VERSION 5.8 ;
BUSBITCHARS "[]" ;
DIVIDERCHAR "/" ;
UNITS
    DATABASE MICRONS 1000 ;
END UNITS

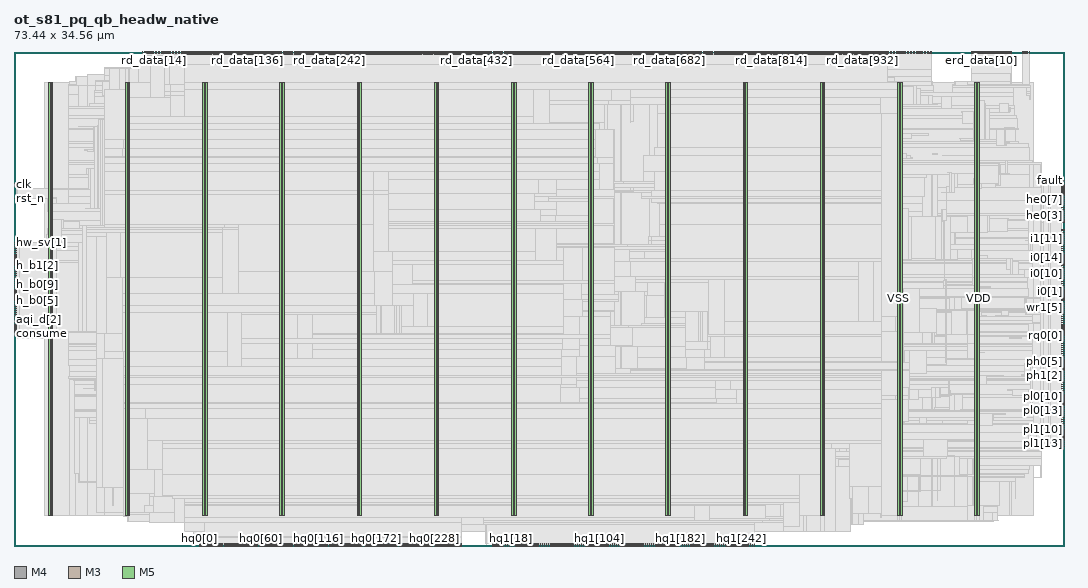
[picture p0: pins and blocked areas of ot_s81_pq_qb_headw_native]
MACRO ot_s81_pq_qb_headw_native
  FOREIGN ot_s81_pq_qb_headw_native 0 0 ;
  CLASS BLOCK ;
  SIZE 73.44 BY 34.56 ;
  PIN aqi_d[0]
    DIRECTION INPUT ;
    USE SIGNAL ;
    PORT
      LAYER M4 ;
        RECT  0 15.024 0.192 15.048 ;
    END
  END aqi_d[0]
  PIN aqi_d[1]
    DIRECTION INPUT ;
    USE SIGNAL ;
    PORT
      LAYER M4 ;
        RECT  0 15.168 0.192 15.192 ;
    END
  END aqi_d[1]
  PIN aqi_d[2]
    DIRECTION INPUT ;
    USE SIGNAL ;
    PORT
      LAYER M4 ;
        RECT  0 15.312 0.192 15.336 ;
    END
  END aqi_d[2]
  PIN aqi_d[3]
    DIRECTION INPUT ;
    USE SIGNAL ;
    PORT
      LAYER M4 ;
        RECT  0 15.456 0.192 15.48 ;
    END
  END aqi_d[3]
  PIN aqi_d[4]
    DIRECTION INPUT ;
    USE SIGNAL ;
    PORT
      LAYER M4 ;
        RECT  0 15.6 0.192 15.624 ;
    END
  END aqi_d[4]
  PIN aqi_d[5]
    DIRECTION INPUT ;
    USE SIGNAL ;
    PORT
      LAYER M4 ;
        RECT  0 15.744 0.192 15.768 ;
    END
  END aqi_d[5]
  PIN aqi_d[6]
    DIRECTION INPUT ;
    USE SIGNAL ;
    PORT
      LAYER M4 ;
        RECT  0 15.888 0.192 15.912 ;
    END
  END aqi_d[6]
  PIN aqi_d[7]
    DIRECTION INPUT ;
    USE SIGNAL ;
    PORT
      LAYER M4 ;
        RECT  0 16.032 0.192 16.056 ;
    END
  END aqi_d[7]
  PIN aqi_d[8]
    DIRECTION INPUT ;
    USE SIGNAL ;
    PORT
      LAYER M4 ;
        RECT  0 16.176 0.192 16.2 ;
    END
  END aqi_d[8]
  PIN aqi_d[9]
    DIRECTION INPUT ;
    USE SIGNAL ;
    PORT
      LAYER M4 ;
        RECT  0 16.32 0.192 16.344 ;
    END
  END aqi_d[9]
  PIN bfault[0]
    DIRECTION INPUT ;
    USE SIGNAL ;
    PORT
      LAYER M3 ;
        RECT  70.56 34.416 70.578 34.56 ;
    END
  END bfault[0]
  PIN bfault[1]
    DIRECTION INPUT ;
    USE SIGNAL ;
    PORT
      LAYER M3 ;
        RECT  70.704 34.416 70.722 34.56 ;
    END
  END bfault[1]
  PIN bfault[2]
    DIRECTION INPUT ;
    USE SIGNAL ;
    PORT
      LAYER M3 ;
        RECT  70.848 34.416 70.866 34.56 ;
    END
  END bfault[2]
  PIN bfault[3]
    DIRECTION INPUT ;
    USE SIGNAL ;
    PORT
      LAYER M3 ;
        RECT  70.992 34.416 71.01 34.56 ;
    END
  END bfault[3]
  PIN clk
    DIRECTION INPUT ;
    USE SIGNAL ;
    PORT
      LAYER M4 ;
        RECT  0 25.296 0.192 25.32 ;
    END
    PORT
      LAYER M4 ;
        RECT  0.156 25.296 0.181 25.32 ;
    END
  END clk
  PIN consume
    DIRECTION INPUT ;
    USE SIGNAL ;
    PORT
      LAYER M4 ;
        RECT  0 14.88 0.192 14.904 ;
    END
  END consume
  PIN erd_data[0]
    DIRECTION INPUT ;
    USE SIGNAL ;
    PORT
      LAYER M3 ;
        RECT  66.96 34.416 66.978 34.56 ;
    END
  END erd_data[0]
  PIN erd_data[10]
    DIRECTION INPUT ;
    USE SIGNAL ;
    PORT
      LAYER M3 ;
        RECT  67.68 34.416 67.698 34.56 ;
    END
  END erd_data[10]
  PIN erd_data[11]
    DIRECTION INPUT ;
    USE SIGNAL ;
    PORT
      LAYER M3 ;
        RECT  67.752 34.416 67.77 34.56 ;
    END
  END erd_data[11]
  PIN erd_data[12]
    DIRECTION INPUT ;
    USE SIGNAL ;
    PORT
      LAYER M3 ;
        RECT  67.824 34.416 67.842 34.56 ;
    END
  END erd_data[12]
  PIN erd_data[13]
    DIRECTION INPUT ;
    USE SIGNAL ;
    PORT
      LAYER M3 ;
        RECT  67.896 34.416 67.914 34.56 ;
    END
  END erd_data[13]
  PIN erd_data[14]
    DIRECTION INPUT ;
    USE SIGNAL ;
    PORT
      LAYER M3 ;
        RECT  67.968 34.416 67.986 34.56 ;
    END
  END erd_data[14]
  PIN erd_data[15]
    DIRECTION INPUT ;
    USE SIGNAL ;
    PORT
      LAYER M3 ;
        RECT  68.04 34.416 68.058 34.56 ;
    END
  END erd_data[15]
  PIN erd_data[16]
    DIRECTION INPUT ;
    USE SIGNAL ;
    PORT
      LAYER M3 ;
        RECT  68.112 34.416 68.13 34.56 ;
    END
  END erd_data[16]
  PIN erd_data[17]
    DIRECTION INPUT ;
    USE SIGNAL ;
    PORT
      LAYER M3 ;
        RECT  68.184 34.416 68.202 34.56 ;
    END
  END erd_data[17]
  PIN erd_data[18]
    DIRECTION INPUT ;
    USE SIGNAL ;
    PORT
      LAYER M3 ;
        RECT  68.256 34.416 68.274 34.56 ;
    END
  END erd_data[18]
  PIN erd_data[19]
    DIRECTION INPUT ;
    USE SIGNAL ;
    PORT
      LAYER M3 ;
        RECT  68.328 34.416 68.346 34.56 ;
    END
  END erd_data[19]
  PIN erd_data[1]
    DIRECTION INPUT ;
    USE SIGNAL ;
    PORT
      LAYER M3 ;
        RECT  67.032 34.416 67.05 34.56 ;
    END
  END erd_data[1]
  PIN erd_data[20]
    DIRECTION INPUT ;
    USE SIGNAL ;
    PORT
      LAYER M3 ;
        RECT  68.4 34.416 68.418 34.56 ;
    END
  END erd_data[20]
  PIN erd_data[21]
    DIRECTION INPUT ;
    USE SIGNAL ;
    PORT
      LAYER M3 ;
        RECT  68.472 34.416 68.49 34.56 ;
    END
  END erd_data[21]
  PIN erd_data[22]
    DIRECTION INPUT ;
    USE SIGNAL ;
    PORT
      LAYER M3 ;
        RECT  68.544 34.416 68.562 34.56 ;
    END
  END erd_data[22]
  PIN erd_data[23]
    DIRECTION INPUT ;
    USE SIGNAL ;
    PORT
      LAYER M3 ;
        RECT  68.616 34.416 68.634 34.56 ;
    END
  END erd_data[23]
  PIN erd_data[24]
    DIRECTION INPUT ;
    USE SIGNAL ;
    PORT
      LAYER M3 ;
        RECT  68.688 34.416 68.706 34.56 ;
    END
  END erd_data[24]
  PIN erd_data[25]
    DIRECTION INPUT ;
    USE SIGNAL ;
    PORT
      LAYER M3 ;
        RECT  68.76 34.416 68.778 34.56 ;
    END
  END erd_data[25]
  PIN erd_data[26]
    DIRECTION INPUT ;
    USE SIGNAL ;
    PORT
      LAYER M3 ;
        RECT  68.832 34.416 68.85 34.56 ;
    END
  END erd_data[26]
  PIN erd_data[27]
    DIRECTION INPUT ;
    USE SIGNAL ;
    PORT
      LAYER M3 ;
        RECT  68.904 34.416 68.922 34.56 ;
    END
  END erd_data[27]
  PIN erd_data[28]
    DIRECTION INPUT ;
    USE SIGNAL ;
    PORT
      LAYER M3 ;
        RECT  68.976 34.416 68.994 34.56 ;
    END
  END erd_data[28]
  PIN erd_data[29]
    DIRECTION INPUT ;
    USE SIGNAL ;
    PORT
      LAYER M3 ;
        RECT  69.048 34.416 69.066 34.56 ;
    END
  END erd_data[29]
  PIN erd_data[2]
    DIRECTION INPUT ;
    USE SIGNAL ;
    PORT
      LAYER M3 ;
        RECT  67.104 34.416 67.122 34.56 ;
    END
  END erd_data[2]
  PIN erd_data[30]
    DIRECTION INPUT ;
    USE SIGNAL ;
    PORT
      LAYER M3 ;
        RECT  69.12 34.416 69.138 34.56 ;
    END
  END erd_data[30]
  PIN erd_data[31]
    DIRECTION INPUT ;
    USE SIGNAL ;
    PORT
      LAYER M3 ;
        RECT  69.192 34.416 69.21 34.56 ;
    END
  END erd_data[31]
  PIN erd_data[32]
    DIRECTION INPUT ;
    USE SIGNAL ;
    PORT
      LAYER M3 ;
        RECT  69.264 34.416 69.282 34.56 ;
    END
  END erd_data[32]
  PIN erd_data[33]
    DIRECTION INPUT ;
    USE SIGNAL ;
    PORT
      LAYER M3 ;
        RECT  69.336 34.416 69.354 34.56 ;
    END
  END erd_data[33]
  PIN erd_data[34]
    DIRECTION INPUT ;
    USE SIGNAL ;
    PORT
      LAYER M3 ;
        RECT  69.408 34.416 69.426 34.56 ;
    END
  END erd_data[34]
  PIN erd_data[35]
    DIRECTION INPUT ;
    USE SIGNAL ;
    PORT
      LAYER M3 ;
        RECT  69.48 34.416 69.498 34.56 ;
    END
  END erd_data[35]
  PIN erd_data[36]
    DIRECTION INPUT ;
    USE SIGNAL ;
    PORT
      LAYER M3 ;
        RECT  69.552 34.416 69.57 34.56 ;
    END
  END erd_data[36]
  PIN erd_data[37]
    DIRECTION INPUT ;
    USE SIGNAL ;
    PORT
      LAYER M3 ;
        RECT  69.624 34.416 69.642 34.56 ;
    END
  END erd_data[37]
  PIN erd_data[38]
    DIRECTION INPUT ;
    USE SIGNAL ;
    PORT
      LAYER M3 ;
        RECT  69.696 34.416 69.714 34.56 ;
    END
    PORT
      LAYER M3 ;
        RECT  69.66 34.428 69.75 34.493 ;
    END
  END erd_data[38]
  PIN erd_data[39]
    DIRECTION INPUT ;
    USE SIGNAL ;
    PORT
      LAYER M3 ;
        RECT  69.768 34.416 69.786 34.56 ;
    END
  END erd_data[39]
  PIN erd_data[3]
    DIRECTION INPUT ;
    USE SIGNAL ;
    PORT
      LAYER M3 ;
        RECT  67.176 34.416 67.194 34.56 ;
    END
  END erd_data[3]
  PIN erd_data[4]
    DIRECTION INPUT ;
    USE SIGNAL ;
    PORT
      LAYER M3 ;
        RECT  67.248 34.416 67.266 34.56 ;
    END
  END erd_data[4]
  PIN erd_data[5]
    DIRECTION INPUT ;
    USE SIGNAL ;
    PORT
      LAYER M3 ;
        RECT  67.32 34.416 67.338 34.56 ;
    END
  END erd_data[5]
  PIN erd_data[6]
    DIRECTION INPUT ;
    USE SIGNAL ;
    PORT
      LAYER M3 ;
        RECT  67.392 34.416 67.41 34.56 ;
    END
  END erd_data[6]
  PIN erd_data[7]
    DIRECTION INPUT ;
    USE SIGNAL ;
    PORT
      LAYER M3 ;
        RECT  67.464 34.416 67.482 34.56 ;
    END
  END erd_data[7]
  PIN erd_data[8]
    DIRECTION INPUT ;
    USE SIGNAL ;
    PORT
      LAYER M3 ;
        RECT  67.536 34.416 67.554 34.56 ;
    END
  END erd_data[8]
  PIN erd_data[9]
    DIRECTION INPUT ;
    USE SIGNAL ;
    PORT
      LAYER M3 ;
        RECT  67.608 34.416 67.626 34.56 ;
    END
  END erd_data[9]
  PIN fault
    DIRECTION OUTPUT ;
    USE SIGNAL ;
    PORT
      LAYER M4 ;
        RECT  73.248 25.536 73.44 25.56 ;
    END
  END fault
  PIN h_b0[0]
    DIRECTION INPUT ;
    USE SIGNAL ;
    PORT
      LAYER M4 ;
        RECT  0 16.464 0.192 16.488 ;
    END
  END h_b0[0]
  PIN h_b0[10]
    DIRECTION INPUT ;
    USE SIGNAL ;
    PORT
      LAYER M4 ;
        RECT  0 17.904 0.192 17.928 ;
    END
  END h_b0[10]
  PIN h_b0[11]
    DIRECTION INPUT ;
    USE SIGNAL ;
    PORT
      LAYER M4 ;
        RECT  0 18.048 0.192 18.072 ;
    END
  END h_b0[11]
  PIN h_b0[12]
    DIRECTION INPUT ;
    USE SIGNAL ;
    PORT
      LAYER M4 ;
        RECT  0 18.192 0.192 18.216 ;
    END
  END h_b0[12]
  PIN h_b0[13]
    DIRECTION INPUT ;
    USE SIGNAL ;
    PORT
      LAYER M4 ;
        RECT  0 18.336 0.192 18.36 ;
    END
  END h_b0[13]
  PIN h_b0[14]
    DIRECTION INPUT ;
    USE SIGNAL ;
    PORT
      LAYER M4 ;
        RECT  0 18.48 0.192 18.504 ;
    END
  END h_b0[14]
  PIN h_b0[15]
    DIRECTION INPUT ;
    USE SIGNAL ;
    PORT
      LAYER M4 ;
        RECT  0 18.624 0.192 18.648 ;
    END
  END h_b0[15]
  PIN h_b0[1]
    DIRECTION INPUT ;
    USE SIGNAL ;
    PORT
      LAYER M4 ;
        RECT  0 16.608 0.192 16.632 ;
    END
  END h_b0[1]
  PIN h_b0[2]
    DIRECTION INPUT ;
    USE SIGNAL ;
    PORT
      LAYER M4 ;
        RECT  0 16.752 0.192 16.776 ;
    END
  END h_b0[2]
  PIN h_b0[3]
    DIRECTION INPUT ;
    USE SIGNAL ;
    PORT
      LAYER M4 ;
        RECT  0 16.896 0.192 16.92 ;
    END
  END h_b0[3]
  PIN h_b0[4]
    DIRECTION INPUT ;
    USE SIGNAL ;
    PORT
      LAYER M4 ;
        RECT  0 17.04 0.192 17.064 ;
    END
  END h_b0[4]
  PIN h_b0[5]
    DIRECTION INPUT ;
    USE SIGNAL ;
    PORT
      LAYER M4 ;
        RECT  0 17.184 0.192 17.208 ;
    END
  END h_b0[5]
  PIN h_b0[6]
    DIRECTION INPUT ;
    USE SIGNAL ;
    PORT
      LAYER M4 ;
        RECT  0 17.328 0.192 17.352 ;
    END
  END h_b0[6]
  PIN h_b0[7]
    DIRECTION INPUT ;
    USE SIGNAL ;
    PORT
      LAYER M4 ;
        RECT  0 17.472 0.192 17.496 ;
    END
  END h_b0[7]
  PIN h_b0[8]
    DIRECTION INPUT ;
    USE SIGNAL ;
    PORT
      LAYER M4 ;
        RECT  0 17.616 0.192 17.64 ;
    END
  END h_b0[8]
  PIN h_b0[9]
    DIRECTION INPUT ;
    USE SIGNAL ;
    PORT
      LAYER M4 ;
        RECT  0 17.76 0.192 17.784 ;
    END
  END h_b0[9]
  PIN h_b1[0]
    DIRECTION INPUT ;
    USE SIGNAL ;
    PORT
      LAYER M4 ;
        RECT  0 18.768 0.192 18.792 ;
    END
  END h_b1[0]
  PIN h_b1[10]
    DIRECTION INPUT ;
    USE SIGNAL ;
    PORT
      LAYER M4 ;
        RECT  0 20.208 0.192 20.232 ;
    END
  END h_b1[10]
  PIN h_b1[11]
    DIRECTION INPUT ;
    USE SIGNAL ;
    PORT
      LAYER M4 ;
        RECT  0 20.352 0.192 20.376 ;
    END
  END h_b1[11]
  PIN h_b1[12]
    DIRECTION INPUT ;
    USE SIGNAL ;
    PORT
      LAYER M4 ;
        RECT  0 20.496 0.192 20.52 ;
    END
  END h_b1[12]
  PIN h_b1[13]
    DIRECTION INPUT ;
    USE SIGNAL ;
    PORT
      LAYER M4 ;
        RECT  0 20.64 0.192 20.664 ;
    END
  END h_b1[13]
  PIN h_b1[14]
    DIRECTION INPUT ;
    USE SIGNAL ;
    PORT
      LAYER M4 ;
        RECT  0 20.784 0.192 20.808 ;
    END
  END h_b1[14]
  PIN h_b1[15]
    DIRECTION INPUT ;
    USE SIGNAL ;
    PORT
      LAYER M4 ;
        RECT  0 20.928 0.192 20.952 ;
    END
  END h_b1[15]
  PIN h_b1[1]
    DIRECTION INPUT ;
    USE SIGNAL ;
    PORT
      LAYER M4 ;
        RECT  0 18.912 0.192 18.936 ;
    END
  END h_b1[1]
  PIN h_b1[2]
    DIRECTION INPUT ;
    USE SIGNAL ;
    PORT
      LAYER M4 ;
        RECT  0 19.056 0.192 19.08 ;
    END
  END h_b1[2]
  PIN h_b1[3]
    DIRECTION INPUT ;
    USE SIGNAL ;
    PORT
      LAYER M4 ;
        RECT  0 19.2 0.192 19.224 ;
    END
  END h_b1[3]
  PIN h_b1[4]
    DIRECTION INPUT ;
    USE SIGNAL ;
    PORT
      LAYER M4 ;
        RECT  0 19.344 0.192 19.368 ;
    END
  END h_b1[4]
  PIN h_b1[5]
    DIRECTION INPUT ;
    USE SIGNAL ;
    PORT
      LAYER M4 ;
        RECT  0 19.488 0.192 19.512 ;
    END
  END h_b1[5]
  PIN h_b1[6]
    DIRECTION INPUT ;
    USE SIGNAL ;
    PORT
      LAYER M4 ;
        RECT  0 19.632 0.192 19.656 ;
    END
  END h_b1[6]
  PIN h_b1[7]
    DIRECTION INPUT ;
    USE SIGNAL ;
    PORT
      LAYER M4 ;
        RECT  0 19.776 0.192 19.8 ;
    END
  END h_b1[7]
  PIN h_b1[8]
    DIRECTION INPUT ;
    USE SIGNAL ;
    PORT
      LAYER M4 ;
        RECT  0 19.92 0.192 19.944 ;
    END
  END h_b1[8]
  PIN h_b1[9]
    DIRECTION INPUT ;
    USE SIGNAL ;
    PORT
      LAYER M4 ;
        RECT  0 20.064 0.192 20.088 ;
    END
  END h_b1[9]
  PIN he0[0]
    DIRECTION OUTPUT ;
    USE SIGNAL ;
    PORT
      LAYER M4 ;
        RECT  73.248 22.656 73.44 22.68 ;
    END
  END he0[0]
  PIN he0[1]
    DIRECTION OUTPUT ;
    USE SIGNAL ;
    PORT
      LAYER M4 ;
        RECT  73.248 22.8 73.44 22.824 ;
    END
  END he0[1]
  PIN he0[2]
    DIRECTION OUTPUT ;
    USE SIGNAL ;
    PORT
      LAYER M4 ;
        RECT  73.248 22.944 73.44 22.968 ;
    END
  END he0[2]
  PIN he0[3]
    DIRECTION OUTPUT ;
    USE SIGNAL ;
    PORT
      LAYER M4 ;
        RECT  73.248 23.088 73.44 23.112 ;
    END
  END he0[3]
  PIN he0[4]
    DIRECTION OUTPUT ;
    USE SIGNAL ;
    PORT
      LAYER M4 ;
        RECT  73.248 23.232 73.44 23.256 ;
    END
  END he0[4]
  PIN he0[5]
    DIRECTION OUTPUT ;
    USE SIGNAL ;
    PORT
      LAYER M4 ;
        RECT  73.248 23.376 73.44 23.4 ;
    END
  END he0[5]
  PIN he0[6]
    DIRECTION OUTPUT ;
    USE SIGNAL ;
    PORT
      LAYER M4 ;
        RECT  73.248 23.52 73.44 23.544 ;
    END
  END he0[6]
  PIN he0[7]
    DIRECTION OUTPUT ;
    USE SIGNAL ;
    PORT
      LAYER M4 ;
        RECT  73.248 23.664 73.44 23.688 ;
    END
  END he0[7]
  PIN he0[8]
    DIRECTION OUTPUT ;
    USE SIGNAL ;
    PORT
      LAYER M4 ;
        RECT  73.248 23.808 73.44 23.832 ;
    END
  END he0[8]
  PIN he0[9]
    DIRECTION OUTPUT ;
    USE SIGNAL ;
    PORT
      LAYER M4 ;
        RECT  73.248 23.952 73.44 23.976 ;
    END
  END he0[9]
  PIN he1[0]
    DIRECTION OUTPUT ;
    USE SIGNAL ;
    PORT
      LAYER M4 ;
        RECT  73.248 24.096 73.44 24.12 ;
    END
  END he1[0]
  PIN he1[1]
    DIRECTION OUTPUT ;
    USE SIGNAL ;
    PORT
      LAYER M4 ;
        RECT  73.248 24.24 73.44 24.264 ;
    END
  END he1[1]
  PIN he1[2]
    DIRECTION OUTPUT ;
    USE SIGNAL ;
    PORT
      LAYER M4 ;
        RECT  73.248 24.384 73.44 24.408 ;
    END
  END he1[2]
  PIN he1[3]
    DIRECTION OUTPUT ;
    USE SIGNAL ;
    PORT
      LAYER M4 ;
        RECT  73.248 24.528 73.44 24.552 ;
    END
  END he1[3]
  PIN he1[4]
    DIRECTION OUTPUT ;
    USE SIGNAL ;
    PORT
      LAYER M4 ;
        RECT  73.248 24.672 73.44 24.696 ;
    END
  END he1[4]
  PIN he1[5]
    DIRECTION OUTPUT ;
    USE SIGNAL ;
    PORT
      LAYER M4 ;
        RECT  73.248 24.816 73.44 24.84 ;
    END
  END he1[5]
  PIN he1[6]
    DIRECTION OUTPUT ;
    USE SIGNAL ;
    PORT
      LAYER M4 ;
        RECT  73.248 24.96 73.44 24.984 ;
    END
  END he1[6]
  PIN he1[7]
    DIRECTION OUTPUT ;
    USE SIGNAL ;
    PORT
      LAYER M4 ;
        RECT  73.248 25.104 73.44 25.128 ;
    END
  END he1[7]
  PIN he1[8]
    DIRECTION OUTPUT ;
    USE SIGNAL ;
    PORT
      LAYER M4 ;
        RECT  73.248 25.248 73.44 25.272 ;
    END
  END he1[8]
  PIN he1[9]
    DIRECTION OUTPUT ;
    USE SIGNAL ;
    PORT
      LAYER M4 ;
        RECT  73.248 25.392 73.44 25.416 ;
    END
  END he1[9]
  PIN hq0[0]
    DIRECTION OUTPUT ;
    USE SIGNAL ;
    PORT
      LAYER M3 ;
        RECT  12.96 0 12.978 0.144 ;
    END
  END hq0[0]
  PIN hq0[100]
    DIRECTION OUTPUT ;
    USE SIGNAL ;
    PORT
      LAYER M3 ;
        RECT  20.16 0 20.178 0.144 ;
    END
  END hq0[100]
  PIN hq0[101]
    DIRECTION OUTPUT ;
    USE SIGNAL ;
    PORT
      LAYER M5 ;
        RECT  20.208 0 20.232 0.192 ;
    END
  END hq0[101]
  PIN hq0[102]
    DIRECTION OUTPUT ;
    USE SIGNAL ;
    PORT
      LAYER M3 ;
        RECT  20.304 0 20.322 0.144 ;
    END
  END hq0[102]
  PIN hq0[103]
    DIRECTION OUTPUT ;
    USE SIGNAL ;
    PORT
      LAYER M5 ;
        RECT  20.352 0 20.376 0.192 ;
    END
  END hq0[103]
  PIN hq0[104]
    DIRECTION OUTPUT ;
    USE SIGNAL ;
    PORT
      LAYER M3 ;
        RECT  20.448 0 20.466 0.144 ;
    END
  END hq0[104]
  PIN hq0[105]
    DIRECTION OUTPUT ;
    USE SIGNAL ;
    PORT
      LAYER M5 ;
        RECT  20.496 0 20.52 0.192 ;
    END
  END hq0[105]
  PIN hq0[106]
    DIRECTION OUTPUT ;
    USE SIGNAL ;
    PORT
      LAYER M3 ;
        RECT  20.592 0 20.61 0.144 ;
    END
  END hq0[106]
  PIN hq0[107]
    DIRECTION OUTPUT ;
    USE SIGNAL ;
    PORT
      LAYER M5 ;
        RECT  20.64 0 20.664 0.192 ;
    END
  END hq0[107]
  PIN hq0[108]
    DIRECTION OUTPUT ;
    USE SIGNAL ;
    PORT
      LAYER M3 ;
        RECT  20.736 0 20.754 0.144 ;
    END
  END hq0[108]
  PIN hq0[109]
    DIRECTION OUTPUT ;
    USE SIGNAL ;
    PORT
      LAYER M5 ;
        RECT  20.784 0 20.808 0.192 ;
    END
  END hq0[109]
  PIN hq0[10]
    DIRECTION OUTPUT ;
    USE SIGNAL ;
    PORT
      LAYER M3 ;
        RECT  13.68 0 13.698 0.144 ;
    END
  END hq0[10]
  PIN hq0[110]
    DIRECTION OUTPUT ;
    USE SIGNAL ;
    PORT
      LAYER M3 ;
        RECT  20.88 0 20.898 0.144 ;
    END
  END hq0[110]
  PIN hq0[111]
    DIRECTION OUTPUT ;
    USE SIGNAL ;
    PORT
      LAYER M5 ;
        RECT  20.928 0 20.952 0.192 ;
    END
  END hq0[111]
  PIN hq0[112]
    DIRECTION OUTPUT ;
    USE SIGNAL ;
    PORT
      LAYER M3 ;
        RECT  21.024 0 21.042 0.144 ;
    END
  END hq0[112]
  PIN hq0[113]
    DIRECTION OUTPUT ;
    USE SIGNAL ;
    PORT
      LAYER M5 ;
        RECT  21.072 0 21.096 0.192 ;
    END
  END hq0[113]
  PIN hq0[114]
    DIRECTION OUTPUT ;
    USE SIGNAL ;
    PORT
      LAYER M3 ;
        RECT  21.168 0 21.186 0.144 ;
    END
  END hq0[114]
  PIN hq0[115]
    DIRECTION OUTPUT ;
    USE SIGNAL ;
    PORT
      LAYER M5 ;
        RECT  21.216 0 21.24 0.192 ;
    END
  END hq0[115]
  PIN hq0[116]
    DIRECTION OUTPUT ;
    USE SIGNAL ;
    PORT
      LAYER M3 ;
        RECT  21.312 0 21.33 0.144 ;
    END
  END hq0[116]
  PIN hq0[117]
    DIRECTION OUTPUT ;
    USE SIGNAL ;
    PORT
      LAYER M5 ;
        RECT  21.36 0 21.384 0.192 ;
    END
  END hq0[117]
  PIN hq0[118]
    DIRECTION OUTPUT ;
    USE SIGNAL ;
    PORT
      LAYER M3 ;
        RECT  21.456 0 21.474 0.144 ;
    END
  END hq0[118]
  PIN hq0[119]
    DIRECTION OUTPUT ;
    USE SIGNAL ;
    PORT
      LAYER M5 ;
        RECT  21.504 0 21.528 0.192 ;
    END
  END hq0[119]
  PIN hq0[11]
    DIRECTION OUTPUT ;
    USE SIGNAL ;
    PORT
      LAYER M5 ;
        RECT  13.728 0 13.752 0.192 ;
    END
  END hq0[11]
  PIN hq0[120]
    DIRECTION OUTPUT ;
    USE SIGNAL ;
    PORT
      LAYER M3 ;
        RECT  21.6 0 21.618 0.144 ;
    END
  END hq0[120]
  PIN hq0[121]
    DIRECTION OUTPUT ;
    USE SIGNAL ;
    PORT
      LAYER M5 ;
        RECT  21.648 0 21.672 0.192 ;
    END
  END hq0[121]
  PIN hq0[122]
    DIRECTION OUTPUT ;
    USE SIGNAL ;
    PORT
      LAYER M3 ;
        RECT  21.744 0 21.762 0.144 ;
    END
  END hq0[122]
  PIN hq0[123]
    DIRECTION OUTPUT ;
    USE SIGNAL ;
    PORT
      LAYER M5 ;
        RECT  21.792 0 21.816 0.192 ;
    END
  END hq0[123]
  PIN hq0[124]
    DIRECTION OUTPUT ;
    USE SIGNAL ;
    PORT
      LAYER M3 ;
        RECT  21.888 0 21.906 0.144 ;
    END
  END hq0[124]
  PIN hq0[125]
    DIRECTION OUTPUT ;
    USE SIGNAL ;
    PORT
      LAYER M5 ;
        RECT  21.936 0 21.96 0.192 ;
    END
  END hq0[125]
  PIN hq0[126]
    DIRECTION OUTPUT ;
    USE SIGNAL ;
    PORT
      LAYER M3 ;
        RECT  22.032 0 22.05 0.144 ;
    END
  END hq0[126]
  PIN hq0[127]
    DIRECTION OUTPUT ;
    USE SIGNAL ;
    PORT
      LAYER M5 ;
        RECT  22.08 0 22.104 0.192 ;
    END
  END hq0[127]
  PIN hq0[128]
    DIRECTION OUTPUT ;
    USE SIGNAL ;
    PORT
      LAYER M3 ;
        RECT  22.176 0 22.194 0.144 ;
    END
  END hq0[128]
  PIN hq0[129]
    DIRECTION OUTPUT ;
    USE SIGNAL ;
    PORT
      LAYER M5 ;
        RECT  22.224 0 22.248 0.192 ;
    END
  END hq0[129]
  PIN hq0[12]
    DIRECTION OUTPUT ;
    USE SIGNAL ;
    PORT
      LAYER M3 ;
        RECT  13.824 0 13.842 0.144 ;
    END
  END hq0[12]
  PIN hq0[130]
    DIRECTION OUTPUT ;
    USE SIGNAL ;
    PORT
      LAYER M3 ;
        RECT  22.32 0 22.338 0.144 ;
    END
  END hq0[130]
  PIN hq0[131]
    DIRECTION OUTPUT ;
    USE SIGNAL ;
    PORT
      LAYER M5 ;
        RECT  22.368 0 22.392 0.192 ;
    END
  END hq0[131]
  PIN hq0[132]
    DIRECTION OUTPUT ;
    USE SIGNAL ;
    PORT
      LAYER M3 ;
        RECT  22.464 0 22.482 0.144 ;
    END
  END hq0[132]
  PIN hq0[133]
    DIRECTION OUTPUT ;
    USE SIGNAL ;
    PORT
      LAYER M5 ;
        RECT  22.512 0 22.536 0.192 ;
    END
  END hq0[133]
  PIN hq0[134]
    DIRECTION OUTPUT ;
    USE SIGNAL ;
    PORT
      LAYER M3 ;
        RECT  22.608 0 22.626 0.144 ;
    END
  END hq0[134]
  PIN hq0[135]
    DIRECTION OUTPUT ;
    USE SIGNAL ;
    PORT
      LAYER M5 ;
        RECT  22.656 0 22.68 0.192 ;
    END
  END hq0[135]
  PIN hq0[136]
    DIRECTION OUTPUT ;
    USE SIGNAL ;
    PORT
      LAYER M3 ;
        RECT  22.752 0 22.77 0.144 ;
    END
  END hq0[136]
  PIN hq0[137]
    DIRECTION OUTPUT ;
    USE SIGNAL ;
    PORT
      LAYER M5 ;
        RECT  22.8 0 22.824 0.192 ;
    END
  END hq0[137]
  PIN hq0[138]
    DIRECTION OUTPUT ;
    USE SIGNAL ;
    PORT
      LAYER M3 ;
        RECT  22.896 0 22.914 0.144 ;
    END
  END hq0[138]
  PIN hq0[139]
    DIRECTION OUTPUT ;
    USE SIGNAL ;
    PORT
      LAYER M5 ;
        RECT  22.944 0 22.968 0.192 ;
    END
  END hq0[139]
  PIN hq0[13]
    DIRECTION OUTPUT ;
    USE SIGNAL ;
    PORT
      LAYER M5 ;
        RECT  13.872 0 13.896 0.192 ;
    END
  END hq0[13]
  PIN hq0[140]
    DIRECTION OUTPUT ;
    USE SIGNAL ;
    PORT
      LAYER M3 ;
        RECT  23.04 0 23.058 0.144 ;
    END
  END hq0[140]
  PIN hq0[141]
    DIRECTION OUTPUT ;
    USE SIGNAL ;
    PORT
      LAYER M5 ;
        RECT  23.088 0 23.112 0.192 ;
    END
  END hq0[141]
  PIN hq0[142]
    DIRECTION OUTPUT ;
    USE SIGNAL ;
    PORT
      LAYER M3 ;
        RECT  23.184 0 23.202 0.144 ;
    END
  END hq0[142]
  PIN hq0[143]
    DIRECTION OUTPUT ;
    USE SIGNAL ;
    PORT
      LAYER M5 ;
        RECT  23.232 0 23.256 0.192 ;
    END
  END hq0[143]
  PIN hq0[144]
    DIRECTION OUTPUT ;
    USE SIGNAL ;
    PORT
      LAYER M3 ;
        RECT  23.328 0 23.346 0.144 ;
    END
  END hq0[144]
  PIN hq0[145]
    DIRECTION OUTPUT ;
    USE SIGNAL ;
    PORT
      LAYER M5 ;
        RECT  23.376 0 23.4 0.192 ;
    END
  END hq0[145]
  PIN hq0[146]
    DIRECTION OUTPUT ;
    USE SIGNAL ;
    PORT
      LAYER M3 ;
        RECT  23.472 0 23.49 0.144 ;
    END
  END hq0[146]
  PIN hq0[147]
    DIRECTION OUTPUT ;
    USE SIGNAL ;
    PORT
      LAYER M5 ;
        RECT  23.52 0 23.544 0.192 ;
    END
  END hq0[147]
  PIN hq0[148]
    DIRECTION OUTPUT ;
    USE SIGNAL ;
    PORT
      LAYER M3 ;
        RECT  23.616 0 23.634 0.144 ;
    END
  END hq0[148]
  PIN hq0[149]
    DIRECTION OUTPUT ;
    USE SIGNAL ;
    PORT
      LAYER M5 ;
        RECT  23.664 0 23.688 0.192 ;
    END
  END hq0[149]
  PIN hq0[14]
    DIRECTION OUTPUT ;
    USE SIGNAL ;
    PORT
      LAYER M3 ;
        RECT  13.968 0 13.986 0.144 ;
    END
  END hq0[14]
  PIN hq0[150]
    DIRECTION OUTPUT ;
    USE SIGNAL ;
    PORT
      LAYER M3 ;
        RECT  23.76 0 23.778 0.144 ;
    END
  END hq0[150]
  PIN hq0[151]
    DIRECTION OUTPUT ;
    USE SIGNAL ;
    PORT
      LAYER M5 ;
        RECT  23.808 0 23.832 0.192 ;
    END
  END hq0[151]
  PIN hq0[152]
    DIRECTION OUTPUT ;
    USE SIGNAL ;
    PORT
      LAYER M3 ;
        RECT  23.904 0 23.922 0.144 ;
    END
  END hq0[152]
  PIN hq0[153]
    DIRECTION OUTPUT ;
    USE SIGNAL ;
    PORT
      LAYER M5 ;
        RECT  23.952 0 23.976 0.192 ;
    END
  END hq0[153]
  PIN hq0[154]
    DIRECTION OUTPUT ;
    USE SIGNAL ;
    PORT
      LAYER M3 ;
        RECT  24.048 0 24.066 0.144 ;
    END
  END hq0[154]
  PIN hq0[155]
    DIRECTION OUTPUT ;
    USE SIGNAL ;
    PORT
      LAYER M5 ;
        RECT  24.096 0 24.12 0.192 ;
    END
  END hq0[155]
  PIN hq0[156]
    DIRECTION OUTPUT ;
    USE SIGNAL ;
    PORT
      LAYER M3 ;
        RECT  24.192 0 24.21 0.144 ;
    END
  END hq0[156]
  PIN hq0[157]
    DIRECTION OUTPUT ;
    USE SIGNAL ;
    PORT
      LAYER M5 ;
        RECT  24.24 0 24.264 0.192 ;
    END
  END hq0[157]
  PIN hq0[158]
    DIRECTION OUTPUT ;
    USE SIGNAL ;
    PORT
      LAYER M3 ;
        RECT  24.336 0 24.354 0.144 ;
    END
  END hq0[158]
  PIN hq0[159]
    DIRECTION OUTPUT ;
    USE SIGNAL ;
    PORT
      LAYER M5 ;
        RECT  24.384 0 24.408 0.192 ;
    END
  END hq0[159]
  PIN hq0[15]
    DIRECTION OUTPUT ;
    USE SIGNAL ;
    PORT
      LAYER M5 ;
        RECT  14.016 0 14.04 0.192 ;
    END
  END hq0[15]
  PIN hq0[160]
    DIRECTION OUTPUT ;
    USE SIGNAL ;
    PORT
      LAYER M3 ;
        RECT  24.48 0 24.498 0.144 ;
    END
  END hq0[160]
  PIN hq0[161]
    DIRECTION OUTPUT ;
    USE SIGNAL ;
    PORT
      LAYER M5 ;
        RECT  24.528 0 24.552 0.192 ;
    END
  END hq0[161]
  PIN hq0[162]
    DIRECTION OUTPUT ;
    USE SIGNAL ;
    PORT
      LAYER M3 ;
        RECT  24.624 0 24.642 0.144 ;
    END
  END hq0[162]
  PIN hq0[163]
    DIRECTION OUTPUT ;
    USE SIGNAL ;
    PORT
      LAYER M5 ;
        RECT  24.672 0 24.696 0.192 ;
    END
  END hq0[163]
  PIN hq0[164]
    DIRECTION OUTPUT ;
    USE SIGNAL ;
    PORT
      LAYER M3 ;
        RECT  24.768 0 24.786 0.144 ;
    END
  END hq0[164]
  PIN hq0[165]
    DIRECTION OUTPUT ;
    USE SIGNAL ;
    PORT
      LAYER M5 ;
        RECT  24.816 0 24.84 0.192 ;
    END
  END hq0[165]
  PIN hq0[166]
    DIRECTION OUTPUT ;
    USE SIGNAL ;
    PORT
      LAYER M3 ;
        RECT  24.912 0 24.93 0.144 ;
    END
  END hq0[166]
  PIN hq0[167]
    DIRECTION OUTPUT ;
    USE SIGNAL ;
    PORT
      LAYER M5 ;
        RECT  24.96 0 24.984 0.192 ;
    END
  END hq0[167]
  PIN hq0[168]
    DIRECTION OUTPUT ;
    USE SIGNAL ;
    PORT
      LAYER M3 ;
        RECT  25.056 0 25.074 0.144 ;
    END
  END hq0[168]
  PIN hq0[169]
    DIRECTION OUTPUT ;
    USE SIGNAL ;
    PORT
      LAYER M5 ;
        RECT  25.104 0 25.128 0.192 ;
    END
  END hq0[169]
  PIN hq0[16]
    DIRECTION OUTPUT ;
    USE SIGNAL ;
    PORT
      LAYER M3 ;
        RECT  14.112 0 14.13 0.144 ;
    END
  END hq0[16]
  PIN hq0[170]
    DIRECTION OUTPUT ;
    USE SIGNAL ;
    PORT
      LAYER M3 ;
        RECT  25.2 0 25.218 0.144 ;
    END
  END hq0[170]
  PIN hq0[171]
    DIRECTION OUTPUT ;
    USE SIGNAL ;
    PORT
      LAYER M5 ;
        RECT  25.248 0 25.272 0.192 ;
    END
  END hq0[171]
  PIN hq0[172]
    DIRECTION OUTPUT ;
    USE SIGNAL ;
    PORT
      LAYER M3 ;
        RECT  25.344 0 25.362 0.144 ;
    END
  END hq0[172]
  PIN hq0[173]
    DIRECTION OUTPUT ;
    USE SIGNAL ;
    PORT
      LAYER M5 ;
        RECT  25.392 0 25.416 0.192 ;
    END
  END hq0[173]
  PIN hq0[174]
    DIRECTION OUTPUT ;
    USE SIGNAL ;
    PORT
      LAYER M3 ;
        RECT  25.488 0 25.506 0.144 ;
    END
  END hq0[174]
  PIN hq0[175]
    DIRECTION OUTPUT ;
    USE SIGNAL ;
    PORT
      LAYER M5 ;
        RECT  25.536 0 25.56 0.192 ;
    END
  END hq0[175]
  PIN hq0[176]
    DIRECTION OUTPUT ;
    USE SIGNAL ;
    PORT
      LAYER M3 ;
        RECT  25.632 0 25.65 0.144 ;
    END
  END hq0[176]
  PIN hq0[177]
    DIRECTION OUTPUT ;
    USE SIGNAL ;
    PORT
      LAYER M5 ;
        RECT  25.68 0 25.704 0.192 ;
    END
  END hq0[177]
  PIN hq0[178]
    DIRECTION OUTPUT ;
    USE SIGNAL ;
    PORT
      LAYER M3 ;
        RECT  25.776 0 25.794 0.144 ;
    END
  END hq0[178]
  PIN hq0[179]
    DIRECTION OUTPUT ;
    USE SIGNAL ;
    PORT
      LAYER M5 ;
        RECT  25.824 0 25.848 0.192 ;
    END
  END hq0[179]
  PIN hq0[17]
    DIRECTION OUTPUT ;
    USE SIGNAL ;
    PORT
      LAYER M5 ;
        RECT  14.16 0 14.184 0.192 ;
    END
  END hq0[17]
  PIN hq0[180]
    DIRECTION OUTPUT ;
    USE SIGNAL ;
    PORT
      LAYER M3 ;
        RECT  25.92 0 25.938 0.144 ;
    END
  END hq0[180]
  PIN hq0[181]
    DIRECTION OUTPUT ;
    USE SIGNAL ;
    PORT
      LAYER M5 ;
        RECT  25.968 0 25.992 0.192 ;
    END
  END hq0[181]
  PIN hq0[182]
    DIRECTION OUTPUT ;
    USE SIGNAL ;
    PORT
      LAYER M3 ;
        RECT  26.064 0 26.082 0.144 ;
    END
  END hq0[182]
  PIN hq0[183]
    DIRECTION OUTPUT ;
    USE SIGNAL ;
    PORT
      LAYER M5 ;
        RECT  26.112 0 26.136 0.192 ;
    END
  END hq0[183]
  PIN hq0[184]
    DIRECTION OUTPUT ;
    USE SIGNAL ;
    PORT
      LAYER M3 ;
        RECT  26.208 0 26.226 0.144 ;
    END
  END hq0[184]
  PIN hq0[185]
    DIRECTION OUTPUT ;
    USE SIGNAL ;
    PORT
      LAYER M5 ;
        RECT  26.256 0 26.28 0.192 ;
    END
  END hq0[185]
  PIN hq0[186]
    DIRECTION OUTPUT ;
    USE SIGNAL ;
    PORT
      LAYER M3 ;
        RECT  26.352 0 26.37 0.144 ;
    END
  END hq0[186]
  PIN hq0[187]
    DIRECTION OUTPUT ;
    USE SIGNAL ;
    PORT
      LAYER M5 ;
        RECT  26.4 0 26.424 0.192 ;
    END
  END hq0[187]
  PIN hq0[188]
    DIRECTION OUTPUT ;
    USE SIGNAL ;
    PORT
      LAYER M3 ;
        RECT  26.496 0 26.514 0.144 ;
    END
  END hq0[188]
  PIN hq0[189]
    DIRECTION OUTPUT ;
    USE SIGNAL ;
    PORT
      LAYER M5 ;
        RECT  26.544 0 26.568 0.192 ;
    END
  END hq0[189]
  PIN hq0[18]
    DIRECTION OUTPUT ;
    USE SIGNAL ;
    PORT
      LAYER M3 ;
        RECT  14.256 0 14.274 0.144 ;
    END
  END hq0[18]
  PIN hq0[190]
    DIRECTION OUTPUT ;
    USE SIGNAL ;
    PORT
      LAYER M3 ;
        RECT  26.64 0 26.658 0.144 ;
    END
  END hq0[190]
  PIN hq0[191]
    DIRECTION OUTPUT ;
    USE SIGNAL ;
    PORT
      LAYER M5 ;
        RECT  26.688 0 26.712 0.192 ;
    END
  END hq0[191]
  PIN hq0[192]
    DIRECTION OUTPUT ;
    USE SIGNAL ;
    PORT
      LAYER M3 ;
        RECT  26.784 0 26.802 0.144 ;
    END
  END hq0[192]
  PIN hq0[193]
    DIRECTION OUTPUT ;
    USE SIGNAL ;
    PORT
      LAYER M5 ;
        RECT  26.832 0 26.856 0.192 ;
    END
  END hq0[193]
  PIN hq0[194]
    DIRECTION OUTPUT ;
    USE SIGNAL ;
    PORT
      LAYER M3 ;
        RECT  26.928 0 26.946 0.144 ;
    END
  END hq0[194]
  PIN hq0[195]
    DIRECTION OUTPUT ;
    USE SIGNAL ;
    PORT
      LAYER M5 ;
        RECT  26.976 0 27 0.192 ;
    END
  END hq0[195]
  PIN hq0[196]
    DIRECTION OUTPUT ;
    USE SIGNAL ;
    PORT
      LAYER M3 ;
        RECT  27.072 0 27.09 0.144 ;
    END
  END hq0[196]
  PIN hq0[197]
    DIRECTION OUTPUT ;
    USE SIGNAL ;
    PORT
      LAYER M5 ;
        RECT  27.12 0 27.144 0.192 ;
    END
  END hq0[197]
  PIN hq0[198]
    DIRECTION OUTPUT ;
    USE SIGNAL ;
    PORT
      LAYER M3 ;
        RECT  27.216 0 27.234 0.144 ;
    END
  END hq0[198]
  PIN hq0[199]
    DIRECTION OUTPUT ;
    USE SIGNAL ;
    PORT
      LAYER M5 ;
        RECT  27.264 0 27.288 0.192 ;
    END
  END hq0[199]
  PIN hq0[19]
    DIRECTION OUTPUT ;
    USE SIGNAL ;
    PORT
      LAYER M5 ;
        RECT  14.304 0 14.328 0.192 ;
    END
  END hq0[19]
  PIN hq0[1]
    DIRECTION OUTPUT ;
    USE SIGNAL ;
    PORT
      LAYER M5 ;
        RECT  13.008 0 13.032 0.192 ;
    END
  END hq0[1]
  PIN hq0[200]
    DIRECTION OUTPUT ;
    USE SIGNAL ;
    PORT
      LAYER M3 ;
        RECT  27.36 0 27.378 0.144 ;
    END
  END hq0[200]
  PIN hq0[201]
    DIRECTION OUTPUT ;
    USE SIGNAL ;
    PORT
      LAYER M5 ;
        RECT  27.408 0 27.432 0.192 ;
    END
  END hq0[201]
  PIN hq0[202]
    DIRECTION OUTPUT ;
    USE SIGNAL ;
    PORT
      LAYER M3 ;
        RECT  27.504 0 27.522 0.144 ;
    END
  END hq0[202]
  PIN hq0[203]
    DIRECTION OUTPUT ;
    USE SIGNAL ;
    PORT
      LAYER M5 ;
        RECT  27.552 0 27.576 0.192 ;
    END
  END hq0[203]
  PIN hq0[204]
    DIRECTION OUTPUT ;
    USE SIGNAL ;
    PORT
      LAYER M3 ;
        RECT  27.648 0 27.666 0.144 ;
    END
  END hq0[204]
  PIN hq0[205]
    DIRECTION OUTPUT ;
    USE SIGNAL ;
    PORT
      LAYER M5 ;
        RECT  27.696 0 27.72 0.192 ;
    END
  END hq0[205]
  PIN hq0[206]
    DIRECTION OUTPUT ;
    USE SIGNAL ;
    PORT
      LAYER M3 ;
        RECT  27.792 0 27.81 0.144 ;
    END
  END hq0[206]
  PIN hq0[207]
    DIRECTION OUTPUT ;
    USE SIGNAL ;
    PORT
      LAYER M5 ;
        RECT  27.84 0 27.864 0.192 ;
    END
  END hq0[207]
  PIN hq0[208]
    DIRECTION OUTPUT ;
    USE SIGNAL ;
    PORT
      LAYER M3 ;
        RECT  27.936 0 27.954 0.144 ;
    END
  END hq0[208]
  PIN hq0[209]
    DIRECTION OUTPUT ;
    USE SIGNAL ;
    PORT
      LAYER M5 ;
        RECT  27.984 0 28.008 0.192 ;
    END
  END hq0[209]
  PIN hq0[20]
    DIRECTION OUTPUT ;
    USE SIGNAL ;
    PORT
      LAYER M3 ;
        RECT  14.4 0 14.418 0.144 ;
    END
  END hq0[20]
  PIN hq0[210]
    DIRECTION OUTPUT ;
    USE SIGNAL ;
    PORT
      LAYER M3 ;
        RECT  28.08 0 28.098 0.144 ;
    END
  END hq0[210]
  PIN hq0[211]
    DIRECTION OUTPUT ;
    USE SIGNAL ;
    PORT
      LAYER M5 ;
        RECT  28.128 0 28.152 0.192 ;
    END
  END hq0[211]
  PIN hq0[212]
    DIRECTION OUTPUT ;
    USE SIGNAL ;
    PORT
      LAYER M3 ;
        RECT  28.224 0 28.242 0.144 ;
    END
  END hq0[212]
  PIN hq0[213]
    DIRECTION OUTPUT ;
    USE SIGNAL ;
    PORT
      LAYER M5 ;
        RECT  28.272 0 28.296 0.192 ;
    END
  END hq0[213]
  PIN hq0[214]
    DIRECTION OUTPUT ;
    USE SIGNAL ;
    PORT
      LAYER M3 ;
        RECT  28.368 0 28.386 0.144 ;
    END
  END hq0[214]
  PIN hq0[215]
    DIRECTION OUTPUT ;
    USE SIGNAL ;
    PORT
      LAYER M5 ;
        RECT  28.416 0 28.44 0.192 ;
    END
  END hq0[215]
  PIN hq0[216]
    DIRECTION OUTPUT ;
    USE SIGNAL ;
    PORT
      LAYER M3 ;
        RECT  28.512 0 28.53 0.144 ;
    END
  END hq0[216]
  PIN hq0[217]
    DIRECTION OUTPUT ;
    USE SIGNAL ;
    PORT
      LAYER M5 ;
        RECT  28.56 0 28.584 0.192 ;
    END
  END hq0[217]
  PIN hq0[218]
    DIRECTION OUTPUT ;
    USE SIGNAL ;
    PORT
      LAYER M3 ;
        RECT  28.656 0 28.674 0.144 ;
    END
  END hq0[218]
  PIN hq0[219]
    DIRECTION OUTPUT ;
    USE SIGNAL ;
    PORT
      LAYER M5 ;
        RECT  28.704 0 28.728 0.192 ;
    END
  END hq0[219]
  PIN hq0[21]
    DIRECTION OUTPUT ;
    USE SIGNAL ;
    PORT
      LAYER M5 ;
        RECT  14.448 0 14.472 0.192 ;
    END
  END hq0[21]
  PIN hq0[220]
    DIRECTION OUTPUT ;
    USE SIGNAL ;
    PORT
      LAYER M3 ;
        RECT  28.8 0 28.818 0.144 ;
    END
  END hq0[220]
  PIN hq0[221]
    DIRECTION OUTPUT ;
    USE SIGNAL ;
    PORT
      LAYER M5 ;
        RECT  28.848 0 28.872 0.192 ;
    END
  END hq0[221]
  PIN hq0[222]
    DIRECTION OUTPUT ;
    USE SIGNAL ;
    PORT
      LAYER M3 ;
        RECT  28.944 0 28.962 0.144 ;
    END
  END hq0[222]
  PIN hq0[223]
    DIRECTION OUTPUT ;
    USE SIGNAL ;
    PORT
      LAYER M5 ;
        RECT  28.992 0 29.016 0.192 ;
    END
  END hq0[223]
  PIN hq0[224]
    DIRECTION OUTPUT ;
    USE SIGNAL ;
    PORT
      LAYER M3 ;
        RECT  29.088 0 29.106 0.144 ;
    END
  END hq0[224]
  PIN hq0[225]
    DIRECTION OUTPUT ;
    USE SIGNAL ;
    PORT
      LAYER M5 ;
        RECT  29.136 0 29.16 0.192 ;
    END
  END hq0[225]
  PIN hq0[226]
    DIRECTION OUTPUT ;
    USE SIGNAL ;
    PORT
      LAYER M3 ;
        RECT  29.232 0 29.25 0.144 ;
    END
  END hq0[226]
  PIN hq0[227]
    DIRECTION OUTPUT ;
    USE SIGNAL ;
    PORT
      LAYER M5 ;
        RECT  29.28 0 29.304 0.192 ;
    END
  END hq0[227]
  PIN hq0[228]
    DIRECTION OUTPUT ;
    USE SIGNAL ;
    PORT
      LAYER M3 ;
        RECT  29.376 0 29.394 0.144 ;
    END
  END hq0[228]
  PIN hq0[229]
    DIRECTION OUTPUT ;
    USE SIGNAL ;
    PORT
      LAYER M5 ;
        RECT  29.424 0 29.448 0.192 ;
    END
  END hq0[229]
  PIN hq0[22]
    DIRECTION OUTPUT ;
    USE SIGNAL ;
    PORT
      LAYER M3 ;
        RECT  14.544 0 14.562 0.144 ;
    END
  END hq0[22]
  PIN hq0[230]
    DIRECTION OUTPUT ;
    USE SIGNAL ;
    PORT
      LAYER M3 ;
        RECT  29.52 0 29.538 0.144 ;
    END
  END hq0[230]
  PIN hq0[231]
    DIRECTION OUTPUT ;
    USE SIGNAL ;
    PORT
      LAYER M5 ;
        RECT  29.568 0 29.592 0.192 ;
    END
  END hq0[231]
  PIN hq0[232]
    DIRECTION OUTPUT ;
    USE SIGNAL ;
    PORT
      LAYER M3 ;
        RECT  29.664 0 29.682 0.144 ;
    END
  END hq0[232]
  PIN hq0[233]
    DIRECTION OUTPUT ;
    USE SIGNAL ;
    PORT
      LAYER M5 ;
        RECT  29.712 0 29.736 0.192 ;
    END
  END hq0[233]
  PIN hq0[234]
    DIRECTION OUTPUT ;
    USE SIGNAL ;
    PORT
      LAYER M3 ;
        RECT  29.808 0 29.826 0.144 ;
    END
  END hq0[234]
  PIN hq0[235]
    DIRECTION OUTPUT ;
    USE SIGNAL ;
    PORT
      LAYER M5 ;
        RECT  29.856 0 29.88 0.192 ;
    END
  END hq0[235]
  PIN hq0[236]
    DIRECTION OUTPUT ;
    USE SIGNAL ;
    PORT
      LAYER M3 ;
        RECT  29.952 0 29.97 0.144 ;
    END
  END hq0[236]
  PIN hq0[237]
    DIRECTION OUTPUT ;
    USE SIGNAL ;
    PORT
      LAYER M5 ;
        RECT  30 0 30.024 0.192 ;
    END
  END hq0[237]
  PIN hq0[238]
    DIRECTION OUTPUT ;
    USE SIGNAL ;
    PORT
      LAYER M3 ;
        RECT  30.096 0 30.114 0.144 ;
    END
  END hq0[238]
  PIN hq0[239]
    DIRECTION OUTPUT ;
    USE SIGNAL ;
    PORT
      LAYER M5 ;
        RECT  30.144 0 30.168 0.192 ;
    END
  END hq0[239]
  PIN hq0[23]
    DIRECTION OUTPUT ;
    USE SIGNAL ;
    PORT
      LAYER M5 ;
        RECT  14.592 0 14.616 0.192 ;
    END
  END hq0[23]
  PIN hq0[240]
    DIRECTION OUTPUT ;
    USE SIGNAL ;
    PORT
      LAYER M3 ;
        RECT  30.24 0 30.258 0.144 ;
    END
  END hq0[240]
  PIN hq0[241]
    DIRECTION OUTPUT ;
    USE SIGNAL ;
    PORT
      LAYER M5 ;
        RECT  30.288 0 30.312 0.192 ;
    END
  END hq0[241]
  PIN hq0[242]
    DIRECTION OUTPUT ;
    USE SIGNAL ;
    PORT
      LAYER M3 ;
        RECT  30.384 0 30.402 0.144 ;
    END
  END hq0[242]
  PIN hq0[243]
    DIRECTION OUTPUT ;
    USE SIGNAL ;
    PORT
      LAYER M5 ;
        RECT  30.432 0 30.456 0.192 ;
    END
  END hq0[243]
  PIN hq0[244]
    DIRECTION OUTPUT ;
    USE SIGNAL ;
    PORT
      LAYER M3 ;
        RECT  30.528 0 30.546 0.144 ;
    END
  END hq0[244]
  PIN hq0[245]
    DIRECTION OUTPUT ;
    USE SIGNAL ;
    PORT
      LAYER M5 ;
        RECT  30.576 0 30.6 0.192 ;
    END
  END hq0[245]
  PIN hq0[246]
    DIRECTION OUTPUT ;
    USE SIGNAL ;
    PORT
      LAYER M3 ;
        RECT  30.672 0 30.69 0.144 ;
    END
  END hq0[246]
  PIN hq0[247]
    DIRECTION OUTPUT ;
    USE SIGNAL ;
    PORT
      LAYER M5 ;
        RECT  30.72 0 30.744 0.192 ;
    END
  END hq0[247]
  PIN hq0[248]
    DIRECTION OUTPUT ;
    USE SIGNAL ;
    PORT
      LAYER M3 ;
        RECT  30.816 0 30.834 0.144 ;
    END
  END hq0[248]
  PIN hq0[249]
    DIRECTION OUTPUT ;
    USE SIGNAL ;
    PORT
      LAYER M5 ;
        RECT  30.864 0 30.888 0.192 ;
    END
  END hq0[249]
  PIN hq0[24]
    DIRECTION OUTPUT ;
    USE SIGNAL ;
    PORT
      LAYER M3 ;
        RECT  14.688 0 14.706 0.144 ;
    END
  END hq0[24]
  PIN hq0[250]
    DIRECTION OUTPUT ;
    USE SIGNAL ;
    PORT
      LAYER M3 ;
        RECT  30.96 0 30.978 0.144 ;
    END
  END hq0[250]
  PIN hq0[251]
    DIRECTION OUTPUT ;
    USE SIGNAL ;
    PORT
      LAYER M5 ;
        RECT  31.008 0 31.032 0.192 ;
    END
  END hq0[251]
  PIN hq0[252]
    DIRECTION OUTPUT ;
    USE SIGNAL ;
    PORT
      LAYER M3 ;
        RECT  31.104 0 31.122 0.144 ;
    END
  END hq0[252]
  PIN hq0[253]
    DIRECTION OUTPUT ;
    USE SIGNAL ;
    PORT
      LAYER M5 ;
        RECT  31.152 0 31.176 0.192 ;
    END
  END hq0[253]
  PIN hq0[254]
    DIRECTION OUTPUT ;
    USE SIGNAL ;
    PORT
      LAYER M3 ;
        RECT  31.248 0 31.266 0.144 ;
    END
  END hq0[254]
  PIN hq0[255]
    DIRECTION OUTPUT ;
    USE SIGNAL ;
    PORT
      LAYER M5 ;
        RECT  31.296 0 31.32 0.192 ;
    END
  END hq0[255]
  PIN hq0[25]
    DIRECTION OUTPUT ;
    USE SIGNAL ;
    PORT
      LAYER M5 ;
        RECT  14.736 0 14.76 0.192 ;
    END
  END hq0[25]
  PIN hq0[26]
    DIRECTION OUTPUT ;
    USE SIGNAL ;
    PORT
      LAYER M3 ;
        RECT  14.832 0 14.85 0.144 ;
    END
  END hq0[26]
  PIN hq0[27]
    DIRECTION OUTPUT ;
    USE SIGNAL ;
    PORT
      LAYER M5 ;
        RECT  14.88 0 14.904 0.192 ;
    END
  END hq0[27]
  PIN hq0[28]
    DIRECTION OUTPUT ;
    USE SIGNAL ;
    PORT
      LAYER M3 ;
        RECT  14.976 0 14.994 0.144 ;
    END
  END hq0[28]
  PIN hq0[29]
    DIRECTION OUTPUT ;
    USE SIGNAL ;
    PORT
      LAYER M5 ;
        RECT  15.024 0 15.048 0.192 ;
    END
  END hq0[29]
  PIN hq0[2]
    DIRECTION OUTPUT ;
    USE SIGNAL ;
    PORT
      LAYER M3 ;
        RECT  13.104 0 13.122 0.144 ;
    END
  END hq0[2]
  PIN hq0[30]
    DIRECTION OUTPUT ;
    USE SIGNAL ;
    PORT
      LAYER M3 ;
        RECT  15.12 0 15.138 0.144 ;
    END
  END hq0[30]
  PIN hq0[31]
    DIRECTION OUTPUT ;
    USE SIGNAL ;
    PORT
      LAYER M5 ;
        RECT  15.168 0 15.192 0.192 ;
    END
  END hq0[31]
  PIN hq0[32]
    DIRECTION OUTPUT ;
    USE SIGNAL ;
    PORT
      LAYER M3 ;
        RECT  15.264 0 15.282 0.144 ;
    END
  END hq0[32]
  PIN hq0[33]
    DIRECTION OUTPUT ;
    USE SIGNAL ;
    PORT
      LAYER M5 ;
        RECT  15.312 0 15.336 0.192 ;
    END
  END hq0[33]
  PIN hq0[34]
    DIRECTION OUTPUT ;
    USE SIGNAL ;
    PORT
      LAYER M3 ;
        RECT  15.408 0 15.426 0.144 ;
    END
  END hq0[34]
  PIN hq0[35]
    DIRECTION OUTPUT ;
    USE SIGNAL ;
    PORT
      LAYER M5 ;
        RECT  15.456 0 15.48 0.192 ;
    END
  END hq0[35]
  PIN hq0[36]
    DIRECTION OUTPUT ;
    USE SIGNAL ;
    PORT
      LAYER M3 ;
        RECT  15.552 0 15.57 0.144 ;
    END
  END hq0[36]
  PIN hq0[37]
    DIRECTION OUTPUT ;
    USE SIGNAL ;
    PORT
      LAYER M5 ;
        RECT  15.6 0 15.624 0.192 ;
    END
  END hq0[37]
  PIN hq0[38]
    DIRECTION OUTPUT ;
    USE SIGNAL ;
    PORT
      LAYER M3 ;
        RECT  15.696 0 15.714 0.144 ;
    END
  END hq0[38]
  PIN hq0[39]
    DIRECTION OUTPUT ;
    USE SIGNAL ;
    PORT
      LAYER M5 ;
        RECT  15.744 0 15.768 0.192 ;
    END
  END hq0[39]
  PIN hq0[3]
    DIRECTION OUTPUT ;
    USE SIGNAL ;
    PORT
      LAYER M5 ;
        RECT  13.152 0 13.176 0.192 ;
    END
  END hq0[3]
  PIN hq0[40]
    DIRECTION OUTPUT ;
    USE SIGNAL ;
    PORT
      LAYER M3 ;
        RECT  15.84 0 15.858 0.144 ;
    END
  END hq0[40]
  PIN hq0[41]
    DIRECTION OUTPUT ;
    USE SIGNAL ;
    PORT
      LAYER M5 ;
        RECT  15.888 0 15.912 0.192 ;
    END
  END hq0[41]
  PIN hq0[42]
    DIRECTION OUTPUT ;
    USE SIGNAL ;
    PORT
      LAYER M3 ;
        RECT  15.984 0 16.002 0.144 ;
    END
  END hq0[42]
  PIN hq0[43]
    DIRECTION OUTPUT ;
    USE SIGNAL ;
    PORT
      LAYER M5 ;
        RECT  16.032 0 16.056 0.192 ;
    END
  END hq0[43]
  PIN hq0[44]
    DIRECTION OUTPUT ;
    USE SIGNAL ;
    PORT
      LAYER M3 ;
        RECT  16.128 0 16.146 0.144 ;
    END
  END hq0[44]
  PIN hq0[45]
    DIRECTION OUTPUT ;
    USE SIGNAL ;
    PORT
      LAYER M5 ;
        RECT  16.176 0 16.2 0.192 ;
    END
  END hq0[45]
  PIN hq0[46]
    DIRECTION OUTPUT ;
    USE SIGNAL ;
    PORT
      LAYER M3 ;
        RECT  16.272 0 16.29 0.144 ;
    END
  END hq0[46]
  PIN hq0[47]
    DIRECTION OUTPUT ;
    USE SIGNAL ;
    PORT
      LAYER M5 ;
        RECT  16.32 0 16.344 0.192 ;
    END
  END hq0[47]
  PIN hq0[48]
    DIRECTION OUTPUT ;
    USE SIGNAL ;
    PORT
      LAYER M3 ;
        RECT  16.416 0 16.434 0.144 ;
    END
  END hq0[48]
  PIN hq0[49]
    DIRECTION OUTPUT ;
    USE SIGNAL ;
    PORT
      LAYER M5 ;
        RECT  16.464 0 16.488 0.192 ;
    END
  END hq0[49]
  PIN hq0[4]
    DIRECTION OUTPUT ;
    USE SIGNAL ;
    PORT
      LAYER M3 ;
        RECT  13.248 0 13.266 0.144 ;
    END
  END hq0[4]
  PIN hq0[50]
    DIRECTION OUTPUT ;
    USE SIGNAL ;
    PORT
      LAYER M3 ;
        RECT  16.56 0 16.578 0.144 ;
    END
  END hq0[50]
  PIN hq0[51]
    DIRECTION OUTPUT ;
    USE SIGNAL ;
    PORT
      LAYER M5 ;
        RECT  16.608 0 16.632 0.192 ;
    END
  END hq0[51]
  PIN hq0[52]
    DIRECTION OUTPUT ;
    USE SIGNAL ;
    PORT
      LAYER M3 ;
        RECT  16.704 0 16.722 0.144 ;
    END
  END hq0[52]
  PIN hq0[53]
    DIRECTION OUTPUT ;
    USE SIGNAL ;
    PORT
      LAYER M5 ;
        RECT  16.752 0 16.776 0.192 ;
    END
  END hq0[53]
  PIN hq0[54]
    DIRECTION OUTPUT ;
    USE SIGNAL ;
    PORT
      LAYER M3 ;
        RECT  16.848 0 16.866 0.144 ;
    END
  END hq0[54]
  PIN hq0[55]
    DIRECTION OUTPUT ;
    USE SIGNAL ;
    PORT
      LAYER M5 ;
        RECT  16.896 0 16.92 0.192 ;
    END
  END hq0[55]
  PIN hq0[56]
    DIRECTION OUTPUT ;
    USE SIGNAL ;
    PORT
      LAYER M3 ;
        RECT  16.992 0 17.01 0.144 ;
    END
  END hq0[56]
  PIN hq0[57]
    DIRECTION OUTPUT ;
    USE SIGNAL ;
    PORT
      LAYER M5 ;
        RECT  17.04 0 17.064 0.192 ;
    END
  END hq0[57]
  PIN hq0[58]
    DIRECTION OUTPUT ;
    USE SIGNAL ;
    PORT
      LAYER M3 ;
        RECT  17.136 0 17.154 0.144 ;
    END
  END hq0[58]
  PIN hq0[59]
    DIRECTION OUTPUT ;
    USE SIGNAL ;
    PORT
      LAYER M5 ;
        RECT  17.184 0 17.208 0.192 ;
    END
  END hq0[59]
  PIN hq0[5]
    DIRECTION OUTPUT ;
    USE SIGNAL ;
    PORT
      LAYER M5 ;
        RECT  13.296 0 13.32 0.192 ;
    END
  END hq0[5]
  PIN hq0[60]
    DIRECTION OUTPUT ;
    USE SIGNAL ;
    PORT
      LAYER M3 ;
        RECT  17.28 0 17.298 0.144 ;
    END
  END hq0[60]
  PIN hq0[61]
    DIRECTION OUTPUT ;
    USE SIGNAL ;
    PORT
      LAYER M5 ;
        RECT  17.328 0 17.352 0.192 ;
    END
  END hq0[61]
  PIN hq0[62]
    DIRECTION OUTPUT ;
    USE SIGNAL ;
    PORT
      LAYER M3 ;
        RECT  17.424 0 17.442 0.144 ;
    END
  END hq0[62]
  PIN hq0[63]
    DIRECTION OUTPUT ;
    USE SIGNAL ;
    PORT
      LAYER M5 ;
        RECT  17.472 0 17.496 0.192 ;
    END
  END hq0[63]
  PIN hq0[64]
    DIRECTION OUTPUT ;
    USE SIGNAL ;
    PORT
      LAYER M3 ;
        RECT  17.568 0 17.586 0.144 ;
    END
  END hq0[64]
  PIN hq0[65]
    DIRECTION OUTPUT ;
    USE SIGNAL ;
    PORT
      LAYER M5 ;
        RECT  17.616 0 17.64 0.192 ;
    END
  END hq0[65]
  PIN hq0[66]
    DIRECTION OUTPUT ;
    USE SIGNAL ;
    PORT
      LAYER M3 ;
        RECT  17.712 0 17.73 0.144 ;
    END
  END hq0[66]
  PIN hq0[67]
    DIRECTION OUTPUT ;
    USE SIGNAL ;
    PORT
      LAYER M5 ;
        RECT  17.76 0 17.784 0.192 ;
    END
  END hq0[67]
  PIN hq0[68]
    DIRECTION OUTPUT ;
    USE SIGNAL ;
    PORT
      LAYER M3 ;
        RECT  17.856 0 17.874 0.144 ;
    END
  END hq0[68]
  PIN hq0[69]
    DIRECTION OUTPUT ;
    USE SIGNAL ;
    PORT
      LAYER M5 ;
        RECT  17.904 0 17.928 0.192 ;
    END
  END hq0[69]
  PIN hq0[6]
    DIRECTION OUTPUT ;
    USE SIGNAL ;
    PORT
      LAYER M3 ;
        RECT  13.392 0 13.41 0.144 ;
    END
  END hq0[6]
  PIN hq0[70]
    DIRECTION OUTPUT ;
    USE SIGNAL ;
    PORT
      LAYER M3 ;
        RECT  18 0 18.018 0.144 ;
    END
  END hq0[70]
  PIN hq0[71]
    DIRECTION OUTPUT ;
    USE SIGNAL ;
    PORT
      LAYER M5 ;
        RECT  18.048 0 18.072 0.192 ;
    END
  END hq0[71]
  PIN hq0[72]
    DIRECTION OUTPUT ;
    USE SIGNAL ;
    PORT
      LAYER M3 ;
        RECT  18.144 0 18.162 0.144 ;
    END
  END hq0[72]
  PIN hq0[73]
    DIRECTION OUTPUT ;
    USE SIGNAL ;
    PORT
      LAYER M5 ;
        RECT  18.192 0 18.216 0.192 ;
    END
  END hq0[73]
  PIN hq0[74]
    DIRECTION OUTPUT ;
    USE SIGNAL ;
    PORT
      LAYER M3 ;
        RECT  18.288 0 18.306 0.144 ;
    END
  END hq0[74]
  PIN hq0[75]
    DIRECTION OUTPUT ;
    USE SIGNAL ;
    PORT
      LAYER M5 ;
        RECT  18.336 0 18.36 0.192 ;
    END
  END hq0[75]
  PIN hq0[76]
    DIRECTION OUTPUT ;
    USE SIGNAL ;
    PORT
      LAYER M3 ;
        RECT  18.432 0 18.45 0.144 ;
    END
  END hq0[76]
  PIN hq0[77]
    DIRECTION OUTPUT ;
    USE SIGNAL ;
    PORT
      LAYER M5 ;
        RECT  18.48 0 18.504 0.192 ;
    END
  END hq0[77]
  PIN hq0[78]
    DIRECTION OUTPUT ;
    USE SIGNAL ;
    PORT
      LAYER M3 ;
        RECT  18.576 0 18.594 0.144 ;
    END
  END hq0[78]
  PIN hq0[79]
    DIRECTION OUTPUT ;
    USE SIGNAL ;
    PORT
      LAYER M5 ;
        RECT  18.624 0 18.648 0.192 ;
    END
  END hq0[79]
  PIN hq0[7]
    DIRECTION OUTPUT ;
    USE SIGNAL ;
    PORT
      LAYER M5 ;
        RECT  13.44 0 13.464 0.192 ;
    END
  END hq0[7]
  PIN hq0[80]
    DIRECTION OUTPUT ;
    USE SIGNAL ;
    PORT
      LAYER M3 ;
        RECT  18.72 0 18.738 0.144 ;
    END
  END hq0[80]
  PIN hq0[81]
    DIRECTION OUTPUT ;
    USE SIGNAL ;
    PORT
      LAYER M5 ;
        RECT  18.768 0 18.792 0.192 ;
    END
  END hq0[81]
  PIN hq0[82]
    DIRECTION OUTPUT ;
    USE SIGNAL ;
    PORT
      LAYER M3 ;
        RECT  18.864 0 18.882 0.144 ;
    END
  END hq0[82]
  PIN hq0[83]
    DIRECTION OUTPUT ;
    USE SIGNAL ;
    PORT
      LAYER M5 ;
        RECT  18.912 0 18.936 0.192 ;
    END
  END hq0[83]
  PIN hq0[84]
    DIRECTION OUTPUT ;
    USE SIGNAL ;
    PORT
      LAYER M3 ;
        RECT  19.008 0 19.026 0.144 ;
    END
  END hq0[84]
  PIN hq0[85]
    DIRECTION OUTPUT ;
    USE SIGNAL ;
    PORT
      LAYER M5 ;
        RECT  19.056 0 19.08 0.192 ;
    END
  END hq0[85]
  PIN hq0[86]
    DIRECTION OUTPUT ;
    USE SIGNAL ;
    PORT
      LAYER M3 ;
        RECT  19.152 0 19.17 0.144 ;
    END
  END hq0[86]
  PIN hq0[87]
    DIRECTION OUTPUT ;
    USE SIGNAL ;
    PORT
      LAYER M5 ;
        RECT  19.2 0 19.224 0.192 ;
    END
  END hq0[87]
  PIN hq0[88]
    DIRECTION OUTPUT ;
    USE SIGNAL ;
    PORT
      LAYER M3 ;
        RECT  19.296 0 19.314 0.144 ;
    END
  END hq0[88]
  PIN hq0[89]
    DIRECTION OUTPUT ;
    USE SIGNAL ;
    PORT
      LAYER M5 ;
        RECT  19.344 0 19.368 0.192 ;
    END
  END hq0[89]
  PIN hq0[8]
    DIRECTION OUTPUT ;
    USE SIGNAL ;
    PORT
      LAYER M3 ;
        RECT  13.536 0 13.554 0.144 ;
    END
  END hq0[8]
  PIN hq0[90]
    DIRECTION OUTPUT ;
    USE SIGNAL ;
    PORT
      LAYER M3 ;
        RECT  19.44 0 19.458 0.144 ;
    END
  END hq0[90]
  PIN hq0[91]
    DIRECTION OUTPUT ;
    USE SIGNAL ;
    PORT
      LAYER M5 ;
        RECT  19.488 0 19.512 0.192 ;
    END
  END hq0[91]
  PIN hq0[92]
    DIRECTION OUTPUT ;
    USE SIGNAL ;
    PORT
      LAYER M3 ;
        RECT  19.584 0 19.602 0.144 ;
    END
  END hq0[92]
  PIN hq0[93]
    DIRECTION OUTPUT ;
    USE SIGNAL ;
    PORT
      LAYER M5 ;
        RECT  19.632 0 19.656 0.192 ;
    END
  END hq0[93]
  PIN hq0[94]
    DIRECTION OUTPUT ;
    USE SIGNAL ;
    PORT
      LAYER M3 ;
        RECT  19.728 0 19.746 0.144 ;
    END
  END hq0[94]
  PIN hq0[95]
    DIRECTION OUTPUT ;
    USE SIGNAL ;
    PORT
      LAYER M5 ;
        RECT  19.776 0 19.8 0.192 ;
    END
  END hq0[95]
  PIN hq0[96]
    DIRECTION OUTPUT ;
    USE SIGNAL ;
    PORT
      LAYER M3 ;
        RECT  19.872 0 19.89 0.144 ;
    END
  END hq0[96]
  PIN hq0[97]
    DIRECTION OUTPUT ;
    USE SIGNAL ;
    PORT
      LAYER M5 ;
        RECT  19.92 0 19.944 0.192 ;
    END
  END hq0[97]
  PIN hq0[98]
    DIRECTION OUTPUT ;
    USE SIGNAL ;
    PORT
      LAYER M3 ;
        RECT  20.016 0 20.034 0.144 ;
    END
  END hq0[98]
  PIN hq0[99]
    DIRECTION OUTPUT ;
    USE SIGNAL ;
    PORT
      LAYER M5 ;
        RECT  20.064 0 20.088 0.192 ;
    END
  END hq0[99]
  PIN hq0[9]
    DIRECTION OUTPUT ;
    USE SIGNAL ;
    PORT
      LAYER M5 ;
        RECT  13.584 0 13.608 0.192 ;
    END
  END hq0[9]
  PIN hq1[0]
    DIRECTION OUTPUT ;
    USE SIGNAL ;
    PORT
      LAYER M3 ;
        RECT  33.48 0 33.498 0.144 ;
    END
  END hq1[0]
  PIN hq1[100]
    DIRECTION OUTPUT ;
    USE SIGNAL ;
    PORT
      LAYER M3 ;
        RECT  40.68 0 40.698 0.144 ;
    END
  END hq1[100]
  PIN hq1[101]
    DIRECTION OUTPUT ;
    USE SIGNAL ;
    PORT
      LAYER M5 ;
        RECT  40.704 0 40.728 0.192 ;
    END
  END hq1[101]
  PIN hq1[102]
    DIRECTION OUTPUT ;
    USE SIGNAL ;
    PORT
      LAYER M3 ;
        RECT  40.824 0 40.842 0.144 ;
    END
  END hq1[102]
  PIN hq1[103]
    DIRECTION OUTPUT ;
    USE SIGNAL ;
    PORT
      LAYER M5 ;
        RECT  40.848 0 40.872 0.192 ;
    END
  END hq1[103]
  PIN hq1[104]
    DIRECTION OUTPUT ;
    USE SIGNAL ;
    PORT
      LAYER M3 ;
        RECT  40.968 0 40.986 0.144 ;
    END
  END hq1[104]
  PIN hq1[105]
    DIRECTION OUTPUT ;
    USE SIGNAL ;
    PORT
      LAYER M5 ;
        RECT  40.992 0 41.016 0.192 ;
    END
  END hq1[105]
  PIN hq1[106]
    DIRECTION OUTPUT ;
    USE SIGNAL ;
    PORT
      LAYER M3 ;
        RECT  41.112 0 41.13 0.144 ;
    END
  END hq1[106]
  PIN hq1[107]
    DIRECTION OUTPUT ;
    USE SIGNAL ;
    PORT
      LAYER M5 ;
        RECT  41.136 0 41.16 0.192 ;
    END
  END hq1[107]
  PIN hq1[108]
    DIRECTION OUTPUT ;
    USE SIGNAL ;
    PORT
      LAYER M3 ;
        RECT  41.256 0 41.274 0.144 ;
    END
  END hq1[108]
  PIN hq1[109]
    DIRECTION OUTPUT ;
    USE SIGNAL ;
    PORT
      LAYER M5 ;
        RECT  41.28 0 41.304 0.192 ;
    END
  END hq1[109]
  PIN hq1[10]
    DIRECTION OUTPUT ;
    USE SIGNAL ;
    PORT
      LAYER M3 ;
        RECT  34.2 0 34.218 0.144 ;
    END
  END hq1[10]
  PIN hq1[110]
    DIRECTION OUTPUT ;
    USE SIGNAL ;
    PORT
      LAYER M3 ;
        RECT  41.4 0 41.418 0.144 ;
    END
  END hq1[110]
  PIN hq1[111]
    DIRECTION OUTPUT ;
    USE SIGNAL ;
    PORT
      LAYER M5 ;
        RECT  41.424 0 41.448 0.192 ;
    END
  END hq1[111]
  PIN hq1[112]
    DIRECTION OUTPUT ;
    USE SIGNAL ;
    PORT
      LAYER M3 ;
        RECT  41.544 0 41.562 0.144 ;
    END
  END hq1[112]
  PIN hq1[113]
    DIRECTION OUTPUT ;
    USE SIGNAL ;
    PORT
      LAYER M5 ;
        RECT  41.568 0 41.592 0.192 ;
    END
  END hq1[113]
  PIN hq1[114]
    DIRECTION OUTPUT ;
    USE SIGNAL ;
    PORT
      LAYER M3 ;
        RECT  41.688 0 41.706 0.144 ;
    END
  END hq1[114]
  PIN hq1[115]
    DIRECTION OUTPUT ;
    USE SIGNAL ;
    PORT
      LAYER M5 ;
        RECT  41.712 0 41.736 0.192 ;
    END
  END hq1[115]
  PIN hq1[116]
    DIRECTION OUTPUT ;
    USE SIGNAL ;
    PORT
      LAYER M3 ;
        RECT  41.832 0 41.85 0.144 ;
    END
  END hq1[116]
  PIN hq1[117]
    DIRECTION OUTPUT ;
    USE SIGNAL ;
    PORT
      LAYER M5 ;
        RECT  41.856 0 41.88 0.192 ;
    END
  END hq1[117]
  PIN hq1[118]
    DIRECTION OUTPUT ;
    USE SIGNAL ;
    PORT
      LAYER M3 ;
        RECT  41.976 0 41.994 0.144 ;
    END
  END hq1[118]
  PIN hq1[119]
    DIRECTION OUTPUT ;
    USE SIGNAL ;
    PORT
      LAYER M5 ;
        RECT  42 0 42.024 0.192 ;
    END
  END hq1[119]
  PIN hq1[11]
    DIRECTION OUTPUT ;
    USE SIGNAL ;
    PORT
      LAYER M5 ;
        RECT  34.224 0 34.248 0.192 ;
    END
  END hq1[11]
  PIN hq1[120]
    DIRECTION OUTPUT ;
    USE SIGNAL ;
    PORT
      LAYER M3 ;
        RECT  42.12 0 42.138 0.144 ;
    END
  END hq1[120]
  PIN hq1[121]
    DIRECTION OUTPUT ;
    USE SIGNAL ;
    PORT
      LAYER M5 ;
        RECT  42.144 0 42.168 0.192 ;
    END
  END hq1[121]
  PIN hq1[122]
    DIRECTION OUTPUT ;
    USE SIGNAL ;
    PORT
      LAYER M3 ;
        RECT  42.264 0 42.282 0.144 ;
    END
  END hq1[122]
  PIN hq1[123]
    DIRECTION OUTPUT ;
    USE SIGNAL ;
    PORT
      LAYER M5 ;
        RECT  42.288 0 42.312 0.192 ;
    END
  END hq1[123]
  PIN hq1[124]
    DIRECTION OUTPUT ;
    USE SIGNAL ;
    PORT
      LAYER M3 ;
        RECT  42.408 0 42.426 0.144 ;
    END
  END hq1[124]
  PIN hq1[125]
    DIRECTION OUTPUT ;
    USE SIGNAL ;
    PORT
      LAYER M5 ;
        RECT  42.432 0 42.456 0.192 ;
    END
  END hq1[125]
  PIN hq1[126]
    DIRECTION OUTPUT ;
    USE SIGNAL ;
    PORT
      LAYER M3 ;
        RECT  42.552 0 42.57 0.144 ;
    END
  END hq1[126]
  PIN hq1[127]
    DIRECTION OUTPUT ;
    USE SIGNAL ;
    PORT
      LAYER M5 ;
        RECT  42.576 0 42.6 0.192 ;
    END
  END hq1[127]
  PIN hq1[128]
    DIRECTION OUTPUT ;
    USE SIGNAL ;
    PORT
      LAYER M3 ;
        RECT  42.696 0 42.714 0.144 ;
    END
  END hq1[128]
  PIN hq1[129]
    DIRECTION OUTPUT ;
    USE SIGNAL ;
    PORT
      LAYER M5 ;
        RECT  42.72 0 42.744 0.192 ;
    END
  END hq1[129]
  PIN hq1[12]
    DIRECTION OUTPUT ;
    USE SIGNAL ;
    PORT
      LAYER M3 ;
        RECT  34.344 0 34.362 0.144 ;
    END
  END hq1[12]
  PIN hq1[130]
    DIRECTION OUTPUT ;
    USE SIGNAL ;
    PORT
      LAYER M3 ;
        RECT  42.84 0 42.858 0.144 ;
    END
  END hq1[130]
  PIN hq1[131]
    DIRECTION OUTPUT ;
    USE SIGNAL ;
    PORT
      LAYER M5 ;
        RECT  42.864 0 42.888 0.192 ;
    END
  END hq1[131]
  PIN hq1[132]
    DIRECTION OUTPUT ;
    USE SIGNAL ;
    PORT
      LAYER M3 ;
        RECT  42.984 0 43.002 0.144 ;
    END
  END hq1[132]
  PIN hq1[133]
    DIRECTION OUTPUT ;
    USE SIGNAL ;
    PORT
      LAYER M5 ;
        RECT  43.008 0 43.032 0.192 ;
    END
  END hq1[133]
  PIN hq1[134]
    DIRECTION OUTPUT ;
    USE SIGNAL ;
    PORT
      LAYER M3 ;
        RECT  43.128 0 43.146 0.144 ;
    END
  END hq1[134]
  PIN hq1[135]
    DIRECTION OUTPUT ;
    USE SIGNAL ;
    PORT
      LAYER M5 ;
        RECT  43.152 0 43.176 0.192 ;
    END
  END hq1[135]
  PIN hq1[136]
    DIRECTION OUTPUT ;
    USE SIGNAL ;
    PORT
      LAYER M3 ;
        RECT  43.272 0 43.29 0.144 ;
    END
  END hq1[136]
  PIN hq1[137]
    DIRECTION OUTPUT ;
    USE SIGNAL ;
    PORT
      LAYER M5 ;
        RECT  43.296 0 43.32 0.192 ;
    END
  END hq1[137]
  PIN hq1[138]
    DIRECTION OUTPUT ;
    USE SIGNAL ;
    PORT
      LAYER M3 ;
        RECT  43.416 0 43.434 0.144 ;
    END
  END hq1[138]
  PIN hq1[139]
    DIRECTION OUTPUT ;
    USE SIGNAL ;
    PORT
      LAYER M5 ;
        RECT  43.44 0 43.464 0.192 ;
    END
  END hq1[139]
  PIN hq1[13]
    DIRECTION OUTPUT ;
    USE SIGNAL ;
    PORT
      LAYER M5 ;
        RECT  34.368 0 34.392 0.192 ;
    END
  END hq1[13]
  PIN hq1[140]
    DIRECTION OUTPUT ;
    USE SIGNAL ;
    PORT
      LAYER M3 ;
        RECT  43.56 0 43.578 0.144 ;
    END
  END hq1[140]
  PIN hq1[141]
    DIRECTION OUTPUT ;
    USE SIGNAL ;
    PORT
      LAYER M5 ;
        RECT  43.584 0 43.608 0.192 ;
    END
  END hq1[141]
  PIN hq1[142]
    DIRECTION OUTPUT ;
    USE SIGNAL ;
    PORT
      LAYER M3 ;
        RECT  43.704 0 43.722 0.144 ;
    END
  END hq1[142]
  PIN hq1[143]
    DIRECTION OUTPUT ;
    USE SIGNAL ;
    PORT
      LAYER M5 ;
        RECT  43.728 0 43.752 0.192 ;
    END
  END hq1[143]
  PIN hq1[144]
    DIRECTION OUTPUT ;
    USE SIGNAL ;
    PORT
      LAYER M3 ;
        RECT  43.848 0 43.866 0.144 ;
    END
  END hq1[144]
  PIN hq1[145]
    DIRECTION OUTPUT ;
    USE SIGNAL ;
    PORT
      LAYER M5 ;
        RECT  43.872 0 43.896 0.192 ;
    END
  END hq1[145]
  PIN hq1[146]
    DIRECTION OUTPUT ;
    USE SIGNAL ;
    PORT
      LAYER M3 ;
        RECT  43.992 0 44.01 0.144 ;
    END
  END hq1[146]
  PIN hq1[147]
    DIRECTION OUTPUT ;
    USE SIGNAL ;
    PORT
      LAYER M5 ;
        RECT  44.016 0 44.04 0.192 ;
    END
  END hq1[147]
  PIN hq1[148]
    DIRECTION OUTPUT ;
    USE SIGNAL ;
    PORT
      LAYER M3 ;
        RECT  44.136 0 44.154 0.144 ;
    END
  END hq1[148]
  PIN hq1[149]
    DIRECTION OUTPUT ;
    USE SIGNAL ;
    PORT
      LAYER M5 ;
        RECT  44.16 0 44.184 0.192 ;
    END
  END hq1[149]
  PIN hq1[14]
    DIRECTION OUTPUT ;
    USE SIGNAL ;
    PORT
      LAYER M3 ;
        RECT  34.488 0 34.506 0.144 ;
    END
  END hq1[14]
  PIN hq1[150]
    DIRECTION OUTPUT ;
    USE SIGNAL ;
    PORT
      LAYER M3 ;
        RECT  44.28 0 44.298 0.144 ;
    END
  END hq1[150]
  PIN hq1[151]
    DIRECTION OUTPUT ;
    USE SIGNAL ;
    PORT
      LAYER M5 ;
        RECT  44.304 0 44.328 0.192 ;
    END
  END hq1[151]
  PIN hq1[152]
    DIRECTION OUTPUT ;
    USE SIGNAL ;
    PORT
      LAYER M3 ;
        RECT  44.424 0 44.442 0.144 ;
    END
  END hq1[152]
  PIN hq1[153]
    DIRECTION OUTPUT ;
    USE SIGNAL ;
    PORT
      LAYER M5 ;
        RECT  44.448 0 44.472 0.192 ;
    END
  END hq1[153]
  PIN hq1[154]
    DIRECTION OUTPUT ;
    USE SIGNAL ;
    PORT
      LAYER M3 ;
        RECT  44.568 0 44.586 0.144 ;
    END
  END hq1[154]
  PIN hq1[155]
    DIRECTION OUTPUT ;
    USE SIGNAL ;
    PORT
      LAYER M5 ;
        RECT  44.592 0 44.616 0.192 ;
    END
  END hq1[155]
  PIN hq1[156]
    DIRECTION OUTPUT ;
    USE SIGNAL ;
    PORT
      LAYER M3 ;
        RECT  44.712 0 44.73 0.144 ;
    END
  END hq1[156]
  PIN hq1[157]
    DIRECTION OUTPUT ;
    USE SIGNAL ;
    PORT
      LAYER M5 ;
        RECT  44.736 0 44.76 0.192 ;
    END
  END hq1[157]
  PIN hq1[158]
    DIRECTION OUTPUT ;
    USE SIGNAL ;
    PORT
      LAYER M3 ;
        RECT  44.856 0 44.874 0.144 ;
    END
  END hq1[158]
  PIN hq1[159]
    DIRECTION OUTPUT ;
    USE SIGNAL ;
    PORT
      LAYER M5 ;
        RECT  44.88 0 44.904 0.192 ;
    END
  END hq1[159]
  PIN hq1[15]
    DIRECTION OUTPUT ;
    USE SIGNAL ;
    PORT
      LAYER M5 ;
        RECT  34.512 0 34.536 0.192 ;
    END
  END hq1[15]
  PIN hq1[160]
    DIRECTION OUTPUT ;
    USE SIGNAL ;
    PORT
      LAYER M3 ;
        RECT  45 0 45.018 0.144 ;
    END
  END hq1[160]
  PIN hq1[161]
    DIRECTION OUTPUT ;
    USE SIGNAL ;
    PORT
      LAYER M5 ;
        RECT  45.024 0 45.048 0.192 ;
    END
  END hq1[161]
  PIN hq1[162]
    DIRECTION OUTPUT ;
    USE SIGNAL ;
    PORT
      LAYER M3 ;
        RECT  45.144 0 45.162 0.144 ;
    END
  END hq1[162]
  PIN hq1[163]
    DIRECTION OUTPUT ;
    USE SIGNAL ;
    PORT
      LAYER M5 ;
        RECT  45.168 0 45.192 0.192 ;
    END
  END hq1[163]
  PIN hq1[164]
    DIRECTION OUTPUT ;
    USE SIGNAL ;
    PORT
      LAYER M3 ;
        RECT  45.288 0 45.306 0.144 ;
    END
  END hq1[164]
  PIN hq1[165]
    DIRECTION OUTPUT ;
    USE SIGNAL ;
    PORT
      LAYER M5 ;
        RECT  45.312 0 45.336 0.192 ;
    END
  END hq1[165]
  PIN hq1[166]
    DIRECTION OUTPUT ;
    USE SIGNAL ;
    PORT
      LAYER M3 ;
        RECT  45.432 0 45.45 0.144 ;
    END
  END hq1[166]
  PIN hq1[167]
    DIRECTION OUTPUT ;
    USE SIGNAL ;
    PORT
      LAYER M5 ;
        RECT  45.456 0 45.48 0.192 ;
    END
  END hq1[167]
  PIN hq1[168]
    DIRECTION OUTPUT ;
    USE SIGNAL ;
    PORT
      LAYER M3 ;
        RECT  45.576 0 45.594 0.144 ;
    END
  END hq1[168]
  PIN hq1[169]
    DIRECTION OUTPUT ;
    USE SIGNAL ;
    PORT
      LAYER M5 ;
        RECT  45.6 0 45.624 0.192 ;
    END
  END hq1[169]
  PIN hq1[16]
    DIRECTION OUTPUT ;
    USE SIGNAL ;
    PORT
      LAYER M3 ;
        RECT  34.632 0 34.65 0.144 ;
    END
  END hq1[16]
  PIN hq1[170]
    DIRECTION OUTPUT ;
    USE SIGNAL ;
    PORT
      LAYER M3 ;
        RECT  45.72 0 45.738 0.144 ;
    END
  END hq1[170]
  PIN hq1[171]
    DIRECTION OUTPUT ;
    USE SIGNAL ;
    PORT
      LAYER M5 ;
        RECT  45.744 0 45.768 0.192 ;
    END
  END hq1[171]
  PIN hq1[172]
    DIRECTION OUTPUT ;
    USE SIGNAL ;
    PORT
      LAYER M3 ;
        RECT  45.864 0 45.882 0.144 ;
    END
  END hq1[172]
  PIN hq1[173]
    DIRECTION OUTPUT ;
    USE SIGNAL ;
    PORT
      LAYER M5 ;
        RECT  45.888 0 45.912 0.192 ;
    END
  END hq1[173]
  PIN hq1[174]
    DIRECTION OUTPUT ;
    USE SIGNAL ;
    PORT
      LAYER M3 ;
        RECT  46.008 0 46.026 0.144 ;
    END
  END hq1[174]
  PIN hq1[175]
    DIRECTION OUTPUT ;
    USE SIGNAL ;
    PORT
      LAYER M5 ;
        RECT  46.032 0 46.056 0.192 ;
    END
  END hq1[175]
  PIN hq1[176]
    DIRECTION OUTPUT ;
    USE SIGNAL ;
    PORT
      LAYER M3 ;
        RECT  46.152 0 46.17 0.144 ;
    END
  END hq1[176]
  PIN hq1[177]
    DIRECTION OUTPUT ;
    USE SIGNAL ;
    PORT
      LAYER M5 ;
        RECT  46.176 0 46.2 0.192 ;
    END
  END hq1[177]
  PIN hq1[178]
    DIRECTION OUTPUT ;
    USE SIGNAL ;
    PORT
      LAYER M3 ;
        RECT  46.296 0 46.314 0.144 ;
    END
  END hq1[178]
  PIN hq1[179]
    DIRECTION OUTPUT ;
    USE SIGNAL ;
    PORT
      LAYER M5 ;
        RECT  46.32 0 46.344 0.192 ;
    END
  END hq1[179]
  PIN hq1[17]
    DIRECTION OUTPUT ;
    USE SIGNAL ;
    PORT
      LAYER M5 ;
        RECT  34.656 0 34.68 0.192 ;
    END
  END hq1[17]
  PIN hq1[180]
    DIRECTION OUTPUT ;
    USE SIGNAL ;
    PORT
      LAYER M3 ;
        RECT  46.44 0 46.458 0.144 ;
    END
  END hq1[180]
  PIN hq1[181]
    DIRECTION OUTPUT ;
    USE SIGNAL ;
    PORT
      LAYER M5 ;
        RECT  46.464 0 46.488 0.192 ;
    END
  END hq1[181]
  PIN hq1[182]
    DIRECTION OUTPUT ;
    USE SIGNAL ;
    PORT
      LAYER M3 ;
        RECT  46.584 0 46.602 0.144 ;
    END
  END hq1[182]
  PIN hq1[183]
    DIRECTION OUTPUT ;
    USE SIGNAL ;
    PORT
      LAYER M5 ;
        RECT  46.608 0 46.632 0.192 ;
    END
  END hq1[183]
  PIN hq1[184]
    DIRECTION OUTPUT ;
    USE SIGNAL ;
    PORT
      LAYER M3 ;
        RECT  46.728 0 46.746 0.144 ;
    END
  END hq1[184]
  PIN hq1[185]
    DIRECTION OUTPUT ;
    USE SIGNAL ;
    PORT
      LAYER M5 ;
        RECT  46.752 0 46.776 0.192 ;
    END
  END hq1[185]
  PIN hq1[186]
    DIRECTION OUTPUT ;
    USE SIGNAL ;
    PORT
      LAYER M3 ;
        RECT  46.872 0 46.89 0.144 ;
    END
  END hq1[186]
  PIN hq1[187]
    DIRECTION OUTPUT ;
    USE SIGNAL ;
    PORT
      LAYER M5 ;
        RECT  46.896 0 46.92 0.192 ;
    END
  END hq1[187]
  PIN hq1[188]
    DIRECTION OUTPUT ;
    USE SIGNAL ;
    PORT
      LAYER M3 ;
        RECT  47.016 0 47.034 0.144 ;
    END
  END hq1[188]
  PIN hq1[189]
    DIRECTION OUTPUT ;
    USE SIGNAL ;
    PORT
      LAYER M5 ;
        RECT  47.04 0 47.064 0.192 ;
    END
  END hq1[189]
  PIN hq1[18]
    DIRECTION OUTPUT ;
    USE SIGNAL ;
    PORT
      LAYER M3 ;
        RECT  34.776 0 34.794 0.144 ;
    END
  END hq1[18]
  PIN hq1[190]
    DIRECTION OUTPUT ;
    USE SIGNAL ;
    PORT
      LAYER M3 ;
        RECT  47.16 0 47.178 0.144 ;
    END
  END hq1[190]
  PIN hq1[191]
    DIRECTION OUTPUT ;
    USE SIGNAL ;
    PORT
      LAYER M5 ;
        RECT  47.184 0 47.208 0.192 ;
    END
  END hq1[191]
  PIN hq1[192]
    DIRECTION OUTPUT ;
    USE SIGNAL ;
    PORT
      LAYER M3 ;
        RECT  47.304 0 47.322 0.144 ;
    END
  END hq1[192]
  PIN hq1[193]
    DIRECTION OUTPUT ;
    USE SIGNAL ;
    PORT
      LAYER M5 ;
        RECT  47.328 0 47.352 0.192 ;
    END
  END hq1[193]
  PIN hq1[194]
    DIRECTION OUTPUT ;
    USE SIGNAL ;
    PORT
      LAYER M3 ;
        RECT  47.448 0 47.466 0.144 ;
    END
  END hq1[194]
  PIN hq1[195]
    DIRECTION OUTPUT ;
    USE SIGNAL ;
    PORT
      LAYER M5 ;
        RECT  47.472 0 47.496 0.192 ;
    END
  END hq1[195]
  PIN hq1[196]
    DIRECTION OUTPUT ;
    USE SIGNAL ;
    PORT
      LAYER M3 ;
        RECT  47.592 0 47.61 0.144 ;
    END
  END hq1[196]
  PIN hq1[197]
    DIRECTION OUTPUT ;
    USE SIGNAL ;
    PORT
      LAYER M5 ;
        RECT  47.616 0 47.64 0.192 ;
    END
  END hq1[197]
  PIN hq1[198]
    DIRECTION OUTPUT ;
    USE SIGNAL ;
    PORT
      LAYER M3 ;
        RECT  47.736 0 47.754 0.144 ;
    END
  END hq1[198]
  PIN hq1[199]
    DIRECTION OUTPUT ;
    USE SIGNAL ;
    PORT
      LAYER M5 ;
        RECT  47.76 0 47.784 0.192 ;
    END
  END hq1[199]
  PIN hq1[19]
    DIRECTION OUTPUT ;
    USE SIGNAL ;
    PORT
      LAYER M5 ;
        RECT  34.8 0 34.824 0.192 ;
    END
  END hq1[19]
  PIN hq1[1]
    DIRECTION OUTPUT ;
    USE SIGNAL ;
    PORT
      LAYER M5 ;
        RECT  33.504 0 33.528 0.192 ;
    END
  END hq1[1]
  PIN hq1[200]
    DIRECTION OUTPUT ;
    USE SIGNAL ;
    PORT
      LAYER M3 ;
        RECT  47.88 0 47.898 0.144 ;
    END
  END hq1[200]
  PIN hq1[201]
    DIRECTION OUTPUT ;
    USE SIGNAL ;
    PORT
      LAYER M5 ;
        RECT  47.904 0 47.928 0.192 ;
    END
  END hq1[201]
  PIN hq1[202]
    DIRECTION OUTPUT ;
    USE SIGNAL ;
    PORT
      LAYER M3 ;
        RECT  48.024 0 48.042 0.144 ;
    END
  END hq1[202]
  PIN hq1[203]
    DIRECTION OUTPUT ;
    USE SIGNAL ;
    PORT
      LAYER M5 ;
        RECT  48.048 0 48.072 0.192 ;
    END
  END hq1[203]
  PIN hq1[204]
    DIRECTION OUTPUT ;
    USE SIGNAL ;
    PORT
      LAYER M3 ;
        RECT  48.168 0 48.186 0.144 ;
    END
  END hq1[204]
  PIN hq1[205]
    DIRECTION OUTPUT ;
    USE SIGNAL ;
    PORT
      LAYER M5 ;
        RECT  48.192 0 48.216 0.192 ;
    END
  END hq1[205]
  PIN hq1[206]
    DIRECTION OUTPUT ;
    USE SIGNAL ;
    PORT
      LAYER M3 ;
        RECT  48.312 0 48.33 0.144 ;
    END
  END hq1[206]
  PIN hq1[207]
    DIRECTION OUTPUT ;
    USE SIGNAL ;
    PORT
      LAYER M5 ;
        RECT  48.336 0 48.36 0.192 ;
    END
  END hq1[207]
  PIN hq1[208]
    DIRECTION OUTPUT ;
    USE SIGNAL ;
    PORT
      LAYER M3 ;
        RECT  48.456 0 48.474 0.144 ;
    END
  END hq1[208]
  PIN hq1[209]
    DIRECTION OUTPUT ;
    USE SIGNAL ;
    PORT
      LAYER M5 ;
        RECT  48.48 0 48.504 0.192 ;
    END
  END hq1[209]
  PIN hq1[20]
    DIRECTION OUTPUT ;
    USE SIGNAL ;
    PORT
      LAYER M3 ;
        RECT  34.92 0 34.938 0.144 ;
    END
  END hq1[20]
  PIN hq1[210]
    DIRECTION OUTPUT ;
    USE SIGNAL ;
    PORT
      LAYER M3 ;
        RECT  48.6 0 48.618 0.144 ;
    END
  END hq1[210]
  PIN hq1[211]
    DIRECTION OUTPUT ;
    USE SIGNAL ;
    PORT
      LAYER M5 ;
        RECT  48.624 0 48.648 0.192 ;
    END
  END hq1[211]
  PIN hq1[212]
    DIRECTION OUTPUT ;
    USE SIGNAL ;
    PORT
      LAYER M3 ;
        RECT  48.744 0 48.762 0.144 ;
    END
  END hq1[212]
  PIN hq1[213]
    DIRECTION OUTPUT ;
    USE SIGNAL ;
    PORT
      LAYER M5 ;
        RECT  48.768 0 48.792 0.192 ;
    END
  END hq1[213]
  PIN hq1[214]
    DIRECTION OUTPUT ;
    USE SIGNAL ;
    PORT
      LAYER M3 ;
        RECT  48.888 0 48.906 0.144 ;
    END
  END hq1[214]
  PIN hq1[215]
    DIRECTION OUTPUT ;
    USE SIGNAL ;
    PORT
      LAYER M5 ;
        RECT  48.912 0 48.936 0.192 ;
    END
  END hq1[215]
  PIN hq1[216]
    DIRECTION OUTPUT ;
    USE SIGNAL ;
    PORT
      LAYER M3 ;
        RECT  49.032 0 49.05 0.144 ;
    END
  END hq1[216]
  PIN hq1[217]
    DIRECTION OUTPUT ;
    USE SIGNAL ;
    PORT
      LAYER M5 ;
        RECT  49.056 0 49.08 0.192 ;
    END
  END hq1[217]
  PIN hq1[218]
    DIRECTION OUTPUT ;
    USE SIGNAL ;
    PORT
      LAYER M3 ;
        RECT  49.176 0 49.194 0.144 ;
    END
  END hq1[218]
  PIN hq1[219]
    DIRECTION OUTPUT ;
    USE SIGNAL ;
    PORT
      LAYER M5 ;
        RECT  49.2 0 49.224 0.192 ;
    END
  END hq1[219]
  PIN hq1[21]
    DIRECTION OUTPUT ;
    USE SIGNAL ;
    PORT
      LAYER M5 ;
        RECT  34.944 0 34.968 0.192 ;
    END
  END hq1[21]
  PIN hq1[220]
    DIRECTION OUTPUT ;
    USE SIGNAL ;
    PORT
      LAYER M3 ;
        RECT  49.32 0 49.338 0.144 ;
    END
  END hq1[220]
  PIN hq1[221]
    DIRECTION OUTPUT ;
    USE SIGNAL ;
    PORT
      LAYER M5 ;
        RECT  49.344 0 49.368 0.192 ;
    END
  END hq1[221]
  PIN hq1[222]
    DIRECTION OUTPUT ;
    USE SIGNAL ;
    PORT
      LAYER M3 ;
        RECT  49.464 0 49.482 0.144 ;
    END
  END hq1[222]
  PIN hq1[223]
    DIRECTION OUTPUT ;
    USE SIGNAL ;
    PORT
      LAYER M5 ;
        RECT  49.488 0 49.512 0.192 ;
    END
  END hq1[223]
  PIN hq1[224]
    DIRECTION OUTPUT ;
    USE SIGNAL ;
    PORT
      LAYER M3 ;
        RECT  49.608 0 49.626 0.144 ;
    END
  END hq1[224]
  PIN hq1[225]
    DIRECTION OUTPUT ;
    USE SIGNAL ;
    PORT
      LAYER M5 ;
        RECT  49.632 0 49.656 0.192 ;
    END
  END hq1[225]
  PIN hq1[226]
    DIRECTION OUTPUT ;
    USE SIGNAL ;
    PORT
      LAYER M3 ;
        RECT  49.752 0 49.77 0.144 ;
    END
  END hq1[226]
  PIN hq1[227]
    DIRECTION OUTPUT ;
    USE SIGNAL ;
    PORT
      LAYER M5 ;
        RECT  49.776 0 49.8 0.192 ;
    END
  END hq1[227]
  PIN hq1[228]
    DIRECTION OUTPUT ;
    USE SIGNAL ;
    PORT
      LAYER M3 ;
        RECT  49.896 0 49.914 0.144 ;
    END
  END hq1[228]
  PIN hq1[229]
    DIRECTION OUTPUT ;
    USE SIGNAL ;
    PORT
      LAYER M5 ;
        RECT  49.92 0 49.944 0.192 ;
    END
  END hq1[229]
  PIN hq1[22]
    DIRECTION OUTPUT ;
    USE SIGNAL ;
    PORT
      LAYER M3 ;
        RECT  35.064 0 35.082 0.144 ;
    END
  END hq1[22]
  PIN hq1[230]
    DIRECTION OUTPUT ;
    USE SIGNAL ;
    PORT
      LAYER M3 ;
        RECT  50.04 0 50.058 0.144 ;
    END
  END hq1[230]
  PIN hq1[231]
    DIRECTION OUTPUT ;
    USE SIGNAL ;
    PORT
      LAYER M5 ;
        RECT  50.064 0 50.088 0.192 ;
    END
  END hq1[231]
  PIN hq1[232]
    DIRECTION OUTPUT ;
    USE SIGNAL ;
    PORT
      LAYER M3 ;
        RECT  50.184 0 50.202 0.144 ;
    END
  END hq1[232]
  PIN hq1[233]
    DIRECTION OUTPUT ;
    USE SIGNAL ;
    PORT
      LAYER M5 ;
        RECT  50.208 0 50.232 0.192 ;
    END
  END hq1[233]
  PIN hq1[234]
    DIRECTION OUTPUT ;
    USE SIGNAL ;
    PORT
      LAYER M3 ;
        RECT  50.328 0 50.346 0.144 ;
    END
  END hq1[234]
  PIN hq1[235]
    DIRECTION OUTPUT ;
    USE SIGNAL ;
    PORT
      LAYER M5 ;
        RECT  50.352 0 50.376 0.192 ;
    END
  END hq1[235]
  PIN hq1[236]
    DIRECTION OUTPUT ;
    USE SIGNAL ;
    PORT
      LAYER M3 ;
        RECT  50.472 0 50.49 0.144 ;
    END
  END hq1[236]
  PIN hq1[237]
    DIRECTION OUTPUT ;
    USE SIGNAL ;
    PORT
      LAYER M5 ;
        RECT  50.496 0 50.52 0.192 ;
    END
  END hq1[237]
  PIN hq1[238]
    DIRECTION OUTPUT ;
    USE SIGNAL ;
    PORT
      LAYER M3 ;
        RECT  50.616 0 50.634 0.144 ;
    END
  END hq1[238]
  PIN hq1[239]
    DIRECTION OUTPUT ;
    USE SIGNAL ;
    PORT
      LAYER M5 ;
        RECT  50.64 0 50.664 0.192 ;
    END
  END hq1[239]
  PIN hq1[23]
    DIRECTION OUTPUT ;
    USE SIGNAL ;
    PORT
      LAYER M5 ;
        RECT  35.088 0 35.112 0.192 ;
    END
  END hq1[23]
  PIN hq1[240]
    DIRECTION OUTPUT ;
    USE SIGNAL ;
    PORT
      LAYER M3 ;
        RECT  50.76 0 50.778 0.144 ;
    END
  END hq1[240]
  PIN hq1[241]
    DIRECTION OUTPUT ;
    USE SIGNAL ;
    PORT
      LAYER M5 ;
        RECT  50.784 0 50.808 0.192 ;
    END
  END hq1[241]
  PIN hq1[242]
    DIRECTION OUTPUT ;
    USE SIGNAL ;
    PORT
      LAYER M3 ;
        RECT  50.904 0 50.922 0.144 ;
    END
  END hq1[242]
  PIN hq1[243]
    DIRECTION OUTPUT ;
    USE SIGNAL ;
    PORT
      LAYER M5 ;
        RECT  50.928 0 50.952 0.192 ;
    END
  END hq1[243]
  PIN hq1[244]
    DIRECTION OUTPUT ;
    USE SIGNAL ;
    PORT
      LAYER M3 ;
        RECT  51.048 0 51.066 0.144 ;
    END
  END hq1[244]
  PIN hq1[245]
    DIRECTION OUTPUT ;
    USE SIGNAL ;
    PORT
      LAYER M5 ;
        RECT  51.072 0 51.096 0.192 ;
    END
  END hq1[245]
  PIN hq1[246]
    DIRECTION OUTPUT ;
    USE SIGNAL ;
    PORT
      LAYER M3 ;
        RECT  51.192 0 51.21 0.144 ;
    END
  END hq1[246]
  PIN hq1[247]
    DIRECTION OUTPUT ;
    USE SIGNAL ;
    PORT
      LAYER M5 ;
        RECT  51.216 0 51.24 0.192 ;
    END
  END hq1[247]
  PIN hq1[248]
    DIRECTION OUTPUT ;
    USE SIGNAL ;
    PORT
      LAYER M3 ;
        RECT  51.336 0 51.354 0.144 ;
    END
  END hq1[248]
  PIN hq1[249]
    DIRECTION OUTPUT ;
    USE SIGNAL ;
    PORT
      LAYER M5 ;
        RECT  51.36 0 51.384 0.192 ;
    END
  END hq1[249]
  PIN hq1[24]
    DIRECTION OUTPUT ;
    USE SIGNAL ;
    PORT
      LAYER M3 ;
        RECT  35.208 0 35.226 0.144 ;
    END
  END hq1[24]
  PIN hq1[250]
    DIRECTION OUTPUT ;
    USE SIGNAL ;
    PORT
      LAYER M3 ;
        RECT  51.48 0 51.498 0.144 ;
    END
  END hq1[250]
  PIN hq1[251]
    DIRECTION OUTPUT ;
    USE SIGNAL ;
    PORT
      LAYER M5 ;
        RECT  51.504 0 51.528 0.192 ;
    END
  END hq1[251]
  PIN hq1[252]
    DIRECTION OUTPUT ;
    USE SIGNAL ;
    PORT
      LAYER M3 ;
        RECT  51.624 0 51.642 0.144 ;
    END
  END hq1[252]
  PIN hq1[253]
    DIRECTION OUTPUT ;
    USE SIGNAL ;
    PORT
      LAYER M5 ;
        RECT  51.648 0 51.672 0.192 ;
    END
  END hq1[253]
  PIN hq1[254]
    DIRECTION OUTPUT ;
    USE SIGNAL ;
    PORT
      LAYER M3 ;
        RECT  51.768 0 51.786 0.144 ;
    END
  END hq1[254]
  PIN hq1[255]
    DIRECTION OUTPUT ;
    USE SIGNAL ;
    PORT
      LAYER M5 ;
        RECT  51.792 0 51.816 0.192 ;
    END
  END hq1[255]
  PIN hq1[25]
    DIRECTION OUTPUT ;
    USE SIGNAL ;
    PORT
      LAYER M5 ;
        RECT  35.232 0 35.256 0.192 ;
    END
  END hq1[25]
  PIN hq1[26]
    DIRECTION OUTPUT ;
    USE SIGNAL ;
    PORT
      LAYER M3 ;
        RECT  35.352 0 35.37 0.144 ;
    END
  END hq1[26]
  PIN hq1[27]
    DIRECTION OUTPUT ;
    USE SIGNAL ;
    PORT
      LAYER M5 ;
        RECT  35.376 0 35.4 0.192 ;
    END
  END hq1[27]
  PIN hq1[28]
    DIRECTION OUTPUT ;
    USE SIGNAL ;
    PORT
      LAYER M3 ;
        RECT  35.496 0 35.514 0.144 ;
    END
  END hq1[28]
  PIN hq1[29]
    DIRECTION OUTPUT ;
    USE SIGNAL ;
    PORT
      LAYER M5 ;
        RECT  35.52 0 35.544 0.192 ;
    END
  END hq1[29]
  PIN hq1[2]
    DIRECTION OUTPUT ;
    USE SIGNAL ;
    PORT
      LAYER M3 ;
        RECT  33.624 0 33.642 0.144 ;
    END
  END hq1[2]
  PIN hq1[30]
    DIRECTION OUTPUT ;
    USE SIGNAL ;
    PORT
      LAYER M3 ;
        RECT  35.64 0 35.658 0.144 ;
    END
  END hq1[30]
  PIN hq1[31]
    DIRECTION OUTPUT ;
    USE SIGNAL ;
    PORT
      LAYER M5 ;
        RECT  35.664 0 35.688 0.192 ;
    END
  END hq1[31]
  PIN hq1[32]
    DIRECTION OUTPUT ;
    USE SIGNAL ;
    PORT
      LAYER M3 ;
        RECT  35.784 0 35.802 0.144 ;
    END
  END hq1[32]
  PIN hq1[33]
    DIRECTION OUTPUT ;
    USE SIGNAL ;
    PORT
      LAYER M5 ;
        RECT  35.808 0 35.832 0.192 ;
    END
  END hq1[33]
  PIN hq1[34]
    DIRECTION OUTPUT ;
    USE SIGNAL ;
    PORT
      LAYER M3 ;
        RECT  35.928 0 35.946 0.144 ;
    END
  END hq1[34]
  PIN hq1[35]
    DIRECTION OUTPUT ;
    USE SIGNAL ;
    PORT
      LAYER M5 ;
        RECT  35.952 0 35.976 0.192 ;
    END
  END hq1[35]
  PIN hq1[36]
    DIRECTION OUTPUT ;
    USE SIGNAL ;
    PORT
      LAYER M3 ;
        RECT  36.072 0 36.09 0.144 ;
    END
  END hq1[36]
  PIN hq1[37]
    DIRECTION OUTPUT ;
    USE SIGNAL ;
    PORT
      LAYER M5 ;
        RECT  36.096 0 36.12 0.192 ;
    END
  END hq1[37]
  PIN hq1[38]
    DIRECTION OUTPUT ;
    USE SIGNAL ;
    PORT
      LAYER M3 ;
        RECT  36.216 0 36.234 0.144 ;
    END
  END hq1[38]
  PIN hq1[39]
    DIRECTION OUTPUT ;
    USE SIGNAL ;
    PORT
      LAYER M5 ;
        RECT  36.24 0 36.264 0.192 ;
    END
  END hq1[39]
  PIN hq1[3]
    DIRECTION OUTPUT ;
    USE SIGNAL ;
    PORT
      LAYER M5 ;
        RECT  33.648 0 33.672 0.192 ;
    END
  END hq1[3]
  PIN hq1[40]
    DIRECTION OUTPUT ;
    USE SIGNAL ;
    PORT
      LAYER M3 ;
        RECT  36.36 0 36.378 0.144 ;
    END
  END hq1[40]
  PIN hq1[41]
    DIRECTION OUTPUT ;
    USE SIGNAL ;
    PORT
      LAYER M5 ;
        RECT  36.384 0 36.408 0.192 ;
    END
  END hq1[41]
  PIN hq1[42]
    DIRECTION OUTPUT ;
    USE SIGNAL ;
    PORT
      LAYER M3 ;
        RECT  36.504 0 36.522 0.144 ;
    END
  END hq1[42]
  PIN hq1[43]
    DIRECTION OUTPUT ;
    USE SIGNAL ;
    PORT
      LAYER M5 ;
        RECT  36.528 0 36.552 0.192 ;
    END
  END hq1[43]
  PIN hq1[44]
    DIRECTION OUTPUT ;
    USE SIGNAL ;
    PORT
      LAYER M3 ;
        RECT  36.648 0 36.666 0.144 ;
    END
  END hq1[44]
  PIN hq1[45]
    DIRECTION OUTPUT ;
    USE SIGNAL ;
    PORT
      LAYER M5 ;
        RECT  36.672 0 36.696 0.192 ;
    END
  END hq1[45]
  PIN hq1[46]
    DIRECTION OUTPUT ;
    USE SIGNAL ;
    PORT
      LAYER M3 ;
        RECT  36.792 0 36.81 0.144 ;
    END
  END hq1[46]
  PIN hq1[47]
    DIRECTION OUTPUT ;
    USE SIGNAL ;
    PORT
      LAYER M5 ;
        RECT  36.816 0 36.84 0.192 ;
    END
  END hq1[47]
  PIN hq1[48]
    DIRECTION OUTPUT ;
    USE SIGNAL ;
    PORT
      LAYER M3 ;
        RECT  36.936 0 36.954 0.144 ;
    END
  END hq1[48]
  PIN hq1[49]
    DIRECTION OUTPUT ;
    USE SIGNAL ;
    PORT
      LAYER M5 ;
        RECT  36.96 0 36.984 0.192 ;
    END
  END hq1[49]
  PIN hq1[4]
    DIRECTION OUTPUT ;
    USE SIGNAL ;
    PORT
      LAYER M3 ;
        RECT  33.768 0 33.786 0.144 ;
    END
  END hq1[4]
  PIN hq1[50]
    DIRECTION OUTPUT ;
    USE SIGNAL ;
    PORT
      LAYER M3 ;
        RECT  37.08 0 37.098 0.144 ;
    END
  END hq1[50]
  PIN hq1[51]
    DIRECTION OUTPUT ;
    USE SIGNAL ;
    PORT
      LAYER M5 ;
        RECT  37.104 0 37.128 0.192 ;
    END
  END hq1[51]
  PIN hq1[52]
    DIRECTION OUTPUT ;
    USE SIGNAL ;
    PORT
      LAYER M3 ;
        RECT  37.224 0 37.242 0.144 ;
    END
  END hq1[52]
  PIN hq1[53]
    DIRECTION OUTPUT ;
    USE SIGNAL ;
    PORT
      LAYER M5 ;
        RECT  37.248 0 37.272 0.192 ;
    END
  END hq1[53]
  PIN hq1[54]
    DIRECTION OUTPUT ;
    USE SIGNAL ;
    PORT
      LAYER M3 ;
        RECT  37.368 0 37.386 0.144 ;
    END
  END hq1[54]
  PIN hq1[55]
    DIRECTION OUTPUT ;
    USE SIGNAL ;
    PORT
      LAYER M5 ;
        RECT  37.392 0 37.416 0.192 ;
    END
  END hq1[55]
  PIN hq1[56]
    DIRECTION OUTPUT ;
    USE SIGNAL ;
    PORT
      LAYER M3 ;
        RECT  37.512 0 37.53 0.144 ;
    END
  END hq1[56]
  PIN hq1[57]
    DIRECTION OUTPUT ;
    USE SIGNAL ;
    PORT
      LAYER M5 ;
        RECT  37.536 0 37.56 0.192 ;
    END
  END hq1[57]
  PIN hq1[58]
    DIRECTION OUTPUT ;
    USE SIGNAL ;
    PORT
      LAYER M3 ;
        RECT  37.656 0 37.674 0.144 ;
    END
  END hq1[58]
  PIN hq1[59]
    DIRECTION OUTPUT ;
    USE SIGNAL ;
    PORT
      LAYER M5 ;
        RECT  37.68 0 37.704 0.192 ;
    END
  END hq1[59]
  PIN hq1[5]
    DIRECTION OUTPUT ;
    USE SIGNAL ;
    PORT
      LAYER M5 ;
        RECT  33.792 0 33.816 0.192 ;
    END
  END hq1[5]
  PIN hq1[60]
    DIRECTION OUTPUT ;
    USE SIGNAL ;
    PORT
      LAYER M3 ;
        RECT  37.8 0 37.818 0.144 ;
    END
  END hq1[60]
  PIN hq1[61]
    DIRECTION OUTPUT ;
    USE SIGNAL ;
    PORT
      LAYER M5 ;
        RECT  37.824 0 37.848 0.192 ;
    END
  END hq1[61]
  PIN hq1[62]
    DIRECTION OUTPUT ;
    USE SIGNAL ;
    PORT
      LAYER M3 ;
        RECT  37.944 0 37.962 0.144 ;
    END
  END hq1[62]
  PIN hq1[63]
    DIRECTION OUTPUT ;
    USE SIGNAL ;
    PORT
      LAYER M5 ;
        RECT  37.968 0 37.992 0.192 ;
    END
  END hq1[63]
  PIN hq1[64]
    DIRECTION OUTPUT ;
    USE SIGNAL ;
    PORT
      LAYER M3 ;
        RECT  38.088 0 38.106 0.144 ;
    END
  END hq1[64]
  PIN hq1[65]
    DIRECTION OUTPUT ;
    USE SIGNAL ;
    PORT
      LAYER M5 ;
        RECT  38.112 0 38.136 0.192 ;
    END
  END hq1[65]
  PIN hq1[66]
    DIRECTION OUTPUT ;
    USE SIGNAL ;
    PORT
      LAYER M3 ;
        RECT  38.232 0 38.25 0.144 ;
    END
  END hq1[66]
  PIN hq1[67]
    DIRECTION OUTPUT ;
    USE SIGNAL ;
    PORT
      LAYER M5 ;
        RECT  38.256 0 38.28 0.192 ;
    END
  END hq1[67]
  PIN hq1[68]
    DIRECTION OUTPUT ;
    USE SIGNAL ;
    PORT
      LAYER M3 ;
        RECT  38.376 0 38.394 0.144 ;
    END
  END hq1[68]
  PIN hq1[69]
    DIRECTION OUTPUT ;
    USE SIGNAL ;
    PORT
      LAYER M5 ;
        RECT  38.4 0 38.424 0.192 ;
    END
  END hq1[69]
  PIN hq1[6]
    DIRECTION OUTPUT ;
    USE SIGNAL ;
    PORT
      LAYER M3 ;
        RECT  33.912 0 33.93 0.144 ;
    END
  END hq1[6]
  PIN hq1[70]
    DIRECTION OUTPUT ;
    USE SIGNAL ;
    PORT
      LAYER M3 ;
        RECT  38.52 0 38.538 0.144 ;
    END
  END hq1[70]
  PIN hq1[71]
    DIRECTION OUTPUT ;
    USE SIGNAL ;
    PORT
      LAYER M5 ;
        RECT  38.544 0 38.568 0.192 ;
    END
  END hq1[71]
  PIN hq1[72]
    DIRECTION OUTPUT ;
    USE SIGNAL ;
    PORT
      LAYER M3 ;
        RECT  38.664 0 38.682 0.144 ;
    END
  END hq1[72]
  PIN hq1[73]
    DIRECTION OUTPUT ;
    USE SIGNAL ;
    PORT
      LAYER M5 ;
        RECT  38.688 0 38.712 0.192 ;
    END
  END hq1[73]
  PIN hq1[74]
    DIRECTION OUTPUT ;
    USE SIGNAL ;
    PORT
      LAYER M3 ;
        RECT  38.808 0 38.826 0.144 ;
    END
  END hq1[74]
  PIN hq1[75]
    DIRECTION OUTPUT ;
    USE SIGNAL ;
    PORT
      LAYER M5 ;
        RECT  38.832 0 38.856 0.192 ;
    END
  END hq1[75]
  PIN hq1[76]
    DIRECTION OUTPUT ;
    USE SIGNAL ;
    PORT
      LAYER M3 ;
        RECT  38.952 0 38.97 0.144 ;
    END
  END hq1[76]
  PIN hq1[77]
    DIRECTION OUTPUT ;
    USE SIGNAL ;
    PORT
      LAYER M5 ;
        RECT  38.976 0 39 0.192 ;
    END
  END hq1[77]
  PIN hq1[78]
    DIRECTION OUTPUT ;
    USE SIGNAL ;
    PORT
      LAYER M3 ;
        RECT  39.096 0 39.114 0.144 ;
    END
  END hq1[78]
  PIN hq1[79]
    DIRECTION OUTPUT ;
    USE SIGNAL ;
    PORT
      LAYER M5 ;
        RECT  39.12 0 39.144 0.192 ;
    END
  END hq1[79]
  PIN hq1[7]
    DIRECTION OUTPUT ;
    USE SIGNAL ;
    PORT
      LAYER M5 ;
        RECT  33.936 0 33.96 0.192 ;
    END
  END hq1[7]
  PIN hq1[80]
    DIRECTION OUTPUT ;
    USE SIGNAL ;
    PORT
      LAYER M3 ;
        RECT  39.24 0 39.258 0.144 ;
    END
  END hq1[80]
  PIN hq1[81]
    DIRECTION OUTPUT ;
    USE SIGNAL ;
    PORT
      LAYER M5 ;
        RECT  39.264 0 39.288 0.192 ;
    END
  END hq1[81]
  PIN hq1[82]
    DIRECTION OUTPUT ;
    USE SIGNAL ;
    PORT
      LAYER M3 ;
        RECT  39.384 0 39.402 0.144 ;
    END
  END hq1[82]
  PIN hq1[83]
    DIRECTION OUTPUT ;
    USE SIGNAL ;
    PORT
      LAYER M5 ;
        RECT  39.408 0 39.432 0.192 ;
    END
  END hq1[83]
  PIN hq1[84]
    DIRECTION OUTPUT ;
    USE SIGNAL ;
    PORT
      LAYER M3 ;
        RECT  39.528 0 39.546 0.144 ;
    END
  END hq1[84]
  PIN hq1[85]
    DIRECTION OUTPUT ;
    USE SIGNAL ;
    PORT
      LAYER M5 ;
        RECT  39.552 0 39.576 0.192 ;
    END
  END hq1[85]
  PIN hq1[86]
    DIRECTION OUTPUT ;
    USE SIGNAL ;
    PORT
      LAYER M3 ;
        RECT  39.672 0 39.69 0.144 ;
    END
  END hq1[86]
  PIN hq1[87]
    DIRECTION OUTPUT ;
    USE SIGNAL ;
    PORT
      LAYER M5 ;
        RECT  39.696 0 39.72 0.192 ;
    END
  END hq1[87]
  PIN hq1[88]
    DIRECTION OUTPUT ;
    USE SIGNAL ;
    PORT
      LAYER M3 ;
        RECT  39.816 0 39.834 0.144 ;
    END
  END hq1[88]
  PIN hq1[89]
    DIRECTION OUTPUT ;
    USE SIGNAL ;
    PORT
      LAYER M5 ;
        RECT  39.84 0 39.864 0.192 ;
    END
  END hq1[89]
  PIN hq1[8]
    DIRECTION OUTPUT ;
    USE SIGNAL ;
    PORT
      LAYER M3 ;
        RECT  34.056 0 34.074 0.144 ;
    END
  END hq1[8]
  PIN hq1[90]
    DIRECTION OUTPUT ;
    USE SIGNAL ;
    PORT
      LAYER M3 ;
        RECT  39.96 0 39.978 0.144 ;
    END
  END hq1[90]
  PIN hq1[91]
    DIRECTION OUTPUT ;
    USE SIGNAL ;
    PORT
      LAYER M5 ;
        RECT  39.984 0 40.008 0.192 ;
    END
  END hq1[91]
  PIN hq1[92]
    DIRECTION OUTPUT ;
    USE SIGNAL ;
    PORT
      LAYER M3 ;
        RECT  40.104 0 40.122 0.144 ;
    END
  END hq1[92]
  PIN hq1[93]
    DIRECTION OUTPUT ;
    USE SIGNAL ;
    PORT
      LAYER M5 ;
        RECT  40.128 0 40.152 0.192 ;
    END
  END hq1[93]
  PIN hq1[94]
    DIRECTION OUTPUT ;
    USE SIGNAL ;
    PORT
      LAYER M3 ;
        RECT  40.248 0 40.266 0.144 ;
    END
  END hq1[94]
  PIN hq1[95]
    DIRECTION OUTPUT ;
    USE SIGNAL ;
    PORT
      LAYER M5 ;
        RECT  40.272 0 40.296 0.192 ;
    END
  END hq1[95]
  PIN hq1[96]
    DIRECTION OUTPUT ;
    USE SIGNAL ;
    PORT
      LAYER M3 ;
        RECT  40.392 0 40.41 0.144 ;
    END
  END hq1[96]
  PIN hq1[97]
    DIRECTION OUTPUT ;
    USE SIGNAL ;
    PORT
      LAYER M5 ;
        RECT  40.416 0 40.44 0.192 ;
    END
  END hq1[97]
  PIN hq1[98]
    DIRECTION OUTPUT ;
    USE SIGNAL ;
    PORT
      LAYER M3 ;
        RECT  40.536 0 40.554 0.144 ;
    END
  END hq1[98]
  PIN hq1[99]
    DIRECTION OUTPUT ;
    USE SIGNAL ;
    PORT
      LAYER M5 ;
        RECT  40.56 0 40.584 0.192 ;
    END
  END hq1[99]
  PIN hq1[9]
    DIRECTION OUTPUT ;
    USE SIGNAL ;
    PORT
      LAYER M5 ;
        RECT  34.08 0 34.104 0.192 ;
    END
  END hq1[9]
  PIN hw_sv[0]
    DIRECTION INPUT ;
    USE SIGNAL ;
    PORT
      LAYER M4 ;
        RECT  0 21.072 0.192 21.096 ;
    END
  END hw_sv[0]
  PIN hw_sv[1]
    DIRECTION INPUT ;
    USE SIGNAL ;
    PORT
      LAYER M4 ;
        RECT  0 21.216 0.192 21.24 ;
    END
  END hw_sv[1]
  PIN i0[0]
    DIRECTION OUTPUT ;
    USE SIGNAL ;
    PORT
      LAYER M4 ;
        RECT  73.248 17.616 73.44 17.64 ;
    END
  END i0[0]
  PIN i0[10]
    DIRECTION OUTPUT ;
    USE SIGNAL ;
    PORT
      LAYER M4 ;
        RECT  73.248 19.056 73.44 19.08 ;
    END
  END i0[10]
  PIN i0[11]
    DIRECTION OUTPUT ;
    USE SIGNAL ;
    PORT
      LAYER M4 ;
        RECT  73.248 19.2 73.44 19.224 ;
    END
  END i0[11]
  PIN i0[12]
    DIRECTION OUTPUT ;
    USE SIGNAL ;
    PORT
      LAYER M4 ;
        RECT  73.248 19.344 73.44 19.368 ;
    END
  END i0[12]
  PIN i0[13]
    DIRECTION OUTPUT ;
    USE SIGNAL ;
    PORT
      LAYER M4 ;
        RECT  73.248 19.488 73.44 19.512 ;
    END
  END i0[13]
  PIN i0[14]
    DIRECTION OUTPUT ;
    USE SIGNAL ;
    PORT
      LAYER M4 ;
        RECT  73.248 19.632 73.44 19.656 ;
    END
  END i0[14]
  PIN i0[15]
    DIRECTION OUTPUT ;
    USE SIGNAL ;
    PORT
      LAYER M4 ;
        RECT  73.248 19.776 73.44 19.8 ;
    END
  END i0[15]
  PIN i0[1]
    DIRECTION OUTPUT ;
    USE SIGNAL ;
    PORT
      LAYER M4 ;
        RECT  73.248 17.76 73.44 17.784 ;
    END
  END i0[1]
  PIN i0[2]
    DIRECTION OUTPUT ;
    USE SIGNAL ;
    PORT
      LAYER M4 ;
        RECT  73.248 17.904 73.44 17.928 ;
    END
  END i0[2]
  PIN i0[3]
    DIRECTION OUTPUT ;
    USE SIGNAL ;
    PORT
      LAYER M4 ;
        RECT  73.248 18.048 73.44 18.072 ;
    END
  END i0[3]
  PIN i0[4]
    DIRECTION OUTPUT ;
    USE SIGNAL ;
    PORT
      LAYER M4 ;
        RECT  73.248 18.192 73.44 18.216 ;
    END
  END i0[4]
  PIN i0[5]
    DIRECTION OUTPUT ;
    USE SIGNAL ;
    PORT
      LAYER M4 ;
        RECT  73.248 18.336 73.44 18.36 ;
    END
  END i0[5]
  PIN i0[6]
    DIRECTION OUTPUT ;
    USE SIGNAL ;
    PORT
      LAYER M4 ;
        RECT  73.248 18.48 73.44 18.504 ;
    END
  END i0[6]
  PIN i0[7]
    DIRECTION OUTPUT ;
    USE SIGNAL ;
    PORT
      LAYER M4 ;
        RECT  73.248 18.624 73.44 18.648 ;
    END
  END i0[7]
  PIN i0[8]
    DIRECTION OUTPUT ;
    USE SIGNAL ;
    PORT
      LAYER M4 ;
        RECT  73.248 18.768 73.44 18.792 ;
    END
  END i0[8]
  PIN i0[9]
    DIRECTION OUTPUT ;
    USE SIGNAL ;
    PORT
      LAYER M4 ;
        RECT  73.248 18.912 73.44 18.936 ;
    END
  END i0[9]
  PIN i1[0]
    DIRECTION OUTPUT ;
    USE SIGNAL ;
    PORT
      LAYER M4 ;
        RECT  73.248 19.92 73.44 19.944 ;
    END
  END i1[0]
  PIN i1[10]
    DIRECTION OUTPUT ;
    USE SIGNAL ;
    PORT
      LAYER M4 ;
        RECT  73.248 21.36 73.44 21.384 ;
    END
  END i1[10]
  PIN i1[11]
    DIRECTION OUTPUT ;
    USE SIGNAL ;
    PORT
      LAYER M4 ;
        RECT  73.248 21.504 73.44 21.528 ;
    END
  END i1[11]
  PIN i1[12]
    DIRECTION OUTPUT ;
    USE SIGNAL ;
    PORT
      LAYER M4 ;
        RECT  73.248 21.648 73.44 21.672 ;
    END
  END i1[12]
  PIN i1[13]
    DIRECTION OUTPUT ;
    USE SIGNAL ;
    PORT
      LAYER M4 ;
        RECT  73.248 21.792 73.44 21.816 ;
    END
  END i1[13]
  PIN i1[14]
    DIRECTION OUTPUT ;
    USE SIGNAL ;
    PORT
      LAYER M4 ;
        RECT  73.248 21.936 73.44 21.96 ;
    END
  END i1[14]
  PIN i1[15]
    DIRECTION OUTPUT ;
    USE SIGNAL ;
    PORT
      LAYER M4 ;
        RECT  73.248 22.08 73.44 22.104 ;
    END
  END i1[15]
  PIN i1[1]
    DIRECTION OUTPUT ;
    USE SIGNAL ;
    PORT
      LAYER M4 ;
        RECT  73.248 20.064 73.44 20.088 ;
    END
  END i1[1]
  PIN i1[2]
    DIRECTION OUTPUT ;
    USE SIGNAL ;
    PORT
      LAYER M4 ;
        RECT  73.248 20.208 73.44 20.232 ;
    END
  END i1[2]
  PIN i1[3]
    DIRECTION OUTPUT ;
    USE SIGNAL ;
    PORT
      LAYER M4 ;
        RECT  73.248 20.352 73.44 20.376 ;
    END
  END i1[3]
  PIN i1[4]
    DIRECTION OUTPUT ;
    USE SIGNAL ;
    PORT
      LAYER M4 ;
        RECT  73.248 20.496 73.44 20.52 ;
    END
  END i1[4]
  PIN i1[5]
    DIRECTION OUTPUT ;
    USE SIGNAL ;
    PORT
      LAYER M4 ;
        RECT  73.248 20.64 73.44 20.664 ;
    END
  END i1[5]
  PIN i1[6]
    DIRECTION OUTPUT ;
    USE SIGNAL ;
    PORT
      LAYER M4 ;
        RECT  73.248 20.784 73.44 20.808 ;
    END
  END i1[6]
  PIN i1[7]
    DIRECTION OUTPUT ;
    USE SIGNAL ;
    PORT
      LAYER M4 ;
        RECT  73.248 20.928 73.44 20.952 ;
    END
  END i1[7]
  PIN i1[8]
    DIRECTION OUTPUT ;
    USE SIGNAL ;
    PORT
      LAYER M4 ;
        RECT  73.248 21.072 73.44 21.096 ;
    END
  END i1[8]
  PIN i1[9]
    DIRECTION OUTPUT ;
    USE SIGNAL ;
    PORT
      LAYER M4 ;
        RECT  73.248 21.216 73.44 21.24 ;
    END
  END i1[9]
  PIN ph0[0]
    DIRECTION OUTPUT ;
    USE SIGNAL ;
    PORT
      LAYER M4 ;
        RECT  73.248 13.584 73.44 13.608 ;
    END
  END ph0[0]
  PIN ph0[1]
    DIRECTION OUTPUT ;
    USE SIGNAL ;
    PORT
      LAYER M4 ;
        RECT  73.248 13.44 73.44 13.464 ;
    END
  END ph0[1]
  PIN ph0[2]
    DIRECTION OUTPUT ;
    USE SIGNAL ;
    PORT
      LAYER M4 ;
        RECT  73.248 13.296 73.44 13.32 ;
    END
  END ph0[2]
  PIN ph0[3]
    DIRECTION OUTPUT ;
    USE SIGNAL ;
    PORT
      LAYER M4 ;
        RECT  73.248 13.152 73.44 13.176 ;
    END
  END ph0[3]
  PIN ph0[4]
    DIRECTION OUTPUT ;
    USE SIGNAL ;
    PORT
      LAYER M4 ;
        RECT  73.248 13.008 73.44 13.032 ;
    END
  END ph0[4]
  PIN ph0[5]
    DIRECTION OUTPUT ;
    USE SIGNAL ;
    PORT
      LAYER M4 ;
        RECT  73.248 12.864 73.44 12.888 ;
    END
  END ph0[5]
  PIN ph1[0]
    DIRECTION OUTPUT ;
    USE SIGNAL ;
    PORT
      LAYER M4 ;
        RECT  73.248 12.72 73.44 12.744 ;
    END
  END ph1[0]
  PIN ph1[1]
    DIRECTION OUTPUT ;
    USE SIGNAL ;
    PORT
      LAYER M4 ;
        RECT  73.248 12.576 73.44 12.6 ;
    END
  END ph1[1]
  PIN ph1[2]
    DIRECTION OUTPUT ;
    USE SIGNAL ;
    PORT
      LAYER M4 ;
        RECT  73.248 12.432 73.44 12.456 ;
    END
  END ph1[2]
  PIN ph1[3]
    DIRECTION OUTPUT ;
    USE SIGNAL ;
    PORT
      LAYER M4 ;
        RECT  73.248 12.288 73.44 12.312 ;
    END
  END ph1[3]
  PIN ph1[4]
    DIRECTION OUTPUT ;
    USE SIGNAL ;
    PORT
      LAYER M4 ;
        RECT  73.248 12.144 73.44 12.168 ;
    END
  END ph1[4]
  PIN ph1[5]
    DIRECTION OUTPUT ;
    USE SIGNAL ;
    PORT
      LAYER M4 ;
        RECT  73.248 12 73.44 12.024 ;
    END
  END ph1[5]
  PIN pl0[0]
    DIRECTION OUTPUT ;
    USE SIGNAL ;
    PORT
      LAYER M4 ;
        RECT  73.248 11.856 73.44 11.88 ;
    END
  END pl0[0]
  PIN pl0[10]
    DIRECTION OUTPUT ;
    USE SIGNAL ;
    PORT
      LAYER M4 ;
        RECT  73.248 10.416 73.44 10.44 ;
    END
  END pl0[10]
  PIN pl0[11]
    DIRECTION OUTPUT ;
    USE SIGNAL ;
    PORT
      LAYER M4 ;
        RECT  73.248 10.272 73.44 10.296 ;
    END
  END pl0[11]
  PIN pl0[12]
    DIRECTION OUTPUT ;
    USE SIGNAL ;
    PORT
      LAYER M4 ;
        RECT  73.248 10.128 73.44 10.152 ;
    END
  END pl0[12]
  PIN pl0[13]
    DIRECTION OUTPUT ;
    USE SIGNAL ;
    PORT
      LAYER M4 ;
        RECT  73.248 9.984 73.44 10.008 ;
    END
  END pl0[13]
  PIN pl0[14]
    DIRECTION OUTPUT ;
    USE SIGNAL ;
    PORT
      LAYER M4 ;
        RECT  73.248 9.84 73.44 9.864 ;
    END
  END pl0[14]
  PIN pl0[15]
    DIRECTION OUTPUT ;
    USE SIGNAL ;
    PORT
      LAYER M4 ;
        RECT  73.248 9.696 73.44 9.72 ;
    END
  END pl0[15]
  PIN pl0[1]
    DIRECTION OUTPUT ;
    USE SIGNAL ;
    PORT
      LAYER M4 ;
        RECT  73.248 11.712 73.44 11.736 ;
    END
  END pl0[1]
  PIN pl0[2]
    DIRECTION OUTPUT ;
    USE SIGNAL ;
    PORT
      LAYER M4 ;
        RECT  73.248 11.568 73.44 11.592 ;
    END
  END pl0[2]
  PIN pl0[3]
    DIRECTION OUTPUT ;
    USE SIGNAL ;
    PORT
      LAYER M4 ;
        RECT  73.248 11.424 73.44 11.448 ;
    END
  END pl0[3]
  PIN pl0[4]
    DIRECTION OUTPUT ;
    USE SIGNAL ;
    PORT
      LAYER M4 ;
        RECT  73.248 11.28 73.44 11.304 ;
    END
  END pl0[4]
  PIN pl0[5]
    DIRECTION OUTPUT ;
    USE SIGNAL ;
    PORT
      LAYER M4 ;
        RECT  73.248 11.136 73.44 11.16 ;
    END
  END pl0[5]
  PIN pl0[6]
    DIRECTION OUTPUT ;
    USE SIGNAL ;
    PORT
      LAYER M4 ;
        RECT  73.248 10.992 73.44 11.016 ;
    END
  END pl0[6]
  PIN pl0[7]
    DIRECTION OUTPUT ;
    USE SIGNAL ;
    PORT
      LAYER M4 ;
        RECT  73.248 10.848 73.44 10.872 ;
    END
  END pl0[7]
  PIN pl0[8]
    DIRECTION OUTPUT ;
    USE SIGNAL ;
    PORT
      LAYER M4 ;
        RECT  73.248 10.704 73.44 10.728 ;
    END
  END pl0[8]
  PIN pl0[9]
    DIRECTION OUTPUT ;
    USE SIGNAL ;
    PORT
      LAYER M4 ;
        RECT  73.248 10.56 73.44 10.584 ;
    END
  END pl0[9]
  PIN pl1[0]
    DIRECTION OUTPUT ;
    USE SIGNAL ;
    PORT
      LAYER M4 ;
        RECT  73.248 9.552 73.44 9.576 ;
    END
  END pl1[0]
  PIN pl1[10]
    DIRECTION OUTPUT ;
    USE SIGNAL ;
    PORT
      LAYER M4 ;
        RECT  73.248 8.112 73.44 8.136 ;
    END
  END pl1[10]
  PIN pl1[11]
    DIRECTION OUTPUT ;
    USE SIGNAL ;
    PORT
      LAYER M4 ;
        RECT  73.248 7.968 73.44 7.992 ;
    END
  END pl1[11]
  PIN pl1[12]
    DIRECTION OUTPUT ;
    USE SIGNAL ;
    PORT
      LAYER M4 ;
        RECT  73.248 7.824 73.44 7.848 ;
    END
  END pl1[12]
  PIN pl1[13]
    DIRECTION OUTPUT ;
    USE SIGNAL ;
    PORT
      LAYER M4 ;
        RECT  73.248 7.68 73.44 7.704 ;
    END
  END pl1[13]
  PIN pl1[14]
    DIRECTION OUTPUT ;
    USE SIGNAL ;
    PORT
      LAYER M4 ;
        RECT  73.248 7.536 73.44 7.56 ;
    END
  END pl1[14]
  PIN pl1[15]
    DIRECTION OUTPUT ;
    USE SIGNAL ;
    PORT
      LAYER M4 ;
        RECT  73.248 7.392 73.44 7.416 ;
    END
  END pl1[15]
  PIN pl1[1]
    DIRECTION OUTPUT ;
    USE SIGNAL ;
    PORT
      LAYER M4 ;
        RECT  73.248 9.408 73.44 9.432 ;
    END
  END pl1[1]
  PIN pl1[2]
    DIRECTION OUTPUT ;
    USE SIGNAL ;
    PORT
      LAYER M4 ;
        RECT  73.248 9.264 73.44 9.288 ;
    END
  END pl1[2]
  PIN pl1[3]
    DIRECTION OUTPUT ;
    USE SIGNAL ;
    PORT
      LAYER M4 ;
        RECT  73.248 9.12 73.44 9.144 ;
    END
  END pl1[3]
  PIN pl1[4]
    DIRECTION OUTPUT ;
    USE SIGNAL ;
    PORT
      LAYER M4 ;
        RECT  73.248 8.976 73.44 9 ;
    END
  END pl1[4]
  PIN pl1[5]
    DIRECTION OUTPUT ;
    USE SIGNAL ;
    PORT
      LAYER M4 ;
        RECT  73.248 8.832 73.44 8.856 ;
    END
  END pl1[5]
  PIN pl1[6]
    DIRECTION OUTPUT ;
    USE SIGNAL ;
    PORT
      LAYER M4 ;
        RECT  73.248 8.688 73.44 8.712 ;
    END
  END pl1[6]
  PIN pl1[7]
    DIRECTION OUTPUT ;
    USE SIGNAL ;
    PORT
      LAYER M4 ;
        RECT  73.248 8.544 73.44 8.568 ;
    END
  END pl1[7]
  PIN pl1[8]
    DIRECTION OUTPUT ;
    USE SIGNAL ;
    PORT
      LAYER M4 ;
        RECT  73.248 8.4 73.44 8.424 ;
    END
  END pl1[8]
  PIN pl1[9]
    DIRECTION OUTPUT ;
    USE SIGNAL ;
    PORT
      LAYER M4 ;
        RECT  73.248 8.256 73.44 8.28 ;
    END
  END pl1[9]
  PIN rd_data[0]
    DIRECTION INPUT ;
    USE SIGNAL ;
    PORT
      LAYER M3 ;
        RECT  9 34.416 9.018 34.56 ;
    END
  END rd_data[0]
  PIN rd_data[1000]
    DIRECTION INPUT ;
    USE SIGNAL ;
    PORT
      LAYER M3 ;
        RECT  63 34.416 63.018 34.56 ;
    END
  END rd_data[1000]
  PIN rd_data[1001]
    DIRECTION INPUT ;
    USE SIGNAL ;
    PORT
      LAYER M5 ;
        RECT  60 34.368 60.024 34.56 ;
    END
  END rd_data[1001]
  PIN rd_data[1002]
    DIRECTION INPUT ;
    USE SIGNAL ;
    PORT
      LAYER M3 ;
        RECT  63.108 34.416 63.126 34.56 ;
    END
  END rd_data[1002]
  PIN rd_data[1003]
    DIRECTION INPUT ;
    USE SIGNAL ;
    PORT
      LAYER M5 ;
        RECT  60.096 34.368 60.12 34.56 ;
    END
  END rd_data[1003]
  PIN rd_data[1004]
    DIRECTION INPUT ;
    USE SIGNAL ;
    PORT
      LAYER M3 ;
        RECT  63.216 34.416 63.234 34.56 ;
    END
  END rd_data[1004]
  PIN rd_data[1005]
    DIRECTION INPUT ;
    USE SIGNAL ;
    PORT
      LAYER M5 ;
        RECT  60.192 34.368 60.216 34.56 ;
    END
  END rd_data[1005]
  PIN rd_data[1006]
    DIRECTION INPUT ;
    USE SIGNAL ;
    PORT
      LAYER M3 ;
        RECT  63.324 34.416 63.342 34.56 ;
    END
  END rd_data[1006]
  PIN rd_data[1007]
    DIRECTION INPUT ;
    USE SIGNAL ;
    PORT
      LAYER M5 ;
        RECT  60.288 34.368 60.312 34.56 ;
    END
  END rd_data[1007]
  PIN rd_data[1008]
    DIRECTION INPUT ;
    USE SIGNAL ;
    PORT
      LAYER M3 ;
        RECT  63.432 34.416 63.45 34.56 ;
    END
  END rd_data[1008]
  PIN rd_data[1009]
    DIRECTION INPUT ;
    USE SIGNAL ;
    PORT
      LAYER M5 ;
        RECT  60.384 34.368 60.408 34.56 ;
    END
  END rd_data[1009]
  PIN rd_data[100]
    DIRECTION INPUT ;
    USE SIGNAL ;
    PORT
      LAYER M3 ;
        RECT  14.4 34.416 14.418 34.56 ;
    END
  END rd_data[100]
  PIN rd_data[1010]
    DIRECTION INPUT ;
    USE SIGNAL ;
    PORT
      LAYER M3 ;
        RECT  63.54 34.416 63.558 34.56 ;
    END
  END rd_data[1010]
  PIN rd_data[1011]
    DIRECTION INPUT ;
    USE SIGNAL ;
    PORT
      LAYER M5 ;
        RECT  60.48 34.368 60.504 34.56 ;
    END
  END rd_data[1011]
  PIN rd_data[1012]
    DIRECTION INPUT ;
    USE SIGNAL ;
    PORT
      LAYER M3 ;
        RECT  63.648 34.416 63.666 34.56 ;
    END
  END rd_data[1012]
  PIN rd_data[1013]
    DIRECTION INPUT ;
    USE SIGNAL ;
    PORT
      LAYER M5 ;
        RECT  60.576 34.368 60.6 34.56 ;
    END
  END rd_data[1013]
  PIN rd_data[1014]
    DIRECTION INPUT ;
    USE SIGNAL ;
    PORT
      LAYER M3 ;
        RECT  63.756 34.416 63.774 34.56 ;
    END
  END rd_data[1014]
  PIN rd_data[1015]
    DIRECTION INPUT ;
    USE SIGNAL ;
    PORT
      LAYER M5 ;
        RECT  60.672 34.368 60.696 34.56 ;
    END
  END rd_data[1015]
  PIN rd_data[1016]
    DIRECTION INPUT ;
    USE SIGNAL ;
    PORT
      LAYER M3 ;
        RECT  63.864 34.416 63.882 34.56 ;
    END
  END rd_data[1016]
  PIN rd_data[1017]
    DIRECTION INPUT ;
    USE SIGNAL ;
    PORT
      LAYER M5 ;
        RECT  60.768 34.368 60.792 34.56 ;
    END
  END rd_data[1017]
  PIN rd_data[1018]
    DIRECTION INPUT ;
    USE SIGNAL ;
    PORT
      LAYER M3 ;
        RECT  63.972 34.416 63.99 34.56 ;
    END
  END rd_data[1018]
  PIN rd_data[1019]
    DIRECTION INPUT ;
    USE SIGNAL ;
    PORT
      LAYER M5 ;
        RECT  60.864 34.368 60.888 34.56 ;
    END
  END rd_data[1019]
  PIN rd_data[101]
    DIRECTION INPUT ;
    USE SIGNAL ;
    PORT
      LAYER M5 ;
        RECT  16.8 34.368 16.824 34.56 ;
    END
  END rd_data[101]
  PIN rd_data[1020]
    DIRECTION INPUT ;
    USE SIGNAL ;
    PORT
      LAYER M3 ;
        RECT  64.08 34.416 64.098 34.56 ;
    END
    PORT
      LAYER M3 ;
        RECT  64.008 34.428 64.134 34.493 ;
    END
  END rd_data[1020]
  PIN rd_data[1021]
    DIRECTION INPUT ;
    USE SIGNAL ;
    PORT
      LAYER M5 ;
        RECT  60.96 34.368 60.984 34.56 ;
    END
  END rd_data[1021]
  PIN rd_data[1022]
    DIRECTION INPUT ;
    USE SIGNAL ;
    PORT
      LAYER M3 ;
        RECT  64.188 34.416 64.206 34.56 ;
    END
  END rd_data[1022]
  PIN rd_data[1023]
    DIRECTION INPUT ;
    USE SIGNAL ;
    PORT
      LAYER M5 ;
        RECT  61.056 34.368 61.08 34.56 ;
    END
  END rd_data[1023]
  PIN rd_data[102]
    DIRECTION INPUT ;
    USE SIGNAL ;
    PORT
      LAYER M3 ;
        RECT  14.508 34.416 14.526 34.56 ;
    END
  END rd_data[102]
  PIN rd_data[103]
    DIRECTION INPUT ;
    USE SIGNAL ;
    PORT
      LAYER M5 ;
        RECT  16.896 34.368 16.92 34.56 ;
    END
  END rd_data[103]
  PIN rd_data[104]
    DIRECTION INPUT ;
    USE SIGNAL ;
    PORT
      LAYER M3 ;
        RECT  14.616 34.416 14.634 34.56 ;
    END
  END rd_data[104]
  PIN rd_data[105]
    DIRECTION INPUT ;
    USE SIGNAL ;
    PORT
      LAYER M5 ;
        RECT  16.992 34.368 17.016 34.56 ;
    END
  END rd_data[105]
  PIN rd_data[106]
    DIRECTION INPUT ;
    USE SIGNAL ;
    PORT
      LAYER M3 ;
        RECT  14.724 34.416 14.742 34.56 ;
    END
  END rd_data[106]
  PIN rd_data[107]
    DIRECTION INPUT ;
    USE SIGNAL ;
    PORT
      LAYER M5 ;
        RECT  17.088 34.368 17.112 34.56 ;
    END
  END rd_data[107]
  PIN rd_data[108]
    DIRECTION INPUT ;
    USE SIGNAL ;
    PORT
      LAYER M3 ;
        RECT  14.832 34.416 14.85 34.56 ;
    END
  END rd_data[108]
  PIN rd_data[109]
    DIRECTION INPUT ;
    USE SIGNAL ;
    PORT
      LAYER M5 ;
        RECT  17.184 34.368 17.208 34.56 ;
    END
  END rd_data[109]
  PIN rd_data[10]
    DIRECTION INPUT ;
    USE SIGNAL ;
    PORT
      LAYER M3 ;
        RECT  9.54 34.416 9.558 34.56 ;
    END
  END rd_data[10]
  PIN rd_data[110]
    DIRECTION INPUT ;
    USE SIGNAL ;
    PORT
      LAYER M3 ;
        RECT  14.94 34.416 14.958 34.56 ;
    END
  END rd_data[110]
  PIN rd_data[111]
    DIRECTION INPUT ;
    USE SIGNAL ;
    PORT
      LAYER M5 ;
        RECT  17.28 34.368 17.304 34.56 ;
    END
  END rd_data[111]
  PIN rd_data[112]
    DIRECTION INPUT ;
    USE SIGNAL ;
    PORT
      LAYER M3 ;
        RECT  15.048 34.416 15.066 34.56 ;
    END
  END rd_data[112]
  PIN rd_data[113]
    DIRECTION INPUT ;
    USE SIGNAL ;
    PORT
      LAYER M5 ;
        RECT  17.376 34.368 17.4 34.56 ;
    END
  END rd_data[113]
  PIN rd_data[114]
    DIRECTION INPUT ;
    USE SIGNAL ;
    PORT
      LAYER M3 ;
        RECT  15.156 34.416 15.174 34.56 ;
    END
  END rd_data[114]
  PIN rd_data[115]
    DIRECTION INPUT ;
    USE SIGNAL ;
    PORT
      LAYER M5 ;
        RECT  17.472 34.368 17.496 34.56 ;
    END
  END rd_data[115]
  PIN rd_data[116]
    DIRECTION INPUT ;
    USE SIGNAL ;
    PORT
      LAYER M3 ;
        RECT  15.264 34.416 15.282 34.56 ;
    END
  END rd_data[116]
  PIN rd_data[117]
    DIRECTION INPUT ;
    USE SIGNAL ;
    PORT
      LAYER M5 ;
        RECT  17.568 34.368 17.592 34.56 ;
    END
  END rd_data[117]
  PIN rd_data[118]
    DIRECTION INPUT ;
    USE SIGNAL ;
    PORT
      LAYER M3 ;
        RECT  15.372 34.416 15.39 34.56 ;
    END
  END rd_data[118]
  PIN rd_data[119]
    DIRECTION INPUT ;
    USE SIGNAL ;
    PORT
      LAYER M5 ;
        RECT  17.664 34.368 17.688 34.56 ;
    END
  END rd_data[119]
  PIN rd_data[11]
    DIRECTION INPUT ;
    USE SIGNAL ;
    PORT
      LAYER M5 ;
        RECT  12.48 34.368 12.504 34.56 ;
    END
  END rd_data[11]
  PIN rd_data[120]
    DIRECTION INPUT ;
    USE SIGNAL ;
    PORT
      LAYER M3 ;
        RECT  15.48 34.416 15.498 34.56 ;
    END
  END rd_data[120]
  PIN rd_data[121]
    DIRECTION INPUT ;
    USE SIGNAL ;
    PORT
      LAYER M5 ;
        RECT  17.76 34.368 17.784 34.56 ;
    END
  END rd_data[121]
  PIN rd_data[122]
    DIRECTION INPUT ;
    USE SIGNAL ;
    PORT
      LAYER M3 ;
        RECT  15.588 34.416 15.606 34.56 ;
    END
  END rd_data[122]
  PIN rd_data[123]
    DIRECTION INPUT ;
    USE SIGNAL ;
    PORT
      LAYER M5 ;
        RECT  17.856 34.368 17.88 34.56 ;
    END
  END rd_data[123]
  PIN rd_data[124]
    DIRECTION INPUT ;
    USE SIGNAL ;
    PORT
      LAYER M3 ;
        RECT  15.696 34.416 15.714 34.56 ;
    END
  END rd_data[124]
  PIN rd_data[125]
    DIRECTION INPUT ;
    USE SIGNAL ;
    PORT
      LAYER M5 ;
        RECT  17.952 34.368 17.976 34.56 ;
    END
  END rd_data[125]
  PIN rd_data[126]
    DIRECTION INPUT ;
    USE SIGNAL ;
    PORT
      LAYER M3 ;
        RECT  15.804 34.416 15.822 34.56 ;
    END
  END rd_data[126]
  PIN rd_data[127]
    DIRECTION INPUT ;
    USE SIGNAL ;
    PORT
      LAYER M5 ;
        RECT  18.048 34.368 18.072 34.56 ;
    END
  END rd_data[127]
  PIN rd_data[128]
    DIRECTION INPUT ;
    USE SIGNAL ;
    PORT
      LAYER M3 ;
        RECT  15.912 34.416 15.93 34.56 ;
    END
  END rd_data[128]
  PIN rd_data[129]
    DIRECTION INPUT ;
    USE SIGNAL ;
    PORT
      LAYER M5 ;
        RECT  18.144 34.368 18.168 34.56 ;
    END
  END rd_data[129]
  PIN rd_data[12]
    DIRECTION INPUT ;
    USE SIGNAL ;
    PORT
      LAYER M3 ;
        RECT  9.648 34.416 9.666 34.56 ;
    END
  END rd_data[12]
  PIN rd_data[130]
    DIRECTION INPUT ;
    USE SIGNAL ;
    PORT
      LAYER M3 ;
        RECT  16.02 34.416 16.038 34.56 ;
    END
  END rd_data[130]
  PIN rd_data[131]
    DIRECTION INPUT ;
    USE SIGNAL ;
    PORT
      LAYER M5 ;
        RECT  18.24 34.368 18.264 34.56 ;
    END
  END rd_data[131]
  PIN rd_data[132]
    DIRECTION INPUT ;
    USE SIGNAL ;
    PORT
      LAYER M3 ;
        RECT  16.128 34.416 16.146 34.56 ;
    END
  END rd_data[132]
  PIN rd_data[133]
    DIRECTION INPUT ;
    USE SIGNAL ;
    PORT
      LAYER M5 ;
        RECT  18.336 34.368 18.36 34.56 ;
    END
  END rd_data[133]
  PIN rd_data[134]
    DIRECTION INPUT ;
    USE SIGNAL ;
    PORT
      LAYER M3 ;
        RECT  16.236 34.416 16.254 34.56 ;
    END
  END rd_data[134]
  PIN rd_data[135]
    DIRECTION INPUT ;
    USE SIGNAL ;
    PORT
      LAYER M5 ;
        RECT  18.432 34.368 18.456 34.56 ;
    END
  END rd_data[135]
  PIN rd_data[136]
    DIRECTION INPUT ;
    USE SIGNAL ;
    PORT
      LAYER M3 ;
        RECT  16.344 34.416 16.362 34.56 ;
    END
  END rd_data[136]
  PIN rd_data[137]
    DIRECTION INPUT ;
    USE SIGNAL ;
    PORT
      LAYER M5 ;
        RECT  18.528 34.368 18.552 34.56 ;
    END
  END rd_data[137]
  PIN rd_data[138]
    DIRECTION INPUT ;
    USE SIGNAL ;
    PORT
      LAYER M3 ;
        RECT  16.452 34.416 16.47 34.56 ;
    END
  END rd_data[138]
  PIN rd_data[139]
    DIRECTION INPUT ;
    USE SIGNAL ;
    PORT
      LAYER M5 ;
        RECT  18.624 34.368 18.648 34.56 ;
    END
  END rd_data[139]
  PIN rd_data[13]
    DIRECTION INPUT ;
    USE SIGNAL ;
    PORT
      LAYER M5 ;
        RECT  12.576 34.368 12.6 34.56 ;
    END
  END rd_data[13]
  PIN rd_data[140]
    DIRECTION INPUT ;
    USE SIGNAL ;
    PORT
      LAYER M3 ;
        RECT  16.56 34.416 16.578 34.56 ;
    END
  END rd_data[140]
  PIN rd_data[141]
    DIRECTION INPUT ;
    USE SIGNAL ;
    PORT
      LAYER M5 ;
        RECT  18.72 34.368 18.744 34.56 ;
    END
  END rd_data[141]
  PIN rd_data[142]
    DIRECTION INPUT ;
    USE SIGNAL ;
    PORT
      LAYER M3 ;
        RECT  16.668 34.416 16.686 34.56 ;
    END
  END rd_data[142]
  PIN rd_data[143]
    DIRECTION INPUT ;
    USE SIGNAL ;
    PORT
      LAYER M5 ;
        RECT  18.816 34.368 18.84 34.56 ;
    END
  END rd_data[143]
  PIN rd_data[144]
    DIRECTION INPUT ;
    USE SIGNAL ;
    PORT
      LAYER M3 ;
        RECT  16.776 34.416 16.794 34.56 ;
    END
  END rd_data[144]
  PIN rd_data[145]
    DIRECTION INPUT ;
    USE SIGNAL ;
    PORT
      LAYER M5 ;
        RECT  18.912 34.368 18.936 34.56 ;
    END
  END rd_data[145]
  PIN rd_data[146]
    DIRECTION INPUT ;
    USE SIGNAL ;
    PORT
      LAYER M3 ;
        RECT  16.884 34.416 16.902 34.56 ;
    END
  END rd_data[146]
  PIN rd_data[147]
    DIRECTION INPUT ;
    USE SIGNAL ;
    PORT
      LAYER M5 ;
        RECT  19.008 34.368 19.032 34.56 ;
    END
  END rd_data[147]
  PIN rd_data[148]
    DIRECTION INPUT ;
    USE SIGNAL ;
    PORT
      LAYER M3 ;
        RECT  16.992 34.416 17.01 34.56 ;
    END
  END rd_data[148]
  PIN rd_data[149]
    DIRECTION INPUT ;
    USE SIGNAL ;
    PORT
      LAYER M5 ;
        RECT  19.104 34.368 19.128 34.56 ;
    END
  END rd_data[149]
  PIN rd_data[14]
    DIRECTION INPUT ;
    USE SIGNAL ;
    PORT
      LAYER M3 ;
        RECT  9.756 34.416 9.774 34.56 ;
    END
  END rd_data[14]
  PIN rd_data[150]
    DIRECTION INPUT ;
    USE SIGNAL ;
    PORT
      LAYER M3 ;
        RECT  17.1 34.416 17.118 34.56 ;
    END
  END rd_data[150]
  PIN rd_data[151]
    DIRECTION INPUT ;
    USE SIGNAL ;
    PORT
      LAYER M5 ;
        RECT  19.2 34.368 19.224 34.56 ;
    END
  END rd_data[151]
  PIN rd_data[152]
    DIRECTION INPUT ;
    USE SIGNAL ;
    PORT
      LAYER M3 ;
        RECT  17.208 34.416 17.226 34.56 ;
    END
  END rd_data[152]
  PIN rd_data[153]
    DIRECTION INPUT ;
    USE SIGNAL ;
    PORT
      LAYER M5 ;
        RECT  19.296 34.368 19.32 34.56 ;
    END
  END rd_data[153]
  PIN rd_data[154]
    DIRECTION INPUT ;
    USE SIGNAL ;
    PORT
      LAYER M3 ;
        RECT  17.316 34.416 17.334 34.56 ;
    END
  END rd_data[154]
  PIN rd_data[155]
    DIRECTION INPUT ;
    USE SIGNAL ;
    PORT
      LAYER M5 ;
        RECT  19.392 34.368 19.416 34.56 ;
    END
  END rd_data[155]
  PIN rd_data[156]
    DIRECTION INPUT ;
    USE SIGNAL ;
    PORT
      LAYER M3 ;
        RECT  17.424 34.416 17.442 34.56 ;
    END
  END rd_data[156]
  PIN rd_data[157]
    DIRECTION INPUT ;
    USE SIGNAL ;
    PORT
      LAYER M5 ;
        RECT  19.488 34.368 19.512 34.56 ;
    END
  END rd_data[157]
  PIN rd_data[158]
    DIRECTION INPUT ;
    USE SIGNAL ;
    PORT
      LAYER M3 ;
        RECT  17.532 34.416 17.55 34.56 ;
    END
    PORT
      LAYER M3 ;
        RECT  17.496 34.428 17.622 34.493 ;
    END
  END rd_data[158]
  PIN rd_data[159]
    DIRECTION INPUT ;
    USE SIGNAL ;
    PORT
      LAYER M5 ;
        RECT  19.584 34.368 19.608 34.56 ;
    END
  END rd_data[159]
  PIN rd_data[15]
    DIRECTION INPUT ;
    USE SIGNAL ;
    PORT
      LAYER M5 ;
        RECT  12.672 34.368 12.696 34.56 ;
    END
  END rd_data[15]
  PIN rd_data[160]
    DIRECTION INPUT ;
    USE SIGNAL ;
    PORT
      LAYER M3 ;
        RECT  17.64 34.416 17.658 34.56 ;
    END
  END rd_data[160]
  PIN rd_data[161]
    DIRECTION INPUT ;
    USE SIGNAL ;
    PORT
      LAYER M5 ;
        RECT  19.68 34.368 19.704 34.56 ;
    END
  END rd_data[161]
  PIN rd_data[162]
    DIRECTION INPUT ;
    USE SIGNAL ;
    PORT
      LAYER M3 ;
        RECT  17.748 34.416 17.766 34.56 ;
    END
  END rd_data[162]
  PIN rd_data[163]
    DIRECTION INPUT ;
    USE SIGNAL ;
    PORT
      LAYER M5 ;
        RECT  19.776 34.368 19.8 34.56 ;
    END
  END rd_data[163]
  PIN rd_data[164]
    DIRECTION INPUT ;
    USE SIGNAL ;
    PORT
      LAYER M3 ;
        RECT  17.856 34.416 17.874 34.56 ;
    END
  END rd_data[164]
  PIN rd_data[165]
    DIRECTION INPUT ;
    USE SIGNAL ;
    PORT
      LAYER M5 ;
        RECT  19.872 34.368 19.896 34.56 ;
    END
  END rd_data[165]
  PIN rd_data[166]
    DIRECTION INPUT ;
    USE SIGNAL ;
    PORT
      LAYER M3 ;
        RECT  17.964 34.416 17.982 34.56 ;
    END
  END rd_data[166]
  PIN rd_data[167]
    DIRECTION INPUT ;
    USE SIGNAL ;
    PORT
      LAYER M5 ;
        RECT  19.968 34.368 19.992 34.56 ;
    END
  END rd_data[167]
  PIN rd_data[168]
    DIRECTION INPUT ;
    USE SIGNAL ;
    PORT
      LAYER M3 ;
        RECT  18.072 34.416 18.09 34.56 ;
    END
  END rd_data[168]
  PIN rd_data[169]
    DIRECTION INPUT ;
    USE SIGNAL ;
    PORT
      LAYER M5 ;
        RECT  20.064 34.368 20.088 34.56 ;
    END
  END rd_data[169]
  PIN rd_data[16]
    DIRECTION INPUT ;
    USE SIGNAL ;
    PORT
      LAYER M3 ;
        RECT  9.864 34.416 9.882 34.56 ;
    END
  END rd_data[16]
  PIN rd_data[170]
    DIRECTION INPUT ;
    USE SIGNAL ;
    PORT
      LAYER M3 ;
        RECT  18.18 34.416 18.198 34.56 ;
    END
  END rd_data[170]
  PIN rd_data[171]
    DIRECTION INPUT ;
    USE SIGNAL ;
    PORT
      LAYER M5 ;
        RECT  20.16 34.368 20.184 34.56 ;
    END
  END rd_data[171]
  PIN rd_data[172]
    DIRECTION INPUT ;
    USE SIGNAL ;
    PORT
      LAYER M3 ;
        RECT  18.288 34.416 18.306 34.56 ;
    END
  END rd_data[172]
  PIN rd_data[173]
    DIRECTION INPUT ;
    USE SIGNAL ;
    PORT
      LAYER M5 ;
        RECT  20.256 34.368 20.28 34.56 ;
    END
  END rd_data[173]
  PIN rd_data[174]
    DIRECTION INPUT ;
    USE SIGNAL ;
    PORT
      LAYER M3 ;
        RECT  18.396 34.416 18.414 34.56 ;
    END
    PORT
      LAYER M3 ;
        RECT  18.36 34.457 18.486 34.493 ;
    END
  END rd_data[174]
  PIN rd_data[175]
    DIRECTION INPUT ;
    USE SIGNAL ;
    PORT
      LAYER M5 ;
        RECT  20.352 34.368 20.376 34.56 ;
    END
  END rd_data[175]
  PIN rd_data[176]
    DIRECTION INPUT ;
    USE SIGNAL ;
    PORT
      LAYER M3 ;
        RECT  18.504 34.416 18.522 34.56 ;
    END
  END rd_data[176]
  PIN rd_data[177]
    DIRECTION INPUT ;
    USE SIGNAL ;
    PORT
      LAYER M5 ;
        RECT  20.448 34.368 20.472 34.56 ;
    END
  END rd_data[177]
  PIN rd_data[178]
    DIRECTION INPUT ;
    USE SIGNAL ;
    PORT
      LAYER M3 ;
        RECT  18.612 34.416 18.63 34.56 ;
    END
  END rd_data[178]
  PIN rd_data[179]
    DIRECTION INPUT ;
    USE SIGNAL ;
    PORT
      LAYER M5 ;
        RECT  20.544 34.368 20.568 34.56 ;
    END
  END rd_data[179]
  PIN rd_data[17]
    DIRECTION INPUT ;
    USE SIGNAL ;
    PORT
      LAYER M5 ;
        RECT  12.768 34.368 12.792 34.56 ;
    END
  END rd_data[17]
  PIN rd_data[180]
    DIRECTION INPUT ;
    USE SIGNAL ;
    PORT
      LAYER M3 ;
        RECT  18.72 34.416 18.738 34.56 ;
    END
  END rd_data[180]
  PIN rd_data[181]
    DIRECTION INPUT ;
    USE SIGNAL ;
    PORT
      LAYER M5 ;
        RECT  20.64 34.368 20.664 34.56 ;
    END
  END rd_data[181]
  PIN rd_data[182]
    DIRECTION INPUT ;
    USE SIGNAL ;
    PORT
      LAYER M3 ;
        RECT  18.828 34.416 18.846 34.56 ;
    END
  END rd_data[182]
  PIN rd_data[183]
    DIRECTION INPUT ;
    USE SIGNAL ;
    PORT
      LAYER M5 ;
        RECT  20.736 34.368 20.76 34.56 ;
    END
  END rd_data[183]
  PIN rd_data[184]
    DIRECTION INPUT ;
    USE SIGNAL ;
    PORT
      LAYER M3 ;
        RECT  18.936 34.416 18.954 34.56 ;
    END
  END rd_data[184]
  PIN rd_data[185]
    DIRECTION INPUT ;
    USE SIGNAL ;
    PORT
      LAYER M5 ;
        RECT  20.832 34.368 20.856 34.56 ;
    END
  END rd_data[185]
  PIN rd_data[186]
    DIRECTION INPUT ;
    USE SIGNAL ;
    PORT
      LAYER M3 ;
        RECT  19.044 34.416 19.062 34.56 ;
    END
  END rd_data[186]
  PIN rd_data[187]
    DIRECTION INPUT ;
    USE SIGNAL ;
    PORT
      LAYER M5 ;
        RECT  20.928 34.368 20.952 34.56 ;
    END
  END rd_data[187]
  PIN rd_data[188]
    DIRECTION INPUT ;
    USE SIGNAL ;
    PORT
      LAYER M3 ;
        RECT  19.152 34.416 19.17 34.56 ;
    END
  END rd_data[188]
  PIN rd_data[189]
    DIRECTION INPUT ;
    USE SIGNAL ;
    PORT
      LAYER M5 ;
        RECT  21.024 34.368 21.048 34.56 ;
    END
  END rd_data[189]
  PIN rd_data[18]
    DIRECTION INPUT ;
    USE SIGNAL ;
    PORT
      LAYER M3 ;
        RECT  9.972 34.416 9.99 34.56 ;
    END
  END rd_data[18]
  PIN rd_data[190]
    DIRECTION INPUT ;
    USE SIGNAL ;
    PORT
      LAYER M3 ;
        RECT  19.26 34.416 19.278 34.56 ;
    END
  END rd_data[190]
  PIN rd_data[191]
    DIRECTION INPUT ;
    USE SIGNAL ;
    PORT
      LAYER M5 ;
        RECT  21.12 34.368 21.144 34.56 ;
    END
  END rd_data[191]
  PIN rd_data[192]
    DIRECTION INPUT ;
    USE SIGNAL ;
    PORT
      LAYER M3 ;
        RECT  19.368 34.416 19.386 34.56 ;
    END
  END rd_data[192]
  PIN rd_data[193]
    DIRECTION INPUT ;
    USE SIGNAL ;
    PORT
      LAYER M5 ;
        RECT  21.216 34.368 21.24 34.56 ;
    END
  END rd_data[193]
  PIN rd_data[194]
    DIRECTION INPUT ;
    USE SIGNAL ;
    PORT
      LAYER M3 ;
        RECT  19.476 34.416 19.494 34.56 ;
    END
  END rd_data[194]
  PIN rd_data[195]
    DIRECTION INPUT ;
    USE SIGNAL ;
    PORT
      LAYER M5 ;
        RECT  21.312 34.368 21.336 34.56 ;
    END
  END rd_data[195]
  PIN rd_data[196]
    DIRECTION INPUT ;
    USE SIGNAL ;
    PORT
      LAYER M3 ;
        RECT  19.584 34.416 19.602 34.56 ;
    END
  END rd_data[196]
  PIN rd_data[197]
    DIRECTION INPUT ;
    USE SIGNAL ;
    PORT
      LAYER M5 ;
        RECT  21.408 34.368 21.432 34.56 ;
    END
  END rd_data[197]
  PIN rd_data[198]
    DIRECTION INPUT ;
    USE SIGNAL ;
    PORT
      LAYER M3 ;
        RECT  19.692 34.416 19.71 34.56 ;
    END
  END rd_data[198]
  PIN rd_data[199]
    DIRECTION INPUT ;
    USE SIGNAL ;
    PORT
      LAYER M5 ;
        RECT  21.504 34.368 21.528 34.56 ;
    END
  END rd_data[199]
  PIN rd_data[19]
    DIRECTION INPUT ;
    USE SIGNAL ;
    PORT
      LAYER M5 ;
        RECT  12.864 34.368 12.888 34.56 ;
    END
  END rd_data[19]
  PIN rd_data[1]
    DIRECTION INPUT ;
    USE SIGNAL ;
    PORT
      LAYER M5 ;
        RECT  12 34.368 12.024 34.56 ;
    END
  END rd_data[1]
  PIN rd_data[200]
    DIRECTION INPUT ;
    USE SIGNAL ;
    PORT
      LAYER M3 ;
        RECT  19.8 34.416 19.818 34.56 ;
    END
  END rd_data[200]
  PIN rd_data[201]
    DIRECTION INPUT ;
    USE SIGNAL ;
    PORT
      LAYER M5 ;
        RECT  21.6 34.368 21.624 34.56 ;
    END
  END rd_data[201]
  PIN rd_data[202]
    DIRECTION INPUT ;
    USE SIGNAL ;
    PORT
      LAYER M3 ;
        RECT  19.908 34.416 19.926 34.56 ;
    END
  END rd_data[202]
  PIN rd_data[203]
    DIRECTION INPUT ;
    USE SIGNAL ;
    PORT
      LAYER M5 ;
        RECT  21.696 34.368 21.72 34.56 ;
    END
  END rd_data[203]
  PIN rd_data[204]
    DIRECTION INPUT ;
    USE SIGNAL ;
    PORT
      LAYER M3 ;
        RECT  20.016 34.416 20.034 34.56 ;
    END
  END rd_data[204]
  PIN rd_data[205]
    DIRECTION INPUT ;
    USE SIGNAL ;
    PORT
      LAYER M5 ;
        RECT  21.792 34.368 21.816 34.56 ;
    END
  END rd_data[205]
  PIN rd_data[206]
    DIRECTION INPUT ;
    USE SIGNAL ;
    PORT
      LAYER M3 ;
        RECT  20.124 34.416 20.142 34.56 ;
    END
  END rd_data[206]
  PIN rd_data[207]
    DIRECTION INPUT ;
    USE SIGNAL ;
    PORT
      LAYER M5 ;
        RECT  21.888 34.368 21.912 34.56 ;
    END
  END rd_data[207]
  PIN rd_data[208]
    DIRECTION INPUT ;
    USE SIGNAL ;
    PORT
      LAYER M3 ;
        RECT  20.232 34.416 20.25 34.56 ;
    END
  END rd_data[208]
  PIN rd_data[209]
    DIRECTION INPUT ;
    USE SIGNAL ;
    PORT
      LAYER M5 ;
        RECT  21.984 34.368 22.008 34.56 ;
    END
  END rd_data[209]
  PIN rd_data[20]
    DIRECTION INPUT ;
    USE SIGNAL ;
    PORT
      LAYER M3 ;
        RECT  10.08 34.416 10.098 34.56 ;
    END
  END rd_data[20]
  PIN rd_data[210]
    DIRECTION INPUT ;
    USE SIGNAL ;
    PORT
      LAYER M3 ;
        RECT  20.34 34.416 20.358 34.56 ;
    END
  END rd_data[210]
  PIN rd_data[211]
    DIRECTION INPUT ;
    USE SIGNAL ;
    PORT
      LAYER M5 ;
        RECT  22.08 34.368 22.104 34.56 ;
    END
  END rd_data[211]
  PIN rd_data[212]
    DIRECTION INPUT ;
    USE SIGNAL ;
    PORT
      LAYER M3 ;
        RECT  20.448 34.416 20.466 34.56 ;
    END
  END rd_data[212]
  PIN rd_data[213]
    DIRECTION INPUT ;
    USE SIGNAL ;
    PORT
      LAYER M5 ;
        RECT  22.176 34.368 22.2 34.56 ;
    END
  END rd_data[213]
  PIN rd_data[214]
    DIRECTION INPUT ;
    USE SIGNAL ;
    PORT
      LAYER M3 ;
        RECT  20.556 34.416 20.574 34.56 ;
    END
  END rd_data[214]
  PIN rd_data[215]
    DIRECTION INPUT ;
    USE SIGNAL ;
    PORT
      LAYER M5 ;
        RECT  22.272 34.368 22.296 34.56 ;
    END
  END rd_data[215]
  PIN rd_data[216]
    DIRECTION INPUT ;
    USE SIGNAL ;
    PORT
      LAYER M3 ;
        RECT  20.664 34.416 20.682 34.56 ;
    END
  END rd_data[216]
  PIN rd_data[217]
    DIRECTION INPUT ;
    USE SIGNAL ;
    PORT
      LAYER M5 ;
        RECT  22.368 34.368 22.392 34.56 ;
    END
  END rd_data[217]
  PIN rd_data[218]
    DIRECTION INPUT ;
    USE SIGNAL ;
    PORT
      LAYER M3 ;
        RECT  20.772 34.416 20.79 34.56 ;
    END
  END rd_data[218]
  PIN rd_data[219]
    DIRECTION INPUT ;
    USE SIGNAL ;
    PORT
      LAYER M5 ;
        RECT  22.464 34.368 22.488 34.56 ;
    END
  END rd_data[219]
  PIN rd_data[21]
    DIRECTION INPUT ;
    USE SIGNAL ;
    PORT
      LAYER M5 ;
        RECT  12.96 34.368 12.984 34.56 ;
    END
  END rd_data[21]
  PIN rd_data[220]
    DIRECTION INPUT ;
    USE SIGNAL ;
    PORT
      LAYER M3 ;
        RECT  20.88 34.416 20.898 34.56 ;
    END
  END rd_data[220]
  PIN rd_data[221]
    DIRECTION INPUT ;
    USE SIGNAL ;
    PORT
      LAYER M5 ;
        RECT  22.56 34.368 22.584 34.56 ;
    END
  END rd_data[221]
  PIN rd_data[222]
    DIRECTION INPUT ;
    USE SIGNAL ;
    PORT
      LAYER M3 ;
        RECT  20.988 34.416 21.006 34.56 ;
    END
  END rd_data[222]
  PIN rd_data[223]
    DIRECTION INPUT ;
    USE SIGNAL ;
    PORT
      LAYER M5 ;
        RECT  22.656 34.368 22.68 34.56 ;
    END
  END rd_data[223]
  PIN rd_data[224]
    DIRECTION INPUT ;
    USE SIGNAL ;
    PORT
      LAYER M3 ;
        RECT  21.096 34.416 21.114 34.56 ;
    END
  END rd_data[224]
  PIN rd_data[225]
    DIRECTION INPUT ;
    USE SIGNAL ;
    PORT
      LAYER M5 ;
        RECT  22.752 34.368 22.776 34.56 ;
    END
  END rd_data[225]
  PIN rd_data[226]
    DIRECTION INPUT ;
    USE SIGNAL ;
    PORT
      LAYER M3 ;
        RECT  21.204 34.416 21.222 34.56 ;
    END
  END rd_data[226]
  PIN rd_data[227]
    DIRECTION INPUT ;
    USE SIGNAL ;
    PORT
      LAYER M5 ;
        RECT  22.848 34.368 22.872 34.56 ;
    END
  END rd_data[227]
  PIN rd_data[228]
    DIRECTION INPUT ;
    USE SIGNAL ;
    PORT
      LAYER M3 ;
        RECT  21.312 34.416 21.33 34.56 ;
    END
  END rd_data[228]
  PIN rd_data[229]
    DIRECTION INPUT ;
    USE SIGNAL ;
    PORT
      LAYER M5 ;
        RECT  22.944 34.368 22.968 34.56 ;
    END
  END rd_data[229]
  PIN rd_data[22]
    DIRECTION INPUT ;
    USE SIGNAL ;
    PORT
      LAYER M3 ;
        RECT  10.188 34.416 10.206 34.56 ;
    END
  END rd_data[22]
  PIN rd_data[230]
    DIRECTION INPUT ;
    USE SIGNAL ;
    PORT
      LAYER M3 ;
        RECT  21.42 34.416 21.438 34.56 ;
    END
  END rd_data[230]
  PIN rd_data[231]
    DIRECTION INPUT ;
    USE SIGNAL ;
    PORT
      LAYER M5 ;
        RECT  23.04 34.368 23.064 34.56 ;
    END
  END rd_data[231]
  PIN rd_data[232]
    DIRECTION INPUT ;
    USE SIGNAL ;
    PORT
      LAYER M3 ;
        RECT  21.528 34.416 21.546 34.56 ;
    END
  END rd_data[232]
  PIN rd_data[233]
    DIRECTION INPUT ;
    USE SIGNAL ;
    PORT
      LAYER M5 ;
        RECT  23.136 34.368 23.16 34.56 ;
    END
  END rd_data[233]
  PIN rd_data[234]
    DIRECTION INPUT ;
    USE SIGNAL ;
    PORT
      LAYER M3 ;
        RECT  21.636 34.416 21.654 34.56 ;
    END
  END rd_data[234]
  PIN rd_data[235]
    DIRECTION INPUT ;
    USE SIGNAL ;
    PORT
      LAYER M5 ;
        RECT  23.232 34.368 23.256 34.56 ;
    END
  END rd_data[235]
  PIN rd_data[236]
    DIRECTION INPUT ;
    USE SIGNAL ;
    PORT
      LAYER M3 ;
        RECT  21.744 34.416 21.762 34.56 ;
    END
  END rd_data[236]
  PIN rd_data[237]
    DIRECTION INPUT ;
    USE SIGNAL ;
    PORT
      LAYER M5 ;
        RECT  23.328 34.368 23.352 34.56 ;
    END
  END rd_data[237]
  PIN rd_data[238]
    DIRECTION INPUT ;
    USE SIGNAL ;
    PORT
      LAYER M3 ;
        RECT  21.852 34.416 21.87 34.56 ;
    END
  END rd_data[238]
  PIN rd_data[239]
    DIRECTION INPUT ;
    USE SIGNAL ;
    PORT
      LAYER M5 ;
        RECT  23.424 34.368 23.448 34.56 ;
    END
  END rd_data[239]
  PIN rd_data[23]
    DIRECTION INPUT ;
    USE SIGNAL ;
    PORT
      LAYER M5 ;
        RECT  13.056 34.368 13.08 34.56 ;
    END
  END rd_data[23]
  PIN rd_data[240]
    DIRECTION INPUT ;
    USE SIGNAL ;
    PORT
      LAYER M3 ;
        RECT  21.96 34.416 21.978 34.56 ;
    END
  END rd_data[240]
  PIN rd_data[241]
    DIRECTION INPUT ;
    USE SIGNAL ;
    PORT
      LAYER M5 ;
        RECT  23.52 34.368 23.544 34.56 ;
    END
  END rd_data[241]
  PIN rd_data[242]
    DIRECTION INPUT ;
    USE SIGNAL ;
    PORT
      LAYER M3 ;
        RECT  22.068 34.416 22.086 34.56 ;
    END
  END rd_data[242]
  PIN rd_data[243]
    DIRECTION INPUT ;
    USE SIGNAL ;
    PORT
      LAYER M5 ;
        RECT  23.616 34.368 23.64 34.56 ;
    END
  END rd_data[243]
  PIN rd_data[244]
    DIRECTION INPUT ;
    USE SIGNAL ;
    PORT
      LAYER M3 ;
        RECT  22.176 34.416 22.194 34.56 ;
    END
  END rd_data[244]
  PIN rd_data[245]
    DIRECTION INPUT ;
    USE SIGNAL ;
    PORT
      LAYER M5 ;
        RECT  23.712 34.368 23.736 34.56 ;
    END
  END rd_data[245]
  PIN rd_data[246]
    DIRECTION INPUT ;
    USE SIGNAL ;
    PORT
      LAYER M3 ;
        RECT  22.284 34.416 22.302 34.56 ;
    END
  END rd_data[246]
  PIN rd_data[247]
    DIRECTION INPUT ;
    USE SIGNAL ;
    PORT
      LAYER M5 ;
        RECT  23.808 34.368 23.832 34.56 ;
    END
  END rd_data[247]
  PIN rd_data[248]
    DIRECTION INPUT ;
    USE SIGNAL ;
    PORT
      LAYER M3 ;
        RECT  22.392 34.416 22.41 34.56 ;
    END
  END rd_data[248]
  PIN rd_data[249]
    DIRECTION INPUT ;
    USE SIGNAL ;
    PORT
      LAYER M5 ;
        RECT  23.904 34.368 23.928 34.56 ;
    END
  END rd_data[249]
  PIN rd_data[24]
    DIRECTION INPUT ;
    USE SIGNAL ;
    PORT
      LAYER M3 ;
        RECT  10.296 34.416 10.314 34.56 ;
    END
  END rd_data[24]
  PIN rd_data[250]
    DIRECTION INPUT ;
    USE SIGNAL ;
    PORT
      LAYER M3 ;
        RECT  22.5 34.416 22.518 34.56 ;
    END
  END rd_data[250]
  PIN rd_data[251]
    DIRECTION INPUT ;
    USE SIGNAL ;
    PORT
      LAYER M5 ;
        RECT  24 34.368 24.024 34.56 ;
    END
  END rd_data[251]
  PIN rd_data[252]
    DIRECTION INPUT ;
    USE SIGNAL ;
    PORT
      LAYER M3 ;
        RECT  22.608 34.416 22.626 34.56 ;
    END
  END rd_data[252]
  PIN rd_data[253]
    DIRECTION INPUT ;
    USE SIGNAL ;
    PORT
      LAYER M5 ;
        RECT  24.096 34.368 24.12 34.56 ;
    END
  END rd_data[253]
  PIN rd_data[254]
    DIRECTION INPUT ;
    USE SIGNAL ;
    PORT
      LAYER M3 ;
        RECT  22.716 34.416 22.734 34.56 ;
    END
  END rd_data[254]
  PIN rd_data[255]
    DIRECTION INPUT ;
    USE SIGNAL ;
    PORT
      LAYER M5 ;
        RECT  24.192 34.368 24.216 34.56 ;
    END
  END rd_data[255]
  PIN rd_data[256]
    DIRECTION INPUT ;
    USE SIGNAL ;
    PORT
      LAYER M3 ;
        RECT  22.824 34.416 22.842 34.56 ;
    END
  END rd_data[256]
  PIN rd_data[257]
    DIRECTION INPUT ;
    USE SIGNAL ;
    PORT
      LAYER M5 ;
        RECT  24.288 34.368 24.312 34.56 ;
    END
  END rd_data[257]
  PIN rd_data[258]
    DIRECTION INPUT ;
    USE SIGNAL ;
    PORT
      LAYER M3 ;
        RECT  22.932 34.416 22.95 34.56 ;
    END
  END rd_data[258]
  PIN rd_data[259]
    DIRECTION INPUT ;
    USE SIGNAL ;
    PORT
      LAYER M5 ;
        RECT  24.384 34.368 24.408 34.56 ;
    END
  END rd_data[259]
  PIN rd_data[25]
    DIRECTION INPUT ;
    USE SIGNAL ;
    PORT
      LAYER M5 ;
        RECT  13.152 34.368 13.176 34.56 ;
    END
  END rd_data[25]
  PIN rd_data[260]
    DIRECTION INPUT ;
    USE SIGNAL ;
    PORT
      LAYER M3 ;
        RECT  23.04 34.416 23.058 34.56 ;
    END
  END rd_data[260]
  PIN rd_data[261]
    DIRECTION INPUT ;
    USE SIGNAL ;
    PORT
      LAYER M5 ;
        RECT  24.48 34.368 24.504 34.56 ;
    END
  END rd_data[261]
  PIN rd_data[262]
    DIRECTION INPUT ;
    USE SIGNAL ;
    PORT
      LAYER M3 ;
        RECT  23.148 34.416 23.166 34.56 ;
    END
  END rd_data[262]
  PIN rd_data[263]
    DIRECTION INPUT ;
    USE SIGNAL ;
    PORT
      LAYER M5 ;
        RECT  24.576 34.368 24.6 34.56 ;
    END
  END rd_data[263]
  PIN rd_data[264]
    DIRECTION INPUT ;
    USE SIGNAL ;
    PORT
      LAYER M3 ;
        RECT  23.256 34.416 23.274 34.56 ;
    END
  END rd_data[264]
  PIN rd_data[265]
    DIRECTION INPUT ;
    USE SIGNAL ;
    PORT
      LAYER M5 ;
        RECT  24.672 34.368 24.696 34.56 ;
    END
  END rd_data[265]
  PIN rd_data[266]
    DIRECTION INPUT ;
    USE SIGNAL ;
    PORT
      LAYER M3 ;
        RECT  23.364 34.416 23.382 34.56 ;
    END
  END rd_data[266]
  PIN rd_data[267]
    DIRECTION INPUT ;
    USE SIGNAL ;
    PORT
      LAYER M5 ;
        RECT  24.768 34.368 24.792 34.56 ;
    END
  END rd_data[267]
  PIN rd_data[268]
    DIRECTION INPUT ;
    USE SIGNAL ;
    PORT
      LAYER M3 ;
        RECT  23.472 34.416 23.49 34.56 ;
    END
  END rd_data[268]
  PIN rd_data[269]
    DIRECTION INPUT ;
    USE SIGNAL ;
    PORT
      LAYER M5 ;
        RECT  24.864 34.368 24.888 34.56 ;
    END
  END rd_data[269]
  PIN rd_data[26]
    DIRECTION INPUT ;
    USE SIGNAL ;
    PORT
      LAYER M3 ;
        RECT  10.404 34.416 10.422 34.56 ;
    END
  END rd_data[26]
  PIN rd_data[270]
    DIRECTION INPUT ;
    USE SIGNAL ;
    PORT
      LAYER M3 ;
        RECT  23.58 34.416 23.598 34.56 ;
    END
  END rd_data[270]
  PIN rd_data[271]
    DIRECTION INPUT ;
    USE SIGNAL ;
    PORT
      LAYER M5 ;
        RECT  24.96 34.368 24.984 34.56 ;
    END
  END rd_data[271]
  PIN rd_data[272]
    DIRECTION INPUT ;
    USE SIGNAL ;
    PORT
      LAYER M3 ;
        RECT  23.688 34.416 23.706 34.56 ;
    END
  END rd_data[272]
  PIN rd_data[273]
    DIRECTION INPUT ;
    USE SIGNAL ;
    PORT
      LAYER M5 ;
        RECT  25.056 34.368 25.08 34.56 ;
    END
  END rd_data[273]
  PIN rd_data[274]
    DIRECTION INPUT ;
    USE SIGNAL ;
    PORT
      LAYER M3 ;
        RECT  23.796 34.416 23.814 34.56 ;
    END
  END rd_data[274]
  PIN rd_data[275]
    DIRECTION INPUT ;
    USE SIGNAL ;
    PORT
      LAYER M5 ;
        RECT  25.152 34.368 25.176 34.56 ;
    END
  END rd_data[275]
  PIN rd_data[276]
    DIRECTION INPUT ;
    USE SIGNAL ;
    PORT
      LAYER M3 ;
        RECT  23.904 34.416 23.922 34.56 ;
    END
  END rd_data[276]
  PIN rd_data[277]
    DIRECTION INPUT ;
    USE SIGNAL ;
    PORT
      LAYER M5 ;
        RECT  25.248 34.368 25.272 34.56 ;
    END
  END rd_data[277]
  PIN rd_data[278]
    DIRECTION INPUT ;
    USE SIGNAL ;
    PORT
      LAYER M3 ;
        RECT  24.012 34.416 24.03 34.56 ;
    END
  END rd_data[278]
  PIN rd_data[279]
    DIRECTION INPUT ;
    USE SIGNAL ;
    PORT
      LAYER M5 ;
        RECT  25.344 34.368 25.368 34.56 ;
    END
  END rd_data[279]
  PIN rd_data[27]
    DIRECTION INPUT ;
    USE SIGNAL ;
    PORT
      LAYER M5 ;
        RECT  13.248 34.368 13.272 34.56 ;
    END
  END rd_data[27]
  PIN rd_data[280]
    DIRECTION INPUT ;
    USE SIGNAL ;
    PORT
      LAYER M3 ;
        RECT  24.12 34.416 24.138 34.56 ;
    END
  END rd_data[280]
  PIN rd_data[281]
    DIRECTION INPUT ;
    USE SIGNAL ;
    PORT
      LAYER M5 ;
        RECT  25.44 34.368 25.464 34.56 ;
    END
  END rd_data[281]
  PIN rd_data[282]
    DIRECTION INPUT ;
    USE SIGNAL ;
    PORT
      LAYER M3 ;
        RECT  24.228 34.416 24.246 34.56 ;
    END
  END rd_data[282]
  PIN rd_data[283]
    DIRECTION INPUT ;
    USE SIGNAL ;
    PORT
      LAYER M5 ;
        RECT  25.536 34.368 25.56 34.56 ;
    END
  END rd_data[283]
  PIN rd_data[284]
    DIRECTION INPUT ;
    USE SIGNAL ;
    PORT
      LAYER M3 ;
        RECT  24.336 34.416 24.354 34.56 ;
    END
  END rd_data[284]
  PIN rd_data[285]
    DIRECTION INPUT ;
    USE SIGNAL ;
    PORT
      LAYER M5 ;
        RECT  25.632 34.368 25.656 34.56 ;
    END
  END rd_data[285]
  PIN rd_data[286]
    DIRECTION INPUT ;
    USE SIGNAL ;
    PORT
      LAYER M3 ;
        RECT  24.444 34.416 24.462 34.56 ;
    END
  END rd_data[286]
  PIN rd_data[287]
    DIRECTION INPUT ;
    USE SIGNAL ;
    PORT
      LAYER M5 ;
        RECT  25.728 34.368 25.752 34.56 ;
    END
  END rd_data[287]
  PIN rd_data[288]
    DIRECTION INPUT ;
    USE SIGNAL ;
    PORT
      LAYER M3 ;
        RECT  24.552 34.416 24.57 34.56 ;
    END
  END rd_data[288]
  PIN rd_data[289]
    DIRECTION INPUT ;
    USE SIGNAL ;
    PORT
      LAYER M5 ;
        RECT  25.824 34.368 25.848 34.56 ;
    END
  END rd_data[289]
  PIN rd_data[28]
    DIRECTION INPUT ;
    USE SIGNAL ;
    PORT
      LAYER M3 ;
        RECT  10.512 34.416 10.53 34.56 ;
    END
  END rd_data[28]
  PIN rd_data[290]
    DIRECTION INPUT ;
    USE SIGNAL ;
    PORT
      LAYER M3 ;
        RECT  24.66 34.416 24.678 34.56 ;
    END
  END rd_data[290]
  PIN rd_data[291]
    DIRECTION INPUT ;
    USE SIGNAL ;
    PORT
      LAYER M5 ;
        RECT  25.92 34.368 25.944 34.56 ;
    END
  END rd_data[291]
  PIN rd_data[292]
    DIRECTION INPUT ;
    USE SIGNAL ;
    PORT
      LAYER M3 ;
        RECT  24.768 34.416 24.786 34.56 ;
    END
  END rd_data[292]
  PIN rd_data[293]
    DIRECTION INPUT ;
    USE SIGNAL ;
    PORT
      LAYER M5 ;
        RECT  26.016 34.368 26.04 34.56 ;
    END
  END rd_data[293]
  PIN rd_data[294]
    DIRECTION INPUT ;
    USE SIGNAL ;
    PORT
      LAYER M3 ;
        RECT  24.876 34.416 24.894 34.56 ;
    END
    PORT
      LAYER M3 ;
        RECT  24.84 34.428 24.966 34.493 ;
    END
  END rd_data[294]
  PIN rd_data[295]
    DIRECTION INPUT ;
    USE SIGNAL ;
    PORT
      LAYER M5 ;
        RECT  26.112 34.368 26.136 34.56 ;
    END
  END rd_data[295]
  PIN rd_data[296]
    DIRECTION INPUT ;
    USE SIGNAL ;
    PORT
      LAYER M3 ;
        RECT  24.984 34.416 25.002 34.56 ;
    END
  END rd_data[296]
  PIN rd_data[297]
    DIRECTION INPUT ;
    USE SIGNAL ;
    PORT
      LAYER M5 ;
        RECT  26.208 34.368 26.232 34.56 ;
    END
  END rd_data[297]
  PIN rd_data[298]
    DIRECTION INPUT ;
    USE SIGNAL ;
    PORT
      LAYER M3 ;
        RECT  25.092 34.416 25.11 34.56 ;
    END
  END rd_data[298]
  PIN rd_data[299]
    DIRECTION INPUT ;
    USE SIGNAL ;
    PORT
      LAYER M5 ;
        RECT  26.304 34.368 26.328 34.56 ;
    END
  END rd_data[299]
  PIN rd_data[29]
    DIRECTION INPUT ;
    USE SIGNAL ;
    PORT
      LAYER M5 ;
        RECT  13.344 34.368 13.368 34.56 ;
    END
  END rd_data[29]
  PIN rd_data[2]
    DIRECTION INPUT ;
    USE SIGNAL ;
    PORT
      LAYER M3 ;
        RECT  9.108 34.416 9.126 34.56 ;
    END
  END rd_data[2]
  PIN rd_data[300]
    DIRECTION INPUT ;
    USE SIGNAL ;
    PORT
      LAYER M3 ;
        RECT  25.2 34.416 25.218 34.56 ;
    END
  END rd_data[300]
  PIN rd_data[301]
    DIRECTION INPUT ;
    USE SIGNAL ;
    PORT
      LAYER M5 ;
        RECT  26.4 34.368 26.424 34.56 ;
    END
  END rd_data[301]
  PIN rd_data[302]
    DIRECTION INPUT ;
    USE SIGNAL ;
    PORT
      LAYER M3 ;
        RECT  25.308 34.416 25.326 34.56 ;
    END
  END rd_data[302]
  PIN rd_data[303]
    DIRECTION INPUT ;
    USE SIGNAL ;
    PORT
      LAYER M5 ;
        RECT  26.496 34.368 26.52 34.56 ;
    END
  END rd_data[303]
  PIN rd_data[304]
    DIRECTION INPUT ;
    USE SIGNAL ;
    PORT
      LAYER M3 ;
        RECT  25.416 34.416 25.434 34.56 ;
    END
  END rd_data[304]
  PIN rd_data[305]
    DIRECTION INPUT ;
    USE SIGNAL ;
    PORT
      LAYER M5 ;
        RECT  26.592 34.368 26.616 34.56 ;
    END
  END rd_data[305]
  PIN rd_data[306]
    DIRECTION INPUT ;
    USE SIGNAL ;
    PORT
      LAYER M3 ;
        RECT  25.524 34.416 25.542 34.56 ;
    END
  END rd_data[306]
  PIN rd_data[307]
    DIRECTION INPUT ;
    USE SIGNAL ;
    PORT
      LAYER M5 ;
        RECT  26.688 34.368 26.712 34.56 ;
    END
  END rd_data[307]
  PIN rd_data[308]
    DIRECTION INPUT ;
    USE SIGNAL ;
    PORT
      LAYER M3 ;
        RECT  25.632 34.416 25.65 34.56 ;
    END
  END rd_data[308]
  PIN rd_data[309]
    DIRECTION INPUT ;
    USE SIGNAL ;
    PORT
      LAYER M5 ;
        RECT  26.784 34.368 26.808 34.56 ;
    END
  END rd_data[309]
  PIN rd_data[30]
    DIRECTION INPUT ;
    USE SIGNAL ;
    PORT
      LAYER M3 ;
        RECT  10.62 34.416 10.638 34.56 ;
    END
  END rd_data[30]
  PIN rd_data[310]
    DIRECTION INPUT ;
    USE SIGNAL ;
    PORT
      LAYER M3 ;
        RECT  25.74 34.416 25.758 34.56 ;
    END
  END rd_data[310]
  PIN rd_data[311]
    DIRECTION INPUT ;
    USE SIGNAL ;
    PORT
      LAYER M5 ;
        RECT  26.88 34.368 26.904 34.56 ;
    END
  END rd_data[311]
  PIN rd_data[312]
    DIRECTION INPUT ;
    USE SIGNAL ;
    PORT
      LAYER M3 ;
        RECT  25.848 34.416 25.866 34.56 ;
    END
  END rd_data[312]
  PIN rd_data[313]
    DIRECTION INPUT ;
    USE SIGNAL ;
    PORT
      LAYER M5 ;
        RECT  26.976 34.368 27 34.56 ;
    END
  END rd_data[313]
  PIN rd_data[314]
    DIRECTION INPUT ;
    USE SIGNAL ;
    PORT
      LAYER M3 ;
        RECT  25.956 34.416 25.974 34.56 ;
    END
  END rd_data[314]
  PIN rd_data[315]
    DIRECTION INPUT ;
    USE SIGNAL ;
    PORT
      LAYER M5 ;
        RECT  27.072 34.368 27.096 34.56 ;
    END
  END rd_data[315]
  PIN rd_data[316]
    DIRECTION INPUT ;
    USE SIGNAL ;
    PORT
      LAYER M3 ;
        RECT  26.064 34.416 26.082 34.56 ;
    END
  END rd_data[316]
  PIN rd_data[317]
    DIRECTION INPUT ;
    USE SIGNAL ;
    PORT
      LAYER M5 ;
        RECT  27.168 34.368 27.192 34.56 ;
    END
  END rd_data[317]
  PIN rd_data[318]
    DIRECTION INPUT ;
    USE SIGNAL ;
    PORT
      LAYER M3 ;
        RECT  26.172 34.416 26.19 34.56 ;
    END
  END rd_data[318]
  PIN rd_data[319]
    DIRECTION INPUT ;
    USE SIGNAL ;
    PORT
      LAYER M5 ;
        RECT  27.264 34.368 27.288 34.56 ;
    END
  END rd_data[319]
  PIN rd_data[31]
    DIRECTION INPUT ;
    USE SIGNAL ;
    PORT
      LAYER M5 ;
        RECT  13.44 34.368 13.464 34.56 ;
    END
  END rd_data[31]
  PIN rd_data[320]
    DIRECTION INPUT ;
    USE SIGNAL ;
    PORT
      LAYER M3 ;
        RECT  26.28 34.416 26.298 34.56 ;
    END
  END rd_data[320]
  PIN rd_data[321]
    DIRECTION INPUT ;
    USE SIGNAL ;
    PORT
      LAYER M5 ;
        RECT  27.36 34.368 27.384 34.56 ;
    END
  END rd_data[321]
  PIN rd_data[322]
    DIRECTION INPUT ;
    USE SIGNAL ;
    PORT
      LAYER M3 ;
        RECT  26.388 34.416 26.406 34.56 ;
    END
  END rd_data[322]
  PIN rd_data[323]
    DIRECTION INPUT ;
    USE SIGNAL ;
    PORT
      LAYER M5 ;
        RECT  27.456 34.368 27.48 34.56 ;
    END
  END rd_data[323]
  PIN rd_data[324]
    DIRECTION INPUT ;
    USE SIGNAL ;
    PORT
      LAYER M3 ;
        RECT  26.496 34.416 26.514 34.56 ;
    END
  END rd_data[324]
  PIN rd_data[325]
    DIRECTION INPUT ;
    USE SIGNAL ;
    PORT
      LAYER M5 ;
        RECT  27.552 34.368 27.576 34.56 ;
    END
  END rd_data[325]
  PIN rd_data[326]
    DIRECTION INPUT ;
    USE SIGNAL ;
    PORT
      LAYER M3 ;
        RECT  26.604 34.416 26.622 34.56 ;
    END
  END rd_data[326]
  PIN rd_data[327]
    DIRECTION INPUT ;
    USE SIGNAL ;
    PORT
      LAYER M5 ;
        RECT  27.648 34.368 27.672 34.56 ;
    END
  END rd_data[327]
  PIN rd_data[328]
    DIRECTION INPUT ;
    USE SIGNAL ;
    PORT
      LAYER M3 ;
        RECT  26.712 34.416 26.73 34.56 ;
    END
  END rd_data[328]
  PIN rd_data[329]
    DIRECTION INPUT ;
    USE SIGNAL ;
    PORT
      LAYER M5 ;
        RECT  27.744 34.368 27.768 34.56 ;
    END
  END rd_data[329]
  PIN rd_data[32]
    DIRECTION INPUT ;
    USE SIGNAL ;
    PORT
      LAYER M3 ;
        RECT  10.728 34.416 10.746 34.56 ;
    END
  END rd_data[32]
  PIN rd_data[330]
    DIRECTION INPUT ;
    USE SIGNAL ;
    PORT
      LAYER M3 ;
        RECT  26.82 34.416 26.838 34.56 ;
    END
  END rd_data[330]
  PIN rd_data[331]
    DIRECTION INPUT ;
    USE SIGNAL ;
    PORT
      LAYER M5 ;
        RECT  27.84 34.368 27.864 34.56 ;
    END
  END rd_data[331]
  PIN rd_data[332]
    DIRECTION INPUT ;
    USE SIGNAL ;
    PORT
      LAYER M3 ;
        RECT  26.928 34.416 26.946 34.56 ;
    END
  END rd_data[332]
  PIN rd_data[333]
    DIRECTION INPUT ;
    USE SIGNAL ;
    PORT
      LAYER M5 ;
        RECT  27.936 34.368 27.96 34.56 ;
    END
  END rd_data[333]
  PIN rd_data[334]
    DIRECTION INPUT ;
    USE SIGNAL ;
    PORT
      LAYER M3 ;
        RECT  27.036 34.416 27.054 34.56 ;
    END
  END rd_data[334]
  PIN rd_data[335]
    DIRECTION INPUT ;
    USE SIGNAL ;
    PORT
      LAYER M5 ;
        RECT  28.032 34.368 28.056 34.56 ;
    END
  END rd_data[335]
  PIN rd_data[336]
    DIRECTION INPUT ;
    USE SIGNAL ;
    PORT
      LAYER M3 ;
        RECT  27.144 34.416 27.162 34.56 ;
    END
  END rd_data[336]
  PIN rd_data[337]
    DIRECTION INPUT ;
    USE SIGNAL ;
    PORT
      LAYER M5 ;
        RECT  28.128 34.368 28.152 34.56 ;
    END
  END rd_data[337]
  PIN rd_data[338]
    DIRECTION INPUT ;
    USE SIGNAL ;
    PORT
      LAYER M3 ;
        RECT  27.252 34.416 27.27 34.56 ;
    END
  END rd_data[338]
  PIN rd_data[339]
    DIRECTION INPUT ;
    USE SIGNAL ;
    PORT
      LAYER M5 ;
        RECT  28.224 34.368 28.248 34.56 ;
    END
  END rd_data[339]
  PIN rd_data[33]
    DIRECTION INPUT ;
    USE SIGNAL ;
    PORT
      LAYER M5 ;
        RECT  13.536 34.368 13.56 34.56 ;
    END
  END rd_data[33]
  PIN rd_data[340]
    DIRECTION INPUT ;
    USE SIGNAL ;
    PORT
      LAYER M3 ;
        RECT  27.36 34.416 27.378 34.56 ;
    END
  END rd_data[340]
  PIN rd_data[341]
    DIRECTION INPUT ;
    USE SIGNAL ;
    PORT
      LAYER M5 ;
        RECT  28.32 34.368 28.344 34.56 ;
    END
  END rd_data[341]
  PIN rd_data[342]
    DIRECTION INPUT ;
    USE SIGNAL ;
    PORT
      LAYER M3 ;
        RECT  27.468 34.416 27.486 34.56 ;
    END
  END rd_data[342]
  PIN rd_data[343]
    DIRECTION INPUT ;
    USE SIGNAL ;
    PORT
      LAYER M5 ;
        RECT  28.416 34.368 28.44 34.56 ;
    END
  END rd_data[343]
  PIN rd_data[344]
    DIRECTION INPUT ;
    USE SIGNAL ;
    PORT
      LAYER M3 ;
        RECT  27.576 34.416 27.594 34.56 ;
    END
  END rd_data[344]
  PIN rd_data[345]
    DIRECTION INPUT ;
    USE SIGNAL ;
    PORT
      LAYER M5 ;
        RECT  28.512 34.368 28.536 34.56 ;
    END
  END rd_data[345]
  PIN rd_data[346]
    DIRECTION INPUT ;
    USE SIGNAL ;
    PORT
      LAYER M3 ;
        RECT  27.684 34.416 27.702 34.56 ;
    END
  END rd_data[346]
  PIN rd_data[347]
    DIRECTION INPUT ;
    USE SIGNAL ;
    PORT
      LAYER M5 ;
        RECT  28.608 34.368 28.632 34.56 ;
    END
  END rd_data[347]
  PIN rd_data[348]
    DIRECTION INPUT ;
    USE SIGNAL ;
    PORT
      LAYER M3 ;
        RECT  27.792 34.416 27.81 34.56 ;
    END
  END rd_data[348]
  PIN rd_data[349]
    DIRECTION INPUT ;
    USE SIGNAL ;
    PORT
      LAYER M5 ;
        RECT  28.704 34.368 28.728 34.56 ;
    END
  END rd_data[349]
  PIN rd_data[34]
    DIRECTION INPUT ;
    USE SIGNAL ;
    PORT
      LAYER M3 ;
        RECT  10.836 34.416 10.854 34.56 ;
    END
  END rd_data[34]
  PIN rd_data[350]
    DIRECTION INPUT ;
    USE SIGNAL ;
    PORT
      LAYER M3 ;
        RECT  27.9 34.416 27.918 34.56 ;
    END
  END rd_data[350]
  PIN rd_data[351]
    DIRECTION INPUT ;
    USE SIGNAL ;
    PORT
      LAYER M5 ;
        RECT  28.8 34.368 28.824 34.56 ;
    END
  END rd_data[351]
  PIN rd_data[352]
    DIRECTION INPUT ;
    USE SIGNAL ;
    PORT
      LAYER M3 ;
        RECT  28.008 34.416 28.026 34.56 ;
    END
  END rd_data[352]
  PIN rd_data[353]
    DIRECTION INPUT ;
    USE SIGNAL ;
    PORT
      LAYER M5 ;
        RECT  28.896 34.368 28.92 34.56 ;
    END
  END rd_data[353]
  PIN rd_data[354]
    DIRECTION INPUT ;
    USE SIGNAL ;
    PORT
      LAYER M3 ;
        RECT  28.116 34.416 28.134 34.56 ;
    END
  END rd_data[354]
  PIN rd_data[355]
    DIRECTION INPUT ;
    USE SIGNAL ;
    PORT
      LAYER M5 ;
        RECT  28.992 34.368 29.016 34.56 ;
    END
  END rd_data[355]
  PIN rd_data[356]
    DIRECTION INPUT ;
    USE SIGNAL ;
    PORT
      LAYER M3 ;
        RECT  28.224 34.416 28.242 34.56 ;
    END
  END rd_data[356]
  PIN rd_data[357]
    DIRECTION INPUT ;
    USE SIGNAL ;
    PORT
      LAYER M5 ;
        RECT  29.088 34.368 29.112 34.56 ;
    END
  END rd_data[357]
  PIN rd_data[358]
    DIRECTION INPUT ;
    USE SIGNAL ;
    PORT
      LAYER M3 ;
        RECT  28.332 34.416 28.35 34.56 ;
    END
  END rd_data[358]
  PIN rd_data[359]
    DIRECTION INPUT ;
    USE SIGNAL ;
    PORT
      LAYER M5 ;
        RECT  29.184 34.368 29.208 34.56 ;
    END
  END rd_data[359]
  PIN rd_data[35]
    DIRECTION INPUT ;
    USE SIGNAL ;
    PORT
      LAYER M5 ;
        RECT  13.632 34.368 13.656 34.56 ;
    END
  END rd_data[35]
  PIN rd_data[360]
    DIRECTION INPUT ;
    USE SIGNAL ;
    PORT
      LAYER M3 ;
        RECT  28.44 34.416 28.458 34.56 ;
    END
  END rd_data[360]
  PIN rd_data[361]
    DIRECTION INPUT ;
    USE SIGNAL ;
    PORT
      LAYER M5 ;
        RECT  29.28 34.368 29.304 34.56 ;
    END
  END rd_data[361]
  PIN rd_data[362]
    DIRECTION INPUT ;
    USE SIGNAL ;
    PORT
      LAYER M3 ;
        RECT  28.548 34.416 28.566 34.56 ;
    END
  END rd_data[362]
  PIN rd_data[363]
    DIRECTION INPUT ;
    USE SIGNAL ;
    PORT
      LAYER M5 ;
        RECT  29.376 34.368 29.4 34.56 ;
    END
  END rd_data[363]
  PIN rd_data[364]
    DIRECTION INPUT ;
    USE SIGNAL ;
    PORT
      LAYER M3 ;
        RECT  28.656 34.416 28.674 34.56 ;
    END
  END rd_data[364]
  PIN rd_data[365]
    DIRECTION INPUT ;
    USE SIGNAL ;
    PORT
      LAYER M5 ;
        RECT  29.472 34.368 29.496 34.56 ;
    END
  END rd_data[365]
  PIN rd_data[366]
    DIRECTION INPUT ;
    USE SIGNAL ;
    PORT
      LAYER M3 ;
        RECT  28.764 34.416 28.782 34.56 ;
    END
  END rd_data[366]
  PIN rd_data[367]
    DIRECTION INPUT ;
    USE SIGNAL ;
    PORT
      LAYER M5 ;
        RECT  29.568 34.368 29.592 34.56 ;
    END
  END rd_data[367]
  PIN rd_data[368]
    DIRECTION INPUT ;
    USE SIGNAL ;
    PORT
      LAYER M3 ;
        RECT  28.872 34.416 28.89 34.56 ;
    END
  END rd_data[368]
  PIN rd_data[369]
    DIRECTION INPUT ;
    USE SIGNAL ;
    PORT
      LAYER M5 ;
        RECT  29.664 34.368 29.688 34.56 ;
    END
  END rd_data[369]
  PIN rd_data[36]
    DIRECTION INPUT ;
    USE SIGNAL ;
    PORT
      LAYER M3 ;
        RECT  10.944 34.416 10.962 34.56 ;
    END
  END rd_data[36]
  PIN rd_data[370]
    DIRECTION INPUT ;
    USE SIGNAL ;
    PORT
      LAYER M3 ;
        RECT  28.98 34.416 28.998 34.56 ;
    END
  END rd_data[370]
  PIN rd_data[371]
    DIRECTION INPUT ;
    USE SIGNAL ;
    PORT
      LAYER M5 ;
        RECT  29.76 34.368 29.784 34.56 ;
    END
  END rd_data[371]
  PIN rd_data[372]
    DIRECTION INPUT ;
    USE SIGNAL ;
    PORT
      LAYER M3 ;
        RECT  29.088 34.416 29.106 34.56 ;
    END
  END rd_data[372]
  PIN rd_data[373]
    DIRECTION INPUT ;
    USE SIGNAL ;
    PORT
      LAYER M5 ;
        RECT  29.856 34.368 29.88 34.56 ;
    END
  END rd_data[373]
  PIN rd_data[374]
    DIRECTION INPUT ;
    USE SIGNAL ;
    PORT
      LAYER M3 ;
        RECT  29.196 34.416 29.214 34.56 ;
    END
  END rd_data[374]
  PIN rd_data[375]
    DIRECTION INPUT ;
    USE SIGNAL ;
    PORT
      LAYER M5 ;
        RECT  29.952 34.368 29.976 34.56 ;
    END
  END rd_data[375]
  PIN rd_data[376]
    DIRECTION INPUT ;
    USE SIGNAL ;
    PORT
      LAYER M3 ;
        RECT  29.304 34.416 29.322 34.56 ;
    END
  END rd_data[376]
  PIN rd_data[377]
    DIRECTION INPUT ;
    USE SIGNAL ;
    PORT
      LAYER M5 ;
        RECT  30.048 34.368 30.072 34.56 ;
    END
  END rd_data[377]
  PIN rd_data[378]
    DIRECTION INPUT ;
    USE SIGNAL ;
    PORT
      LAYER M3 ;
        RECT  29.412 34.416 29.43 34.56 ;
    END
  END rd_data[378]
  PIN rd_data[379]
    DIRECTION INPUT ;
    USE SIGNAL ;
    PORT
      LAYER M5 ;
        RECT  30.144 34.368 30.168 34.56 ;
    END
  END rd_data[379]
  PIN rd_data[37]
    DIRECTION INPUT ;
    USE SIGNAL ;
    PORT
      LAYER M5 ;
        RECT  13.728 34.368 13.752 34.56 ;
    END
  END rd_data[37]
  PIN rd_data[380]
    DIRECTION INPUT ;
    USE SIGNAL ;
    PORT
      LAYER M3 ;
        RECT  29.52 34.416 29.538 34.56 ;
    END
  END rd_data[380]
  PIN rd_data[381]
    DIRECTION INPUT ;
    USE SIGNAL ;
    PORT
      LAYER M5 ;
        RECT  30.24 34.368 30.264 34.56 ;
    END
  END rd_data[381]
  PIN rd_data[382]
    DIRECTION INPUT ;
    USE SIGNAL ;
    PORT
      LAYER M3 ;
        RECT  29.628 34.416 29.646 34.56 ;
    END
  END rd_data[382]
  PIN rd_data[383]
    DIRECTION INPUT ;
    USE SIGNAL ;
    PORT
      LAYER M5 ;
        RECT  30.336 34.368 30.36 34.56 ;
    END
  END rd_data[383]
  PIN rd_data[384]
    DIRECTION INPUT ;
    USE SIGNAL ;
    PORT
      LAYER M3 ;
        RECT  29.736 34.416 29.754 34.56 ;
    END
  END rd_data[384]
  PIN rd_data[385]
    DIRECTION INPUT ;
    USE SIGNAL ;
    PORT
      LAYER M5 ;
        RECT  30.432 34.368 30.456 34.56 ;
    END
  END rd_data[385]
  PIN rd_data[386]
    DIRECTION INPUT ;
    USE SIGNAL ;
    PORT
      LAYER M3 ;
        RECT  29.844 34.416 29.862 34.56 ;
    END
  END rd_data[386]
  PIN rd_data[387]
    DIRECTION INPUT ;
    USE SIGNAL ;
    PORT
      LAYER M5 ;
        RECT  30.528 34.368 30.552 34.56 ;
    END
  END rd_data[387]
  PIN rd_data[388]
    DIRECTION INPUT ;
    USE SIGNAL ;
    PORT
      LAYER M3 ;
        RECT  29.952 34.416 29.97 34.56 ;
    END
  END rd_data[388]
  PIN rd_data[389]
    DIRECTION INPUT ;
    USE SIGNAL ;
    PORT
      LAYER M5 ;
        RECT  30.624 34.368 30.648 34.56 ;
    END
  END rd_data[389]
  PIN rd_data[38]
    DIRECTION INPUT ;
    USE SIGNAL ;
    PORT
      LAYER M3 ;
        RECT  11.052 34.416 11.07 34.56 ;
    END
  END rd_data[38]
  PIN rd_data[390]
    DIRECTION INPUT ;
    USE SIGNAL ;
    PORT
      LAYER M3 ;
        RECT  30.06 34.416 30.078 34.56 ;
    END
  END rd_data[390]
  PIN rd_data[391]
    DIRECTION INPUT ;
    USE SIGNAL ;
    PORT
      LAYER M5 ;
        RECT  30.72 34.368 30.744 34.56 ;
    END
  END rd_data[391]
  PIN rd_data[392]
    DIRECTION INPUT ;
    USE SIGNAL ;
    PORT
      LAYER M3 ;
        RECT  30.168 34.416 30.186 34.56 ;
    END
  END rd_data[392]
  PIN rd_data[393]
    DIRECTION INPUT ;
    USE SIGNAL ;
    PORT
      LAYER M5 ;
        RECT  30.816 34.368 30.84 34.56 ;
    END
  END rd_data[393]
  PIN rd_data[394]
    DIRECTION INPUT ;
    USE SIGNAL ;
    PORT
      LAYER M3 ;
        RECT  30.276 34.416 30.294 34.56 ;
    END
  END rd_data[394]
  PIN rd_data[395]
    DIRECTION INPUT ;
    USE SIGNAL ;
    PORT
      LAYER M5 ;
        RECT  30.912 34.368 30.936 34.56 ;
    END
  END rd_data[395]
  PIN rd_data[396]
    DIRECTION INPUT ;
    USE SIGNAL ;
    PORT
      LAYER M3 ;
        RECT  30.384 34.416 30.402 34.56 ;
    END
  END rd_data[396]
  PIN rd_data[397]
    DIRECTION INPUT ;
    USE SIGNAL ;
    PORT
      LAYER M5 ;
        RECT  31.008 34.368 31.032 34.56 ;
    END
  END rd_data[397]
  PIN rd_data[398]
    DIRECTION INPUT ;
    USE SIGNAL ;
    PORT
      LAYER M3 ;
        RECT  30.492 34.416 30.51 34.56 ;
    END
  END rd_data[398]
  PIN rd_data[399]
    DIRECTION INPUT ;
    USE SIGNAL ;
    PORT
      LAYER M5 ;
        RECT  31.104 34.368 31.128 34.56 ;
    END
  END rd_data[399]
  PIN rd_data[39]
    DIRECTION INPUT ;
    USE SIGNAL ;
    PORT
      LAYER M5 ;
        RECT  13.824 34.368 13.848 34.56 ;
    END
  END rd_data[39]
  PIN rd_data[3]
    DIRECTION INPUT ;
    USE SIGNAL ;
    PORT
      LAYER M5 ;
        RECT  12.096 34.368 12.12 34.56 ;
    END
  END rd_data[3]
  PIN rd_data[400]
    DIRECTION INPUT ;
    USE SIGNAL ;
    PORT
      LAYER M3 ;
        RECT  30.6 34.416 30.618 34.56 ;
    END
  END rd_data[400]
  PIN rd_data[401]
    DIRECTION INPUT ;
    USE SIGNAL ;
    PORT
      LAYER M5 ;
        RECT  31.2 34.368 31.224 34.56 ;
    END
  END rd_data[401]
  PIN rd_data[402]
    DIRECTION INPUT ;
    USE SIGNAL ;
    PORT
      LAYER M3 ;
        RECT  30.708 34.416 30.726 34.56 ;
    END
  END rd_data[402]
  PIN rd_data[403]
    DIRECTION INPUT ;
    USE SIGNAL ;
    PORT
      LAYER M5 ;
        RECT  31.296 34.368 31.32 34.56 ;
    END
  END rd_data[403]
  PIN rd_data[404]
    DIRECTION INPUT ;
    USE SIGNAL ;
    PORT
      LAYER M3 ;
        RECT  30.816 34.416 30.834 34.56 ;
    END
  END rd_data[404]
  PIN rd_data[405]
    DIRECTION INPUT ;
    USE SIGNAL ;
    PORT
      LAYER M5 ;
        RECT  31.392 34.368 31.416 34.56 ;
    END
  END rd_data[405]
  PIN rd_data[406]
    DIRECTION INPUT ;
    USE SIGNAL ;
    PORT
      LAYER M3 ;
        RECT  30.924 34.416 30.942 34.56 ;
    END
  END rd_data[406]
  PIN rd_data[407]
    DIRECTION INPUT ;
    USE SIGNAL ;
    PORT
      LAYER M5 ;
        RECT  31.488 34.368 31.512 34.56 ;
    END
  END rd_data[407]
  PIN rd_data[408]
    DIRECTION INPUT ;
    USE SIGNAL ;
    PORT
      LAYER M3 ;
        RECT  31.032 34.416 31.05 34.56 ;
    END
  END rd_data[408]
  PIN rd_data[409]
    DIRECTION INPUT ;
    USE SIGNAL ;
    PORT
      LAYER M5 ;
        RECT  31.584 34.368 31.608 34.56 ;
    END
  END rd_data[409]
  PIN rd_data[40]
    DIRECTION INPUT ;
    USE SIGNAL ;
    PORT
      LAYER M3 ;
        RECT  11.16 34.416 11.178 34.56 ;
    END
  END rd_data[40]
  PIN rd_data[410]
    DIRECTION INPUT ;
    USE SIGNAL ;
    PORT
      LAYER M3 ;
        RECT  31.14 34.416 31.158 34.56 ;
    END
  END rd_data[410]
  PIN rd_data[411]
    DIRECTION INPUT ;
    USE SIGNAL ;
    PORT
      LAYER M5 ;
        RECT  31.68 34.368 31.704 34.56 ;
    END
  END rd_data[411]
  PIN rd_data[412]
    DIRECTION INPUT ;
    USE SIGNAL ;
    PORT
      LAYER M3 ;
        RECT  31.248 34.416 31.266 34.56 ;
    END
  END rd_data[412]
  PIN rd_data[413]
    DIRECTION INPUT ;
    USE SIGNAL ;
    PORT
      LAYER M5 ;
        RECT  31.776 34.368 31.8 34.56 ;
    END
  END rd_data[413]
  PIN rd_data[414]
    DIRECTION INPUT ;
    USE SIGNAL ;
    PORT
      LAYER M3 ;
        RECT  31.356 34.416 31.374 34.56 ;
    END
  END rd_data[414]
  PIN rd_data[415]
    DIRECTION INPUT ;
    USE SIGNAL ;
    PORT
      LAYER M5 ;
        RECT  31.872 34.368 31.896 34.56 ;
    END
  END rd_data[415]
  PIN rd_data[416]
    DIRECTION INPUT ;
    USE SIGNAL ;
    PORT
      LAYER M3 ;
        RECT  31.464 34.416 31.482 34.56 ;
    END
  END rd_data[416]
  PIN rd_data[417]
    DIRECTION INPUT ;
    USE SIGNAL ;
    PORT
      LAYER M5 ;
        RECT  31.968 34.368 31.992 34.56 ;
    END
  END rd_data[417]
  PIN rd_data[418]
    DIRECTION INPUT ;
    USE SIGNAL ;
    PORT
      LAYER M3 ;
        RECT  31.572 34.416 31.59 34.56 ;
    END
  END rd_data[418]
  PIN rd_data[419]
    DIRECTION INPUT ;
    USE SIGNAL ;
    PORT
      LAYER M5 ;
        RECT  32.064 34.368 32.088 34.56 ;
    END
  END rd_data[419]
  PIN rd_data[41]
    DIRECTION INPUT ;
    USE SIGNAL ;
    PORT
      LAYER M5 ;
        RECT  13.92 34.368 13.944 34.56 ;
    END
  END rd_data[41]
  PIN rd_data[420]
    DIRECTION INPUT ;
    USE SIGNAL ;
    PORT
      LAYER M3 ;
        RECT  31.68 34.416 31.698 34.56 ;
    END
  END rd_data[420]
  PIN rd_data[421]
    DIRECTION INPUT ;
    USE SIGNAL ;
    PORT
      LAYER M5 ;
        RECT  32.16 34.368 32.184 34.56 ;
    END
  END rd_data[421]
  PIN rd_data[422]
    DIRECTION INPUT ;
    USE SIGNAL ;
    PORT
      LAYER M3 ;
        RECT  31.788 34.416 31.806 34.56 ;
    END
  END rd_data[422]
  PIN rd_data[423]
    DIRECTION INPUT ;
    USE SIGNAL ;
    PORT
      LAYER M5 ;
        RECT  32.256 34.368 32.28 34.56 ;
    END
  END rd_data[423]
  PIN rd_data[424]
    DIRECTION INPUT ;
    USE SIGNAL ;
    PORT
      LAYER M3 ;
        RECT  31.896 34.416 31.914 34.56 ;
    END
  END rd_data[424]
  PIN rd_data[425]
    DIRECTION INPUT ;
    USE SIGNAL ;
    PORT
      LAYER M5 ;
        RECT  32.352 34.368 32.376 34.56 ;
    END
  END rd_data[425]
  PIN rd_data[426]
    DIRECTION INPUT ;
    USE SIGNAL ;
    PORT
      LAYER M3 ;
        RECT  32.004 34.416 32.022 34.56 ;
    END
  END rd_data[426]
  PIN rd_data[427]
    DIRECTION INPUT ;
    USE SIGNAL ;
    PORT
      LAYER M5 ;
        RECT  32.448 34.368 32.472 34.56 ;
    END
  END rd_data[427]
  PIN rd_data[428]
    DIRECTION INPUT ;
    USE SIGNAL ;
    PORT
      LAYER M3 ;
        RECT  32.112 34.416 32.13 34.56 ;
    END
  END rd_data[428]
  PIN rd_data[429]
    DIRECTION INPUT ;
    USE SIGNAL ;
    PORT
      LAYER M5 ;
        RECT  32.544 34.368 32.568 34.56 ;
    END
  END rd_data[429]
  PIN rd_data[42]
    DIRECTION INPUT ;
    USE SIGNAL ;
    PORT
      LAYER M3 ;
        RECT  11.268 34.416 11.286 34.56 ;
    END
  END rd_data[42]
  PIN rd_data[430]
    DIRECTION INPUT ;
    USE SIGNAL ;
    PORT
      LAYER M3 ;
        RECT  32.22 34.416 32.238 34.56 ;
    END
  END rd_data[430]
  PIN rd_data[431]
    DIRECTION INPUT ;
    USE SIGNAL ;
    PORT
      LAYER M5 ;
        RECT  32.64 34.368 32.664 34.56 ;
    END
  END rd_data[431]
  PIN rd_data[432]
    DIRECTION INPUT ;
    USE SIGNAL ;
    PORT
      LAYER M3 ;
        RECT  32.328 34.416 32.346 34.56 ;
    END
  END rd_data[432]
  PIN rd_data[433]
    DIRECTION INPUT ;
    USE SIGNAL ;
    PORT
      LAYER M5 ;
        RECT  32.736 34.368 32.76 34.56 ;
    END
  END rd_data[433]
  PIN rd_data[434]
    DIRECTION INPUT ;
    USE SIGNAL ;
    PORT
      LAYER M3 ;
        RECT  32.436 34.416 32.454 34.56 ;
    END
  END rd_data[434]
  PIN rd_data[435]
    DIRECTION INPUT ;
    USE SIGNAL ;
    PORT
      LAYER M5 ;
        RECT  32.832 34.368 32.856 34.56 ;
    END
  END rd_data[435]
  PIN rd_data[436]
    DIRECTION INPUT ;
    USE SIGNAL ;
    PORT
      LAYER M3 ;
        RECT  32.544 34.416 32.562 34.56 ;
    END
  END rd_data[436]
  PIN rd_data[437]
    DIRECTION INPUT ;
    USE SIGNAL ;
    PORT
      LAYER M5 ;
        RECT  32.928 34.368 32.952 34.56 ;
    END
  END rd_data[437]
  PIN rd_data[438]
    DIRECTION INPUT ;
    USE SIGNAL ;
    PORT
      LAYER M3 ;
        RECT  32.652 34.416 32.67 34.56 ;
    END
  END rd_data[438]
  PIN rd_data[439]
    DIRECTION INPUT ;
    USE SIGNAL ;
    PORT
      LAYER M5 ;
        RECT  33.024 34.368 33.048 34.56 ;
    END
  END rd_data[439]
  PIN rd_data[43]
    DIRECTION INPUT ;
    USE SIGNAL ;
    PORT
      LAYER M5 ;
        RECT  14.016 34.368 14.04 34.56 ;
    END
  END rd_data[43]
  PIN rd_data[440]
    DIRECTION INPUT ;
    USE SIGNAL ;
    PORT
      LAYER M3 ;
        RECT  32.76 34.416 32.778 34.56 ;
    END
  END rd_data[440]
  PIN rd_data[441]
    DIRECTION INPUT ;
    USE SIGNAL ;
    PORT
      LAYER M5 ;
        RECT  33.12 34.368 33.144 34.56 ;
    END
  END rd_data[441]
  PIN rd_data[442]
    DIRECTION INPUT ;
    USE SIGNAL ;
    PORT
      LAYER M3 ;
        RECT  32.868 34.416 32.886 34.56 ;
    END
  END rd_data[442]
  PIN rd_data[443]
    DIRECTION INPUT ;
    USE SIGNAL ;
    PORT
      LAYER M5 ;
        RECT  33.216 34.368 33.24 34.56 ;
    END
  END rd_data[443]
  PIN rd_data[444]
    DIRECTION INPUT ;
    USE SIGNAL ;
    PORT
      LAYER M3 ;
        RECT  32.976 34.416 32.994 34.56 ;
    END
  END rd_data[444]
  PIN rd_data[445]
    DIRECTION INPUT ;
    USE SIGNAL ;
    PORT
      LAYER M5 ;
        RECT  33.312 34.368 33.336 34.56 ;
    END
  END rd_data[445]
  PIN rd_data[446]
    DIRECTION INPUT ;
    USE SIGNAL ;
    PORT
      LAYER M3 ;
        RECT  33.084 34.416 33.102 34.56 ;
    END
  END rd_data[446]
  PIN rd_data[447]
    DIRECTION INPUT ;
    USE SIGNAL ;
    PORT
      LAYER M5 ;
        RECT  33.408 34.368 33.432 34.56 ;
    END
  END rd_data[447]
  PIN rd_data[448]
    DIRECTION INPUT ;
    USE SIGNAL ;
    PORT
      LAYER M3 ;
        RECT  33.192 34.416 33.21 34.56 ;
    END
  END rd_data[448]
  PIN rd_data[449]
    DIRECTION INPUT ;
    USE SIGNAL ;
    PORT
      LAYER M5 ;
        RECT  33.504 34.368 33.528 34.56 ;
    END
  END rd_data[449]
  PIN rd_data[44]
    DIRECTION INPUT ;
    USE SIGNAL ;
    PORT
      LAYER M3 ;
        RECT  11.376 34.416 11.394 34.56 ;
    END
  END rd_data[44]
  PIN rd_data[450]
    DIRECTION INPUT ;
    USE SIGNAL ;
    PORT
      LAYER M3 ;
        RECT  33.3 34.416 33.318 34.56 ;
    END
  END rd_data[450]
  PIN rd_data[451]
    DIRECTION INPUT ;
    USE SIGNAL ;
    PORT
      LAYER M5 ;
        RECT  33.6 34.368 33.624 34.56 ;
    END
  END rd_data[451]
  PIN rd_data[452]
    DIRECTION INPUT ;
    USE SIGNAL ;
    PORT
      LAYER M3 ;
        RECT  33.408 34.416 33.426 34.56 ;
    END
  END rd_data[452]
  PIN rd_data[453]
    DIRECTION INPUT ;
    USE SIGNAL ;
    PORT
      LAYER M5 ;
        RECT  33.696 34.368 33.72 34.56 ;
    END
  END rd_data[453]
  PIN rd_data[454]
    DIRECTION INPUT ;
    USE SIGNAL ;
    PORT
      LAYER M3 ;
        RECT  33.516 34.416 33.534 34.56 ;
    END
  END rd_data[454]
  PIN rd_data[455]
    DIRECTION INPUT ;
    USE SIGNAL ;
    PORT
      LAYER M5 ;
        RECT  33.792 34.368 33.816 34.56 ;
    END
  END rd_data[455]
  PIN rd_data[456]
    DIRECTION INPUT ;
    USE SIGNAL ;
    PORT
      LAYER M3 ;
        RECT  33.624 34.416 33.642 34.56 ;
    END
  END rd_data[456]
  PIN rd_data[457]
    DIRECTION INPUT ;
    USE SIGNAL ;
    PORT
      LAYER M5 ;
        RECT  33.888 34.368 33.912 34.56 ;
    END
  END rd_data[457]
  PIN rd_data[458]
    DIRECTION INPUT ;
    USE SIGNAL ;
    PORT
      LAYER M3 ;
        RECT  33.732 34.416 33.75 34.56 ;
    END
  END rd_data[458]
  PIN rd_data[459]
    DIRECTION INPUT ;
    USE SIGNAL ;
    PORT
      LAYER M5 ;
        RECT  33.984 34.368 34.008 34.56 ;
    END
  END rd_data[459]
  PIN rd_data[45]
    DIRECTION INPUT ;
    USE SIGNAL ;
    PORT
      LAYER M5 ;
        RECT  14.112 34.368 14.136 34.56 ;
    END
  END rd_data[45]
  PIN rd_data[460]
    DIRECTION INPUT ;
    USE SIGNAL ;
    PORT
      LAYER M3 ;
        RECT  33.84 34.416 33.858 34.56 ;
    END
  END rd_data[460]
  PIN rd_data[461]
    DIRECTION INPUT ;
    USE SIGNAL ;
    PORT
      LAYER M5 ;
        RECT  34.08 34.368 34.104 34.56 ;
    END
  END rd_data[461]
  PIN rd_data[462]
    DIRECTION INPUT ;
    USE SIGNAL ;
    PORT
      LAYER M3 ;
        RECT  33.948 34.416 33.966 34.56 ;
    END
  END rd_data[462]
  PIN rd_data[463]
    DIRECTION INPUT ;
    USE SIGNAL ;
    PORT
      LAYER M5 ;
        RECT  34.176 34.368 34.2 34.56 ;
    END
  END rd_data[463]
  PIN rd_data[464]
    DIRECTION INPUT ;
    USE SIGNAL ;
    PORT
      LAYER M3 ;
        RECT  34.056 34.416 34.074 34.56 ;
    END
  END rd_data[464]
  PIN rd_data[465]
    DIRECTION INPUT ;
    USE SIGNAL ;
    PORT
      LAYER M5 ;
        RECT  34.272 34.368 34.296 34.56 ;
    END
  END rd_data[465]
  PIN rd_data[466]
    DIRECTION INPUT ;
    USE SIGNAL ;
    PORT
      LAYER M3 ;
        RECT  34.164 34.416 34.182 34.56 ;
    END
  END rd_data[466]
  PIN rd_data[467]
    DIRECTION INPUT ;
    USE SIGNAL ;
    PORT
      LAYER M5 ;
        RECT  34.368 34.368 34.392 34.56 ;
    END
  END rd_data[467]
  PIN rd_data[468]
    DIRECTION INPUT ;
    USE SIGNAL ;
    PORT
      LAYER M3 ;
        RECT  34.272 34.416 34.29 34.56 ;
    END
  END rd_data[468]
  PIN rd_data[469]
    DIRECTION INPUT ;
    USE SIGNAL ;
    PORT
      LAYER M5 ;
        RECT  34.464 34.368 34.488 34.56 ;
    END
  END rd_data[469]
  PIN rd_data[46]
    DIRECTION INPUT ;
    USE SIGNAL ;
    PORT
      LAYER M3 ;
        RECT  11.484 34.416 11.502 34.56 ;
    END
  END rd_data[46]
  PIN rd_data[470]
    DIRECTION INPUT ;
    USE SIGNAL ;
    PORT
      LAYER M3 ;
        RECT  34.38 34.416 34.398 34.56 ;
    END
  END rd_data[470]
  PIN rd_data[471]
    DIRECTION INPUT ;
    USE SIGNAL ;
    PORT
      LAYER M5 ;
        RECT  34.56 34.368 34.584 34.56 ;
    END
  END rd_data[471]
  PIN rd_data[472]
    DIRECTION INPUT ;
    USE SIGNAL ;
    PORT
      LAYER M3 ;
        RECT  34.488 34.416 34.506 34.56 ;
    END
  END rd_data[472]
  PIN rd_data[473]
    DIRECTION INPUT ;
    USE SIGNAL ;
    PORT
      LAYER M5 ;
        RECT  34.656 34.368 34.68 34.56 ;
    END
  END rd_data[473]
  PIN rd_data[474]
    DIRECTION INPUT ;
    USE SIGNAL ;
    PORT
      LAYER M3 ;
        RECT  34.596 34.416 34.614 34.56 ;
    END
  END rd_data[474]
  PIN rd_data[475]
    DIRECTION INPUT ;
    USE SIGNAL ;
    PORT
      LAYER M5 ;
        RECT  34.752 34.368 34.776 34.56 ;
    END
  END rd_data[475]
  PIN rd_data[476]
    DIRECTION INPUT ;
    USE SIGNAL ;
    PORT
      LAYER M3 ;
        RECT  34.704 34.416 34.722 34.56 ;
    END
  END rd_data[476]
  PIN rd_data[477]
    DIRECTION INPUT ;
    USE SIGNAL ;
    PORT
      LAYER M5 ;
        RECT  34.848 34.368 34.872 34.56 ;
    END
  END rd_data[477]
  PIN rd_data[478]
    DIRECTION INPUT ;
    USE SIGNAL ;
    PORT
      LAYER M3 ;
        RECT  34.812 34.416 34.83 34.56 ;
    END
    PORT
      LAYER M3 ;
        RECT  34.776 34.428 34.902 34.529 ;
    END
  END rd_data[478]
  PIN rd_data[479]
    DIRECTION INPUT ;
    USE SIGNAL ;
    PORT
      LAYER M5 ;
        RECT  34.944 34.368 34.968 34.56 ;
    END
  END rd_data[479]
  PIN rd_data[47]
    DIRECTION INPUT ;
    USE SIGNAL ;
    PORT
      LAYER M5 ;
        RECT  14.208 34.368 14.232 34.56 ;
    END
  END rd_data[47]
  PIN rd_data[480]
    DIRECTION INPUT ;
    USE SIGNAL ;
    PORT
      LAYER M3 ;
        RECT  34.92 34.416 34.938 34.56 ;
    END
  END rd_data[480]
  PIN rd_data[481]
    DIRECTION INPUT ;
    USE SIGNAL ;
    PORT
      LAYER M5 ;
        RECT  35.04 34.368 35.064 34.56 ;
    END
  END rd_data[481]
  PIN rd_data[482]
    DIRECTION INPUT ;
    USE SIGNAL ;
    PORT
      LAYER M3 ;
        RECT  35.028 34.416 35.046 34.56 ;
    END
  END rd_data[482]
  PIN rd_data[483]
    DIRECTION INPUT ;
    USE SIGNAL ;
    PORT
      LAYER M5 ;
        RECT  35.136 34.368 35.16 34.56 ;
    END
  END rd_data[483]
  PIN rd_data[484]
    DIRECTION INPUT ;
    USE SIGNAL ;
    PORT
      LAYER M3 ;
        RECT  35.136 34.416 35.154 34.56 ;
    END
  END rd_data[484]
  PIN rd_data[485]
    DIRECTION INPUT ;
    USE SIGNAL ;
    PORT
      LAYER M5 ;
        RECT  35.232 34.368 35.256 34.56 ;
    END
  END rd_data[485]
  PIN rd_data[486]
    DIRECTION INPUT ;
    USE SIGNAL ;
    PORT
      LAYER M3 ;
        RECT  35.244 34.416 35.262 34.56 ;
    END
  END rd_data[486]
  PIN rd_data[487]
    DIRECTION INPUT ;
    USE SIGNAL ;
    PORT
      LAYER M5 ;
        RECT  35.328 34.368 35.352 34.56 ;
    END
  END rd_data[487]
  PIN rd_data[488]
    DIRECTION INPUT ;
    USE SIGNAL ;
    PORT
      LAYER M3 ;
        RECT  35.352 34.416 35.37 34.56 ;
    END
  END rd_data[488]
  PIN rd_data[489]
    DIRECTION INPUT ;
    USE SIGNAL ;
    PORT
      LAYER M5 ;
        RECT  35.424 34.368 35.448 34.56 ;
    END
  END rd_data[489]
  PIN rd_data[48]
    DIRECTION INPUT ;
    USE SIGNAL ;
    PORT
      LAYER M3 ;
        RECT  11.592 34.416 11.61 34.56 ;
    END
  END rd_data[48]
  PIN rd_data[490]
    DIRECTION INPUT ;
    USE SIGNAL ;
    PORT
      LAYER M3 ;
        RECT  35.46 34.416 35.478 34.56 ;
    END
  END rd_data[490]
  PIN rd_data[491]
    DIRECTION INPUT ;
    USE SIGNAL ;
    PORT
      LAYER M5 ;
        RECT  35.52 34.368 35.544 34.56 ;
    END
  END rd_data[491]
  PIN rd_data[492]
    DIRECTION INPUT ;
    USE SIGNAL ;
    PORT
      LAYER M3 ;
        RECT  35.568 34.416 35.586 34.56 ;
    END
  END rd_data[492]
  PIN rd_data[493]
    DIRECTION INPUT ;
    USE SIGNAL ;
    PORT
      LAYER M5 ;
        RECT  35.616 34.368 35.64 34.56 ;
    END
  END rd_data[493]
  PIN rd_data[494]
    DIRECTION INPUT ;
    USE SIGNAL ;
    PORT
      LAYER M3 ;
        RECT  35.676 34.416 35.694 34.56 ;
    END
  END rd_data[494]
  PIN rd_data[495]
    DIRECTION INPUT ;
    USE SIGNAL ;
    PORT
      LAYER M5 ;
        RECT  35.712 34.368 35.736 34.56 ;
    END
  END rd_data[495]
  PIN rd_data[496]
    DIRECTION INPUT ;
    USE SIGNAL ;
    PORT
      LAYER M3 ;
        RECT  35.784 34.416 35.802 34.56 ;
    END
  END rd_data[496]
  PIN rd_data[497]
    DIRECTION INPUT ;
    USE SIGNAL ;
    PORT
      LAYER M5 ;
        RECT  35.808 34.368 35.832 34.56 ;
    END
  END rd_data[497]
  PIN rd_data[498]
    DIRECTION INPUT ;
    USE SIGNAL ;
    PORT
      LAYER M3 ;
        RECT  35.892 34.416 35.91 34.56 ;
    END
  END rd_data[498]
  PIN rd_data[499]
    DIRECTION INPUT ;
    USE SIGNAL ;
    PORT
      LAYER M5 ;
        RECT  35.904 34.368 35.928 34.56 ;
    END
  END rd_data[499]
  PIN rd_data[49]
    DIRECTION INPUT ;
    USE SIGNAL ;
    PORT
      LAYER M5 ;
        RECT  14.304 34.368 14.328 34.56 ;
    END
  END rd_data[49]
  PIN rd_data[4]
    DIRECTION INPUT ;
    USE SIGNAL ;
    PORT
      LAYER M3 ;
        RECT  9.216 34.416 9.234 34.56 ;
    END
  END rd_data[4]
  PIN rd_data[500]
    DIRECTION INPUT ;
    USE SIGNAL ;
    PORT
      LAYER M3 ;
        RECT  36 34.416 36.018 34.56 ;
    END
  END rd_data[500]
  PIN rd_data[501]
    DIRECTION INPUT ;
    USE SIGNAL ;
    PORT
      LAYER M5 ;
        RECT  36 34.368 36.024 34.56 ;
    END
  END rd_data[501]
  PIN rd_data[502]
    DIRECTION INPUT ;
    USE SIGNAL ;
    PORT
      LAYER M3 ;
        RECT  36.108 34.416 36.126 34.56 ;
    END
  END rd_data[502]
  PIN rd_data[503]
    DIRECTION INPUT ;
    USE SIGNAL ;
    PORT
      LAYER M5 ;
        RECT  36.096 34.368 36.12 34.56 ;
    END
  END rd_data[503]
  PIN rd_data[504]
    DIRECTION INPUT ;
    USE SIGNAL ;
    PORT
      LAYER M3 ;
        RECT  36.216 34.416 36.234 34.56 ;
    END
  END rd_data[504]
  PIN rd_data[505]
    DIRECTION INPUT ;
    USE SIGNAL ;
    PORT
      LAYER M5 ;
        RECT  36.192 34.368 36.216 34.56 ;
    END
  END rd_data[505]
  PIN rd_data[506]
    DIRECTION INPUT ;
    USE SIGNAL ;
    PORT
      LAYER M3 ;
        RECT  36.324 34.416 36.342 34.56 ;
    END
  END rd_data[506]
  PIN rd_data[507]
    DIRECTION INPUT ;
    USE SIGNAL ;
    PORT
      LAYER M5 ;
        RECT  36.288 34.368 36.312 34.56 ;
    END
  END rd_data[507]
  PIN rd_data[508]
    DIRECTION INPUT ;
    USE SIGNAL ;
    PORT
      LAYER M3 ;
        RECT  36.432 34.416 36.45 34.56 ;
    END
  END rd_data[508]
  PIN rd_data[509]
    DIRECTION INPUT ;
    USE SIGNAL ;
    PORT
      LAYER M5 ;
        RECT  36.384 34.368 36.408 34.56 ;
    END
  END rd_data[509]
  PIN rd_data[50]
    DIRECTION INPUT ;
    USE SIGNAL ;
    PORT
      LAYER M3 ;
        RECT  11.7 34.416 11.718 34.56 ;
    END
  END rd_data[50]
  PIN rd_data[510]
    DIRECTION INPUT ;
    USE SIGNAL ;
    PORT
      LAYER M3 ;
        RECT  36.54 34.416 36.558 34.56 ;
    END
  END rd_data[510]
  PIN rd_data[511]
    DIRECTION INPUT ;
    USE SIGNAL ;
    PORT
      LAYER M5 ;
        RECT  36.48 34.368 36.504 34.56 ;
    END
  END rd_data[511]
  PIN rd_data[512]
    DIRECTION INPUT ;
    USE SIGNAL ;
    PORT
      LAYER M3 ;
        RECT  36.648 34.416 36.666 34.56 ;
    END
  END rd_data[512]
  PIN rd_data[513]
    DIRECTION INPUT ;
    USE SIGNAL ;
    PORT
      LAYER M5 ;
        RECT  36.576 34.368 36.6 34.56 ;
    END
  END rd_data[513]
  PIN rd_data[514]
    DIRECTION INPUT ;
    USE SIGNAL ;
    PORT
      LAYER M3 ;
        RECT  36.756 34.416 36.774 34.56 ;
    END
  END rd_data[514]
  PIN rd_data[515]
    DIRECTION INPUT ;
    USE SIGNAL ;
    PORT
      LAYER M5 ;
        RECT  36.672 34.368 36.696 34.56 ;
    END
  END rd_data[515]
  PIN rd_data[516]
    DIRECTION INPUT ;
    USE SIGNAL ;
    PORT
      LAYER M3 ;
        RECT  36.864 34.416 36.882 34.56 ;
    END
  END rd_data[516]
  PIN rd_data[517]
    DIRECTION INPUT ;
    USE SIGNAL ;
    PORT
      LAYER M5 ;
        RECT  36.768 34.368 36.792 34.56 ;
    END
  END rd_data[517]
  PIN rd_data[518]
    DIRECTION INPUT ;
    USE SIGNAL ;
    PORT
      LAYER M3 ;
        RECT  36.972 34.416 36.99 34.56 ;
    END
  END rd_data[518]
  PIN rd_data[519]
    DIRECTION INPUT ;
    USE SIGNAL ;
    PORT
      LAYER M5 ;
        RECT  36.864 34.368 36.888 34.56 ;
    END
  END rd_data[519]
  PIN rd_data[51]
    DIRECTION INPUT ;
    USE SIGNAL ;
    PORT
      LAYER M5 ;
        RECT  14.4 34.368 14.424 34.56 ;
    END
  END rd_data[51]
  PIN rd_data[520]
    DIRECTION INPUT ;
    USE SIGNAL ;
    PORT
      LAYER M3 ;
        RECT  37.08 34.416 37.098 34.56 ;
    END
  END rd_data[520]
  PIN rd_data[521]
    DIRECTION INPUT ;
    USE SIGNAL ;
    PORT
      LAYER M5 ;
        RECT  36.96 34.368 36.984 34.56 ;
    END
  END rd_data[521]
  PIN rd_data[522]
    DIRECTION INPUT ;
    USE SIGNAL ;
    PORT
      LAYER M3 ;
        RECT  37.188 34.416 37.206 34.56 ;
    END
  END rd_data[522]
  PIN rd_data[523]
    DIRECTION INPUT ;
    USE SIGNAL ;
    PORT
      LAYER M5 ;
        RECT  37.056 34.368 37.08 34.56 ;
    END
  END rd_data[523]
  PIN rd_data[524]
    DIRECTION INPUT ;
    USE SIGNAL ;
    PORT
      LAYER M3 ;
        RECT  37.296 34.416 37.314 34.56 ;
    END
  END rd_data[524]
  PIN rd_data[525]
    DIRECTION INPUT ;
    USE SIGNAL ;
    PORT
      LAYER M5 ;
        RECT  37.152 34.368 37.176 34.56 ;
    END
  END rd_data[525]
  PIN rd_data[526]
    DIRECTION INPUT ;
    USE SIGNAL ;
    PORT
      LAYER M3 ;
        RECT  37.404 34.416 37.422 34.56 ;
    END
  END rd_data[526]
  PIN rd_data[527]
    DIRECTION INPUT ;
    USE SIGNAL ;
    PORT
      LAYER M5 ;
        RECT  37.248 34.368 37.272 34.56 ;
    END
  END rd_data[527]
  PIN rd_data[528]
    DIRECTION INPUT ;
    USE SIGNAL ;
    PORT
      LAYER M3 ;
        RECT  37.512 34.416 37.53 34.56 ;
    END
  END rd_data[528]
  PIN rd_data[529]
    DIRECTION INPUT ;
    USE SIGNAL ;
    PORT
      LAYER M5 ;
        RECT  37.344 34.368 37.368 34.56 ;
    END
  END rd_data[529]
  PIN rd_data[52]
    DIRECTION INPUT ;
    USE SIGNAL ;
    PORT
      LAYER M3 ;
        RECT  11.808 34.416 11.826 34.56 ;
    END
  END rd_data[52]
  PIN rd_data[530]
    DIRECTION INPUT ;
    USE SIGNAL ;
    PORT
      LAYER M3 ;
        RECT  37.62 34.416 37.638 34.56 ;
    END
  END rd_data[530]
  PIN rd_data[531]
    DIRECTION INPUT ;
    USE SIGNAL ;
    PORT
      LAYER M5 ;
        RECT  37.44 34.368 37.464 34.56 ;
    END
  END rd_data[531]
  PIN rd_data[532]
    DIRECTION INPUT ;
    USE SIGNAL ;
    PORT
      LAYER M3 ;
        RECT  37.728 34.416 37.746 34.56 ;
    END
  END rd_data[532]
  PIN rd_data[533]
    DIRECTION INPUT ;
    USE SIGNAL ;
    PORT
      LAYER M5 ;
        RECT  37.536 34.368 37.56 34.56 ;
    END
  END rd_data[533]
  PIN rd_data[534]
    DIRECTION INPUT ;
    USE SIGNAL ;
    PORT
      LAYER M3 ;
        RECT  37.836 34.416 37.854 34.56 ;
    END
  END rd_data[534]
  PIN rd_data[535]
    DIRECTION INPUT ;
    USE SIGNAL ;
    PORT
      LAYER M5 ;
        RECT  37.632 34.368 37.656 34.56 ;
    END
  END rd_data[535]
  PIN rd_data[536]
    DIRECTION INPUT ;
    USE SIGNAL ;
    PORT
      LAYER M3 ;
        RECT  37.944 34.416 37.962 34.56 ;
    END
  END rd_data[536]
  PIN rd_data[537]
    DIRECTION INPUT ;
    USE SIGNAL ;
    PORT
      LAYER M5 ;
        RECT  37.728 34.368 37.752 34.56 ;
    END
  END rd_data[537]
  PIN rd_data[538]
    DIRECTION INPUT ;
    USE SIGNAL ;
    PORT
      LAYER M3 ;
        RECT  38.052 34.416 38.07 34.56 ;
    END
  END rd_data[538]
  PIN rd_data[539]
    DIRECTION INPUT ;
    USE SIGNAL ;
    PORT
      LAYER M5 ;
        RECT  37.824 34.368 37.848 34.56 ;
    END
  END rd_data[539]
  PIN rd_data[53]
    DIRECTION INPUT ;
    USE SIGNAL ;
    PORT
      LAYER M5 ;
        RECT  14.496 34.368 14.52 34.56 ;
    END
  END rd_data[53]
  PIN rd_data[540]
    DIRECTION INPUT ;
    USE SIGNAL ;
    PORT
      LAYER M3 ;
        RECT  38.16 34.416 38.178 34.56 ;
    END
  END rd_data[540]
  PIN rd_data[541]
    DIRECTION INPUT ;
    USE SIGNAL ;
    PORT
      LAYER M5 ;
        RECT  37.92 34.368 37.944 34.56 ;
    END
  END rd_data[541]
  PIN rd_data[542]
    DIRECTION INPUT ;
    USE SIGNAL ;
    PORT
      LAYER M3 ;
        RECT  38.268 34.416 38.286 34.56 ;
    END
  END rd_data[542]
  PIN rd_data[543]
    DIRECTION INPUT ;
    USE SIGNAL ;
    PORT
      LAYER M5 ;
        RECT  38.016 34.368 38.04 34.56 ;
    END
  END rd_data[543]
  PIN rd_data[544]
    DIRECTION INPUT ;
    USE SIGNAL ;
    PORT
      LAYER M3 ;
        RECT  38.376 34.416 38.394 34.56 ;
    END
  END rd_data[544]
  PIN rd_data[545]
    DIRECTION INPUT ;
    USE SIGNAL ;
    PORT
      LAYER M5 ;
        RECT  38.112 34.368 38.136 34.56 ;
    END
  END rd_data[545]
  PIN rd_data[546]
    DIRECTION INPUT ;
    USE SIGNAL ;
    PORT
      LAYER M3 ;
        RECT  38.484 34.416 38.502 34.56 ;
    END
  END rd_data[546]
  PIN rd_data[547]
    DIRECTION INPUT ;
    USE SIGNAL ;
    PORT
      LAYER M5 ;
        RECT  38.208 34.368 38.232 34.56 ;
    END
  END rd_data[547]
  PIN rd_data[548]
    DIRECTION INPUT ;
    USE SIGNAL ;
    PORT
      LAYER M3 ;
        RECT  38.592 34.416 38.61 34.56 ;
    END
  END rd_data[548]
  PIN rd_data[549]
    DIRECTION INPUT ;
    USE SIGNAL ;
    PORT
      LAYER M5 ;
        RECT  38.304 34.368 38.328 34.56 ;
    END
  END rd_data[549]
  PIN rd_data[54]
    DIRECTION INPUT ;
    USE SIGNAL ;
    PORT
      LAYER M3 ;
        RECT  11.916 34.416 11.934 34.56 ;
    END
  END rd_data[54]
  PIN rd_data[550]
    DIRECTION INPUT ;
    USE SIGNAL ;
    PORT
      LAYER M3 ;
        RECT  38.7 34.416 38.718 34.56 ;
    END
  END rd_data[550]
  PIN rd_data[551]
    DIRECTION INPUT ;
    USE SIGNAL ;
    PORT
      LAYER M5 ;
        RECT  38.4 34.368 38.424 34.56 ;
    END
  END rd_data[551]
  PIN rd_data[552]
    DIRECTION INPUT ;
    USE SIGNAL ;
    PORT
      LAYER M3 ;
        RECT  38.808 34.416 38.826 34.56 ;
    END
  END rd_data[552]
  PIN rd_data[553]
    DIRECTION INPUT ;
    USE SIGNAL ;
    PORT
      LAYER M5 ;
        RECT  38.496 34.368 38.52 34.56 ;
    END
  END rd_data[553]
  PIN rd_data[554]
    DIRECTION INPUT ;
    USE SIGNAL ;
    PORT
      LAYER M3 ;
        RECT  38.916 34.416 38.934 34.56 ;
    END
  END rd_data[554]
  PIN rd_data[555]
    DIRECTION INPUT ;
    USE SIGNAL ;
    PORT
      LAYER M5 ;
        RECT  38.592 34.368 38.616 34.56 ;
    END
  END rd_data[555]
  PIN rd_data[556]
    DIRECTION INPUT ;
    USE SIGNAL ;
    PORT
      LAYER M3 ;
        RECT  39.024 34.416 39.042 34.56 ;
    END
  END rd_data[556]
  PIN rd_data[557]
    DIRECTION INPUT ;
    USE SIGNAL ;
    PORT
      LAYER M5 ;
        RECT  38.688 34.368 38.712 34.56 ;
    END
  END rd_data[557]
  PIN rd_data[558]
    DIRECTION INPUT ;
    USE SIGNAL ;
    PORT
      LAYER M3 ;
        RECT  39.132 34.416 39.15 34.56 ;
    END
  END rd_data[558]
  PIN rd_data[559]
    DIRECTION INPUT ;
    USE SIGNAL ;
    PORT
      LAYER M5 ;
        RECT  38.784 34.368 38.808 34.56 ;
    END
  END rd_data[559]
  PIN rd_data[55]
    DIRECTION INPUT ;
    USE SIGNAL ;
    PORT
      LAYER M5 ;
        RECT  14.592 34.368 14.616 34.56 ;
    END
  END rd_data[55]
  PIN rd_data[560]
    DIRECTION INPUT ;
    USE SIGNAL ;
    PORT
      LAYER M3 ;
        RECT  39.24 34.416 39.258 34.56 ;
    END
  END rd_data[560]
  PIN rd_data[561]
    DIRECTION INPUT ;
    USE SIGNAL ;
    PORT
      LAYER M5 ;
        RECT  38.88 34.368 38.904 34.56 ;
    END
  END rd_data[561]
  PIN rd_data[562]
    DIRECTION INPUT ;
    USE SIGNAL ;
    PORT
      LAYER M3 ;
        RECT  39.348 34.416 39.366 34.56 ;
    END
  END rd_data[562]
  PIN rd_data[563]
    DIRECTION INPUT ;
    USE SIGNAL ;
    PORT
      LAYER M5 ;
        RECT  38.976 34.368 39 34.56 ;
    END
  END rd_data[563]
  PIN rd_data[564]
    DIRECTION INPUT ;
    USE SIGNAL ;
    PORT
      LAYER M3 ;
        RECT  39.456 34.416 39.474 34.56 ;
    END
  END rd_data[564]
  PIN rd_data[565]
    DIRECTION INPUT ;
    USE SIGNAL ;
    PORT
      LAYER M5 ;
        RECT  39.072 34.368 39.096 34.56 ;
    END
  END rd_data[565]
  PIN rd_data[566]
    DIRECTION INPUT ;
    USE SIGNAL ;
    PORT
      LAYER M3 ;
        RECT  39.564 34.416 39.582 34.56 ;
    END
  END rd_data[566]
  PIN rd_data[567]
    DIRECTION INPUT ;
    USE SIGNAL ;
    PORT
      LAYER M5 ;
        RECT  39.168 34.368 39.192 34.56 ;
    END
  END rd_data[567]
  PIN rd_data[568]
    DIRECTION INPUT ;
    USE SIGNAL ;
    PORT
      LAYER M3 ;
        RECT  39.672 34.416 39.69 34.56 ;
    END
  END rd_data[568]
  PIN rd_data[569]
    DIRECTION INPUT ;
    USE SIGNAL ;
    PORT
      LAYER M5 ;
        RECT  39.264 34.368 39.288 34.56 ;
    END
  END rd_data[569]
  PIN rd_data[56]
    DIRECTION INPUT ;
    USE SIGNAL ;
    PORT
      LAYER M3 ;
        RECT  12.024 34.416 12.042 34.56 ;
    END
  END rd_data[56]
  PIN rd_data[570]
    DIRECTION INPUT ;
    USE SIGNAL ;
    PORT
      LAYER M3 ;
        RECT  39.78 34.416 39.798 34.56 ;
    END
  END rd_data[570]
  PIN rd_data[571]
    DIRECTION INPUT ;
    USE SIGNAL ;
    PORT
      LAYER M5 ;
        RECT  39.36 34.368 39.384 34.56 ;
    END
  END rd_data[571]
  PIN rd_data[572]
    DIRECTION INPUT ;
    USE SIGNAL ;
    PORT
      LAYER M3 ;
        RECT  39.888 34.416 39.906 34.56 ;
    END
  END rd_data[572]
  PIN rd_data[573]
    DIRECTION INPUT ;
    USE SIGNAL ;
    PORT
      LAYER M5 ;
        RECT  39.456 34.368 39.48 34.56 ;
    END
  END rd_data[573]
  PIN rd_data[574]
    DIRECTION INPUT ;
    USE SIGNAL ;
    PORT
      LAYER M3 ;
        RECT  39.996 34.416 40.014 34.56 ;
    END
  END rd_data[574]
  PIN rd_data[575]
    DIRECTION INPUT ;
    USE SIGNAL ;
    PORT
      LAYER M5 ;
        RECT  39.552 34.368 39.576 34.56 ;
    END
  END rd_data[575]
  PIN rd_data[576]
    DIRECTION INPUT ;
    USE SIGNAL ;
    PORT
      LAYER M3 ;
        RECT  40.104 34.416 40.122 34.56 ;
    END
  END rd_data[576]
  PIN rd_data[577]
    DIRECTION INPUT ;
    USE SIGNAL ;
    PORT
      LAYER M5 ;
        RECT  39.648 34.368 39.672 34.56 ;
    END
  END rd_data[577]
  PIN rd_data[578]
    DIRECTION INPUT ;
    USE SIGNAL ;
    PORT
      LAYER M3 ;
        RECT  40.212 34.416 40.23 34.56 ;
    END
  END rd_data[578]
  PIN rd_data[579]
    DIRECTION INPUT ;
    USE SIGNAL ;
    PORT
      LAYER M5 ;
        RECT  39.744 34.368 39.768 34.56 ;
    END
  END rd_data[579]
  PIN rd_data[57]
    DIRECTION INPUT ;
    USE SIGNAL ;
    PORT
      LAYER M5 ;
        RECT  14.688 34.368 14.712 34.56 ;
    END
  END rd_data[57]
  PIN rd_data[580]
    DIRECTION INPUT ;
    USE SIGNAL ;
    PORT
      LAYER M3 ;
        RECT  40.32 34.416 40.338 34.56 ;
    END
  END rd_data[580]
  PIN rd_data[581]
    DIRECTION INPUT ;
    USE SIGNAL ;
    PORT
      LAYER M5 ;
        RECT  39.84 34.368 39.864 34.56 ;
    END
  END rd_data[581]
  PIN rd_data[582]
    DIRECTION INPUT ;
    USE SIGNAL ;
    PORT
      LAYER M3 ;
        RECT  40.428 34.416 40.446 34.56 ;
    END
  END rd_data[582]
  PIN rd_data[583]
    DIRECTION INPUT ;
    USE SIGNAL ;
    PORT
      LAYER M5 ;
        RECT  39.936 34.368 39.96 34.56 ;
    END
  END rd_data[583]
  PIN rd_data[584]
    DIRECTION INPUT ;
    USE SIGNAL ;
    PORT
      LAYER M3 ;
        RECT  40.536 34.416 40.554 34.56 ;
    END
  END rd_data[584]
  PIN rd_data[585]
    DIRECTION INPUT ;
    USE SIGNAL ;
    PORT
      LAYER M5 ;
        RECT  40.032 34.368 40.056 34.56 ;
    END
  END rd_data[585]
  PIN rd_data[586]
    DIRECTION INPUT ;
    USE SIGNAL ;
    PORT
      LAYER M3 ;
        RECT  40.644 34.416 40.662 34.56 ;
    END
  END rd_data[586]
  PIN rd_data[587]
    DIRECTION INPUT ;
    USE SIGNAL ;
    PORT
      LAYER M5 ;
        RECT  40.128 34.368 40.152 34.56 ;
    END
  END rd_data[587]
  PIN rd_data[588]
    DIRECTION INPUT ;
    USE SIGNAL ;
    PORT
      LAYER M3 ;
        RECT  40.752 34.416 40.77 34.56 ;
    END
  END rd_data[588]
  PIN rd_data[589]
    DIRECTION INPUT ;
    USE SIGNAL ;
    PORT
      LAYER M5 ;
        RECT  40.224 34.368 40.248 34.56 ;
    END
  END rd_data[589]
  PIN rd_data[58]
    DIRECTION INPUT ;
    USE SIGNAL ;
    PORT
      LAYER M3 ;
        RECT  12.132 34.416 12.15 34.56 ;
    END
  END rd_data[58]
  PIN rd_data[590]
    DIRECTION INPUT ;
    USE SIGNAL ;
    PORT
      LAYER M3 ;
        RECT  40.86 34.416 40.878 34.56 ;
    END
  END rd_data[590]
  PIN rd_data[591]
    DIRECTION INPUT ;
    USE SIGNAL ;
    PORT
      LAYER M5 ;
        RECT  40.32 34.368 40.344 34.56 ;
    END
  END rd_data[591]
  PIN rd_data[592]
    DIRECTION INPUT ;
    USE SIGNAL ;
    PORT
      LAYER M3 ;
        RECT  40.968 34.416 40.986 34.56 ;
    END
  END rd_data[592]
  PIN rd_data[593]
    DIRECTION INPUT ;
    USE SIGNAL ;
    PORT
      LAYER M5 ;
        RECT  40.416 34.368 40.44 34.56 ;
    END
  END rd_data[593]
  PIN rd_data[594]
    DIRECTION INPUT ;
    USE SIGNAL ;
    PORT
      LAYER M3 ;
        RECT  41.076 34.416 41.094 34.56 ;
    END
  END rd_data[594]
  PIN rd_data[595]
    DIRECTION INPUT ;
    USE SIGNAL ;
    PORT
      LAYER M5 ;
        RECT  40.512 34.368 40.536 34.56 ;
    END
  END rd_data[595]
  PIN rd_data[596]
    DIRECTION INPUT ;
    USE SIGNAL ;
    PORT
      LAYER M3 ;
        RECT  41.184 34.416 41.202 34.56 ;
    END
  END rd_data[596]
  PIN rd_data[597]
    DIRECTION INPUT ;
    USE SIGNAL ;
    PORT
      LAYER M5 ;
        RECT  40.608 34.368 40.632 34.56 ;
    END
  END rd_data[597]
  PIN rd_data[598]
    DIRECTION INPUT ;
    USE SIGNAL ;
    PORT
      LAYER M3 ;
        RECT  41.292 34.416 41.31 34.56 ;
    END
  END rd_data[598]
  PIN rd_data[599]
    DIRECTION INPUT ;
    USE SIGNAL ;
    PORT
      LAYER M5 ;
        RECT  40.704 34.368 40.728 34.56 ;
    END
  END rd_data[599]
  PIN rd_data[59]
    DIRECTION INPUT ;
    USE SIGNAL ;
    PORT
      LAYER M5 ;
        RECT  14.784 34.368 14.808 34.56 ;
    END
  END rd_data[59]
  PIN rd_data[5]
    DIRECTION INPUT ;
    USE SIGNAL ;
    PORT
      LAYER M5 ;
        RECT  12.192 34.368 12.216 34.56 ;
    END
  END rd_data[5]
  PIN rd_data[600]
    DIRECTION INPUT ;
    USE SIGNAL ;
    PORT
      LAYER M3 ;
        RECT  41.4 34.416 41.418 34.56 ;
    END
  END rd_data[600]
  PIN rd_data[601]
    DIRECTION INPUT ;
    USE SIGNAL ;
    PORT
      LAYER M5 ;
        RECT  40.8 34.368 40.824 34.56 ;
    END
  END rd_data[601]
  PIN rd_data[602]
    DIRECTION INPUT ;
    USE SIGNAL ;
    PORT
      LAYER M3 ;
        RECT  41.508 34.416 41.526 34.56 ;
    END
  END rd_data[602]
  PIN rd_data[603]
    DIRECTION INPUT ;
    USE SIGNAL ;
    PORT
      LAYER M5 ;
        RECT  40.896 34.368 40.92 34.56 ;
    END
  END rd_data[603]
  PIN rd_data[604]
    DIRECTION INPUT ;
    USE SIGNAL ;
    PORT
      LAYER M3 ;
        RECT  41.616 34.416 41.634 34.56 ;
    END
  END rd_data[604]
  PIN rd_data[605]
    DIRECTION INPUT ;
    USE SIGNAL ;
    PORT
      LAYER M5 ;
        RECT  40.992 34.368 41.016 34.56 ;
    END
  END rd_data[605]
  PIN rd_data[606]
    DIRECTION INPUT ;
    USE SIGNAL ;
    PORT
      LAYER M3 ;
        RECT  41.724 34.416 41.742 34.56 ;
    END
    PORT
      LAYER M3 ;
        RECT  41.688 34.428 41.814 34.493 ;
    END
  END rd_data[606]
  PIN rd_data[607]
    DIRECTION INPUT ;
    USE SIGNAL ;
    PORT
      LAYER M5 ;
        RECT  41.088 34.368 41.112 34.56 ;
    END
  END rd_data[607]
  PIN rd_data[608]
    DIRECTION INPUT ;
    USE SIGNAL ;
    PORT
      LAYER M3 ;
        RECT  41.832 34.416 41.85 34.56 ;
    END
  END rd_data[608]
  PIN rd_data[609]
    DIRECTION INPUT ;
    USE SIGNAL ;
    PORT
      LAYER M5 ;
        RECT  41.184 34.368 41.208 34.56 ;
    END
  END rd_data[609]
  PIN rd_data[60]
    DIRECTION INPUT ;
    USE SIGNAL ;
    PORT
      LAYER M3 ;
        RECT  12.24 34.416 12.258 34.56 ;
    END
  END rd_data[60]
  PIN rd_data[610]
    DIRECTION INPUT ;
    USE SIGNAL ;
    PORT
      LAYER M3 ;
        RECT  41.94 34.416 41.958 34.56 ;
    END
  END rd_data[610]
  PIN rd_data[611]
    DIRECTION INPUT ;
    USE SIGNAL ;
    PORT
      LAYER M5 ;
        RECT  41.28 34.368 41.304 34.56 ;
    END
  END rd_data[611]
  PIN rd_data[612]
    DIRECTION INPUT ;
    USE SIGNAL ;
    PORT
      LAYER M3 ;
        RECT  42.048 34.416 42.066 34.56 ;
    END
  END rd_data[612]
  PIN rd_data[613]
    DIRECTION INPUT ;
    USE SIGNAL ;
    PORT
      LAYER M5 ;
        RECT  41.376 34.368 41.4 34.56 ;
    END
  END rd_data[613]
  PIN rd_data[614]
    DIRECTION INPUT ;
    USE SIGNAL ;
    PORT
      LAYER M3 ;
        RECT  42.156 34.416 42.174 34.56 ;
    END
  END rd_data[614]
  PIN rd_data[615]
    DIRECTION INPUT ;
    USE SIGNAL ;
    PORT
      LAYER M5 ;
        RECT  41.472 34.368 41.496 34.56 ;
    END
  END rd_data[615]
  PIN rd_data[616]
    DIRECTION INPUT ;
    USE SIGNAL ;
    PORT
      LAYER M3 ;
        RECT  42.264 34.416 42.282 34.56 ;
    END
  END rd_data[616]
  PIN rd_data[617]
    DIRECTION INPUT ;
    USE SIGNAL ;
    PORT
      LAYER M5 ;
        RECT  41.568 34.368 41.592 34.56 ;
    END
  END rd_data[617]
  PIN rd_data[618]
    DIRECTION INPUT ;
    USE SIGNAL ;
    PORT
      LAYER M3 ;
        RECT  42.372 34.416 42.39 34.56 ;
    END
  END rd_data[618]
  PIN rd_data[619]
    DIRECTION INPUT ;
    USE SIGNAL ;
    PORT
      LAYER M5 ;
        RECT  41.664 34.368 41.688 34.56 ;
    END
  END rd_data[619]
  PIN rd_data[61]
    DIRECTION INPUT ;
    USE SIGNAL ;
    PORT
      LAYER M5 ;
        RECT  14.88 34.368 14.904 34.56 ;
    END
  END rd_data[61]
  PIN rd_data[620]
    DIRECTION INPUT ;
    USE SIGNAL ;
    PORT
      LAYER M3 ;
        RECT  42.48 34.416 42.498 34.56 ;
    END
  END rd_data[620]
  PIN rd_data[621]
    DIRECTION INPUT ;
    USE SIGNAL ;
    PORT
      LAYER M5 ;
        RECT  41.76 34.368 41.784 34.56 ;
    END
  END rd_data[621]
  PIN rd_data[622]
    DIRECTION INPUT ;
    USE SIGNAL ;
    PORT
      LAYER M3 ;
        RECT  42.588 34.416 42.606 34.56 ;
    END
  END rd_data[622]
  PIN rd_data[623]
    DIRECTION INPUT ;
    USE SIGNAL ;
    PORT
      LAYER M5 ;
        RECT  41.856 34.368 41.88 34.56 ;
    END
  END rd_data[623]
  PIN rd_data[624]
    DIRECTION INPUT ;
    USE SIGNAL ;
    PORT
      LAYER M3 ;
        RECT  42.696 34.416 42.714 34.56 ;
    END
  END rd_data[624]
  PIN rd_data[625]
    DIRECTION INPUT ;
    USE SIGNAL ;
    PORT
      LAYER M5 ;
        RECT  41.952 34.368 41.976 34.56 ;
    END
  END rd_data[625]
  PIN rd_data[626]
    DIRECTION INPUT ;
    USE SIGNAL ;
    PORT
      LAYER M3 ;
        RECT  42.804 34.416 42.822 34.56 ;
    END
  END rd_data[626]
  PIN rd_data[627]
    DIRECTION INPUT ;
    USE SIGNAL ;
    PORT
      LAYER M5 ;
        RECT  42.048 34.368 42.072 34.56 ;
    END
  END rd_data[627]
  PIN rd_data[628]
    DIRECTION INPUT ;
    USE SIGNAL ;
    PORT
      LAYER M3 ;
        RECT  42.912 34.416 42.93 34.56 ;
    END
  END rd_data[628]
  PIN rd_data[629]
    DIRECTION INPUT ;
    USE SIGNAL ;
    PORT
      LAYER M5 ;
        RECT  42.144 34.368 42.168 34.56 ;
    END
  END rd_data[629]
  PIN rd_data[62]
    DIRECTION INPUT ;
    USE SIGNAL ;
    PORT
      LAYER M3 ;
        RECT  12.348 34.416 12.366 34.56 ;
    END
  END rd_data[62]
  PIN rd_data[630]
    DIRECTION INPUT ;
    USE SIGNAL ;
    PORT
      LAYER M3 ;
        RECT  43.02 34.416 43.038 34.56 ;
    END
  END rd_data[630]
  PIN rd_data[631]
    DIRECTION INPUT ;
    USE SIGNAL ;
    PORT
      LAYER M5 ;
        RECT  42.24 34.368 42.264 34.56 ;
    END
  END rd_data[631]
  PIN rd_data[632]
    DIRECTION INPUT ;
    USE SIGNAL ;
    PORT
      LAYER M3 ;
        RECT  43.128 34.416 43.146 34.56 ;
    END
  END rd_data[632]
  PIN rd_data[633]
    DIRECTION INPUT ;
    USE SIGNAL ;
    PORT
      LAYER M5 ;
        RECT  42.336 34.368 42.36 34.56 ;
    END
  END rd_data[633]
  PIN rd_data[634]
    DIRECTION INPUT ;
    USE SIGNAL ;
    PORT
      LAYER M3 ;
        RECT  43.236 34.416 43.254 34.56 ;
    END
  END rd_data[634]
  PIN rd_data[635]
    DIRECTION INPUT ;
    USE SIGNAL ;
    PORT
      LAYER M5 ;
        RECT  42.432 34.368 42.456 34.56 ;
    END
  END rd_data[635]
  PIN rd_data[636]
    DIRECTION INPUT ;
    USE SIGNAL ;
    PORT
      LAYER M3 ;
        RECT  43.344 34.416 43.362 34.56 ;
    END
  END rd_data[636]
  PIN rd_data[637]
    DIRECTION INPUT ;
    USE SIGNAL ;
    PORT
      LAYER M5 ;
        RECT  42.528 34.368 42.552 34.56 ;
    END
  END rd_data[637]
  PIN rd_data[638]
    DIRECTION INPUT ;
    USE SIGNAL ;
    PORT
      LAYER M3 ;
        RECT  43.452 34.416 43.47 34.56 ;
    END
  END rd_data[638]
  PIN rd_data[639]
    DIRECTION INPUT ;
    USE SIGNAL ;
    PORT
      LAYER M5 ;
        RECT  42.624 34.368 42.648 34.56 ;
    END
  END rd_data[639]
  PIN rd_data[63]
    DIRECTION INPUT ;
    USE SIGNAL ;
    PORT
      LAYER M5 ;
        RECT  14.976 34.368 15 34.56 ;
    END
  END rd_data[63]
  PIN rd_data[640]
    DIRECTION INPUT ;
    USE SIGNAL ;
    PORT
      LAYER M3 ;
        RECT  43.56 34.416 43.578 34.56 ;
    END
  END rd_data[640]
  PIN rd_data[641]
    DIRECTION INPUT ;
    USE SIGNAL ;
    PORT
      LAYER M5 ;
        RECT  42.72 34.368 42.744 34.56 ;
    END
  END rd_data[641]
  PIN rd_data[642]
    DIRECTION INPUT ;
    USE SIGNAL ;
    PORT
      LAYER M3 ;
        RECT  43.668 34.416 43.686 34.56 ;
    END
  END rd_data[642]
  PIN rd_data[643]
    DIRECTION INPUT ;
    USE SIGNAL ;
    PORT
      LAYER M5 ;
        RECT  42.816 34.368 42.84 34.56 ;
    END
  END rd_data[643]
  PIN rd_data[644]
    DIRECTION INPUT ;
    USE SIGNAL ;
    PORT
      LAYER M3 ;
        RECT  43.776 34.416 43.794 34.56 ;
    END
  END rd_data[644]
  PIN rd_data[645]
    DIRECTION INPUT ;
    USE SIGNAL ;
    PORT
      LAYER M5 ;
        RECT  42.912 34.368 42.936 34.56 ;
    END
  END rd_data[645]
  PIN rd_data[646]
    DIRECTION INPUT ;
    USE SIGNAL ;
    PORT
      LAYER M3 ;
        RECT  43.884 34.416 43.902 34.56 ;
    END
  END rd_data[646]
  PIN rd_data[647]
    DIRECTION INPUT ;
    USE SIGNAL ;
    PORT
      LAYER M5 ;
        RECT  43.008 34.368 43.032 34.56 ;
    END
  END rd_data[647]
  PIN rd_data[648]
    DIRECTION INPUT ;
    USE SIGNAL ;
    PORT
      LAYER M3 ;
        RECT  43.992 34.416 44.01 34.56 ;
    END
  END rd_data[648]
  PIN rd_data[649]
    DIRECTION INPUT ;
    USE SIGNAL ;
    PORT
      LAYER M5 ;
        RECT  43.104 34.368 43.128 34.56 ;
    END
  END rd_data[649]
  PIN rd_data[64]
    DIRECTION INPUT ;
    USE SIGNAL ;
    PORT
      LAYER M3 ;
        RECT  12.456 34.416 12.474 34.56 ;
    END
  END rd_data[64]
  PIN rd_data[650]
    DIRECTION INPUT ;
    USE SIGNAL ;
    PORT
      LAYER M3 ;
        RECT  44.1 34.416 44.118 34.56 ;
    END
  END rd_data[650]
  PIN rd_data[651]
    DIRECTION INPUT ;
    USE SIGNAL ;
    PORT
      LAYER M5 ;
        RECT  43.2 34.368 43.224 34.56 ;
    END
  END rd_data[651]
  PIN rd_data[652]
    DIRECTION INPUT ;
    USE SIGNAL ;
    PORT
      LAYER M3 ;
        RECT  44.208 34.416 44.226 34.56 ;
    END
  END rd_data[652]
  PIN rd_data[653]
    DIRECTION INPUT ;
    USE SIGNAL ;
    PORT
      LAYER M5 ;
        RECT  43.296 34.368 43.32 34.56 ;
    END
  END rd_data[653]
  PIN rd_data[654]
    DIRECTION INPUT ;
    USE SIGNAL ;
    PORT
      LAYER M3 ;
        RECT  44.316 34.416 44.334 34.56 ;
    END
  END rd_data[654]
  PIN rd_data[655]
    DIRECTION INPUT ;
    USE SIGNAL ;
    PORT
      LAYER M5 ;
        RECT  43.392 34.368 43.416 34.56 ;
    END
  END rd_data[655]
  PIN rd_data[656]
    DIRECTION INPUT ;
    USE SIGNAL ;
    PORT
      LAYER M3 ;
        RECT  44.424 34.416 44.442 34.56 ;
    END
  END rd_data[656]
  PIN rd_data[657]
    DIRECTION INPUT ;
    USE SIGNAL ;
    PORT
      LAYER M5 ;
        RECT  43.488 34.368 43.512 34.56 ;
    END
  END rd_data[657]
  PIN rd_data[658]
    DIRECTION INPUT ;
    USE SIGNAL ;
    PORT
      LAYER M3 ;
        RECT  44.532 34.416 44.55 34.56 ;
    END
  END rd_data[658]
  PIN rd_data[659]
    DIRECTION INPUT ;
    USE SIGNAL ;
    PORT
      LAYER M5 ;
        RECT  43.584 34.368 43.608 34.56 ;
    END
  END rd_data[659]
  PIN rd_data[65]
    DIRECTION INPUT ;
    USE SIGNAL ;
    PORT
      LAYER M5 ;
        RECT  15.072 34.368 15.096 34.56 ;
    END
  END rd_data[65]
  PIN rd_data[660]
    DIRECTION INPUT ;
    USE SIGNAL ;
    PORT
      LAYER M3 ;
        RECT  44.64 34.416 44.658 34.56 ;
    END
  END rd_data[660]
  PIN rd_data[661]
    DIRECTION INPUT ;
    USE SIGNAL ;
    PORT
      LAYER M5 ;
        RECT  43.68 34.368 43.704 34.56 ;
    END
  END rd_data[661]
  PIN rd_data[662]
    DIRECTION INPUT ;
    USE SIGNAL ;
    PORT
      LAYER M3 ;
        RECT  44.748 34.416 44.766 34.56 ;
    END
  END rd_data[662]
  PIN rd_data[663]
    DIRECTION INPUT ;
    USE SIGNAL ;
    PORT
      LAYER M5 ;
        RECT  43.776 34.368 43.8 34.56 ;
    END
  END rd_data[663]
  PIN rd_data[664]
    DIRECTION INPUT ;
    USE SIGNAL ;
    PORT
      LAYER M3 ;
        RECT  44.856 34.416 44.874 34.56 ;
    END
  END rd_data[664]
  PIN rd_data[665]
    DIRECTION INPUT ;
    USE SIGNAL ;
    PORT
      LAYER M5 ;
        RECT  43.872 34.368 43.896 34.56 ;
    END
  END rd_data[665]
  PIN rd_data[666]
    DIRECTION INPUT ;
    USE SIGNAL ;
    PORT
      LAYER M3 ;
        RECT  44.964 34.416 44.982 34.56 ;
    END
  END rd_data[666]
  PIN rd_data[667]
    DIRECTION INPUT ;
    USE SIGNAL ;
    PORT
      LAYER M5 ;
        RECT  43.968 34.368 43.992 34.56 ;
    END
  END rd_data[667]
  PIN rd_data[668]
    DIRECTION INPUT ;
    USE SIGNAL ;
    PORT
      LAYER M3 ;
        RECT  45.072 34.416 45.09 34.56 ;
    END
  END rd_data[668]
  PIN rd_data[669]
    DIRECTION INPUT ;
    USE SIGNAL ;
    PORT
      LAYER M5 ;
        RECT  44.064 34.368 44.088 34.56 ;
    END
  END rd_data[669]
  PIN rd_data[66]
    DIRECTION INPUT ;
    USE SIGNAL ;
    PORT
      LAYER M3 ;
        RECT  12.564 34.416 12.582 34.56 ;
    END
  END rd_data[66]
  PIN rd_data[670]
    DIRECTION INPUT ;
    USE SIGNAL ;
    PORT
      LAYER M3 ;
        RECT  45.18 34.416 45.198 34.56 ;
    END
  END rd_data[670]
  PIN rd_data[671]
    DIRECTION INPUT ;
    USE SIGNAL ;
    PORT
      LAYER M5 ;
        RECT  44.16 34.368 44.184 34.56 ;
    END
  END rd_data[671]
  PIN rd_data[672]
    DIRECTION INPUT ;
    USE SIGNAL ;
    PORT
      LAYER M3 ;
        RECT  45.288 34.416 45.306 34.56 ;
    END
  END rd_data[672]
  PIN rd_data[673]
    DIRECTION INPUT ;
    USE SIGNAL ;
    PORT
      LAYER M5 ;
        RECT  44.256 34.368 44.28 34.56 ;
    END
  END rd_data[673]
  PIN rd_data[674]
    DIRECTION INPUT ;
    USE SIGNAL ;
    PORT
      LAYER M3 ;
        RECT  45.396 34.416 45.414 34.56 ;
    END
  END rd_data[674]
  PIN rd_data[675]
    DIRECTION INPUT ;
    USE SIGNAL ;
    PORT
      LAYER M5 ;
        RECT  44.352 34.368 44.376 34.56 ;
    END
  END rd_data[675]
  PIN rd_data[676]
    DIRECTION INPUT ;
    USE SIGNAL ;
    PORT
      LAYER M3 ;
        RECT  45.504 34.416 45.522 34.56 ;
    END
  END rd_data[676]
  PIN rd_data[677]
    DIRECTION INPUT ;
    USE SIGNAL ;
    PORT
      LAYER M5 ;
        RECT  44.448 34.368 44.472 34.56 ;
    END
  END rd_data[677]
  PIN rd_data[678]
    DIRECTION INPUT ;
    USE SIGNAL ;
    PORT
      LAYER M3 ;
        RECT  45.612 34.416 45.63 34.56 ;
    END
  END rd_data[678]
  PIN rd_data[679]
    DIRECTION INPUT ;
    USE SIGNAL ;
    PORT
      LAYER M5 ;
        RECT  44.544 34.368 44.568 34.56 ;
    END
  END rd_data[679]
  PIN rd_data[67]
    DIRECTION INPUT ;
    USE SIGNAL ;
    PORT
      LAYER M5 ;
        RECT  15.168 34.368 15.192 34.56 ;
    END
  END rd_data[67]
  PIN rd_data[680]
    DIRECTION INPUT ;
    USE SIGNAL ;
    PORT
      LAYER M3 ;
        RECT  45.72 34.416 45.738 34.56 ;
    END
  END rd_data[680]
  PIN rd_data[681]
    DIRECTION INPUT ;
    USE SIGNAL ;
    PORT
      LAYER M5 ;
        RECT  44.64 34.368 44.664 34.56 ;
    END
  END rd_data[681]
  PIN rd_data[682]
    DIRECTION INPUT ;
    USE SIGNAL ;
    PORT
      LAYER M3 ;
        RECT  45.828 34.416 45.846 34.56 ;
    END
  END rd_data[682]
  PIN rd_data[683]
    DIRECTION INPUT ;
    USE SIGNAL ;
    PORT
      LAYER M5 ;
        RECT  44.736 34.368 44.76 34.56 ;
    END
  END rd_data[683]
  PIN rd_data[684]
    DIRECTION INPUT ;
    USE SIGNAL ;
    PORT
      LAYER M3 ;
        RECT  45.936 34.416 45.954 34.56 ;
    END
  END rd_data[684]
  PIN rd_data[685]
    DIRECTION INPUT ;
    USE SIGNAL ;
    PORT
      LAYER M5 ;
        RECT  44.832 34.368 44.856 34.56 ;
    END
  END rd_data[685]
  PIN rd_data[686]
    DIRECTION INPUT ;
    USE SIGNAL ;
    PORT
      LAYER M3 ;
        RECT  46.044 34.416 46.062 34.56 ;
    END
  END rd_data[686]
  PIN rd_data[687]
    DIRECTION INPUT ;
    USE SIGNAL ;
    PORT
      LAYER M5 ;
        RECT  44.928 34.368 44.952 34.56 ;
    END
  END rd_data[687]
  PIN rd_data[688]
    DIRECTION INPUT ;
    USE SIGNAL ;
    PORT
      LAYER M3 ;
        RECT  46.152 34.416 46.17 34.56 ;
    END
  END rd_data[688]
  PIN rd_data[689]
    DIRECTION INPUT ;
    USE SIGNAL ;
    PORT
      LAYER M5 ;
        RECT  45.024 34.368 45.048 34.56 ;
    END
  END rd_data[689]
  PIN rd_data[68]
    DIRECTION INPUT ;
    USE SIGNAL ;
    PORT
      LAYER M3 ;
        RECT  12.672 34.416 12.69 34.56 ;
    END
  END rd_data[68]
  PIN rd_data[690]
    DIRECTION INPUT ;
    USE SIGNAL ;
    PORT
      LAYER M3 ;
        RECT  46.26 34.416 46.278 34.56 ;
    END
  END rd_data[690]
  PIN rd_data[691]
    DIRECTION INPUT ;
    USE SIGNAL ;
    PORT
      LAYER M5 ;
        RECT  45.12 34.368 45.144 34.56 ;
    END
  END rd_data[691]
  PIN rd_data[692]
    DIRECTION INPUT ;
    USE SIGNAL ;
    PORT
      LAYER M3 ;
        RECT  46.368 34.416 46.386 34.56 ;
    END
  END rd_data[692]
  PIN rd_data[693]
    DIRECTION INPUT ;
    USE SIGNAL ;
    PORT
      LAYER M5 ;
        RECT  45.216 34.368 45.24 34.56 ;
    END
  END rd_data[693]
  PIN rd_data[694]
    DIRECTION INPUT ;
    USE SIGNAL ;
    PORT
      LAYER M3 ;
        RECT  46.476 34.416 46.494 34.56 ;
    END
  END rd_data[694]
  PIN rd_data[695]
    DIRECTION INPUT ;
    USE SIGNAL ;
    PORT
      LAYER M5 ;
        RECT  45.312 34.368 45.336 34.56 ;
    END
  END rd_data[695]
  PIN rd_data[696]
    DIRECTION INPUT ;
    USE SIGNAL ;
    PORT
      LAYER M3 ;
        RECT  46.584 34.416 46.602 34.56 ;
    END
  END rd_data[696]
  PIN rd_data[697]
    DIRECTION INPUT ;
    USE SIGNAL ;
    PORT
      LAYER M5 ;
        RECT  45.408 34.368 45.432 34.56 ;
    END
  END rd_data[697]
  PIN rd_data[698]
    DIRECTION INPUT ;
    USE SIGNAL ;
    PORT
      LAYER M3 ;
        RECT  46.692 34.416 46.71 34.56 ;
    END
  END rd_data[698]
  PIN rd_data[699]
    DIRECTION INPUT ;
    USE SIGNAL ;
    PORT
      LAYER M5 ;
        RECT  45.504 34.368 45.528 34.56 ;
    END
  END rd_data[699]
  PIN rd_data[69]
    DIRECTION INPUT ;
    USE SIGNAL ;
    PORT
      LAYER M5 ;
        RECT  15.264 34.368 15.288 34.56 ;
    END
  END rd_data[69]
  PIN rd_data[6]
    DIRECTION INPUT ;
    USE SIGNAL ;
    PORT
      LAYER M3 ;
        RECT  9.324 34.416 9.342 34.56 ;
    END
  END rd_data[6]
  PIN rd_data[700]
    DIRECTION INPUT ;
    USE SIGNAL ;
    PORT
      LAYER M3 ;
        RECT  46.8 34.416 46.818 34.56 ;
    END
  END rd_data[700]
  PIN rd_data[701]
    DIRECTION INPUT ;
    USE SIGNAL ;
    PORT
      LAYER M5 ;
        RECT  45.6 34.368 45.624 34.56 ;
    END
  END rd_data[701]
  PIN rd_data[702]
    DIRECTION INPUT ;
    USE SIGNAL ;
    PORT
      LAYER M3 ;
        RECT  46.908 34.416 46.926 34.56 ;
    END
  END rd_data[702]
  PIN rd_data[703]
    DIRECTION INPUT ;
    USE SIGNAL ;
    PORT
      LAYER M5 ;
        RECT  45.696 34.368 45.72 34.56 ;
    END
  END rd_data[703]
  PIN rd_data[704]
    DIRECTION INPUT ;
    USE SIGNAL ;
    PORT
      LAYER M3 ;
        RECT  47.016 34.416 47.034 34.56 ;
    END
  END rd_data[704]
  PIN rd_data[705]
    DIRECTION INPUT ;
    USE SIGNAL ;
    PORT
      LAYER M5 ;
        RECT  45.792 34.368 45.816 34.56 ;
    END
  END rd_data[705]
  PIN rd_data[706]
    DIRECTION INPUT ;
    USE SIGNAL ;
    PORT
      LAYER M3 ;
        RECT  47.124 34.416 47.142 34.56 ;
    END
  END rd_data[706]
  PIN rd_data[707]
    DIRECTION INPUT ;
    USE SIGNAL ;
    PORT
      LAYER M5 ;
        RECT  45.888 34.368 45.912 34.56 ;
    END
  END rd_data[707]
  PIN rd_data[708]
    DIRECTION INPUT ;
    USE SIGNAL ;
    PORT
      LAYER M3 ;
        RECT  47.232 34.416 47.25 34.56 ;
    END
  END rd_data[708]
  PIN rd_data[709]
    DIRECTION INPUT ;
    USE SIGNAL ;
    PORT
      LAYER M5 ;
        RECT  45.984 34.368 46.008 34.56 ;
    END
  END rd_data[709]
  PIN rd_data[70]
    DIRECTION INPUT ;
    USE SIGNAL ;
    PORT
      LAYER M3 ;
        RECT  12.78 34.416 12.798 34.56 ;
    END
  END rd_data[70]
  PIN rd_data[710]
    DIRECTION INPUT ;
    USE SIGNAL ;
    PORT
      LAYER M3 ;
        RECT  47.34 34.416 47.358 34.56 ;
    END
  END rd_data[710]
  PIN rd_data[711]
    DIRECTION INPUT ;
    USE SIGNAL ;
    PORT
      LAYER M5 ;
        RECT  46.08 34.368 46.104 34.56 ;
    END
  END rd_data[711]
  PIN rd_data[712]
    DIRECTION INPUT ;
    USE SIGNAL ;
    PORT
      LAYER M3 ;
        RECT  47.448 34.416 47.466 34.56 ;
    END
  END rd_data[712]
  PIN rd_data[713]
    DIRECTION INPUT ;
    USE SIGNAL ;
    PORT
      LAYER M5 ;
        RECT  46.176 34.368 46.2 34.56 ;
    END
  END rd_data[713]
  PIN rd_data[714]
    DIRECTION INPUT ;
    USE SIGNAL ;
    PORT
      LAYER M3 ;
        RECT  47.556 34.416 47.574 34.56 ;
    END
  END rd_data[714]
  PIN rd_data[715]
    DIRECTION INPUT ;
    USE SIGNAL ;
    PORT
      LAYER M5 ;
        RECT  46.272 34.368 46.296 34.56 ;
    END
  END rd_data[715]
  PIN rd_data[716]
    DIRECTION INPUT ;
    USE SIGNAL ;
    PORT
      LAYER M3 ;
        RECT  47.664 34.416 47.682 34.56 ;
    END
  END rd_data[716]
  PIN rd_data[717]
    DIRECTION INPUT ;
    USE SIGNAL ;
    PORT
      LAYER M5 ;
        RECT  46.368 34.368 46.392 34.56 ;
    END
  END rd_data[717]
  PIN rd_data[718]
    DIRECTION INPUT ;
    USE SIGNAL ;
    PORT
      LAYER M3 ;
        RECT  47.772 34.416 47.79 34.56 ;
    END
  END rd_data[718]
  PIN rd_data[719]
    DIRECTION INPUT ;
    USE SIGNAL ;
    PORT
      LAYER M5 ;
        RECT  46.464 34.368 46.488 34.56 ;
    END
  END rd_data[719]
  PIN rd_data[71]
    DIRECTION INPUT ;
    USE SIGNAL ;
    PORT
      LAYER M5 ;
        RECT  15.36 34.368 15.384 34.56 ;
    END
  END rd_data[71]
  PIN rd_data[720]
    DIRECTION INPUT ;
    USE SIGNAL ;
    PORT
      LAYER M3 ;
        RECT  47.88 34.416 47.898 34.56 ;
    END
  END rd_data[720]
  PIN rd_data[721]
    DIRECTION INPUT ;
    USE SIGNAL ;
    PORT
      LAYER M5 ;
        RECT  46.56 34.368 46.584 34.56 ;
    END
  END rd_data[721]
  PIN rd_data[722]
    DIRECTION INPUT ;
    USE SIGNAL ;
    PORT
      LAYER M3 ;
        RECT  47.988 34.416 48.006 34.56 ;
    END
  END rd_data[722]
  PIN rd_data[723]
    DIRECTION INPUT ;
    USE SIGNAL ;
    PORT
      LAYER M5 ;
        RECT  46.656 34.368 46.68 34.56 ;
    END
  END rd_data[723]
  PIN rd_data[724]
    DIRECTION INPUT ;
    USE SIGNAL ;
    PORT
      LAYER M3 ;
        RECT  48.096 34.416 48.114 34.56 ;
    END
  END rd_data[724]
  PIN rd_data[725]
    DIRECTION INPUT ;
    USE SIGNAL ;
    PORT
      LAYER M5 ;
        RECT  46.752 34.368 46.776 34.56 ;
    END
  END rd_data[725]
  PIN rd_data[726]
    DIRECTION INPUT ;
    USE SIGNAL ;
    PORT
      LAYER M3 ;
        RECT  48.204 34.416 48.222 34.56 ;
    END
  END rd_data[726]
  PIN rd_data[727]
    DIRECTION INPUT ;
    USE SIGNAL ;
    PORT
      LAYER M5 ;
        RECT  46.848 34.368 46.872 34.56 ;
    END
  END rd_data[727]
  PIN rd_data[728]
    DIRECTION INPUT ;
    USE SIGNAL ;
    PORT
      LAYER M3 ;
        RECT  48.312 34.416 48.33 34.56 ;
    END
  END rd_data[728]
  PIN rd_data[729]
    DIRECTION INPUT ;
    USE SIGNAL ;
    PORT
      LAYER M5 ;
        RECT  46.944 34.368 46.968 34.56 ;
    END
  END rd_data[729]
  PIN rd_data[72]
    DIRECTION INPUT ;
    USE SIGNAL ;
    PORT
      LAYER M3 ;
        RECT  12.888 34.416 12.906 34.56 ;
    END
  END rd_data[72]
  PIN rd_data[730]
    DIRECTION INPUT ;
    USE SIGNAL ;
    PORT
      LAYER M3 ;
        RECT  48.42 34.416 48.438 34.56 ;
    END
  END rd_data[730]
  PIN rd_data[731]
    DIRECTION INPUT ;
    USE SIGNAL ;
    PORT
      LAYER M5 ;
        RECT  47.04 34.368 47.064 34.56 ;
    END
  END rd_data[731]
  PIN rd_data[732]
    DIRECTION INPUT ;
    USE SIGNAL ;
    PORT
      LAYER M3 ;
        RECT  48.528 34.416 48.546 34.56 ;
    END
  END rd_data[732]
  PIN rd_data[733]
    DIRECTION INPUT ;
    USE SIGNAL ;
    PORT
      LAYER M5 ;
        RECT  47.136 34.368 47.16 34.56 ;
    END
  END rd_data[733]
  PIN rd_data[734]
    DIRECTION INPUT ;
    USE SIGNAL ;
    PORT
      LAYER M3 ;
        RECT  48.636 34.416 48.654 34.56 ;
    END
  END rd_data[734]
  PIN rd_data[735]
    DIRECTION INPUT ;
    USE SIGNAL ;
    PORT
      LAYER M5 ;
        RECT  47.232 34.368 47.256 34.56 ;
    END
  END rd_data[735]
  PIN rd_data[736]
    DIRECTION INPUT ;
    USE SIGNAL ;
    PORT
      LAYER M3 ;
        RECT  48.744 34.416 48.762 34.56 ;
    END
  END rd_data[736]
  PIN rd_data[737]
    DIRECTION INPUT ;
    USE SIGNAL ;
    PORT
      LAYER M5 ;
        RECT  47.328 34.368 47.352 34.56 ;
    END
  END rd_data[737]
  PIN rd_data[738]
    DIRECTION INPUT ;
    USE SIGNAL ;
    PORT
      LAYER M3 ;
        RECT  48.852 34.416 48.87 34.56 ;
    END
  END rd_data[738]
  PIN rd_data[739]
    DIRECTION INPUT ;
    USE SIGNAL ;
    PORT
      LAYER M5 ;
        RECT  47.424 34.368 47.448 34.56 ;
    END
  END rd_data[739]
  PIN rd_data[73]
    DIRECTION INPUT ;
    USE SIGNAL ;
    PORT
      LAYER M5 ;
        RECT  15.456 34.368 15.48 34.56 ;
    END
  END rd_data[73]
  PIN rd_data[740]
    DIRECTION INPUT ;
    USE SIGNAL ;
    PORT
      LAYER M3 ;
        RECT  48.96 34.416 48.978 34.56 ;
    END
  END rd_data[740]
  PIN rd_data[741]
    DIRECTION INPUT ;
    USE SIGNAL ;
    PORT
      LAYER M5 ;
        RECT  47.52 34.368 47.544 34.56 ;
    END
  END rd_data[741]
  PIN rd_data[742]
    DIRECTION INPUT ;
    USE SIGNAL ;
    PORT
      LAYER M3 ;
        RECT  49.068 34.416 49.086 34.56 ;
    END
  END rd_data[742]
  PIN rd_data[743]
    DIRECTION INPUT ;
    USE SIGNAL ;
    PORT
      LAYER M5 ;
        RECT  47.616 34.368 47.64 34.56 ;
    END
  END rd_data[743]
  PIN rd_data[744]
    DIRECTION INPUT ;
    USE SIGNAL ;
    PORT
      LAYER M3 ;
        RECT  49.176 34.416 49.194 34.56 ;
    END
  END rd_data[744]
  PIN rd_data[745]
    DIRECTION INPUT ;
    USE SIGNAL ;
    PORT
      LAYER M5 ;
        RECT  47.712 34.368 47.736 34.56 ;
    END
  END rd_data[745]
  PIN rd_data[746]
    DIRECTION INPUT ;
    USE SIGNAL ;
    PORT
      LAYER M3 ;
        RECT  49.284 34.416 49.302 34.56 ;
    END
  END rd_data[746]
  PIN rd_data[747]
    DIRECTION INPUT ;
    USE SIGNAL ;
    PORT
      LAYER M5 ;
        RECT  47.808 34.368 47.832 34.56 ;
    END
  END rd_data[747]
  PIN rd_data[748]
    DIRECTION INPUT ;
    USE SIGNAL ;
    PORT
      LAYER M3 ;
        RECT  49.392 34.416 49.41 34.56 ;
    END
  END rd_data[748]
  PIN rd_data[749]
    DIRECTION INPUT ;
    USE SIGNAL ;
    PORT
      LAYER M5 ;
        RECT  47.904 34.368 47.928 34.56 ;
    END
  END rd_data[749]
  PIN rd_data[74]
    DIRECTION INPUT ;
    USE SIGNAL ;
    PORT
      LAYER M3 ;
        RECT  12.996 34.416 13.014 34.56 ;
    END
  END rd_data[74]
  PIN rd_data[750]
    DIRECTION INPUT ;
    USE SIGNAL ;
    PORT
      LAYER M3 ;
        RECT  49.5 34.416 49.518 34.56 ;
    END
  END rd_data[750]
  PIN rd_data[751]
    DIRECTION INPUT ;
    USE SIGNAL ;
    PORT
      LAYER M5 ;
        RECT  48 34.368 48.024 34.56 ;
    END
  END rd_data[751]
  PIN rd_data[752]
    DIRECTION INPUT ;
    USE SIGNAL ;
    PORT
      LAYER M3 ;
        RECT  49.608 34.416 49.626 34.56 ;
    END
  END rd_data[752]
  PIN rd_data[753]
    DIRECTION INPUT ;
    USE SIGNAL ;
    PORT
      LAYER M5 ;
        RECT  48.096 34.368 48.12 34.56 ;
    END
  END rd_data[753]
  PIN rd_data[754]
    DIRECTION INPUT ;
    USE SIGNAL ;
    PORT
      LAYER M3 ;
        RECT  49.716 34.416 49.734 34.56 ;
    END
  END rd_data[754]
  PIN rd_data[755]
    DIRECTION INPUT ;
    USE SIGNAL ;
    PORT
      LAYER M5 ;
        RECT  48.192 34.368 48.216 34.56 ;
    END
  END rd_data[755]
  PIN rd_data[756]
    DIRECTION INPUT ;
    USE SIGNAL ;
    PORT
      LAYER M3 ;
        RECT  49.824 34.416 49.842 34.56 ;
    END
  END rd_data[756]
  PIN rd_data[757]
    DIRECTION INPUT ;
    USE SIGNAL ;
    PORT
      LAYER M5 ;
        RECT  48.288 34.368 48.312 34.56 ;
    END
  END rd_data[757]
  PIN rd_data[758]
    DIRECTION INPUT ;
    USE SIGNAL ;
    PORT
      LAYER M3 ;
        RECT  49.932 34.416 49.95 34.56 ;
    END
  END rd_data[758]
  PIN rd_data[759]
    DIRECTION INPUT ;
    USE SIGNAL ;
    PORT
      LAYER M5 ;
        RECT  48.384 34.368 48.408 34.56 ;
    END
  END rd_data[759]
  PIN rd_data[75]
    DIRECTION INPUT ;
    USE SIGNAL ;
    PORT
      LAYER M5 ;
        RECT  15.552 34.368 15.576 34.56 ;
    END
  END rd_data[75]
  PIN rd_data[760]
    DIRECTION INPUT ;
    USE SIGNAL ;
    PORT
      LAYER M3 ;
        RECT  50.04 34.416 50.058 34.56 ;
    END
  END rd_data[760]
  PIN rd_data[761]
    DIRECTION INPUT ;
    USE SIGNAL ;
    PORT
      LAYER M5 ;
        RECT  48.48 34.368 48.504 34.56 ;
    END
  END rd_data[761]
  PIN rd_data[762]
    DIRECTION INPUT ;
    USE SIGNAL ;
    PORT
      LAYER M3 ;
        RECT  50.148 34.416 50.166 34.56 ;
    END
  END rd_data[762]
  PIN rd_data[763]
    DIRECTION INPUT ;
    USE SIGNAL ;
    PORT
      LAYER M5 ;
        RECT  48.576 34.368 48.6 34.56 ;
    END
  END rd_data[763]
  PIN rd_data[764]
    DIRECTION INPUT ;
    USE SIGNAL ;
    PORT
      LAYER M3 ;
        RECT  50.256 34.416 50.274 34.56 ;
    END
  END rd_data[764]
  PIN rd_data[765]
    DIRECTION INPUT ;
    USE SIGNAL ;
    PORT
      LAYER M5 ;
        RECT  48.672 34.368 48.696 34.56 ;
    END
  END rd_data[765]
  PIN rd_data[766]
    DIRECTION INPUT ;
    USE SIGNAL ;
    PORT
      LAYER M3 ;
        RECT  50.364 34.416 50.382 34.56 ;
    END
  END rd_data[766]
  PIN rd_data[767]
    DIRECTION INPUT ;
    USE SIGNAL ;
    PORT
      LAYER M5 ;
        RECT  48.768 34.368 48.792 34.56 ;
    END
  END rd_data[767]
  PIN rd_data[768]
    DIRECTION INPUT ;
    USE SIGNAL ;
    PORT
      LAYER M3 ;
        RECT  50.472 34.416 50.49 34.56 ;
    END
  END rd_data[768]
  PIN rd_data[769]
    DIRECTION INPUT ;
    USE SIGNAL ;
    PORT
      LAYER M5 ;
        RECT  48.864 34.368 48.888 34.56 ;
    END
  END rd_data[769]
  PIN rd_data[76]
    DIRECTION INPUT ;
    USE SIGNAL ;
    PORT
      LAYER M3 ;
        RECT  13.104 34.416 13.122 34.56 ;
    END
  END rd_data[76]
  PIN rd_data[770]
    DIRECTION INPUT ;
    USE SIGNAL ;
    PORT
      LAYER M3 ;
        RECT  50.58 34.416 50.598 34.56 ;
    END
  END rd_data[770]
  PIN rd_data[771]
    DIRECTION INPUT ;
    USE SIGNAL ;
    PORT
      LAYER M5 ;
        RECT  48.96 34.368 48.984 34.56 ;
    END
  END rd_data[771]
  PIN rd_data[772]
    DIRECTION INPUT ;
    USE SIGNAL ;
    PORT
      LAYER M3 ;
        RECT  50.688 34.416 50.706 34.56 ;
    END
  END rd_data[772]
  PIN rd_data[773]
    DIRECTION INPUT ;
    USE SIGNAL ;
    PORT
      LAYER M5 ;
        RECT  49.056 34.368 49.08 34.56 ;
    END
  END rd_data[773]
  PIN rd_data[774]
    DIRECTION INPUT ;
    USE SIGNAL ;
    PORT
      LAYER M3 ;
        RECT  50.796 34.416 50.814 34.56 ;
    END
  END rd_data[774]
  PIN rd_data[775]
    DIRECTION INPUT ;
    USE SIGNAL ;
    PORT
      LAYER M5 ;
        RECT  49.152 34.368 49.176 34.56 ;
    END
  END rd_data[775]
  PIN rd_data[776]
    DIRECTION INPUT ;
    USE SIGNAL ;
    PORT
      LAYER M3 ;
        RECT  50.904 34.416 50.922 34.56 ;
    END
  END rd_data[776]
  PIN rd_data[777]
    DIRECTION INPUT ;
    USE SIGNAL ;
    PORT
      LAYER M5 ;
        RECT  49.248 34.368 49.272 34.56 ;
    END
  END rd_data[777]
  PIN rd_data[778]
    DIRECTION INPUT ;
    USE SIGNAL ;
    PORT
      LAYER M3 ;
        RECT  51.012 34.416 51.03 34.56 ;
    END
  END rd_data[778]
  PIN rd_data[779]
    DIRECTION INPUT ;
    USE SIGNAL ;
    PORT
      LAYER M5 ;
        RECT  49.344 34.368 49.368 34.56 ;
    END
  END rd_data[779]
  PIN rd_data[77]
    DIRECTION INPUT ;
    USE SIGNAL ;
    PORT
      LAYER M5 ;
        RECT  15.648 34.368 15.672 34.56 ;
    END
  END rd_data[77]
  PIN rd_data[780]
    DIRECTION INPUT ;
    USE SIGNAL ;
    PORT
      LAYER M3 ;
        RECT  51.12 34.416 51.138 34.56 ;
    END
  END rd_data[780]
  PIN rd_data[781]
    DIRECTION INPUT ;
    USE SIGNAL ;
    PORT
      LAYER M5 ;
        RECT  49.44 34.368 49.464 34.56 ;
    END
  END rd_data[781]
  PIN rd_data[782]
    DIRECTION INPUT ;
    USE SIGNAL ;
    PORT
      LAYER M3 ;
        RECT  51.228 34.416 51.246 34.56 ;
    END
  END rd_data[782]
  PIN rd_data[783]
    DIRECTION INPUT ;
    USE SIGNAL ;
    PORT
      LAYER M5 ;
        RECT  49.536 34.368 49.56 34.56 ;
    END
  END rd_data[783]
  PIN rd_data[784]
    DIRECTION INPUT ;
    USE SIGNAL ;
    PORT
      LAYER M3 ;
        RECT  51.336 34.416 51.354 34.56 ;
    END
  END rd_data[784]
  PIN rd_data[785]
    DIRECTION INPUT ;
    USE SIGNAL ;
    PORT
      LAYER M5 ;
        RECT  49.632 34.368 49.656 34.56 ;
    END
  END rd_data[785]
  PIN rd_data[786]
    DIRECTION INPUT ;
    USE SIGNAL ;
    PORT
      LAYER M3 ;
        RECT  51.444 34.416 51.462 34.56 ;
    END
  END rd_data[786]
  PIN rd_data[787]
    DIRECTION INPUT ;
    USE SIGNAL ;
    PORT
      LAYER M5 ;
        RECT  49.728 34.368 49.752 34.56 ;
    END
  END rd_data[787]
  PIN rd_data[788]
    DIRECTION INPUT ;
    USE SIGNAL ;
    PORT
      LAYER M3 ;
        RECT  51.552 34.416 51.57 34.56 ;
    END
  END rd_data[788]
  PIN rd_data[789]
    DIRECTION INPUT ;
    USE SIGNAL ;
    PORT
      LAYER M5 ;
        RECT  49.824 34.368 49.848 34.56 ;
    END
  END rd_data[789]
  PIN rd_data[78]
    DIRECTION INPUT ;
    USE SIGNAL ;
    PORT
      LAYER M3 ;
        RECT  13.212 34.416 13.23 34.56 ;
    END
  END rd_data[78]
  PIN rd_data[790]
    DIRECTION INPUT ;
    USE SIGNAL ;
    PORT
      LAYER M3 ;
        RECT  51.66 34.416 51.678 34.56 ;
    END
  END rd_data[790]
  PIN rd_data[791]
    DIRECTION INPUT ;
    USE SIGNAL ;
    PORT
      LAYER M5 ;
        RECT  49.92 34.368 49.944 34.56 ;
    END
  END rd_data[791]
  PIN rd_data[792]
    DIRECTION INPUT ;
    USE SIGNAL ;
    PORT
      LAYER M3 ;
        RECT  51.768 34.416 51.786 34.56 ;
    END
  END rd_data[792]
  PIN rd_data[793]
    DIRECTION INPUT ;
    USE SIGNAL ;
    PORT
      LAYER M5 ;
        RECT  50.016 34.368 50.04 34.56 ;
    END
  END rd_data[793]
  PIN rd_data[794]
    DIRECTION INPUT ;
    USE SIGNAL ;
    PORT
      LAYER M3 ;
        RECT  51.876 34.416 51.894 34.56 ;
    END
  END rd_data[794]
  PIN rd_data[795]
    DIRECTION INPUT ;
    USE SIGNAL ;
    PORT
      LAYER M5 ;
        RECT  50.112 34.368 50.136 34.56 ;
    END
  END rd_data[795]
  PIN rd_data[796]
    DIRECTION INPUT ;
    USE SIGNAL ;
    PORT
      LAYER M3 ;
        RECT  51.984 34.416 52.002 34.56 ;
    END
  END rd_data[796]
  PIN rd_data[797]
    DIRECTION INPUT ;
    USE SIGNAL ;
    PORT
      LAYER M5 ;
        RECT  50.208 34.368 50.232 34.56 ;
    END
  END rd_data[797]
  PIN rd_data[798]
    DIRECTION INPUT ;
    USE SIGNAL ;
    PORT
      LAYER M3 ;
        RECT  52.092 34.416 52.11 34.56 ;
    END
  END rd_data[798]
  PIN rd_data[799]
    DIRECTION INPUT ;
    USE SIGNAL ;
    PORT
      LAYER M5 ;
        RECT  50.304 34.368 50.328 34.56 ;
    END
  END rd_data[799]
  PIN rd_data[79]
    DIRECTION INPUT ;
    USE SIGNAL ;
    PORT
      LAYER M5 ;
        RECT  15.744 34.368 15.768 34.56 ;
    END
  END rd_data[79]
  PIN rd_data[7]
    DIRECTION INPUT ;
    USE SIGNAL ;
    PORT
      LAYER M5 ;
        RECT  12.288 34.368 12.312 34.56 ;
    END
  END rd_data[7]
  PIN rd_data[800]
    DIRECTION INPUT ;
    USE SIGNAL ;
    PORT
      LAYER M3 ;
        RECT  52.2 34.416 52.218 34.56 ;
    END
  END rd_data[800]
  PIN rd_data[801]
    DIRECTION INPUT ;
    USE SIGNAL ;
    PORT
      LAYER M5 ;
        RECT  50.4 34.368 50.424 34.56 ;
    END
  END rd_data[801]
  PIN rd_data[802]
    DIRECTION INPUT ;
    USE SIGNAL ;
    PORT
      LAYER M3 ;
        RECT  52.308 34.416 52.326 34.56 ;
    END
  END rd_data[802]
  PIN rd_data[803]
    DIRECTION INPUT ;
    USE SIGNAL ;
    PORT
      LAYER M5 ;
        RECT  50.496 34.368 50.52 34.56 ;
    END
  END rd_data[803]
  PIN rd_data[804]
    DIRECTION INPUT ;
    USE SIGNAL ;
    PORT
      LAYER M3 ;
        RECT  52.416 34.416 52.434 34.56 ;
    END
  END rd_data[804]
  PIN rd_data[805]
    DIRECTION INPUT ;
    USE SIGNAL ;
    PORT
      LAYER M5 ;
        RECT  50.592 34.368 50.616 34.56 ;
    END
  END rd_data[805]
  PIN rd_data[806]
    DIRECTION INPUT ;
    USE SIGNAL ;
    PORT
      LAYER M3 ;
        RECT  52.524 34.416 52.542 34.56 ;
    END
  END rd_data[806]
  PIN rd_data[807]
    DIRECTION INPUT ;
    USE SIGNAL ;
    PORT
      LAYER M5 ;
        RECT  50.688 34.368 50.712 34.56 ;
    END
  END rd_data[807]
  PIN rd_data[808]
    DIRECTION INPUT ;
    USE SIGNAL ;
    PORT
      LAYER M3 ;
        RECT  52.632 34.416 52.65 34.56 ;
    END
  END rd_data[808]
  PIN rd_data[809]
    DIRECTION INPUT ;
    USE SIGNAL ;
    PORT
      LAYER M5 ;
        RECT  50.784 34.368 50.808 34.56 ;
    END
  END rd_data[809]
  PIN rd_data[80]
    DIRECTION INPUT ;
    USE SIGNAL ;
    PORT
      LAYER M3 ;
        RECT  13.32 34.416 13.338 34.56 ;
    END
  END rd_data[80]
  PIN rd_data[810]
    DIRECTION INPUT ;
    USE SIGNAL ;
    PORT
      LAYER M3 ;
        RECT  52.74 34.416 52.758 34.56 ;
    END
  END rd_data[810]
  PIN rd_data[811]
    DIRECTION INPUT ;
    USE SIGNAL ;
    PORT
      LAYER M5 ;
        RECT  50.88 34.368 50.904 34.56 ;
    END
  END rd_data[811]
  PIN rd_data[812]
    DIRECTION INPUT ;
    USE SIGNAL ;
    PORT
      LAYER M3 ;
        RECT  52.848 34.416 52.866 34.56 ;
    END
  END rd_data[812]
  PIN rd_data[813]
    DIRECTION INPUT ;
    USE SIGNAL ;
    PORT
      LAYER M5 ;
        RECT  50.976 34.368 51 34.56 ;
    END
  END rd_data[813]
  PIN rd_data[814]
    DIRECTION INPUT ;
    USE SIGNAL ;
    PORT
      LAYER M3 ;
        RECT  52.956 34.416 52.974 34.56 ;
    END
  END rd_data[814]
  PIN rd_data[815]
    DIRECTION INPUT ;
    USE SIGNAL ;
    PORT
      LAYER M5 ;
        RECT  51.072 34.368 51.096 34.56 ;
    END
  END rd_data[815]
  PIN rd_data[816]
    DIRECTION INPUT ;
    USE SIGNAL ;
    PORT
      LAYER M3 ;
        RECT  53.064 34.416 53.082 34.56 ;
    END
  END rd_data[816]
  PIN rd_data[817]
    DIRECTION INPUT ;
    USE SIGNAL ;
    PORT
      LAYER M5 ;
        RECT  51.168 34.368 51.192 34.56 ;
    END
  END rd_data[817]
  PIN rd_data[818]
    DIRECTION INPUT ;
    USE SIGNAL ;
    PORT
      LAYER M3 ;
        RECT  53.172 34.416 53.19 34.56 ;
    END
  END rd_data[818]
  PIN rd_data[819]
    DIRECTION INPUT ;
    USE SIGNAL ;
    PORT
      LAYER M5 ;
        RECT  51.264 34.368 51.288 34.56 ;
    END
  END rd_data[819]
  PIN rd_data[81]
    DIRECTION INPUT ;
    USE SIGNAL ;
    PORT
      LAYER M5 ;
        RECT  15.84 34.368 15.864 34.56 ;
    END
  END rd_data[81]
  PIN rd_data[820]
    DIRECTION INPUT ;
    USE SIGNAL ;
    PORT
      LAYER M3 ;
        RECT  53.28 34.416 53.298 34.56 ;
    END
  END rd_data[820]
  PIN rd_data[821]
    DIRECTION INPUT ;
    USE SIGNAL ;
    PORT
      LAYER M5 ;
        RECT  51.36 34.368 51.384 34.56 ;
    END
  END rd_data[821]
  PIN rd_data[822]
    DIRECTION INPUT ;
    USE SIGNAL ;
    PORT
      LAYER M3 ;
        RECT  53.388 34.416 53.406 34.56 ;
    END
  END rd_data[822]
  PIN rd_data[823]
    DIRECTION INPUT ;
    USE SIGNAL ;
    PORT
      LAYER M5 ;
        RECT  51.456 34.368 51.48 34.56 ;
    END
  END rd_data[823]
  PIN rd_data[824]
    DIRECTION INPUT ;
    USE SIGNAL ;
    PORT
      LAYER M3 ;
        RECT  53.496 34.416 53.514 34.56 ;
    END
  END rd_data[824]
  PIN rd_data[825]
    DIRECTION INPUT ;
    USE SIGNAL ;
    PORT
      LAYER M5 ;
        RECT  51.552 34.368 51.576 34.56 ;
    END
  END rd_data[825]
  PIN rd_data[826]
    DIRECTION INPUT ;
    USE SIGNAL ;
    PORT
      LAYER M3 ;
        RECT  53.604 34.416 53.622 34.56 ;
    END
  END rd_data[826]
  PIN rd_data[827]
    DIRECTION INPUT ;
    USE SIGNAL ;
    PORT
      LAYER M5 ;
        RECT  51.648 34.368 51.672 34.56 ;
    END
  END rd_data[827]
  PIN rd_data[828]
    DIRECTION INPUT ;
    USE SIGNAL ;
    PORT
      LAYER M3 ;
        RECT  53.712 34.416 53.73 34.56 ;
    END
  END rd_data[828]
  PIN rd_data[829]
    DIRECTION INPUT ;
    USE SIGNAL ;
    PORT
      LAYER M5 ;
        RECT  51.744 34.368 51.768 34.56 ;
    END
  END rd_data[829]
  PIN rd_data[82]
    DIRECTION INPUT ;
    USE SIGNAL ;
    PORT
      LAYER M3 ;
        RECT  13.428 34.416 13.446 34.56 ;
    END
  END rd_data[82]
  PIN rd_data[830]
    DIRECTION INPUT ;
    USE SIGNAL ;
    PORT
      LAYER M3 ;
        RECT  53.82 34.416 53.838 34.56 ;
    END
  END rd_data[830]
  PIN rd_data[831]
    DIRECTION INPUT ;
    USE SIGNAL ;
    PORT
      LAYER M5 ;
        RECT  51.84 34.368 51.864 34.56 ;
    END
  END rd_data[831]
  PIN rd_data[832]
    DIRECTION INPUT ;
    USE SIGNAL ;
    PORT
      LAYER M3 ;
        RECT  53.928 34.416 53.946 34.56 ;
    END
  END rd_data[832]
  PIN rd_data[833]
    DIRECTION INPUT ;
    USE SIGNAL ;
    PORT
      LAYER M5 ;
        RECT  51.936 34.368 51.96 34.56 ;
    END
  END rd_data[833]
  PIN rd_data[834]
    DIRECTION INPUT ;
    USE SIGNAL ;
    PORT
      LAYER M3 ;
        RECT  54.036 34.416 54.054 34.56 ;
    END
  END rd_data[834]
  PIN rd_data[835]
    DIRECTION INPUT ;
    USE SIGNAL ;
    PORT
      LAYER M5 ;
        RECT  52.032 34.368 52.056 34.56 ;
    END
  END rd_data[835]
  PIN rd_data[836]
    DIRECTION INPUT ;
    USE SIGNAL ;
    PORT
      LAYER M3 ;
        RECT  54.144 34.416 54.162 34.56 ;
    END
  END rd_data[836]
  PIN rd_data[837]
    DIRECTION INPUT ;
    USE SIGNAL ;
    PORT
      LAYER M5 ;
        RECT  52.128 34.368 52.152 34.56 ;
    END
  END rd_data[837]
  PIN rd_data[838]
    DIRECTION INPUT ;
    USE SIGNAL ;
    PORT
      LAYER M3 ;
        RECT  54.252 34.416 54.27 34.56 ;
    END
  END rd_data[838]
  PIN rd_data[839]
    DIRECTION INPUT ;
    USE SIGNAL ;
    PORT
      LAYER M5 ;
        RECT  52.224 34.368 52.248 34.56 ;
    END
  END rd_data[839]
  PIN rd_data[83]
    DIRECTION INPUT ;
    USE SIGNAL ;
    PORT
      LAYER M5 ;
        RECT  15.936 34.368 15.96 34.56 ;
    END
  END rd_data[83]
  PIN rd_data[840]
    DIRECTION INPUT ;
    USE SIGNAL ;
    PORT
      LAYER M3 ;
        RECT  54.36 34.416 54.378 34.56 ;
    END
  END rd_data[840]
  PIN rd_data[841]
    DIRECTION INPUT ;
    USE SIGNAL ;
    PORT
      LAYER M5 ;
        RECT  52.32 34.368 52.344 34.56 ;
    END
  END rd_data[841]
  PIN rd_data[842]
    DIRECTION INPUT ;
    USE SIGNAL ;
    PORT
      LAYER M3 ;
        RECT  54.468 34.416 54.486 34.56 ;
    END
  END rd_data[842]
  PIN rd_data[843]
    DIRECTION INPUT ;
    USE SIGNAL ;
    PORT
      LAYER M5 ;
        RECT  52.416 34.368 52.44 34.56 ;
    END
  END rd_data[843]
  PIN rd_data[844]
    DIRECTION INPUT ;
    USE SIGNAL ;
    PORT
      LAYER M3 ;
        RECT  54.576 34.416 54.594 34.56 ;
    END
  END rd_data[844]
  PIN rd_data[845]
    DIRECTION INPUT ;
    USE SIGNAL ;
    PORT
      LAYER M5 ;
        RECT  52.512 34.368 52.536 34.56 ;
    END
  END rd_data[845]
  PIN rd_data[846]
    DIRECTION INPUT ;
    USE SIGNAL ;
    PORT
      LAYER M3 ;
        RECT  54.684 34.416 54.702 34.56 ;
    END
  END rd_data[846]
  PIN rd_data[847]
    DIRECTION INPUT ;
    USE SIGNAL ;
    PORT
      LAYER M5 ;
        RECT  52.608 34.368 52.632 34.56 ;
    END
  END rd_data[847]
  PIN rd_data[848]
    DIRECTION INPUT ;
    USE SIGNAL ;
    PORT
      LAYER M3 ;
        RECT  54.792 34.416 54.81 34.56 ;
    END
  END rd_data[848]
  PIN rd_data[849]
    DIRECTION INPUT ;
    USE SIGNAL ;
    PORT
      LAYER M5 ;
        RECT  52.704 34.368 52.728 34.56 ;
    END
  END rd_data[849]
  PIN rd_data[84]
    DIRECTION INPUT ;
    USE SIGNAL ;
    PORT
      LAYER M3 ;
        RECT  13.536 34.416 13.554 34.56 ;
    END
  END rd_data[84]
  PIN rd_data[850]
    DIRECTION INPUT ;
    USE SIGNAL ;
    PORT
      LAYER M3 ;
        RECT  54.9 34.416 54.918 34.56 ;
    END
  END rd_data[850]
  PIN rd_data[851]
    DIRECTION INPUT ;
    USE SIGNAL ;
    PORT
      LAYER M5 ;
        RECT  52.8 34.368 52.824 34.56 ;
    END
  END rd_data[851]
  PIN rd_data[852]
    DIRECTION INPUT ;
    USE SIGNAL ;
    PORT
      LAYER M3 ;
        RECT  55.008 34.416 55.026 34.56 ;
    END
  END rd_data[852]
  PIN rd_data[853]
    DIRECTION INPUT ;
    USE SIGNAL ;
    PORT
      LAYER M5 ;
        RECT  52.896 34.368 52.92 34.56 ;
    END
  END rd_data[853]
  PIN rd_data[854]
    DIRECTION INPUT ;
    USE SIGNAL ;
    PORT
      LAYER M3 ;
        RECT  55.116 34.416 55.134 34.56 ;
    END
  END rd_data[854]
  PIN rd_data[855]
    DIRECTION INPUT ;
    USE SIGNAL ;
    PORT
      LAYER M5 ;
        RECT  52.992 34.368 53.016 34.56 ;
    END
  END rd_data[855]
  PIN rd_data[856]
    DIRECTION INPUT ;
    USE SIGNAL ;
    PORT
      LAYER M3 ;
        RECT  55.224 34.416 55.242 34.56 ;
    END
  END rd_data[856]
  PIN rd_data[857]
    DIRECTION INPUT ;
    USE SIGNAL ;
    PORT
      LAYER M5 ;
        RECT  53.088 34.368 53.112 34.56 ;
    END
  END rd_data[857]
  PIN rd_data[858]
    DIRECTION INPUT ;
    USE SIGNAL ;
    PORT
      LAYER M3 ;
        RECT  55.332 34.416 55.35 34.56 ;
    END
  END rd_data[858]
  PIN rd_data[859]
    DIRECTION INPUT ;
    USE SIGNAL ;
    PORT
      LAYER M5 ;
        RECT  53.184 34.368 53.208 34.56 ;
    END
  END rd_data[859]
  PIN rd_data[85]
    DIRECTION INPUT ;
    USE SIGNAL ;
    PORT
      LAYER M5 ;
        RECT  16.032 34.368 16.056 34.56 ;
    END
  END rd_data[85]
  PIN rd_data[860]
    DIRECTION INPUT ;
    USE SIGNAL ;
    PORT
      LAYER M3 ;
        RECT  55.44 34.416 55.458 34.56 ;
    END
  END rd_data[860]
  PIN rd_data[861]
    DIRECTION INPUT ;
    USE SIGNAL ;
    PORT
      LAYER M5 ;
        RECT  53.28 34.368 53.304 34.56 ;
    END
  END rd_data[861]
  PIN rd_data[862]
    DIRECTION INPUT ;
    USE SIGNAL ;
    PORT
      LAYER M3 ;
        RECT  55.548 34.416 55.566 34.56 ;
    END
  END rd_data[862]
  PIN rd_data[863]
    DIRECTION INPUT ;
    USE SIGNAL ;
    PORT
      LAYER M5 ;
        RECT  53.376 34.368 53.4 34.56 ;
    END
  END rd_data[863]
  PIN rd_data[864]
    DIRECTION INPUT ;
    USE SIGNAL ;
    PORT
      LAYER M3 ;
        RECT  55.656 34.416 55.674 34.56 ;
    END
  END rd_data[864]
  PIN rd_data[865]
    DIRECTION INPUT ;
    USE SIGNAL ;
    PORT
      LAYER M5 ;
        RECT  53.472 34.368 53.496 34.56 ;
    END
  END rd_data[865]
  PIN rd_data[866]
    DIRECTION INPUT ;
    USE SIGNAL ;
    PORT
      LAYER M3 ;
        RECT  55.764 34.416 55.782 34.56 ;
    END
  END rd_data[866]
  PIN rd_data[867]
    DIRECTION INPUT ;
    USE SIGNAL ;
    PORT
      LAYER M5 ;
        RECT  53.568 34.368 53.592 34.56 ;
    END
  END rd_data[867]
  PIN rd_data[868]
    DIRECTION INPUT ;
    USE SIGNAL ;
    PORT
      LAYER M3 ;
        RECT  55.872 34.416 55.89 34.56 ;
    END
  END rd_data[868]
  PIN rd_data[869]
    DIRECTION INPUT ;
    USE SIGNAL ;
    PORT
      LAYER M5 ;
        RECT  53.664 34.368 53.688 34.56 ;
    END
  END rd_data[869]
  PIN rd_data[86]
    DIRECTION INPUT ;
    USE SIGNAL ;
    PORT
      LAYER M3 ;
        RECT  13.644 34.416 13.662 34.56 ;
    END
  END rd_data[86]
  PIN rd_data[870]
    DIRECTION INPUT ;
    USE SIGNAL ;
    PORT
      LAYER M3 ;
        RECT  55.98 34.416 55.998 34.56 ;
    END
  END rd_data[870]
  PIN rd_data[871]
    DIRECTION INPUT ;
    USE SIGNAL ;
    PORT
      LAYER M5 ;
        RECT  53.76 34.368 53.784 34.56 ;
    END
  END rd_data[871]
  PIN rd_data[872]
    DIRECTION INPUT ;
    USE SIGNAL ;
    PORT
      LAYER M3 ;
        RECT  56.088 34.416 56.106 34.56 ;
    END
  END rd_data[872]
  PIN rd_data[873]
    DIRECTION INPUT ;
    USE SIGNAL ;
    PORT
      LAYER M5 ;
        RECT  53.856 34.368 53.88 34.56 ;
    END
  END rd_data[873]
  PIN rd_data[874]
    DIRECTION INPUT ;
    USE SIGNAL ;
    PORT
      LAYER M3 ;
        RECT  56.196 34.416 56.214 34.56 ;
    END
  END rd_data[874]
  PIN rd_data[875]
    DIRECTION INPUT ;
    USE SIGNAL ;
    PORT
      LAYER M5 ;
        RECT  53.952 34.368 53.976 34.56 ;
    END
  END rd_data[875]
  PIN rd_data[876]
    DIRECTION INPUT ;
    USE SIGNAL ;
    PORT
      LAYER M3 ;
        RECT  56.304 34.416 56.322 34.56 ;
    END
  END rd_data[876]
  PIN rd_data[877]
    DIRECTION INPUT ;
    USE SIGNAL ;
    PORT
      LAYER M5 ;
        RECT  54.048 34.368 54.072 34.56 ;
    END
  END rd_data[877]
  PIN rd_data[878]
    DIRECTION INPUT ;
    USE SIGNAL ;
    PORT
      LAYER M3 ;
        RECT  56.412 34.416 56.43 34.56 ;
    END
  END rd_data[878]
  PIN rd_data[879]
    DIRECTION INPUT ;
    USE SIGNAL ;
    PORT
      LAYER M5 ;
        RECT  54.144 34.368 54.168 34.56 ;
    END
  END rd_data[879]
  PIN rd_data[87]
    DIRECTION INPUT ;
    USE SIGNAL ;
    PORT
      LAYER M5 ;
        RECT  16.128 34.368 16.152 34.56 ;
    END
  END rd_data[87]
  PIN rd_data[880]
    DIRECTION INPUT ;
    USE SIGNAL ;
    PORT
      LAYER M3 ;
        RECT  56.52 34.416 56.538 34.56 ;
    END
  END rd_data[880]
  PIN rd_data[881]
    DIRECTION INPUT ;
    USE SIGNAL ;
    PORT
      LAYER M5 ;
        RECT  54.24 34.368 54.264 34.56 ;
    END
  END rd_data[881]
  PIN rd_data[882]
    DIRECTION INPUT ;
    USE SIGNAL ;
    PORT
      LAYER M3 ;
        RECT  56.628 34.416 56.646 34.56 ;
    END
  END rd_data[882]
  PIN rd_data[883]
    DIRECTION INPUT ;
    USE SIGNAL ;
    PORT
      LAYER M5 ;
        RECT  54.336 34.368 54.36 34.56 ;
    END
  END rd_data[883]
  PIN rd_data[884]
    DIRECTION INPUT ;
    USE SIGNAL ;
    PORT
      LAYER M3 ;
        RECT  56.736 34.416 56.754 34.56 ;
    END
  END rd_data[884]
  PIN rd_data[885]
    DIRECTION INPUT ;
    USE SIGNAL ;
    PORT
      LAYER M5 ;
        RECT  54.432 34.368 54.456 34.56 ;
    END
  END rd_data[885]
  PIN rd_data[886]
    DIRECTION INPUT ;
    USE SIGNAL ;
    PORT
      LAYER M3 ;
        RECT  56.844 34.416 56.862 34.56 ;
    END
  END rd_data[886]
  PIN rd_data[887]
    DIRECTION INPUT ;
    USE SIGNAL ;
    PORT
      LAYER M5 ;
        RECT  54.528 34.368 54.552 34.56 ;
    END
  END rd_data[887]
  PIN rd_data[888]
    DIRECTION INPUT ;
    USE SIGNAL ;
    PORT
      LAYER M3 ;
        RECT  56.952 34.416 56.97 34.56 ;
    END
  END rd_data[888]
  PIN rd_data[889]
    DIRECTION INPUT ;
    USE SIGNAL ;
    PORT
      LAYER M5 ;
        RECT  54.624 34.368 54.648 34.56 ;
    END
  END rd_data[889]
  PIN rd_data[88]
    DIRECTION INPUT ;
    USE SIGNAL ;
    PORT
      LAYER M3 ;
        RECT  13.752 34.416 13.77 34.56 ;
    END
  END rd_data[88]
  PIN rd_data[890]
    DIRECTION INPUT ;
    USE SIGNAL ;
    PORT
      LAYER M3 ;
        RECT  57.06 34.416 57.078 34.56 ;
    END
  END rd_data[890]
  PIN rd_data[891]
    DIRECTION INPUT ;
    USE SIGNAL ;
    PORT
      LAYER M5 ;
        RECT  54.72 34.368 54.744 34.56 ;
    END
  END rd_data[891]
  PIN rd_data[892]
    DIRECTION INPUT ;
    USE SIGNAL ;
    PORT
      LAYER M3 ;
        RECT  57.168 34.416 57.186 34.56 ;
    END
  END rd_data[892]
  PIN rd_data[893]
    DIRECTION INPUT ;
    USE SIGNAL ;
    PORT
      LAYER M5 ;
        RECT  54.816 34.368 54.84 34.56 ;
    END
  END rd_data[893]
  PIN rd_data[894]
    DIRECTION INPUT ;
    USE SIGNAL ;
    PORT
      LAYER M3 ;
        RECT  57.276 34.416 57.294 34.56 ;
    END
  END rd_data[894]
  PIN rd_data[895]
    DIRECTION INPUT ;
    USE SIGNAL ;
    PORT
      LAYER M5 ;
        RECT  54.912 34.368 54.936 34.56 ;
    END
  END rd_data[895]
  PIN rd_data[896]
    DIRECTION INPUT ;
    USE SIGNAL ;
    PORT
      LAYER M3 ;
        RECT  57.384 34.416 57.402 34.56 ;
    END
  END rd_data[896]
  PIN rd_data[897]
    DIRECTION INPUT ;
    USE SIGNAL ;
    PORT
      LAYER M5 ;
        RECT  55.008 34.368 55.032 34.56 ;
    END
  END rd_data[897]
  PIN rd_data[898]
    DIRECTION INPUT ;
    USE SIGNAL ;
    PORT
      LAYER M3 ;
        RECT  57.492 34.416 57.51 34.56 ;
    END
  END rd_data[898]
  PIN rd_data[899]
    DIRECTION INPUT ;
    USE SIGNAL ;
    PORT
      LAYER M5 ;
        RECT  55.104 34.368 55.128 34.56 ;
    END
  END rd_data[899]
  PIN rd_data[89]
    DIRECTION INPUT ;
    USE SIGNAL ;
    PORT
      LAYER M5 ;
        RECT  16.224 34.368 16.248 34.56 ;
    END
  END rd_data[89]
  PIN rd_data[8]
    DIRECTION INPUT ;
    USE SIGNAL ;
    PORT
      LAYER M3 ;
        RECT  9.432 34.416 9.45 34.56 ;
    END
  END rd_data[8]
  PIN rd_data[900]
    DIRECTION INPUT ;
    USE SIGNAL ;
    PORT
      LAYER M3 ;
        RECT  57.6 34.416 57.618 34.56 ;
    END
  END rd_data[900]
  PIN rd_data[901]
    DIRECTION INPUT ;
    USE SIGNAL ;
    PORT
      LAYER M5 ;
        RECT  55.2 34.368 55.224 34.56 ;
    END
  END rd_data[901]
  PIN rd_data[902]
    DIRECTION INPUT ;
    USE SIGNAL ;
    PORT
      LAYER M3 ;
        RECT  57.708 34.416 57.726 34.56 ;
    END
  END rd_data[902]
  PIN rd_data[903]
    DIRECTION INPUT ;
    USE SIGNAL ;
    PORT
      LAYER M5 ;
        RECT  55.296 34.368 55.32 34.56 ;
    END
  END rd_data[903]
  PIN rd_data[904]
    DIRECTION INPUT ;
    USE SIGNAL ;
    PORT
      LAYER M3 ;
        RECT  57.816 34.416 57.834 34.56 ;
    END
  END rd_data[904]
  PIN rd_data[905]
    DIRECTION INPUT ;
    USE SIGNAL ;
    PORT
      LAYER M5 ;
        RECT  55.392 34.368 55.416 34.56 ;
    END
  END rd_data[905]
  PIN rd_data[906]
    DIRECTION INPUT ;
    USE SIGNAL ;
    PORT
      LAYER M3 ;
        RECT  57.924 34.416 57.942 34.56 ;
    END
  END rd_data[906]
  PIN rd_data[907]
    DIRECTION INPUT ;
    USE SIGNAL ;
    PORT
      LAYER M5 ;
        RECT  55.488 34.368 55.512 34.56 ;
    END
  END rd_data[907]
  PIN rd_data[908]
    DIRECTION INPUT ;
    USE SIGNAL ;
    PORT
      LAYER M3 ;
        RECT  58.032 34.416 58.05 34.56 ;
    END
  END rd_data[908]
  PIN rd_data[909]
    DIRECTION INPUT ;
    USE SIGNAL ;
    PORT
      LAYER M5 ;
        RECT  55.584 34.368 55.608 34.56 ;
    END
  END rd_data[909]
  PIN rd_data[90]
    DIRECTION INPUT ;
    USE SIGNAL ;
    PORT
      LAYER M3 ;
        RECT  13.86 34.416 13.878 34.56 ;
    END
  END rd_data[90]
  PIN rd_data[910]
    DIRECTION INPUT ;
    USE SIGNAL ;
    PORT
      LAYER M3 ;
        RECT  58.14 34.416 58.158 34.56 ;
    END
  END rd_data[910]
  PIN rd_data[911]
    DIRECTION INPUT ;
    USE SIGNAL ;
    PORT
      LAYER M5 ;
        RECT  55.68 34.368 55.704 34.56 ;
    END
  END rd_data[911]
  PIN rd_data[912]
    DIRECTION INPUT ;
    USE SIGNAL ;
    PORT
      LAYER M3 ;
        RECT  58.248 34.416 58.266 34.56 ;
    END
  END rd_data[912]
  PIN rd_data[913]
    DIRECTION INPUT ;
    USE SIGNAL ;
    PORT
      LAYER M5 ;
        RECT  55.776 34.368 55.8 34.56 ;
    END
  END rd_data[913]
  PIN rd_data[914]
    DIRECTION INPUT ;
    USE SIGNAL ;
    PORT
      LAYER M3 ;
        RECT  58.356 34.416 58.374 34.56 ;
    END
  END rd_data[914]
  PIN rd_data[915]
    DIRECTION INPUT ;
    USE SIGNAL ;
    PORT
      LAYER M5 ;
        RECT  55.872 34.368 55.896 34.56 ;
    END
  END rd_data[915]
  PIN rd_data[916]
    DIRECTION INPUT ;
    USE SIGNAL ;
    PORT
      LAYER M3 ;
        RECT  58.464 34.416 58.482 34.56 ;
    END
  END rd_data[916]
  PIN rd_data[917]
    DIRECTION INPUT ;
    USE SIGNAL ;
    PORT
      LAYER M5 ;
        RECT  55.968 34.368 55.992 34.56 ;
    END
  END rd_data[917]
  PIN rd_data[918]
    DIRECTION INPUT ;
    USE SIGNAL ;
    PORT
      LAYER M3 ;
        RECT  58.572 34.416 58.59 34.56 ;
    END
  END rd_data[918]
  PIN rd_data[919]
    DIRECTION INPUT ;
    USE SIGNAL ;
    PORT
      LAYER M5 ;
        RECT  56.064 34.368 56.088 34.56 ;
    END
  END rd_data[919]
  PIN rd_data[91]
    DIRECTION INPUT ;
    USE SIGNAL ;
    PORT
      LAYER M5 ;
        RECT  16.32 34.368 16.344 34.56 ;
    END
  END rd_data[91]
  PIN rd_data[920]
    DIRECTION INPUT ;
    USE SIGNAL ;
    PORT
      LAYER M3 ;
        RECT  58.68 34.416 58.698 34.56 ;
    END
  END rd_data[920]
  PIN rd_data[921]
    DIRECTION INPUT ;
    USE SIGNAL ;
    PORT
      LAYER M5 ;
        RECT  56.16 34.368 56.184 34.56 ;
    END
  END rd_data[921]
  PIN rd_data[922]
    DIRECTION INPUT ;
    USE SIGNAL ;
    PORT
      LAYER M3 ;
        RECT  58.788 34.416 58.806 34.56 ;
    END
  END rd_data[922]
  PIN rd_data[923]
    DIRECTION INPUT ;
    USE SIGNAL ;
    PORT
      LAYER M5 ;
        RECT  56.256 34.368 56.28 34.56 ;
    END
  END rd_data[923]
  PIN rd_data[924]
    DIRECTION INPUT ;
    USE SIGNAL ;
    PORT
      LAYER M3 ;
        RECT  58.896 34.416 58.914 34.56 ;
    END
  END rd_data[924]
  PIN rd_data[925]
    DIRECTION INPUT ;
    USE SIGNAL ;
    PORT
      LAYER M5 ;
        RECT  56.352 34.368 56.376 34.56 ;
    END
  END rd_data[925]
  PIN rd_data[926]
    DIRECTION INPUT ;
    USE SIGNAL ;
    PORT
      LAYER M3 ;
        RECT  59.004 34.416 59.022 34.56 ;
    END
  END rd_data[926]
  PIN rd_data[927]
    DIRECTION INPUT ;
    USE SIGNAL ;
    PORT
      LAYER M5 ;
        RECT  56.448 34.368 56.472 34.56 ;
    END
  END rd_data[927]
  PIN rd_data[928]
    DIRECTION INPUT ;
    USE SIGNAL ;
    PORT
      LAYER M3 ;
        RECT  59.112 34.416 59.13 34.56 ;
    END
  END rd_data[928]
  PIN rd_data[929]
    DIRECTION INPUT ;
    USE SIGNAL ;
    PORT
      LAYER M5 ;
        RECT  56.544 34.368 56.568 34.56 ;
    END
  END rd_data[929]
  PIN rd_data[92]
    DIRECTION INPUT ;
    USE SIGNAL ;
    PORT
      LAYER M3 ;
        RECT  13.968 34.416 13.986 34.56 ;
    END
  END rd_data[92]
  PIN rd_data[930]
    DIRECTION INPUT ;
    USE SIGNAL ;
    PORT
      LAYER M3 ;
        RECT  59.22 34.416 59.238 34.56 ;
    END
  END rd_data[930]
  PIN rd_data[931]
    DIRECTION INPUT ;
    USE SIGNAL ;
    PORT
      LAYER M5 ;
        RECT  56.64 34.368 56.664 34.56 ;
    END
  END rd_data[931]
  PIN rd_data[932]
    DIRECTION INPUT ;
    USE SIGNAL ;
    PORT
      LAYER M3 ;
        RECT  59.328 34.416 59.346 34.56 ;
    END
  END rd_data[932]
  PIN rd_data[933]
    DIRECTION INPUT ;
    USE SIGNAL ;
    PORT
      LAYER M5 ;
        RECT  56.736 34.368 56.76 34.56 ;
    END
  END rd_data[933]
  PIN rd_data[934]
    DIRECTION INPUT ;
    USE SIGNAL ;
    PORT
      LAYER M3 ;
        RECT  59.436 34.416 59.454 34.56 ;
    END
  END rd_data[934]
  PIN rd_data[935]
    DIRECTION INPUT ;
    USE SIGNAL ;
    PORT
      LAYER M5 ;
        RECT  56.832 34.368 56.856 34.56 ;
    END
  END rd_data[935]
  PIN rd_data[936]
    DIRECTION INPUT ;
    USE SIGNAL ;
    PORT
      LAYER M3 ;
        RECT  59.544 34.416 59.562 34.56 ;
    END
  END rd_data[936]
  PIN rd_data[937]
    DIRECTION INPUT ;
    USE SIGNAL ;
    PORT
      LAYER M5 ;
        RECT  56.928 34.368 56.952 34.56 ;
    END
  END rd_data[937]
  PIN rd_data[938]
    DIRECTION INPUT ;
    USE SIGNAL ;
    PORT
      LAYER M3 ;
        RECT  59.652 34.416 59.67 34.56 ;
    END
  END rd_data[938]
  PIN rd_data[939]
    DIRECTION INPUT ;
    USE SIGNAL ;
    PORT
      LAYER M5 ;
        RECT  57.024 34.368 57.048 34.56 ;
    END
  END rd_data[939]
  PIN rd_data[93]
    DIRECTION INPUT ;
    USE SIGNAL ;
    PORT
      LAYER M5 ;
        RECT  16.416 34.368 16.44 34.56 ;
    END
  END rd_data[93]
  PIN rd_data[940]
    DIRECTION INPUT ;
    USE SIGNAL ;
    PORT
      LAYER M3 ;
        RECT  59.76 34.416 59.778 34.56 ;
    END
  END rd_data[940]
  PIN rd_data[941]
    DIRECTION INPUT ;
    USE SIGNAL ;
    PORT
      LAYER M5 ;
        RECT  57.12 34.368 57.144 34.56 ;
    END
  END rd_data[941]
  PIN rd_data[942]
    DIRECTION INPUT ;
    USE SIGNAL ;
    PORT
      LAYER M3 ;
        RECT  59.868 34.416 59.886 34.56 ;
    END
  END rd_data[942]
  PIN rd_data[943]
    DIRECTION INPUT ;
    USE SIGNAL ;
    PORT
      LAYER M5 ;
        RECT  57.216 34.368 57.24 34.56 ;
    END
  END rd_data[943]
  PIN rd_data[944]
    DIRECTION INPUT ;
    USE SIGNAL ;
    PORT
      LAYER M3 ;
        RECT  59.976 34.416 59.994 34.56 ;
    END
  END rd_data[944]
  PIN rd_data[945]
    DIRECTION INPUT ;
    USE SIGNAL ;
    PORT
      LAYER M5 ;
        RECT  57.312 34.368 57.336 34.56 ;
    END
  END rd_data[945]
  PIN rd_data[946]
    DIRECTION INPUT ;
    USE SIGNAL ;
    PORT
      LAYER M3 ;
        RECT  60.084 34.416 60.102 34.56 ;
    END
  END rd_data[946]
  PIN rd_data[947]
    DIRECTION INPUT ;
    USE SIGNAL ;
    PORT
      LAYER M5 ;
        RECT  57.408 34.368 57.432 34.56 ;
    END
  END rd_data[947]
  PIN rd_data[948]
    DIRECTION INPUT ;
    USE SIGNAL ;
    PORT
      LAYER M3 ;
        RECT  60.192 34.416 60.21 34.56 ;
    END
  END rd_data[948]
  PIN rd_data[949]
    DIRECTION INPUT ;
    USE SIGNAL ;
    PORT
      LAYER M5 ;
        RECT  57.504 34.368 57.528 34.56 ;
    END
  END rd_data[949]
  PIN rd_data[94]
    DIRECTION INPUT ;
    USE SIGNAL ;
    PORT
      LAYER M3 ;
        RECT  14.076 34.416 14.094 34.56 ;
    END
  END rd_data[94]
  PIN rd_data[950]
    DIRECTION INPUT ;
    USE SIGNAL ;
    PORT
      LAYER M3 ;
        RECT  60.3 34.416 60.318 34.56 ;
    END
  END rd_data[950]
  PIN rd_data[951]
    DIRECTION INPUT ;
    USE SIGNAL ;
    PORT
      LAYER M5 ;
        RECT  57.6 34.368 57.624 34.56 ;
    END
  END rd_data[951]
  PIN rd_data[952]
    DIRECTION INPUT ;
    USE SIGNAL ;
    PORT
      LAYER M3 ;
        RECT  60.408 34.416 60.426 34.56 ;
    END
  END rd_data[952]
  PIN rd_data[953]
    DIRECTION INPUT ;
    USE SIGNAL ;
    PORT
      LAYER M5 ;
        RECT  57.696 34.368 57.72 34.56 ;
    END
  END rd_data[953]
  PIN rd_data[954]
    DIRECTION INPUT ;
    USE SIGNAL ;
    PORT
      LAYER M3 ;
        RECT  60.516 34.416 60.534 34.56 ;
    END
  END rd_data[954]
  PIN rd_data[955]
    DIRECTION INPUT ;
    USE SIGNAL ;
    PORT
      LAYER M5 ;
        RECT  57.792 34.368 57.816 34.56 ;
    END
  END rd_data[955]
  PIN rd_data[956]
    DIRECTION INPUT ;
    USE SIGNAL ;
    PORT
      LAYER M3 ;
        RECT  60.624 34.416 60.642 34.56 ;
    END
  END rd_data[956]
  PIN rd_data[957]
    DIRECTION INPUT ;
    USE SIGNAL ;
    PORT
      LAYER M5 ;
        RECT  57.888 34.368 57.912 34.56 ;
    END
  END rd_data[957]
  PIN rd_data[958]
    DIRECTION INPUT ;
    USE SIGNAL ;
    PORT
      LAYER M3 ;
        RECT  60.732 34.416 60.75 34.56 ;
    END
  END rd_data[958]
  PIN rd_data[959]
    DIRECTION INPUT ;
    USE SIGNAL ;
    PORT
      LAYER M5 ;
        RECT  57.984 34.368 58.008 34.56 ;
    END
  END rd_data[959]
  PIN rd_data[95]
    DIRECTION INPUT ;
    USE SIGNAL ;
    PORT
      LAYER M5 ;
        RECT  16.512 34.368 16.536 34.56 ;
    END
  END rd_data[95]
  PIN rd_data[960]
    DIRECTION INPUT ;
    USE SIGNAL ;
    PORT
      LAYER M3 ;
        RECT  60.84 34.416 60.858 34.56 ;
    END
  END rd_data[960]
  PIN rd_data[961]
    DIRECTION INPUT ;
    USE SIGNAL ;
    PORT
      LAYER M5 ;
        RECT  58.08 34.368 58.104 34.56 ;
    END
  END rd_data[961]
  PIN rd_data[962]
    DIRECTION INPUT ;
    USE SIGNAL ;
    PORT
      LAYER M3 ;
        RECT  60.948 34.416 60.966 34.56 ;
    END
  END rd_data[962]
  PIN rd_data[963]
    DIRECTION INPUT ;
    USE SIGNAL ;
    PORT
      LAYER M5 ;
        RECT  58.176 34.368 58.2 34.56 ;
    END
  END rd_data[963]
  PIN rd_data[964]
    DIRECTION INPUT ;
    USE SIGNAL ;
    PORT
      LAYER M3 ;
        RECT  61.056 34.416 61.074 34.56 ;
    END
  END rd_data[964]
  PIN rd_data[965]
    DIRECTION INPUT ;
    USE SIGNAL ;
    PORT
      LAYER M5 ;
        RECT  58.272 34.368 58.296 34.56 ;
    END
  END rd_data[965]
  PIN rd_data[966]
    DIRECTION INPUT ;
    USE SIGNAL ;
    PORT
      LAYER M3 ;
        RECT  61.164 34.416 61.182 34.56 ;
    END
  END rd_data[966]
  PIN rd_data[967]
    DIRECTION INPUT ;
    USE SIGNAL ;
    PORT
      LAYER M5 ;
        RECT  58.368 34.368 58.392 34.56 ;
    END
  END rd_data[967]
  PIN rd_data[968]
    DIRECTION INPUT ;
    USE SIGNAL ;
    PORT
      LAYER M3 ;
        RECT  61.272 34.416 61.29 34.56 ;
    END
  END rd_data[968]
  PIN rd_data[969]
    DIRECTION INPUT ;
    USE SIGNAL ;
    PORT
      LAYER M5 ;
        RECT  58.464 34.368 58.488 34.56 ;
    END
  END rd_data[969]
  PIN rd_data[96]
    DIRECTION INPUT ;
    USE SIGNAL ;
    PORT
      LAYER M3 ;
        RECT  14.184 34.416 14.202 34.56 ;
    END
  END rd_data[96]
  PIN rd_data[970]
    DIRECTION INPUT ;
    USE SIGNAL ;
    PORT
      LAYER M3 ;
        RECT  61.38 34.416 61.398 34.56 ;
    END
  END rd_data[970]
  PIN rd_data[971]
    DIRECTION INPUT ;
    USE SIGNAL ;
    PORT
      LAYER M5 ;
        RECT  58.56 34.368 58.584 34.56 ;
    END
  END rd_data[971]
  PIN rd_data[972]
    DIRECTION INPUT ;
    USE SIGNAL ;
    PORT
      LAYER M3 ;
        RECT  61.488 34.416 61.506 34.56 ;
    END
  END rd_data[972]
  PIN rd_data[973]
    DIRECTION INPUT ;
    USE SIGNAL ;
    PORT
      LAYER M5 ;
        RECT  58.656 34.368 58.68 34.56 ;
    END
  END rd_data[973]
  PIN rd_data[974]
    DIRECTION INPUT ;
    USE SIGNAL ;
    PORT
      LAYER M3 ;
        RECT  61.596 34.416 61.614 34.56 ;
    END
  END rd_data[974]
  PIN rd_data[975]
    DIRECTION INPUT ;
    USE SIGNAL ;
    PORT
      LAYER M5 ;
        RECT  58.752 34.368 58.776 34.56 ;
    END
  END rd_data[975]
  PIN rd_data[976]
    DIRECTION INPUT ;
    USE SIGNAL ;
    PORT
      LAYER M3 ;
        RECT  61.704 34.416 61.722 34.56 ;
    END
  END rd_data[976]
  PIN rd_data[977]
    DIRECTION INPUT ;
    USE SIGNAL ;
    PORT
      LAYER M5 ;
        RECT  58.848 34.368 58.872 34.56 ;
    END
  END rd_data[977]
  PIN rd_data[978]
    DIRECTION INPUT ;
    USE SIGNAL ;
    PORT
      LAYER M3 ;
        RECT  61.812 34.416 61.83 34.56 ;
    END
  END rd_data[978]
  PIN rd_data[979]
    DIRECTION INPUT ;
    USE SIGNAL ;
    PORT
      LAYER M5 ;
        RECT  58.944 34.368 58.968 34.56 ;
    END
  END rd_data[979]
  PIN rd_data[97]
    DIRECTION INPUT ;
    USE SIGNAL ;
    PORT
      LAYER M5 ;
        RECT  16.608 34.368 16.632 34.56 ;
    END
  END rd_data[97]
  PIN rd_data[980]
    DIRECTION INPUT ;
    USE SIGNAL ;
    PORT
      LAYER M3 ;
        RECT  61.92 34.416 61.938 34.56 ;
    END
  END rd_data[980]
  PIN rd_data[981]
    DIRECTION INPUT ;
    USE SIGNAL ;
    PORT
      LAYER M5 ;
        RECT  59.04 34.368 59.064 34.56 ;
    END
  END rd_data[981]
  PIN rd_data[982]
    DIRECTION INPUT ;
    USE SIGNAL ;
    PORT
      LAYER M3 ;
        RECT  62.028 34.416 62.046 34.56 ;
    END
  END rd_data[982]
  PIN rd_data[983]
    DIRECTION INPUT ;
    USE SIGNAL ;
    PORT
      LAYER M5 ;
        RECT  59.136 34.368 59.16 34.56 ;
    END
  END rd_data[983]
  PIN rd_data[984]
    DIRECTION INPUT ;
    USE SIGNAL ;
    PORT
      LAYER M3 ;
        RECT  62.136 34.416 62.154 34.56 ;
    END
  END rd_data[984]
  PIN rd_data[985]
    DIRECTION INPUT ;
    USE SIGNAL ;
    PORT
      LAYER M5 ;
        RECT  59.232 34.368 59.256 34.56 ;
    END
  END rd_data[985]
  PIN rd_data[986]
    DIRECTION INPUT ;
    USE SIGNAL ;
    PORT
      LAYER M3 ;
        RECT  62.244 34.416 62.262 34.56 ;
    END
  END rd_data[986]
  PIN rd_data[987]
    DIRECTION INPUT ;
    USE SIGNAL ;
    PORT
      LAYER M5 ;
        RECT  59.328 34.368 59.352 34.56 ;
    END
  END rd_data[987]
  PIN rd_data[988]
    DIRECTION INPUT ;
    USE SIGNAL ;
    PORT
      LAYER M3 ;
        RECT  62.352 34.416 62.37 34.56 ;
    END
  END rd_data[988]
  PIN rd_data[989]
    DIRECTION INPUT ;
    USE SIGNAL ;
    PORT
      LAYER M5 ;
        RECT  59.424 34.368 59.448 34.56 ;
    END
  END rd_data[989]
  PIN rd_data[98]
    DIRECTION INPUT ;
    USE SIGNAL ;
    PORT
      LAYER M3 ;
        RECT  14.292 34.416 14.31 34.56 ;
    END
  END rd_data[98]
  PIN rd_data[990]
    DIRECTION INPUT ;
    USE SIGNAL ;
    PORT
      LAYER M3 ;
        RECT  62.46 34.416 62.478 34.56 ;
    END
  END rd_data[990]
  PIN rd_data[991]
    DIRECTION INPUT ;
    USE SIGNAL ;
    PORT
      LAYER M5 ;
        RECT  59.52 34.368 59.544 34.56 ;
    END
  END rd_data[991]
  PIN rd_data[992]
    DIRECTION INPUT ;
    USE SIGNAL ;
    PORT
      LAYER M3 ;
        RECT  62.568 34.416 62.586 34.56 ;
    END
  END rd_data[992]
  PIN rd_data[993]
    DIRECTION INPUT ;
    USE SIGNAL ;
    PORT
      LAYER M5 ;
        RECT  59.616 34.368 59.64 34.56 ;
    END
  END rd_data[993]
  PIN rd_data[994]
    DIRECTION INPUT ;
    USE SIGNAL ;
    PORT
      LAYER M3 ;
        RECT  62.676 34.416 62.694 34.56 ;
    END
  END rd_data[994]
  PIN rd_data[995]
    DIRECTION INPUT ;
    USE SIGNAL ;
    PORT
      LAYER M5 ;
        RECT  59.712 34.368 59.736 34.56 ;
    END
  END rd_data[995]
  PIN rd_data[996]
    DIRECTION INPUT ;
    USE SIGNAL ;
    PORT
      LAYER M3 ;
        RECT  62.784 34.416 62.802 34.56 ;
    END
  END rd_data[996]
  PIN rd_data[997]
    DIRECTION INPUT ;
    USE SIGNAL ;
    PORT
      LAYER M5 ;
        RECT  59.808 34.368 59.832 34.56 ;
    END
  END rd_data[997]
  PIN rd_data[998]
    DIRECTION INPUT ;
    USE SIGNAL ;
    PORT
      LAYER M3 ;
        RECT  62.892 34.416 62.91 34.56 ;
    END
  END rd_data[998]
  PIN rd_data[999]
    DIRECTION INPUT ;
    USE SIGNAL ;
    PORT
      LAYER M5 ;
        RECT  59.904 34.368 59.928 34.56 ;
    END
  END rd_data[999]
  PIN rd_data[99]
    DIRECTION INPUT ;
    USE SIGNAL ;
    PORT
      LAYER M5 ;
        RECT  16.704 34.368 16.728 34.56 ;
    END
  END rd_data[99]
  PIN rd_data[9]
    DIRECTION INPUT ;
    USE SIGNAL ;
    PORT
      LAYER M5 ;
        RECT  12.384 34.368 12.408 34.56 ;
    END
  END rd_data[9]
  PIN rq0[0]
    DIRECTION OUTPUT ;
    USE SIGNAL ;
    PORT
      LAYER M4 ;
        RECT  73.248 14.736 73.44 14.76 ;
    END
  END rq0[0]
  PIN rq0[1]
    DIRECTION OUTPUT ;
    USE SIGNAL ;
    PORT
      LAYER M4 ;
        RECT  73.248 14.592 73.44 14.616 ;
    END
  END rq0[1]
  PIN rq0[2]
    DIRECTION OUTPUT ;
    USE SIGNAL ;
    PORT
      LAYER M4 ;
        RECT  73.248 14.448 73.44 14.472 ;
    END
  END rq0[2]
  PIN rq0[3]
    DIRECTION OUTPUT ;
    USE SIGNAL ;
    PORT
      LAYER M4 ;
        RECT  73.248 14.304 73.44 14.328 ;
    END
  END rq0[3]
  PIN rq1[0]
    DIRECTION OUTPUT ;
    USE SIGNAL ;
    PORT
      LAYER M4 ;
        RECT  73.248 14.16 73.44 14.184 ;
    END
  END rq1[0]
  PIN rq1[1]
    DIRECTION OUTPUT ;
    USE SIGNAL ;
    PORT
      LAYER M4 ;
        RECT  73.248 14.016 73.44 14.04 ;
    END
  END rq1[1]
  PIN rq1[2]
    DIRECTION OUTPUT ;
    USE SIGNAL ;
    PORT
      LAYER M4 ;
        RECT  73.248 13.872 73.44 13.896 ;
    END
  END rq1[2]
  PIN rq1[3]
    DIRECTION OUTPUT ;
    USE SIGNAL ;
    PORT
      LAYER M4 ;
        RECT  73.248 13.728 73.44 13.752 ;
    END
  END rq1[3]
  PIN rst_n
    DIRECTION INPUT ;
    USE SIGNAL ;
    PORT
      LAYER M4 ;
        RECT  0 24.288 0.192 24.312 ;
    END
    PORT
      LAYER M4 ;
        RECT  0.156 24.288 0.181 24.312 ;
    END
  END rst_n
  PIN wq0[0]
    DIRECTION OUTPUT ;
    USE SIGNAL ;
    PORT
      LAYER M4 ;
        RECT  73.248 14.88 73.44 14.904 ;
    END
  END wq0[0]
  PIN wq0[1]
    DIRECTION OUTPUT ;
    USE SIGNAL ;
    PORT
      LAYER M4 ;
        RECT  73.248 15.312 73.44 15.336 ;
    END
  END wq0[1]
  PIN wq0[2]
    DIRECTION OUTPUT ;
    USE SIGNAL ;
    PORT
      LAYER M4 ;
        RECT  73.248 17.472 73.44 17.496 ;
    END
  END wq0[2]
  PIN wq0[3]
    DIRECTION OUTPUT ;
    USE SIGNAL ;
    PORT
      LAYER M4 ;
        RECT  73.248 7.248 73.44 7.272 ;
    END
  END wq0[3]
  PIN wq1[0]
    DIRECTION OUTPUT ;
    USE SIGNAL ;
    PORT
      LAYER M4 ;
        RECT  73.248 16.176 73.44 16.2 ;
    END
  END wq1[0]
  PIN wq1[1]
    DIRECTION OUTPUT ;
    USE SIGNAL ;
    PORT
      LAYER M4 ;
        RECT  73.248 16.608 73.44 16.632 ;
    END
  END wq1[1]
  PIN wq1[2]
    DIRECTION OUTPUT ;
    USE SIGNAL ;
    PORT
      LAYER M4 ;
        RECT  73.248 7.104 73.44 7.128 ;
    END
  END wq1[2]
  PIN wq1[3]
    DIRECTION OUTPUT ;
    USE SIGNAL ;
    PORT
      LAYER M4 ;
        RECT  73.248 6.96 73.44 6.984 ;
    END
  END wq1[3]
  PIN wr0[0]
    DIRECTION OUTPUT ;
    USE SIGNAL ;
    PORT
      LAYER M4 ;
        RECT  73.248 15.024 73.44 15.048 ;
    END
  END wr0[0]
  PIN wr0[1]
    DIRECTION OUTPUT ;
    USE SIGNAL ;
    PORT
      LAYER M4 ;
        RECT  73.248 15.168 73.44 15.192 ;
    END
  END wr0[1]
  PIN wr0[2]
    DIRECTION OUTPUT ;
    USE SIGNAL ;
    PORT
      LAYER M4 ;
        RECT  73.248 15.456 73.44 15.48 ;
    END
  END wr0[2]
  PIN wr0[3]
    DIRECTION OUTPUT ;
    USE SIGNAL ;
    PORT
      LAYER M4 ;
        RECT  73.248 15.6 73.44 15.624 ;
    END
  END wr0[3]
  PIN wr0[4]
    DIRECTION OUTPUT ;
    USE SIGNAL ;
    PORT
      LAYER M4 ;
        RECT  73.248 15.744 73.44 15.768 ;
    END
  END wr0[4]
  PIN wr0[5]
    DIRECTION OUTPUT ;
    USE SIGNAL ;
    PORT
      LAYER M4 ;
        RECT  73.248 15.888 73.44 15.912 ;
    END
  END wr0[5]
  PIN wr0[6]
    DIRECTION OUTPUT ;
    USE SIGNAL ;
    PORT
      LAYER M4 ;
        RECT  73.248 16.032 73.44 16.056 ;
    END
  END wr0[6]
  PIN wr1[0]
    DIRECTION OUTPUT ;
    USE SIGNAL ;
    PORT
      LAYER M4 ;
        RECT  73.248 16.32 73.44 16.344 ;
    END
  END wr1[0]
  PIN wr1[1]
    DIRECTION OUTPUT ;
    USE SIGNAL ;
    PORT
      LAYER M4 ;
        RECT  73.248 16.464 73.44 16.488 ;
    END
  END wr1[1]
  PIN wr1[2]
    DIRECTION OUTPUT ;
    USE SIGNAL ;
    PORT
      LAYER M4 ;
        RECT  73.248 16.752 73.44 16.776 ;
    END
  END wr1[2]
  PIN wr1[3]
    DIRECTION OUTPUT ;
    USE SIGNAL ;
    PORT
      LAYER M4 ;
        RECT  73.248 16.896 73.44 16.92 ;
    END
  END wr1[3]
  PIN wr1[4]
    DIRECTION OUTPUT ;
    USE SIGNAL ;
    PORT
      LAYER M4 ;
        RECT  73.248 17.04 73.44 17.064 ;
    END
  END wr1[4]
  PIN wr1[5]
    DIRECTION OUTPUT ;
    USE SIGNAL ;
    PORT
      LAYER M4 ;
        RECT  73.248 17.184 73.44 17.208 ;
    END
  END wr1[5]
  PIN wr1[6]
    DIRECTION OUTPUT ;
    USE SIGNAL ;
    PORT
      LAYER M4 ;
        RECT  73.248 17.328 73.44 17.352 ;
    END
  END wr1[6]
  PIN VDD
    DIRECTION INOUT ;
    USE POWER ;
    PORT
      LAYER M5 ;
        RECT  67.392 2.151 67.512 32.409 ;
        RECT  61.992 2.151 62.112 32.409 ;
        RECT  56.592 2.151 56.712 32.409 ;
        RECT  51.192 2.151 51.312 32.409 ;
        RECT  45.792 2.151 45.912 32.409 ;
        RECT  40.392 2.151 40.512 32.409 ;
        RECT  34.992 2.151 35.112 32.409 ;
        RECT  29.592 2.151 29.712 32.409 ;
        RECT  24.192 2.151 24.312 32.409 ;
        RECT  18.792 2.151 18.912 32.409 ;
        RECT  13.392 2.151 13.512 32.409 ;
        RECT  7.992 2.151 8.112 32.409 ;
        RECT  2.592 2.151 2.712 32.409 ;
    END
  END VDD
  PIN VSS
    DIRECTION INOUT ;
    USE GROUND ;
    PORT
      LAYER M5 ;
        RECT  67.2 2.137 67.32 32.423 ;
        RECT  61.8 2.137 61.92 32.423 ;
        RECT  56.4 2.137 56.52 32.423 ;
        RECT  51 2.137 51.12 32.423 ;
        RECT  45.6 2.137 45.72 32.423 ;
        RECT  40.2 2.137 40.32 32.423 ;
        RECT  34.8 2.137 34.92 32.423 ;
        RECT  29.4 2.137 29.52 32.423 ;
        RECT  24 2.137 24.12 32.423 ;
        RECT  18.6 2.137 18.72 32.423 ;
        RECT  13.2 2.137 13.32 32.423 ;
        RECT  7.8 2.137 7.92 32.423 ;
        RECT  2.4 2.137 2.52 32.423 ;
    END
  END VSS
  # OT_OBS_CLOSED layer=M5 d_um=1.536 added=122
  OBS
    LAYER RVTN ;
     RECT  2.16 2.16 71.28 2.295 ;
     RECT  2.16 2.565 71.28 2.835 ;
     RECT  2.16 3.105 71.28 3.375 ;
     RECT  2.16 3.645 71.28 3.915 ;
     RECT  2.16 4.185 71.28 4.455 ;
     RECT  2.16 4.725 71.28 4.995 ;
     RECT  2.16 5.265 71.28 5.535 ;
     RECT  2.16 5.805 71.28 6.075 ;
     RECT  2.16 6.345 71.28 6.615 ;
     RECT  2.16 6.885 71.28 7.155 ;
     RECT  2.16 7.425 71.28 7.695 ;
     RECT  2.16 7.965 71.28 8.235 ;
     RECT  2.16 8.505 71.28 8.775 ;
     RECT  2.16 9.045 71.28 9.315 ;
     RECT  2.16 9.585 71.28 9.855 ;
     RECT  2.16 10.125 71.28 10.395 ;
     RECT  2.16 10.665 71.28 10.935 ;
     RECT  2.16 11.205 71.28 11.475 ;
     RECT  2.16 11.745 71.28 12.015 ;
     RECT  2.16 12.285 71.28 12.555 ;
     RECT  2.16 12.825 71.28 13.095 ;
     RECT  2.16 13.365 71.28 13.635 ;
     RECT  2.16 13.905 71.28 14.175 ;
     RECT  2.16 14.445 71.28 14.715 ;
     RECT  2.16 14.985 71.28 15.255 ;
     RECT  2.16 15.525 71.28 15.795 ;
     RECT  2.16 16.065 71.28 16.335 ;
     RECT  2.16 16.605 71.28 16.875 ;
     RECT  2.16 17.145 71.28 17.415 ;
     RECT  2.16 17.685 71.28 17.955 ;
     RECT  2.16 18.225 71.28 18.495 ;
     RECT  2.16 18.765 71.28 19.035 ;
     RECT  2.16 19.305 71.28 19.575 ;
     RECT  2.16 19.845 71.28 20.115 ;
     RECT  2.16 20.385 71.28 20.655 ;
     RECT  2.16 20.925 71.28 21.195 ;
     RECT  2.16 21.465 71.28 21.735 ;
     RECT  2.16 22.005 71.28 22.275 ;
     RECT  2.16 22.545 71.28 22.815 ;
     RECT  2.16 23.085 71.28 23.355 ;
     RECT  2.16 23.625 71.28 23.895 ;
     RECT  2.16 24.165 71.28 24.435 ;
     RECT  2.16 24.705 71.28 24.975 ;
     RECT  2.16 25.245 71.28 25.515 ;
     RECT  2.16 25.785 71.28 26.055 ;
     RECT  2.16 26.325 71.28 26.595 ;
     RECT  2.16 26.865 71.28 27.135 ;
     RECT  2.16 27.405 71.28 27.675 ;
     RECT  2.16 27.945 71.28 28.215 ;
     RECT  2.16 28.485 71.28 28.755 ;
     RECT  2.16 29.025 71.28 29.295 ;
     RECT  2.16 29.565 71.28 29.835 ;
     RECT  2.16 30.105 71.28 30.375 ;
     RECT  2.16 30.645 71.28 30.915 ;
     RECT  2.16 31.185 71.28 31.455 ;
     RECT  2.16 31.725 71.28 31.995 ;
     RECT  2.16 32.265 71.28 32.4 ;
    LAYER RVTP ;
     RECT  2.16 2.295 71.28 2.565 ;
     RECT  2.16 2.835 71.28 3.105 ;
     RECT  2.16 3.375 71.28 3.645 ;
     RECT  2.16 3.915 71.28 4.185 ;
     RECT  2.16 4.455 71.28 4.725 ;
     RECT  2.16 4.995 71.28 5.265 ;
     RECT  2.16 5.535 71.28 5.805 ;
     RECT  2.16 6.075 71.28 6.345 ;
     RECT  2.16 6.615 71.28 6.885 ;
     RECT  2.16 7.155 71.28 7.425 ;
     RECT  2.16 7.695 71.28 7.965 ;
     RECT  2.16 8.235 71.28 8.505 ;
     RECT  2.16 8.775 71.28 9.045 ;
     RECT  2.16 9.315 71.28 9.585 ;
     RECT  2.16 9.855 71.28 10.125 ;
     RECT  2.16 10.395 71.28 10.665 ;
     RECT  2.16 10.935 71.28 11.205 ;
     RECT  2.16 11.475 71.28 11.745 ;
     RECT  2.16 12.015 71.28 12.285 ;
     RECT  2.16 12.555 71.28 12.825 ;
     RECT  2.16 13.095 71.28 13.365 ;
     RECT  2.16 13.635 71.28 13.905 ;
     RECT  2.16 14.175 71.28 14.445 ;
     RECT  2.16 14.715 71.28 14.985 ;
     RECT  2.16 15.255 71.28 15.525 ;
     RECT  2.16 15.795 71.28 16.065 ;
     RECT  2.16 16.335 71.28 16.605 ;
     RECT  2.16 16.875 71.28 17.145 ;
     RECT  2.16 17.415 71.28 17.685 ;
     RECT  2.16 17.955 71.28 18.225 ;
     RECT  2.16 18.495 71.28 18.765 ;
     RECT  2.16 19.035 71.28 19.305 ;
     RECT  2.16 19.575 71.28 19.845 ;
     RECT  2.16 20.115 71.28 20.385 ;
     RECT  2.16 20.655 71.28 20.925 ;
     RECT  2.16 21.195 71.28 21.465 ;
     RECT  2.16 21.735 71.28 22.005 ;
     RECT  2.16 22.275 71.28 22.545 ;
     RECT  2.16 22.815 71.28 23.085 ;
     RECT  2.16 23.355 71.28 23.625 ;
     RECT  2.16 23.895 71.28 24.165 ;
     RECT  2.16 24.435 71.28 24.705 ;
     RECT  2.16 24.975 71.28 25.245 ;
     RECT  2.16 25.515 71.28 25.785 ;
     RECT  2.16 26.055 71.28 26.325 ;
     RECT  2.16 26.595 71.28 26.865 ;
     RECT  2.16 27.135 71.28 27.405 ;
     RECT  2.16 27.675 71.28 27.945 ;
     RECT  2.16 28.215 71.28 28.485 ;
     RECT  2.16 28.755 71.28 29.025 ;
     RECT  2.16 29.295 71.28 29.565 ;
     RECT  2.16 29.835 71.28 30.105 ;
     RECT  2.16 30.375 71.28 30.645 ;
     RECT  2.16 30.915 71.28 31.185 ;
     RECT  2.16 31.455 71.28 31.725 ;
     RECT  2.16 31.995 71.28 32.265 ;
    LAYER M1 ;
     RECT  2.16 2.151 71.28 32.409 ;
    LAYER M2 ;
     RECT  0.211 14.76 0.247 14.778 ;
     RECT  0.247 14.49 2.16 14.778 ;
     RECT  0.211 17.622 2.16 17.64 ;
     RECT  2.16 2.151 3.847 32.409 ;
     RECT  3.847 2.151 4.315 32.454 ;
     RECT  4.315 2.151 5.143 32.868 ;
     RECT  5.143 2.151 6.331 32.949 ;
     RECT  6.331 2.151 7.951 33.489 ;
     RECT  7.951 1.692 12.127 33.489 ;
     RECT  12.127 1.692 12.163 33.534 ;
     RECT  12.163 1.692 12.559 33.606 ;
     RECT  12.559 1.692 12.595 33.759 ;
     RECT  12.595 1.692 12.695 34.416 ;
     RECT  12.695 1.692 12.839 34.344 ;
     RECT  12.839 1.692 13.027 33.489 ;
     RECT  13.027 1.611 13.127 33.489 ;
     RECT  12.839 34.281 13.199 34.344 ;
     RECT  13.135 0.144 13.415 0.162 ;
     RECT  15.223 0.144 16.511 0.162 ;
     RECT  13.199 34.326 16.519 34.344 ;
     RECT  13.127 1.611 17.491 33.444 ;
     RECT  16.519 34.281 17.491 34.344 ;
     RECT  17.491 1.224 17.563 33.444 ;
     RECT  17.491 34.281 17.627 34.488 ;
     RECT  17.563 1.152 17.699 33.444 ;
     RECT  17.627 34.281 18.355 34.344 ;
     RECT  18.355 34.281 18.491 34.488 ;
     RECT  18.491 34.281 18.599 34.452 ;
     RECT  17.419 0.144 18.743 0.162 ;
     RECT  17.699 1.692 18.859 33.444 ;
     RECT  18.859 1.692 18.931 33.489 ;
     RECT  18.931 1.152 19.031 33.489 ;
     RECT  19.031 1.692 19.687 33.489 ;
     RECT  18.599 34.398 19.687 34.452 ;
     RECT  19.687 1.692 21.191 34.452 ;
     RECT  21.191 1.692 21.263 34.416 ;
     RECT  21.991 0.144 22.703 0.162 ;
     RECT  23.971 0.144 24.187 0.162 ;
     RECT  24.187 0.144 24.323 0.324 ;
     RECT  24.323 0.144 24.467 0.234 ;
     RECT  21.263 1.692 24.835 34.38 ;
     RECT  24.835 1.692 24.943 34.488 ;
     RECT  24.943 1.152 24.971 34.488 ;
     RECT  24.971 1.152 25.043 34.344 ;
     RECT  24.467 0.144 25.655 0.162 ;
     RECT  25.043 1.611 26.995 34.344 ;
     RECT  26.995 1.152 27.131 34.344 ;
     RECT  26.995 0.144 27.463 0.162 ;
     RECT  27.463 0.144 27.815 0.234 ;
     RECT  27.815 0.144 29.263 0.162 ;
     RECT  29.263 0.144 29.543 0.234 ;
     RECT  27.131 1.611 30.415 34.344 ;
     RECT  29.543 0.144 30.623 0.162 ;
     RECT  30.415 1.116 30.695 34.344 ;
     RECT  30.695 1.692 30.847 34.344 ;
     RECT  30.847 1.692 33.079 34.452 ;
     RECT  33.079 1.611 33.115 34.452 ;
     RECT  33.115 1.152 33.791 34.452 ;
     RECT  33.791 1.611 34.771 34.452 ;
     RECT  34.771 1.611 34.907 34.524 ;
     RECT  34.907 1.611 34.915 34.452 ;
     RECT  34.483 0.144 35.059 0.162 ;
     RECT  34.915 1.152 35.159 34.452 ;
     RECT  35.059 0.144 35.231 0.324 ;
     RECT  35.231 0.144 35.303 0.162 ;
     RECT  35.159 1.611 37.147 34.452 ;
     RECT  37.147 1.224 37.291 34.452 ;
     RECT  37.291 1.152 37.391 34.452 ;
     RECT  36.499 0.144 38.767 0.162 ;
     RECT  37.391 1.692 38.867 34.452 ;
     RECT  38.767 0.144 38.903 0.234 ;
     RECT  38.867 1.692 38.975 34.416 ;
     RECT  38.975 1.692 39.955 34.38 ;
     RECT  39.955 1.152 40.955 34.38 ;
     RECT  40.891 0.144 40.991 0.162 ;
     RECT  40.955 1.692 41.683 34.38 ;
     RECT  41.683 1.692 41.819 34.488 ;
     RECT  41.819 1.692 41.971 34.38 ;
     RECT  41.827 0.144 42.035 0.162 ;
     RECT  41.971 1.152 42.539 34.38 ;
     RECT  42.539 1.692 42.763 34.38 ;
     RECT  42.763 1.692 44.779 34.416 ;
     RECT  44.779 1.224 44.851 34.416 ;
     RECT  44.851 1.152 44.951 34.416 ;
     RECT  44.951 1.611 45.103 34.416 ;
     RECT  45.103 1.611 45.131 34.452 ;
     RECT  45.131 1.611 45.311 33.489 ;
     RECT  43.123 0.144 45.599 0.162 ;
     RECT  45.311 1.611 46.355 33.444 ;
     RECT  46.291 0.216 46.463 0.234 ;
     RECT  46.579 0.144 46.715 0.162 ;
     RECT  46.355 1.692 47.695 33.444 ;
     RECT  47.695 1.152 48.047 33.444 ;
     RECT  48.047 1.26 48.119 33.444 ;
     RECT  47.875 0.18 48.163 0.198 ;
     RECT  48.163 0.144 48.451 0.198 ;
     RECT  48.451 0.144 48.551 0.234 ;
     RECT  48.119 1.692 48.883 33.444 ;
     RECT  48.883 1.152 48.983 33.444 ;
     RECT  48.983 1.692 49.019 33.444 ;
     RECT  49.019 1.692 50.251 33.372 ;
     RECT  45.131 34.236 50.719 34.452 ;
     RECT  50.251 1.692 50.755 33.408 ;
     RECT  50.719 34.2 50.755 34.524 ;
     RECT  50.755 1.692 50.855 34.524 ;
     RECT  50.855 34.2 50.891 34.524 ;
     RECT  50.855 1.692 50.971 33.408 ;
     RECT  50.971 1.224 51.151 33.408 ;
     RECT  51.151 1.152 51.251 33.408 ;
     RECT  48.551 0.144 51.431 0.162 ;
     RECT  51.251 1.692 52.807 33.408 ;
     RECT  50.891 34.236 52.807 34.524 ;
     RECT  52.807 1.692 54.707 34.524 ;
     RECT  54.707 34.236 55.139 34.524 ;
     RECT  55.139 34.398 55.427 34.524 ;
     RECT  54.707 1.692 55.723 33.408 ;
     RECT  55.723 1.692 56.543 33.642 ;
     RECT  56.543 1.692 58.171 33.408 ;
     RECT  58.171 1.692 58.703 33.642 ;
     RECT  58.703 1.692 59.135 33.57 ;
     RECT  59.431 34.398 59.603 34.416 ;
     RECT  59.135 1.692 63.275 33.408 ;
     RECT  64.003 34.398 64.103 34.488 ;
     RECT  63.275 1.692 64.139 33.066 ;
     RECT  64.103 34.47 64.139 34.488 ;
     RECT  64.139 1.692 64.211 32.49 ;
     RECT  64.211 1.692 65.803 32.409 ;
     RECT  65.803 1.692 66.703 32.454 ;
     RECT  66.703 1.692 67.063 32.49 ;
     RECT  67.063 1.692 67.135 32.562 ;
     RECT  67.135 1.692 67.531 32.634 ;
     RECT  68.215 34.398 68.351 34.488 ;
     RECT  68.351 34.47 68.387 34.488 ;
     RECT  67.531 1.692 68.495 33.066 ;
     RECT  68.495 2.151 68.711 33.066 ;
     RECT  68.711 2.151 69.619 32.409 ;
     RECT  69.619 34.398 69.655 34.416 ;
     RECT  69.655 34.398 69.755 34.488 ;
     RECT  69.619 2.151 69.791 33.066 ;
     RECT  69.791 2.151 71.28 32.409 ;
     RECT  71.28 6.822 71.807 26.784 ;
     RECT  71.28 4.806 71.843 4.824 ;
     RECT  71.807 6.822 71.843 25.704 ;
     RECT  71.807 26.676 71.843 26.784 ;
     RECT  71.843 6.822 71.879 23.922 ;
     RECT  71.843 26.676 71.879 26.694 ;
     RECT  71.879 12.456 72.023 23.922 ;
     RECT  72.023 18.468 72.347 23.922 ;
     RECT  71.843 24.876 72.347 25.704 ;
     RECT  71.879 6.822 72.383 11.394 ;
     RECT  72.023 12.456 72.383 17.64 ;
     RECT  72.347 18.468 72.383 19.674 ;
     RECT  72.347 20.826 72.383 21.924 ;
     RECT  72.347 24.876 72.383 24.894 ;
     RECT  72.347 25.686 72.383 25.704 ;
     RECT  72.383 6.822 72.419 8.532 ;
     RECT  72.383 9.594 72.419 9.612 ;
     RECT  72.383 10.638 72.419 11.394 ;
     RECT  72.383 13.644 72.419 14.544 ;
     RECT  72.383 15.804 72.419 15.822 ;
     RECT  72.383 19.386 72.419 19.674 ;
     RECT  72.383 21.636 72.419 21.654 ;
     RECT  72.347 22.788 72.419 23.922 ;
     RECT  72.419 7.938 72.455 8.532 ;
     RECT  72.419 10.908 72.455 10.926 ;
     RECT  72.419 13.986 72.455 14.004 ;
     RECT  72.419 22.824 72.455 23.454 ;
     RECT  72.455 22.824 72.491 22.842 ;
     RECT  72.455 7.938 73.247 7.956 ;
    LAYER M3 ;
     RECT  12.96 0.108 31.266 0.571 ;
     RECT  33.48 0.108 51.786 1.147 ;
     RECT  12.564 0.571 31.266 1.387 ;
     RECT  33.12 1.147 51.786 1.387 ;
     RECT  54.756 1.051 54.774 1.435 ;
     RECT  32.508 1.387 51.786 1.723 ;
     RECT  9.504 1.627 9.522 1.771 ;
     RECT  12.564 1.387 31.338 1.771 ;
     RECT  32.508 1.723 52.326 1.771 ;
     RECT  68.472 1.687 68.49 1.771 ;
     RECT  12.564 1.771 31.41 1.963 ;
     RECT  32.508 1.771 52.722 1.963 ;
     RECT  7.956 1.687 7.974 2.059 ;
     RECT  59.4 1.531 59.418 2.059 ;
     RECT  12.564 1.963 52.722 2.101 ;
     RECT  7.956 2.059 8.01 2.143 ;
     RECT  55.8 1.675 55.818 2.143 ;
     RECT  12.564 2.101 52.758 2.191 ;
     RECT  59.4 2.059 59.598 2.191 ;
     RECT  11.628 2.059 11.646 2.219 ;
     RECT  10.836 2.191 10.854 2.237 ;
     RECT  54.252 1.435 54.774 2.251 ;
     RECT  12.564 2.191 53.01 2.263 ;
     RECT  59.4 2.191 59.778 2.285 ;
     RECT  67.215 2.143 67.305 2.347 ;
     RECT  68.472 1.771 68.814 2.347 ;
     RECT  9.504 1.771 9.738 2.371 ;
     RECT  2.415 2.143 2.505 2.413 ;
     RECT  7.815 2.143 8.01 2.413 ;
     RECT  55.8 2.143 56.505 2.413 ;
     RECT  61.815 2.143 61.905 2.413 ;
     RECT  11.988 2.263 53.118 2.569 ;
     RECT  67.215 2.347 68.814 2.731 ;
     RECT  57.672 1.483 57.69 2.779 ;
     RECT  58.464 1.003 58.482 2.779 ;
     RECT  66.708 2.731 68.814 2.827 ;
     RECT  9.144 2.371 9.738 2.831 ;
     RECT  54.216 2.251 54.774 2.839 ;
     RECT  66.708 2.827 68.922 2.861 ;
     RECT  54.216 2.839 54.846 2.923 ;
     RECT  57.672 2.779 58.482 3.019 ;
     RECT  59.4 2.285 59.418 3.019 ;
     RECT  11.232 2.875 11.25 3.073 ;
     RECT  11.988 2.569 53.406 3.073 ;
     RECT  61.815 2.413 62.097 3.145 ;
     RECT  54.216 2.923 54.882 3.445 ;
     RECT  9.504 2.831 9.738 3.451 ;
     RECT  11.232 3.073 53.406 3.649 ;
     RECT  7.815 2.413 8.097 3.691 ;
     RECT  10.908 3.649 53.406 3.691 ;
     RECT  54.144 3.445 54.882 3.691 ;
     RECT  10.908 3.691 54.882 3.883 ;
     RECT  64.584 3.181 64.602 3.883 ;
     RECT  7.815 3.691 8.442 4.075 ;
     RECT  9.504 3.451 9.846 4.075 ;
     RECT  7.815 4.075 9.846 4.205 ;
     RECT  10.728 3.883 54.882 4.315 ;
     RECT  55.8 2.413 56.697 4.315 ;
     RECT  57.672 3.019 59.418 4.411 ;
     RECT  57.672 4.411 59.706 4.531 ;
     RECT  67.215 2.861 68.922 4.531 ;
     RECT  70.02 3.343 70.038 4.531 ;
     RECT  6.912 2.803 6.93 4.699 ;
     RECT  7.815 4.205 8.442 4.699 ;
     RECT  9.504 4.205 9.846 4.729 ;
     RECT  10.728 4.315 56.697 4.729 ;
     RECT  67.215 4.531 70.038 4.765 ;
     RECT  67.215 4.765 70.686 4.891 ;
     RECT  61.815 3.145 62.514 4.999 ;
     RECT  63.36 3.835 63.378 4.999 ;
     RECT  66.708 4.891 70.686 4.999 ;
     RECT  66.132 4.999 70.686 5.021 ;
     RECT  9.504 4.729 56.697 5.035 ;
     RECT  4.536 4.459 4.554 5.071 ;
     RECT  67.215 5.021 70.686 5.071 ;
     RECT  67.215 5.071 70.938 5.341 ;
     RECT  6.912 4.699 8.442 5.539 ;
     RECT  9.288 5.035 56.697 5.539 ;
     RECT  6.084 4.531 6.102 5.611 ;
     RECT  67.215 5.341 71.01 5.611 ;
     RECT  71.82 4.801 71.838 5.611 ;
     RECT  6.912 5.539 56.697 5.639 ;
     RECT  60.732 5.611 60.75 5.773 ;
     RECT  60.696 5.773 60.75 5.881 ;
     RECT  57.672 4.531 59.742 6.043 ;
     RECT  57.672 6.043 59.814 6.079 ;
     RECT  60.624 5.881 60.75 6.079 ;
     RECT  57.672 6.079 60.75 6.091 ;
     RECT  61.815 4.999 63.378 6.115 ;
     RECT  64.584 3.883 64.818 6.115 ;
     RECT  66.132 5.021 66.15 6.115 ;
     RECT  67.215 5.611 71.838 6.115 ;
     RECT  57.456 6.091 60.75 6.151 ;
     RECT  61.632 6.115 63.378 6.151 ;
     RECT  64.296 6.115 64.818 6.151 ;
     RECT  57.456 6.151 65.214 6.241 ;
     RECT  66.132 6.115 71.838 6.241 ;
     RECT  9.288 5.639 56.697 6.583 ;
     RECT  57.456 6.241 71.838 6.583 ;
     RECT  9.288 6.583 71.838 6.691 ;
     RECT  9.216 6.691 71.838 6.817 ;
     RECT  6.912 5.639 8.442 6.853 ;
     RECT  9.216 6.817 72.414 6.853 ;
     RECT  6.912 6.853 72.414 6.907 ;
     RECT  6.912 6.907 72.486 7.277 ;
     RECT  6.912 7.277 72.414 7.963 ;
     RECT  73.224 7.933 73.242 7.997 ;
     RECT  6.84 7.963 72.414 8.509 ;
     RECT  5.832 5.611 6.102 8.539 ;
     RECT  6.84 8.509 72.45 8.573 ;
     RECT  72.36 8.573 72.45 8.717 ;
     RECT  5.292 8.539 6.102 8.743 ;
     RECT  6.84 8.573 71.298 8.743 ;
     RECT  72.36 8.717 72.414 8.861 ;
     RECT  4.248 5.071 4.554 8.977 ;
     RECT  5.292 8.743 71.298 8.977 ;
     RECT  4.248 8.977 71.298 9.391 ;
     RECT  72.36 8.861 72.378 9.391 ;
     RECT  4.248 9.391 72.378 9.509 ;
     RECT  4.248 9.509 65.466 9.545 ;
     RECT  66.204 9.509 71.082 9.545 ;
     RECT  71.82 9.509 72.378 9.589 ;
     RECT  64.368 9.545 65.466 9.689 ;
     RECT  71.82 9.589 72.414 9.725 ;
     RECT  71.82 9.725 72.378 10.013 ;
     RECT  72.36 10.013 72.378 10.157 ;
     RECT  66.312 9.545 71.082 10.363 ;
     RECT  4.248 9.545 63.522 10.435 ;
     RECT  64.44 9.689 65.466 10.435 ;
     RECT  4.248 10.435 65.466 10.561 ;
     RECT  4.248 10.561 65.538 10.597 ;
     RECT  66.312 10.363 71.262 10.597 ;
     RECT  72.396 10.633 72.414 10.699 ;
     RECT  72.396 10.699 72.45 10.931 ;
     RECT  72.396 10.931 72.414 11.101 ;
     RECT  4.248 10.597 71.262 11.281 ;
     RECT  72.36 11.101 72.414 11.281 ;
     RECT  4.248 11.281 72.414 11.551 ;
     RECT  4.176 11.551 72.414 11.597 ;
     RECT  4.176 11.597 72.378 11.677 ;
     RECT  3.888 11.677 72.378 11.749 ;
     RECT  3.816 11.749 72.378 11.849 ;
     RECT  3.852 11.849 72.378 12.173 ;
     RECT  3.852 12.173 71.262 12.631 ;
     RECT  3.816 12.631 71.262 13.063 ;
     RECT  72.036 12.173 72.378 13.063 ;
     RECT  3.816 13.063 72.378 13.639 ;
     RECT  3.816 13.639 72.414 13.981 ;
     RECT  3.816 13.981 72.45 14.107 ;
     RECT  3.78 14.107 72.45 14.171 ;
     RECT  2.415 2.413 2.697 14.521 ;
     RECT  64.404 14.171 72.45 14.621 ;
     RECT  0.252 14.485 0.27 14.683 ;
     RECT  64.404 14.621 72.414 14.711 ;
     RECT  0.252 14.683 0.306 14.755 ;
     RECT  2.376 14.521 2.697 14.755 ;
     RECT  71.82 14.711 72.414 14.765 ;
     RECT  0.216 14.755 0.306 14.875 ;
     RECT  3.78 14.171 63.558 14.917 ;
     RECT  64.404 14.711 70.938 14.917 ;
     RECT  0.216 14.875 0.342 15.005 ;
     RECT  2.376 14.755 2.97 15.019 ;
     RECT  2.304 15.019 2.97 15.025 ;
     RECT  3.78 14.917 70.938 15.025 ;
     RECT  0.216 15.005 0.306 15.197 ;
     RECT  2.304 15.025 70.938 15.521 ;
     RECT  66.312 15.521 70.938 15.595 ;
     RECT  71.82 14.765 72.378 15.595 ;
     RECT  0.252 15.197 0.306 15.629 ;
     RECT  66.312 15.595 72.378 15.799 ;
     RECT  66.312 15.799 72.414 16.061 ;
     RECT  2.304 15.521 65.43 16.171 ;
     RECT  66.312 16.061 72.378 16.363 ;
     RECT  2.268 16.171 65.43 16.375 ;
     RECT  66.276 16.363 72.378 16.375 ;
     RECT  2.268 16.375 72.378 16.439 ;
     RECT  2.268 16.439 70.83 16.565 ;
     RECT  66.24 16.565 70.83 16.601 ;
     RECT  0.252 15.629 0.27 16.877 ;
     RECT  71.82 16.439 72.378 16.925 ;
     RECT  2.415 16.565 65.43 17.311 ;
     RECT  2.304 17.311 65.43 17.383 ;
     RECT  66.24 16.601 70.722 17.383 ;
     RECT  2.304 17.383 70.722 17.455 ;
     RECT  71.856 16.925 72.378 17.645 ;
     RECT  71.856 17.645 72.018 17.653 ;
     RECT  0.216 17.617 0.234 17.789 ;
     RECT  2.304 17.455 70.938 17.987 ;
     RECT  2.304 17.987 70.866 18.427 ;
     RECT  71.82 17.653 72.018 18.463 ;
     RECT  2.268 18.427 70.866 18.509 ;
     RECT  2.304 18.509 70.866 18.769 ;
     RECT  71.82 18.463 72.378 18.769 ;
     RECT  2.304 18.769 72.378 18.959 ;
     RECT  72.036 18.959 72.378 19.337 ;
     RECT  72.324 19.337 72.378 19.339 ;
     RECT  72.324 19.339 72.414 19.679 ;
     RECT  2.304 18.959 71.262 19.771 ;
     RECT  0.252 18.331 0.27 19.805 ;
     RECT  2.304 19.771 71.298 19.841 ;
     RECT  2.304 19.841 71.262 19.949 ;
     RECT  72.324 19.679 72.378 20.344 ;
     RECT  2.304 19.949 71.154 20.669 ;
     RECT  72.288 20.344 72.378 20.779 ;
     RECT  72.288 20.779 72.45 20.923 ;
     RECT  0.252 20.875 0.27 21.101 ;
     RECT  2.304 20.669 70.974 21.101 ;
     RECT  72 20.923 72.45 21.211 ;
     RECT  65.88 21.101 70.974 21.499 ;
     RECT  71.856 21.211 72.45 21.499 ;
     RECT  65.88 21.499 72.45 21.569 ;
     RECT  2.304 21.101 65.142 21.803 ;
     RECT  2.34 21.803 65.142 22.075 ;
     RECT  65.88 21.569 70.938 22.075 ;
     RECT  2.34 22.075 70.938 22.235 ;
     RECT  71.856 21.569 72.45 22.621 ;
     RECT  2.415 22.235 70.938 22.739 ;
     RECT  64.476 22.739 70.938 22.775 ;
     RECT  64.548 22.775 70.938 22.781 ;
     RECT  64.584 22.781 70.938 22.783 ;
     RECT  71.82 22.621 72.45 22.783 ;
     RECT  64.584 22.783 72.45 22.795 ;
     RECT  64.584 22.795 72.486 22.847 ;
     RECT  64.584 22.847 72.45 23.123 ;
     RECT  64.584 23.123 71.298 23.261 ;
     RECT  2.415 22.739 63.522 23.395 ;
     RECT  72.36 23.123 72.45 23.459 ;
     RECT  2.34 23.395 63.522 23.963 ;
     RECT  72.36 23.459 72.414 23.981 ;
     RECT  64.584 23.261 71.262 24.169 ;
     RECT  72.36 23.981 72.378 24.169 ;
     RECT  2.34 23.963 3.006 24.283 ;
     RECT  2.304 24.283 3.006 24.359 ;
     RECT  2.304 24.359 2.826 24.395 ;
     RECT  3.78 23.963 63.522 24.475 ;
     RECT  2.304 24.395 2.697 24.935 ;
     RECT  64.584 24.169 72.378 25.079 ;
     RECT  71.784 25.079 72.378 25.709 ;
     RECT  3.78 24.475 63.702 25.753 ;
     RECT  3.78 25.753 63.846 25.951 ;
     RECT  64.584 25.079 71.01 25.951 ;
     RECT  3.78 25.951 71.01 26.671 ;
     RECT  71.784 25.709 71.874 26.671 ;
     RECT  3.78 26.671 71.874 26.699 ;
     RECT  3.78 26.699 71.838 26.789 ;
     RECT  3.78 26.789 71.226 26.969 ;
     RECT  3.78 26.969 71.01 27.869 ;
     RECT  3.78 27.869 70.938 28.175 ;
     RECT  3.78 28.175 70.29 28.283 ;
     RECT  3.78 28.283 70.074 29.101 ;
     RECT  3.78 29.101 70.254 29.219 ;
     RECT  3.78 29.219 70.182 29.903 ;
     RECT  3.78 29.903 70.146 30.137 ;
     RECT  3.78 30.137 70.002 30.569 ;
     RECT  3.78 30.569 64.854 30.749 ;
     RECT  65.592 30.569 70.002 30.839 ;
     RECT  5.292 30.749 64.854 30.947 ;
     RECT  71.064 31.225 71.082 31.261 ;
     RECT  5.652 30.947 64.854 31.459 ;
     RECT  65.592 30.839 69.894 31.459 ;
     RECT  71.028 31.261 71.082 31.495 ;
     RECT  3.78 30.749 4.482 31.559 ;
     RECT  70.848 31.495 71.082 31.657 ;
     RECT  5.652 31.459 69.894 31.721 ;
     RECT  70.848 31.657 71.118 31.801 ;
     RECT  5.652 31.721 64.314 31.829 ;
     RECT  70.812 31.801 71.118 32.035 ;
     RECT  65.628 31.721 69.894 32.071 ;
     RECT  70.704 32.035 71.118 32.071 ;
     RECT  2.415 24.935 2.697 32.147 ;
     RECT  3.816 31.559 4.482 32.189 ;
     RECT  5.688 31.829 64.314 32.189 ;
     RECT  65.628 32.071 71.118 32.189 ;
     RECT  5.688 32.189 64.206 32.225 ;
     RECT  66.708 32.189 71.046 32.225 ;
     RECT  3.816 32.189 4.41 32.237 ;
     RECT  65.628 32.189 65.826 32.261 ;
     RECT  3.816 32.237 4.338 32.297 ;
     RECT  66.708 32.225 71.01 32.297 ;
     RECT  2.415 32.147 2.505 32.417 ;
     RECT  3.852 32.297 4.338 32.459 ;
     RECT  7.776 32.225 64.206 32.459 ;
     RECT  65.808 32.261 65.826 32.459 ;
     RECT  8.028 32.459 64.206 32.495 ;
     RECT  66.708 32.297 69.714 32.495 ;
     RECT  5.688 32.225 7.002 32.525 ;
     RECT  8.244 32.495 64.206 32.813 ;
     RECT  4.32 32.459 4.338 32.873 ;
     RECT  6.336 32.525 7.002 32.909 ;
     RECT  5.148 32.845 5.166 32.954 ;
     RECT  66.96 32.495 69.714 33.043 ;
     RECT  8.388 32.813 64.206 33.341 ;
     RECT  6.336 32.909 6.678 33.389 ;
     RECT  6.336 33.389 6.354 33.494 ;
     RECT  9 33.341 64.206 34.428 ;
     RECT  66.96 33.043 69.786 34.428 ;
     RECT  70.56 32.297 71.01 34.428 ;
     RECT  18.36 34.428 18.558 34.457 ;
     RECT  21.168 34.428 21.186 34.457 ;
     RECT  30.852 34.428 30.87 34.457 ;
     RECT  38.844 34.428 38.862 34.457 ;
     RECT  45.108 34.428 45.126 34.457 ;
     RECT  53.64 34.428 53.658 34.457 ;
     RECT  68.22 34.428 68.382 34.493 ;
     RECT  50.724 34.428 50.742 34.529 ;
     RECT  55.404 34.428 55.422 34.529 ;
    LAYER M4 ;
     RECT  0.181 24.288 0.227 25.32 ;
     RECT  0.156 14.88 0.353 21.24 ;
     RECT  0.353 14.976 2.408 21.24 ;
     RECT  0.227 24.288 2.408 24.984 ;
     RECT  2.408 2.148 2.512 32.412 ;
     RECT  2.512 2.418 2.704 32.142 ;
     RECT  2.704 14.976 2.981 21.24 ;
     RECT  2.981 20.88 3.449 21.24 ;
     RECT  2.704 22.224 3.449 22.824 ;
     RECT  2.981 14.976 4.489 19.848 ;
     RECT  3.449 20.976 4.489 21.24 ;
     RECT  3.449 22.224 4.601 22.728 ;
     RECT  4.489 14.976 4.777 21.24 ;
     RECT  4.601 22.224 4.777 22.44 ;
     RECT  4.777 14.976 5.075 22.44 ;
     RECT  5.065 26.016 5.101 26.04 ;
     RECT  4.957 27.696 5.137 27.72 ;
     RECT  5.029 9.552 5.141 9.576 ;
     RECT  2.704 24.96 5.245 24.984 ;
     RECT  5.101 26.016 5.245 26.424 ;
     RECT  4.993 23.616 5.317 23.64 ;
     RECT  5.245 24.96 5.317 26.424 ;
     RECT  5.137 27.6 5.569 27.72 ;
     RECT  4.525 29.328 5.569 29.352 ;
     RECT  5.317 23.616 5.605 26.424 ;
     RECT  5.569 27.6 5.605 29.352 ;
     RECT  4.849 10.992 5.641 11.016 ;
     RECT  5.641 10.848 5.677 11.64 ;
     RECT  4.381 32.208 5.677 32.232 ;
     RECT  5.677 10.848 5.749 11.736 ;
     RECT  4.849 13.68 5.749 13.704 ;
     RECT  5.605 23.616 5.821 29.352 ;
     RECT  5.749 13.68 5.857 13.896 ;
     RECT  5.075 14.976 5.857 22.248 ;
     RECT  5.281 8.544 5.893 8.568 ;
     RECT  5.821 23.616 5.929 29.4 ;
     RECT  4.525 4.464 6.037 4.488 ;
     RECT  5.857 13.68 6.037 22.248 ;
     RECT  5.929 23.616 6.037 29.832 ;
     RECT  6.037 4.464 6.133 4.968 ;
     RECT  6.037 13.68 6.181 29.832 ;
     RECT  5.893 8.064 6.217 8.568 ;
     RECT  5.677 32.208 6.217 32.52 ;
     RECT  6.181 13.104 6.412 29.832 ;
     RECT  6.412 13.584 6.613 29.832 ;
     RECT  6.217 31.488 6.649 32.52 ;
     RECT  5.749 10.848 6.793 11.976 ;
     RECT  6.217 8.064 6.829 9.528 ;
     RECT  6.793 10.848 7.189 12.408 ;
     RECT  6.133 4.08 7.225 4.968 ;
     RECT  6.613 13.584 7.369 30.168 ;
     RECT  6.649 31.488 7.369 33.384 ;
     RECT  6.829 7.968 7.405 9.528 ;
     RECT  5.749 2.352 7.669 2.376 ;
     RECT  7.669 2.064 7.808 2.376 ;
     RECT  7.225 4.08 7.808 5.592 ;
     RECT  7.405 7.968 7.808 9.576 ;
     RECT  7.189 10.656 7.808 12.408 ;
     RECT  7.369 13.584 7.808 33.384 ;
     RECT  7.808 2.064 8.021 33.384 ;
     RECT  8.021 2.208 8.104 33.384 ;
     RECT  8.104 12 8.725 33.384 ;
     RECT  8.725 12 9.025 33.672 ;
     RECT  8.104 7.968 9.385 11.016 ;
     RECT  9.025 12 9.385 34.296 ;
     RECT  8.104 2.208 9.493 2.376 ;
     RECT  9.385 7.968 9.745 34.296 ;
     RECT  8.104 3.696 9.817 5.592 ;
     RECT  9.745 7.392 9.829 34.296 ;
     RECT  9.829 7.968 10.429 34.296 ;
     RECT  9.817 3.456 11.077 5.592 ;
     RECT  9.493 1.632 11.221 2.376 ;
     RECT  11.077 3.36 11.221 5.592 ;
     RECT  10.429 7.968 11.653 34.392 ;
     RECT  11.221 1.632 11.893 5.592 ;
     RECT  11.653 7.92 11.941 34.392 ;
     RECT  11.941 7.44 12.085 34.392 ;
     RECT  11.893 1.008 12.517 5.592 ;
     RECT  12.085 6.864 12.517 34.392 ;
     RECT  12.517 1.008 12.553 34.392 ;
     RECT  12.553 0.576 13.82 34.392 ;
     RECT  13.82 0.528 14.569 34.392 ;
     RECT  14.569 0.192 16.121 34.392 ;
     RECT  16.121 0.288 17.153 34.392 ;
     RECT  17.153 0.192 17.237 34.392 ;
     RECT  17.237 0.288 18.853 34.392 ;
     RECT  18.853 0.144 19.721 34.392 ;
     RECT  19.721 0.192 20.125 34.392 ;
     RECT  20.125 1.008 21.26 34.392 ;
     RECT  21.26 0.288 23.365 34.392 ;
     RECT  23.365 0.192 24.289 34.392 ;
     RECT  24.289 0.144 24.509 34.392 ;
     RECT  24.509 0.288 25.337 34.392 ;
     RECT  25.337 0.288 25.649 34.296 ;
     RECT  25.649 0.192 25.733 34.296 ;
     RECT  25.733 0.288 26.627 34.296 ;
     RECT  26.627 0.288 26.771 34.2 ;
     RECT  26.771 1.056 26.957 34.2 ;
     RECT  26.957 1.056 27.973 34.152 ;
     RECT  27.973 0.288 28.108 34.152 ;
     RECT  28.108 0.24 28.133 34.152 ;
     RECT  28.133 0.24 28.177 34.296 ;
     RECT  28.177 0.24 28.361 34.392 ;
     RECT  28.361 1.008 30.661 34.392 ;
     RECT  30.661 0.288 30.947 34.392 ;
     RECT  30.947 1.008 33.013 34.392 ;
     RECT  33.013 0.144 36.245 34.392 ;
     RECT  36.245 0.528 36.677 34.392 ;
     RECT  36.677 1.008 37.781 34.392 ;
     RECT  37.781 0.192 38.729 34.392 ;
     RECT  38.729 1.008 40.129 34.392 ;
     RECT  40.129 0.528 40.451 34.392 ;
     RECT  40.451 0.576 41.533 34.392 ;
     RECT  41.533 0.288 42.389 34.392 ;
     RECT  42.389 0.192 42.473 34.392 ;
     RECT  42.473 0.48 44.437 34.392 ;
     RECT  44.437 0.192 45.964 34.392 ;
     RECT  45.964 0.144 46.469 34.392 ;
     RECT  46.469 0.24 46.577 34.392 ;
     RECT  46.577 0.528 46.901 34.392 ;
     RECT  46.901 0.576 47.893 34.392 ;
     RECT  47.893 0.288 48.013 34.392 ;
     RECT  48.013 0.144 48.125 34.392 ;
     RECT  48.125 0.192 48.809 34.392 ;
     RECT  48.809 0.288 49.909 34.392 ;
     RECT  49.909 0.192 50.033 34.392 ;
     RECT  50.033 0.288 50.933 34.392 ;
     RECT  50.933 0.576 51.365 34.392 ;
     RECT  51.365 0.816 51.443 34.392 ;
     RECT  51.443 1.008 55.253 34.392 ;
     RECT  55.253 1.008 55.397 34.344 ;
     RECT  55.397 1.008 55.427 15.192 ;
     RECT  55.427 1.008 56.408 15.144 ;
     RECT  55.397 16.272 56.408 34.344 ;
     RECT  56.408 1.008 56.704 34.344 ;
     RECT  56.704 16.272 57.059 34.344 ;
     RECT  56.704 12 57.269 15 ;
     RECT  56.704 10.896 57.305 11.016 ;
     RECT  57.269 13.392 57.377 15 ;
     RECT  57.269 12 57.449 12.312 ;
     RECT  56.704 1.008 57.485 9.336 ;
     RECT  57.059 16.368 57.491 34.344 ;
     RECT  57.305 10.992 57.521 11.016 ;
     RECT  57.485 6.624 57.769 9.336 ;
     RECT  57.491 21.168 57.917 34.344 ;
     RECT  57.917 26.784 58.067 34.344 ;
     RECT  57.769 6.624 58.211 9.72 ;
     RECT  57.485 1.008 58.493 5.544 ;
     RECT  58.493 1.536 58.529 5.544 ;
     RECT  57.917 21.168 58.529 25.8 ;
     RECT  57.377 13.632 58.597 15 ;
     RECT  58.529 21.168 58.637 25.128 ;
     RECT  57.449 12 58.669 12.024 ;
     RECT  58.597 13.584 58.705 15 ;
     RECT  58.705 13.056 58.789 15 ;
     RECT  58.669 11.76 58.988 12.024 ;
     RECT  58.988 11.76 59.033 12.36 ;
     RECT  58.529 1.536 59.069 4.92 ;
     RECT  59.033 12 59.075 12.36 ;
     RECT  58.637 21.696 59.171 25.128 ;
     RECT  58.789 13.584 59.221 15 ;
     RECT  59.221 13.584 59.245 15.144 ;
     RECT  57.491 16.368 59.245 20.04 ;
     RECT  58.067 27.072 59.267 34.344 ;
     RECT  59.245 13.584 59.357 20.04 ;
     RECT  59.069 1.536 59.429 2.76 ;
     RECT  59.267 34.128 59.465 34.344 ;
     RECT  59.171 21.696 59.605 25.032 ;
     RECT  59.069 3.84 59.717 4.92 ;
     RECT  59.357 18.96 59.749 20.04 ;
     RECT  59.605 21.408 59.753 25.032 ;
     RECT  59.753 21.408 59.789 23.784 ;
     RECT  59.789 21.408 59.893 23.688 ;
     RECT  59.267 27.072 60.073 33.096 ;
     RECT  58.211 6.624 60.077 9.336 ;
     RECT  60.073 26.88 60.109 33.096 ;
     RECT  60.109 26.784 60.229 33.096 ;
     RECT  59.753 24.864 60.373 25.032 ;
     RECT  60.373 24.864 60.46 25.8 ;
     RECT  59.357 13.584 60.473 17.928 ;
     RECT  59.749 18.96 60.473 20.136 ;
     RECT  60.473 13.584 60.505 16.872 ;
     RECT  60.473 19.248 60.509 20.136 ;
     RECT  60.473 17.904 60.563 17.928 ;
     RECT  59.893 21.168 60.581 23.688 ;
     RECT  60.229 26.784 60.689 33.672 ;
     RECT  60.689 28.128 60.761 33.672 ;
     RECT  60.761 28.368 60.805 33.144 ;
     RECT  60.805 32.496 60.899 33.144 ;
     RECT  60.581 21.936 61.405 23.688 ;
     RECT  59.075 12 61.532 12.024 ;
     RECT  60.505 13.056 61.532 16.872 ;
     RECT  60.899 32.496 61.553 32.76 ;
     RECT  60.077 8.496 61.58 9.336 ;
     RECT  61.549 10.704 61.58 10.728 ;
     RECT  60.077 6.624 61.621 6.936 ;
     RECT  59.429 1.776 61.808 2.76 ;
     RECT  59.717 3.84 61.808 3.912 ;
     RECT  59.717 4.896 61.808 4.92 ;
     RECT  61.621 6.624 61.808 7.128 ;
     RECT  61.58 8.496 61.808 10.728 ;
     RECT  61.532 12 61.808 16.872 ;
     RECT  60.509 19.248 61.808 20.04 ;
     RECT  61.405 21.936 61.808 23.832 ;
     RECT  60.46 24.864 61.808 25.512 ;
     RECT  60.689 26.784 61.808 27.144 ;
     RECT  60.805 28.368 61.808 31.512 ;
     RECT  61.808 1.776 61.912 32.412 ;
     RECT  61.912 1.776 62.104 32.142 ;
     RECT  62.104 8.496 62.243 18.024 ;
     RECT  62.243 8.544 62.273 13.656 ;
     RECT  62.104 27.12 62.417 27.432 ;
     RECT  62.104 20.016 62.561 23.64 ;
     RECT  62.273 10.224 62.668 13.656 ;
     RECT  62.417 27.12 62.669 27.336 ;
     RECT  62.561 20.016 62.741 23.016 ;
     RECT  62.104 28.512 62.777 28.824 ;
     RECT  62.669 27.12 62.813 27.144 ;
     RECT  62.104 30.912 62.881 32.142 ;
     RECT  62.881 30.912 63.137 32.184 ;
     RECT  62.668 10.224 63.245 10.92 ;
     RECT  62.273 8.544 63.313 8.808 ;
     RECT  62.243 14.928 63.317 18.024 ;
     RECT  62.104 3.84 63.389 3.912 ;
     RECT  63.137 30.912 63.389 31.992 ;
     RECT  62.104 6.912 63.601 7.416 ;
     RECT  63.313 8.544 63.821 9 ;
     RECT  62.668 12.048 63.821 13.656 ;
     RECT  62.777 28.704 63.929 28.824 ;
     RECT  63.389 30.912 63.961 31.512 ;
     RECT  63.929 28.8 63.965 28.824 ;
     RECT  63.245 10.416 64.141 10.92 ;
     RECT  63.961 30.864 64.253 31.512 ;
     RECT  64.141 10.416 64.429 11.064 ;
     RECT  62.741 20.112 64.465 23.016 ;
     RECT  63.317 14.928 64.505 16.584 ;
     RECT  64.505 14.928 64.537 16.344 ;
     RECT  64.253 30.864 64.577 30.888 ;
     RECT  64.249 27.408 64.613 27.432 ;
     RECT  64.429 10.368 64.721 11.064 ;
     RECT  64.721 10.416 64.793 11.064 ;
     RECT  63.389 3.888 64.829 3.912 ;
     RECT  64.465 20.064 64.892 23.016 ;
     RECT  63.821 8.544 64.973 8.808 ;
     RECT  64.892 20.064 64.979 23.544 ;
     RECT  63.317 18 65.016 18.024 ;
     RECT  65.016 18 65.045 18.6 ;
     RECT  63.821 12.672 65.189 13.176 ;
     RECT  65.189 12.816 65.219 13.128 ;
     RECT  65.045 18.24 65.219 18.6 ;
     RECT  64.897 24.72 65.221 24.744 ;
     RECT  63.601 6.288 65.297 7.416 ;
     RECT  64.793 10.608 65.372 11.064 ;
     RECT  65.221 24.72 65.437 25.128 ;
     RECT  65.293 26.112 65.437 26.136 ;
     RECT  65.372 10.608 65.459 11.688 ;
     RECT  65.459 10.608 65.477 10.872 ;
     RECT  64.979 20.064 65.513 23.016 ;
     RECT  64.537 14.784 65.545 16.344 ;
     RECT  65.437 24.72 65.585 26.136 ;
     RECT  65.585 24.72 65.765 26.088 ;
     RECT  65.297 6.288 65.801 6.312 ;
     RECT  65.765 25.104 65.981 26.088 ;
     RECT  65.513 20.064 66.017 20.712 ;
     RECT  66.121 28.512 66.193 28.536 ;
     RECT  66.265 30.336 66.373 30.36 ;
     RECT  65.545 14.784 66.62 16.44 ;
     RECT  65.219 13.104 66.661 13.128 ;
     RECT  66.62 14.208 66.661 16.44 ;
     RECT  62.104 1.776 66.697 2.76 ;
     RECT  62.104 4.896 66.697 4.92 ;
     RECT  65.473 8.496 66.697 8.52 ;
     RECT  65.513 21.936 66.697 23.016 ;
     RECT  66.017 20.112 67.004 20.712 ;
     RECT  65.219 18.24 67.021 18.264 ;
     RECT  66.193 28.368 67.129 28.536 ;
     RECT  66.373 29.568 67.129 30.36 ;
     RECT  66.697 1.776 67.208 2.856 ;
     RECT  66.697 4.896 67.208 5.016 ;
     RECT  65.297 7.392 67.208 7.416 ;
     RECT  66.697 8.496 67.208 8.808 ;
     RECT  65.477 10.608 67.208 10.632 ;
     RECT  66.661 13.104 67.208 16.44 ;
     RECT  67.021 18.24 67.208 18.792 ;
     RECT  67.004 20.064 67.208 20.712 ;
     RECT  66.697 21.936 67.208 23.112 ;
     RECT  65.981 25.296 67.208 26.088 ;
     RECT  64.969 27.312 67.208 27.336 ;
     RECT  67.129 28.368 67.208 30.36 ;
     RECT  67.208 1.776 67.312 32.412 ;
     RECT  67.312 1.776 67.504 32.142 ;
     RECT  67.504 25.008 67.529 27.144 ;
     RECT  67.504 16.08 67.673 16.392 ;
     RECT  67.529 25.008 67.673 26.568 ;
     RECT  67.504 1.776 67.817 2.856 ;
     RECT  67.504 13.536 67.889 13.56 ;
     RECT  67.504 28.416 67.889 31.128 ;
     RECT  67.889 28.416 67.961 30.936 ;
     RECT  67.673 16.08 67.997 16.104 ;
     RECT  67.504 11.28 68.033 11.928 ;
     RECT  67.504 20.112 68.105 20.328 ;
     RECT  67.504 21.936 68.105 23.112 ;
     RECT  68.105 22.032 68.213 23.112 ;
     RECT  67.961 28.416 68.249 30.6 ;
     RECT  67.504 18.096 68.321 18.12 ;
     RECT  67.504 8.4 68.465 9.24 ;
     RECT  68.465 8.784 68.537 9.24 ;
     RECT  67.673 25.104 68.681 26.568 ;
     RECT  68.249 28.416 68.749 29.16 ;
     RECT  68.681 25.2 68.753 26.568 ;
     RECT  68.753 25.248 68.821 26.568 ;
     RECT  67.817 1.776 68.825 1.8 ;
     RECT  68.821 25.248 68.857 26.616 ;
     RECT  68.249 30.336 68.929 30.6 ;
     RECT  67.817 2.832 68.933 2.856 ;
     RECT  68.857 25.248 69.005 26.712 ;
     RECT  68.677 16.128 69.037 16.152 ;
     RECT  68.033 11.904 69.221 11.928 ;
     RECT  68.749 27.984 69.289 29.16 ;
     RECT  69.005 26.064 69.325 26.712 ;
     RECT  68.537 9.216 69.329 9.24 ;
     RECT  67.504 4.992 69.365 5.016 ;
     RECT  69.289 27.984 69.365 29.256 ;
     RECT  68.105 20.112 69.433 20.136 ;
     RECT  69.365 27.984 69.437 28.2 ;
     RECT  69.325 26.064 69.473 26.952 ;
     RECT  69.365 29.232 69.505 29.256 ;
     RECT  68.213 22.032 69.509 22.872 ;
     RECT  69.037 16.128 69.545 16.44 ;
     RECT  69.509 22.848 69.545 22.872 ;
     RECT  68.929 30.336 69.545 30.984 ;
     RECT  69.473 26.064 69.617 26.088 ;
     RECT  69.437 28.176 69.617 28.2 ;
     RECT  69.545 30.336 69.653 30.648 ;
     RECT  69.433 19.344 69.685 20.136 ;
     RECT  69.653 30.384 69.725 30.648 ;
     RECT  69.685 18.96 69.833 20.136 ;
     RECT  69.469 10.896 69.865 10.92 ;
     RECT  69.505 29.232 69.869 29.304 ;
     RECT  69.869 29.28 69.977 29.304 ;
     RECT  69.833 18.96 70.229 19.896 ;
     RECT  69.613 14.544 70.481 14.568 ;
     RECT  70.477 11.952 70.693 11.976 ;
     RECT  69.545 16.416 70.693 16.44 ;
     RECT  70.229 18.96 70.693 19.368 ;
     RECT  70.693 16.416 70.729 17.352 ;
     RECT  70.729 16.176 70.841 17.352 ;
     RECT  69.865 10.56 70.945 10.92 ;
     RECT  70.873 8.112 70.981 8.136 ;
     RECT  70.981 7.536 71.125 8.136 ;
     RECT  70.945 10.272 71.125 10.92 ;
     RECT  70.693 11.952 71.125 12.744 ;
     RECT  70.729 21.36 71.125 21.384 ;
     RECT  71.125 10.272 71.233 12.744 ;
     RECT  70.841 16.176 71.233 16.2 ;
     RECT  70.693 18.768 71.233 19.368 ;
     RECT  71.125 20.64 71.233 21.384 ;
     RECT  71.233 9.408 71.269 14.472 ;
     RECT  71.233 18.768 71.269 19.656 ;
     RECT  71.233 20.64 71.269 21.528 ;
     RECT  71.233 22.944 71.269 22.968 ;
     RECT  71.233 24.096 71.269 24.12 ;
     RECT  71.125 6.96 71.485 8.136 ;
     RECT  71.269 22.944 71.773 24.264 ;
     RECT  71.485 6.96 71.809 8.28 ;
     RECT  71.269 9.264 71.809 14.472 ;
     RECT  71.233 15.6 71.809 16.2 ;
     RECT  70.841 17.328 71.809 17.352 ;
     RECT  71.269 18.768 71.809 21.528 ;
     RECT  71.773 22.944 71.809 24.552 ;
     RECT  71.809 22.656 71.845 24.552 ;
     RECT  71.809 25.536 71.845 25.56 ;
     RECT  71.809 6.96 72.025 21.528 ;
     RECT  71.845 22.656 72.025 25.56 ;
     RECT  72.025 6.96 72.385 25.56 ;
     RECT  72.385 6.912 72.497 25.56 ;
     RECT  72.497 6.96 73.26 25.56 ;
    LAYER M5 ;
     RECT  33.024 0.133 33.048 0.144 ;
     RECT  13.008 0.144 31.32 0.611 ;
     RECT  13.152 0.611 31.32 0.659 ;
     RECT  33.024 0.144 51.816 1.525 ;
     RECT  32.832 1.525 51.816 1.621 ;
     RECT  11.904 0.997 11.928 1.669 ;
     RECT  13.296 0.659 31.32 1.669 ;
     RECT  32.832 1.621 52.344 1.763 ;
     RECT  48.624 1.763 52.344 1.765 ;
     RECT  48.624 1.765 52.824 1.907 ;
     RECT  11.904 1.669 31.32 2.005 ;
     RECT  32.832 1.763 47.592 2.005 ;
     RECT  53.808 1.093 53.832 2.053 ;
     RECT  7.68 2.053 7.704 2.137 ;
     RECT  2.4 2.137 2.52 2.151 ;
     RECT  7.68 2.137 7.92 2.151 ;
     RECT  56.4 2.137 56.52 2.151 ;
     RECT  61.8 2.137 61.92 2.151 ;
     RECT  67.2 2.137 67.32 2.151 ;
     RECT  60.624 2.005 60.648 2.245 ;
     RECT  11.904 2.005 47.592 2.821 ;
     RECT  48.624 1.907 52.584 2.821 ;
     RECT  11.904 2.821 52.584 2.869 ;
     RECT  53.616 2.053 53.832 2.869 ;
     RECT  11.904 2.869 53.832 3.013 ;
     RECT  54.912 1.381 54.936 3.013 ;
     RECT  58.608 1.573 58.632 3.301 ;
     RECT  11.904 3.013 54.936 3.349 ;
     RECT  11.088 3.349 54.936 3.541 ;
     RECT  5.76 2.341 5.784 4.069 ;
     RECT  58.416 3.301 58.632 4.165 ;
     RECT  59.76 2.245 60.648 4.165 ;
     RECT  10.368 3.541 54.936 5.029 ;
     RECT  56.4 2.151 56.712 5.029 ;
     RECT  10.368 5.029 56.712 6.805 ;
     RECT  10.368 6.805 57.192 7.189 ;
     RECT  58.416 4.165 60.648 7.189 ;
     RECT  9.312 5.365 9.336 7.381 ;
     RECT  10.368 7.189 60.648 7.381 ;
     RECT  61.8 2.151 62.112 8.485 ;
     RECT  61.8 8.485 62.232 8.677 ;
     RECT  9.312 7.381 60.648 8.917 ;
     RECT  7.68 2.151 8.112 9.589 ;
     RECT  9.216 8.917 60.648 9.589 ;
     RECT  7.68 9.589 60.648 9.971 ;
     RECT  7.68 9.971 49.128 10.067 ;
     RECT  61.8 8.677 62.568 10.213 ;
     RECT  39.552 10.067 49.128 10.307 ;
     RECT  61.632 10.213 62.568 10.499 ;
     RECT  50.544 9.971 60.648 10.981 ;
     RECT  39.552 10.307 49.08 11.077 ;
     RECT  61.8 10.499 62.568 11.077 ;
     RECT  7.68 10.067 38.232 11.317 ;
     RECT  39.36 11.077 49.08 11.605 ;
     RECT  50.112 10.981 60.648 11.605 ;
     RECT  65.424 10.837 65.448 11.699 ;
     RECT  7.68 11.317 38.28 11.797 ;
     RECT  39.36 11.605 60.648 11.797 ;
     RECT  7.68 11.797 60.648 11.939 ;
     RECT  39.36 11.939 60.648 12.035 ;
     RECT  43.104 12.035 60.648 12.277 ;
     RECT  61.8 11.077 62.616 12.277 ;
     RECT  43.104 12.277 62.616 12.371 ;
     RECT  43.104 12.371 47.016 12.419 ;
     RECT  7.68 11.939 38.28 12.563 ;
     RECT  48.288 12.371 62.616 12.803 ;
     RECT  48.288 12.803 62.232 12.899 ;
     RECT  15.936 12.563 38.28 13.091 ;
     RECT  5.76 4.069 6.168 13.093 ;
     RECT  43.632 12.419 47.016 13.187 ;
     RECT  48.288 12.899 60.648 13.187 ;
     RECT  39.36 12.035 42.072 13.235 ;
     RECT  7.68 12.563 14.904 13.621 ;
     RECT  48.288 13.187 48.696 13.715 ;
     RECT  20.88 13.091 38.28 13.717 ;
     RECT  43.632 13.187 46.968 13.957 ;
     RECT  39.552 13.235 42.072 14.003 ;
     RECT  61.8 12.899 62.232 14.147 ;
     RECT  15.936 13.091 19.848 14.149 ;
     RECT  20.88 13.717 38.376 14.149 ;
     RECT  67.2 2.151 67.512 14.197 ;
     RECT  48.48 13.715 48.696 14.291 ;
     RECT  15.936 14.149 38.376 14.485 ;
     RECT  39.552 14.003 41.736 14.485 ;
     RECT  15.936 14.485 41.736 14.531 ;
     RECT  48.528 14.291 48.696 14.677 ;
     RECT  49.728 13.187 60.648 14.677 ;
     RECT  20.88 14.531 41.736 14.771 ;
     RECT  48.528 14.677 60.648 14.819 ;
     RECT  66.672 14.197 67.512 14.819 ;
     RECT  20.88 14.771 38.424 14.867 ;
     RECT  5.76 13.093 6.36 14.869 ;
     RECT  61.8 14.147 62.112 15.013 ;
     RECT  43.248 13.957 46.968 15.253 ;
     RECT  27.12 14.867 38.424 15.347 ;
     RECT  43.008 15.253 46.968 15.395 ;
     RECT  65.184 12.805 65.208 15.445 ;
     RECT  43.92 15.395 46.968 15.539 ;
     RECT  49.728 14.819 60.648 15.731 ;
     RECT  44.064 15.539 46.968 15.971 ;
     RECT  61.632 15.013 62.112 16.019 ;
     RECT  39.552 14.771 41.736 16.067 ;
     RECT  15.936 14.531 19.848 16.213 ;
     RECT  20.88 14.867 25.32 16.213 ;
     RECT  65.184 15.445 65.256 16.259 ;
     RECT  7.584 13.621 14.904 16.309 ;
     RECT  15.936 16.213 25.32 16.309 ;
     RECT  39.792 16.067 41.736 16.405 ;
     RECT  45.504 15.971 46.968 16.405 ;
     RECT  48.528 14.819 48.552 16.405 ;
     RECT  39.792 16.405 41.88 16.501 ;
     RECT  7.584 16.309 25.32 16.835 ;
     RECT  27.12 15.347 27.912 16.837 ;
     RECT  39.792 16.501 41.976 17.125 ;
     RECT  39.792 17.125 42.264 17.269 ;
     RECT  44.064 15.971 44.232 17.509 ;
     RECT  39.696 17.269 42.264 17.603 ;
     RECT  7.584 16.835 25.224 17.651 ;
     RECT  26.448 16.837 27.912 17.653 ;
     RECT  28.896 15.347 38.424 17.653 ;
     RECT  44.064 17.509 44.28 17.797 ;
     RECT  26.448 17.653 38.424 18.275 ;
     RECT  27.888 18.275 38.424 18.373 ;
     RECT  39.696 17.603 41.976 18.373 ;
     RECT  43.488 17.797 44.28 18.421 ;
     RECT  45.504 16.405 48.552 18.421 ;
     RECT  27.888 18.373 41.976 18.563 ;
     RECT  65.184 16.259 65.208 18.565 ;
     RECT  65.088 18.565 65.208 18.611 ;
     RECT  43.488 18.421 48.552 18.613 ;
     RECT  49.728 15.731 59.064 18.613 ;
     RECT  7.584 17.651 14.568 18.757 ;
     RECT  67.2 14.819 67.512 18.757 ;
     RECT  43.488 18.613 59.064 18.853 ;
     RECT  15.696 17.651 25.224 19.187 ;
     RECT  27.888 18.563 38.424 19.669 ;
     RECT  26.448 18.275 26.472 19.717 ;
     RECT  27.552 19.669 38.424 19.717 ;
     RECT  43.104 18.853 59.064 19.909 ;
     RECT  60.096 15.731 60.648 19.909 ;
     RECT  26.448 19.717 38.424 19.955 ;
     RECT  43.056 19.909 60.648 20.099 ;
     RECT  67.056 18.757 67.512 20.099 ;
     RECT  43.056 20.099 44.088 20.579 ;
     RECT  26.448 19.955 36.456 20.581 ;
     RECT  43.056 20.579 43.08 20.771 ;
     RECT  37.968 19.955 38.424 20.869 ;
     RECT  39.792 18.563 41.976 20.869 ;
     RECT  37.968 20.869 41.976 20.917 ;
     RECT  2.4 2.151 2.712 20.965 ;
     RECT  37.968 20.917 42.888 21.107 ;
     RECT  37.968 21.107 41.976 21.155 ;
     RECT  44.4 21.109 44.616 21.347 ;
     RECT  44.4 21.347 44.568 21.635 ;
     RECT  5.76 14.869 6.456 21.637 ;
     RECT  5.04 21.637 6.456 21.925 ;
     RECT  7.44 18.757 14.568 21.925 ;
     RECT  5.04 21.925 14.568 22.117 ;
     RECT  26.208 20.581 36.456 22.213 ;
     RECT  37.968 21.155 40.512 22.213 ;
     RECT  5.04 22.117 14.616 22.259 ;
     RECT  6.336 22.259 14.616 22.261 ;
     RECT  26.208 22.213 40.512 22.405 ;
     RECT  41.952 21.155 41.976 22.405 ;
     RECT  5.04 22.259 5.064 22.451 ;
     RECT  6.336 22.261 14.712 22.453 ;
     RECT  15.696 19.187 25.128 22.453 ;
     RECT  45.6 20.099 60.648 22.453 ;
     RECT  26.208 22.405 41.976 22.547 ;
     RECT  26.208 22.547 40.512 22.691 ;
     RECT  65.088 18.611 65.112 22.693 ;
     RECT  64.944 22.693 65.112 22.741 ;
     RECT  2.4 20.965 3.336 22.835 ;
     RECT  37.872 22.691 40.512 23.123 ;
     RECT  26.208 22.691 36.84 23.555 ;
     RECT  64.944 22.741 65.256 23.555 ;
     RECT  45.12 22.453 60.648 23.989 ;
     RECT  44.976 23.989 60.648 24.037 ;
     RECT  37.968 23.123 40.512 24.085 ;
     RECT  37.392 24.085 40.512 24.277 ;
     RECT  41.952 22.547 41.976 24.277 ;
     RECT  44.592 24.037 60.648 24.325 ;
     RECT  37.392 24.277 41.976 24.419 ;
     RECT  43.872 24.325 60.648 24.467 ;
     RECT  6.336 22.453 25.128 24.613 ;
     RECT  26.208 23.555 36.408 24.661 ;
     RECT  43.296 24.757 43.32 24.805 ;
     RECT  43.2 24.805 43.32 24.853 ;
     RECT  6.336 24.613 25.176 24.899 ;
     RECT  44.592 24.467 60.648 24.899 ;
     RECT  37.968 24.419 41.976 24.947 ;
     RECT  43.104 24.853 43.32 25.091 ;
     RECT  65.232 23.555 65.256 25.139 ;
     RECT  67.2 20.099 67.512 25.285 ;
     RECT  0.192 24.949 0.216 25.331 ;
     RECT  41.952 24.947 41.976 25.333 ;
     RECT  41.952 25.333 42.648 25.523 ;
     RECT  26.208 24.661 36.696 25.669 ;
     RECT  37.968 24.947 40.968 25.669 ;
     RECT  67.104 25.285 67.512 25.715 ;
     RECT  68.832 25.381 68.856 26.005 ;
     RECT  6.336 24.899 25.128 26.197 ;
     RECT  26.208 25.669 40.968 26.197 ;
     RECT  44.784 24.899 60.648 26.197 ;
     RECT  68.832 26.005 68.904 26.627 ;
     RECT  6.336 26.197 40.968 26.723 ;
     RECT  68.88 26.627 68.904 26.723 ;
     RECT  6.336 26.723 40.824 27.155 ;
     RECT  6.336 27.155 40.68 27.251 ;
     RECT  44.016 26.197 60.648 27.299 ;
     RECT  7.584 27.251 40.68 27.779 ;
     RECT  44.784 27.299 60.648 27.875 ;
     RECT  7.68 27.779 40.68 28.451 ;
     RECT  41.952 25.523 41.976 29.123 ;
     RECT  7.8 28.451 40.68 29.125 ;
     RECT  7.8 29.125 40.968 29.555 ;
     RECT  37.44 29.555 40.968 29.653 ;
     RECT  43.104 29.653 43.128 29.701 ;
     RECT  7.8 29.555 36.312 30.035 ;
     RECT  45.024 27.875 60.648 30.275 ;
     RECT  37.44 29.653 41.304 30.853 ;
     RECT  43.104 29.701 43.32 30.901 ;
     RECT  45.024 30.275 60.6 30.901 ;
     RECT  37.44 30.853 41.592 31.141 ;
     RECT  7.8 30.035 10.92 31.379 ;
     RECT  43.104 30.901 60.6 31.381 ;
     RECT  61.8 16.019 62.112 31.381 ;
     RECT  10.56 31.379 10.92 31.477 ;
     RECT  10.56 31.477 10.968 31.811 ;
     RECT  37.44 31.141 41.784 31.909 ;
     RECT  43.104 31.381 62.112 31.909 ;
     RECT  6.336 27.251 6.36 31.955 ;
     RECT  11.952 30.035 36.312 31.957 ;
     RECT  37.44 31.909 62.112 31.957 ;
     RECT  10.56 31.811 10.92 32.291 ;
     RECT  2.4 22.835 2.712 32.409 ;
     RECT  11.952 31.957 62.112 32.409 ;
     RECT  67.2 25.715 67.512 32.409 ;
     RECT  2.4 32.409 2.52 32.423 ;
     RECT  7.8 31.379 9.576 32.423 ;
     RECT  11.952 32.409 61.92 32.423 ;
     RECT  67.2 32.409 67.32 32.423 ;
     RECT  8.736 32.423 9.576 33.683 ;
     RECT  10.56 32.291 10.872 33.683 ;
     RECT  11.952 32.423 61.08 33.683 ;
     RECT  9.552 33.683 9.576 33.731 ;
     RECT  10.56 33.683 10.584 34.163 ;
     RECT  12 33.683 61.08 34.384 ;
     RECT  13.008 0.611 13.152 0.659 ;
     RECT  13.008 0.659 13.296 0.997 ;
     RECT  11.928 0.997 13.296 1.669 ;
     RECT  53.832 1.381 54.912 3.013 ;
     RECT  31.32 1.525 32.832 2.005 ;
     RECT  52.344 1.621 53.808 1.765 ;
     RECT  47.592 1.763 48.624 2.821 ;
     RECT  52.824 1.765 53.808 1.907 ;
     RECT  52.584 1.907 53.808 2.053 ;
     RECT  52.584 2.053 53.616 2.869 ;
     RECT  54.936 2.137 56.4 5.029 ;
     RECT  60.648 2.137 61.8 10.213 ;
     RECT  58.632 2.245 59.76 4.165 ;
     RECT  6.168 4.069 7.68 13.093 ;
     RECT  8.112 5.365 9.312 8.917 ;
     RECT  9.336 5.365 10.368 7.381 ;
     RECT  57.192 6.805 58.416 7.189 ;
     RECT  8.112 8.917 9.216 9.589 ;
     RECT  49.128 9.971 50.544 10.307 ;
     RECT  38.232 10.067 39.552 11.077 ;
     RECT  60.648 10.213 61.632 10.499 ;
     RECT  49.08 10.307 50.544 10.981 ;
     RECT  60.648 10.499 61.8 12.277 ;
     RECT  49.08 10.981 50.112 11.605 ;
     RECT  38.232 11.077 39.36 11.317 ;
     RECT  38.28 11.317 39.36 11.797 ;
     RECT  38.28 11.939 39.36 13.235 ;
     RECT  42.072 12.035 43.104 12.419 ;
     RECT  47.016 12.371 48.288 13.187 ;
     RECT  14.904 12.563 15.936 16.309 ;
     RECT  60.648 12.899 61.8 15.013 ;
     RECT  19.848 13.091 20.88 14.149 ;
     RECT  6.36 13.093 7.68 13.621 ;
     RECT  46.968 13.187 48.288 13.715 ;
     RECT  48.696 13.187 49.728 14.677 ;
     RECT  38.28 13.235 39.552 13.717 ;
     RECT  6.36 13.621 7.584 14.869 ;
     RECT  46.968 13.715 48.48 14.291 ;
     RECT  38.376 13.717 39.552 14.485 ;
     RECT  42.072 13.957 43.248 14.003 ;
     RECT  41.736 14.003 43.248 15.253 ;
     RECT  65.208 14.197 66.672 14.819 ;
     RECT  19.848 14.531 20.88 16.213 ;
     RECT  38.424 14.771 39.552 16.067 ;
     RECT  48.552 14.819 49.728 18.613 ;
     RECT  65.208 14.819 65.256 15.445 ;
     RECT  6.456 14.869 7.584 18.757 ;
     RECT  60.648 15.013 61.632 16.019 ;
     RECT  41.736 15.253 43.008 15.395 ;
     RECT  27.912 15.347 28.896 17.653 ;
     RECT  41.736 15.395 41.976 16.405 ;
     RECT  59.064 15.731 60.096 19.909 ;
     RECT  44.232 15.971 45.504 17.509 ;
     RECT  60.648 16.019 61.8 30.275 ;
     RECT  38.424 16.067 39.792 17.269 ;
     RECT  41.88 16.405 41.976 16.501 ;
     RECT  25.224 16.835 25.32 16.837 ;
     RECT  25.224 16.837 26.448 19.187 ;
     RECT  38.424 17.269 39.696 18.373 ;
     RECT  44.28 17.509 45.504 18.421 ;
     RECT  41.976 17.603 42.264 17.797 ;
     RECT  14.568 17.651 15.696 22.117 ;
     RECT  41.976 17.797 43.488 18.853 ;
     RECT  26.472 18.275 27.888 19.669 ;
     RECT  38.424 18.563 39.792 20.869 ;
     RECT  6.456 18.757 7.44 21.925 ;
     RECT  41.976 18.853 43.104 19.909 ;
     RECT  25.128 19.187 26.448 20.581 ;
     RECT  26.472 19.669 27.552 19.717 ;
     RECT  41.976 19.909 43.056 20.771 ;
     RECT  36.456 19.955 37.968 22.213 ;
     RECT  44.088 20.099 45.6 20.579 ;
     RECT  43.08 20.579 45.6 20.771 ;
     RECT  25.128 20.581 26.208 24.613 ;
     RECT  41.976 20.771 45.6 20.917 ;
     RECT  42.888 20.917 45.6 21.107 ;
     RECT  44.4 21.107 45.6 21.109 ;
     RECT  44.616 21.109 45.6 21.347 ;
     RECT  40.512 21.155 41.952 22.405 ;
     RECT  44.568 21.347 45.6 21.635 ;
     RECT  45.12 21.635 45.6 22.453 ;
     RECT  14.616 22.117 15.696 22.261 ;
     RECT  5.064 22.259 6.336 22.451 ;
     RECT  14.712 22.261 15.696 22.453 ;
     RECT  40.512 22.547 41.952 24.277 ;
     RECT  36.84 22.691 37.872 23.123 ;
     RECT  36.84 23.123 37.968 23.555 ;
     RECT  36.408 23.555 37.968 24.085 ;
     RECT  36.408 24.085 37.392 24.419 ;
     RECT  36.408 24.419 37.968 24.661 ;
     RECT  43.872 24.467 44.592 24.757 ;
     RECT  25.176 24.613 26.208 24.899 ;
     RECT  36.696 24.661 37.968 25.669 ;
     RECT  41.976 24.757 43.296 24.805 ;
     RECT  43.32 24.757 44.592 24.899 ;
     RECT  41.976 24.805 43.2 24.853 ;
     RECT  41.976 24.853 43.104 25.091 ;
     RECT  25.128 24.899 26.208 26.197 ;
     RECT  43.32 24.899 44.784 25.091 ;
     RECT  40.968 24.947 41.952 26.723 ;
     RECT  41.976 25.091 44.784 25.333 ;
     RECT  42.648 25.333 44.784 25.523 ;
     RECT  67.512 25.381 68.832 26.627 ;
     RECT  44.016 25.523 44.784 26.197 ;
     RECT  67.512 26.627 68.88 26.723 ;
     RECT  40.824 26.723 41.952 27.155 ;
     RECT  40.68 27.155 41.952 29.123 ;
     RECT  6.36 27.251 7.584 27.779 ;
     RECT  6.36 27.779 7.68 28.451 ;
     RECT  6.36 28.451 7.8 31.955 ;
     RECT  40.68 29.123 41.304 29.125 ;
     RECT  40.968 29.125 41.304 29.653 ;
     RECT  36.312 29.555 37.44 31.957 ;
     RECT  10.92 30.035 11.952 31.477 ;
     RECT  60.6 30.275 61.8 31.381 ;
     RECT  41.592 30.853 43.104 31.141 ;
     RECT  41.784 31.141 43.104 31.909 ;
     RECT  9.576 31.379 10.56 33.731 ;
     RECT  10.968 31.477 11.952 31.811 ;
     RECT  10.92 31.811 11.952 32.291 ;
     RECT  10.872 32.291 11.952 33.683 ;
     RECT  10.584 33.683 12 34.163 ;
  END
END ot_s81_pq_qb_headw_native
END LIBRARY
